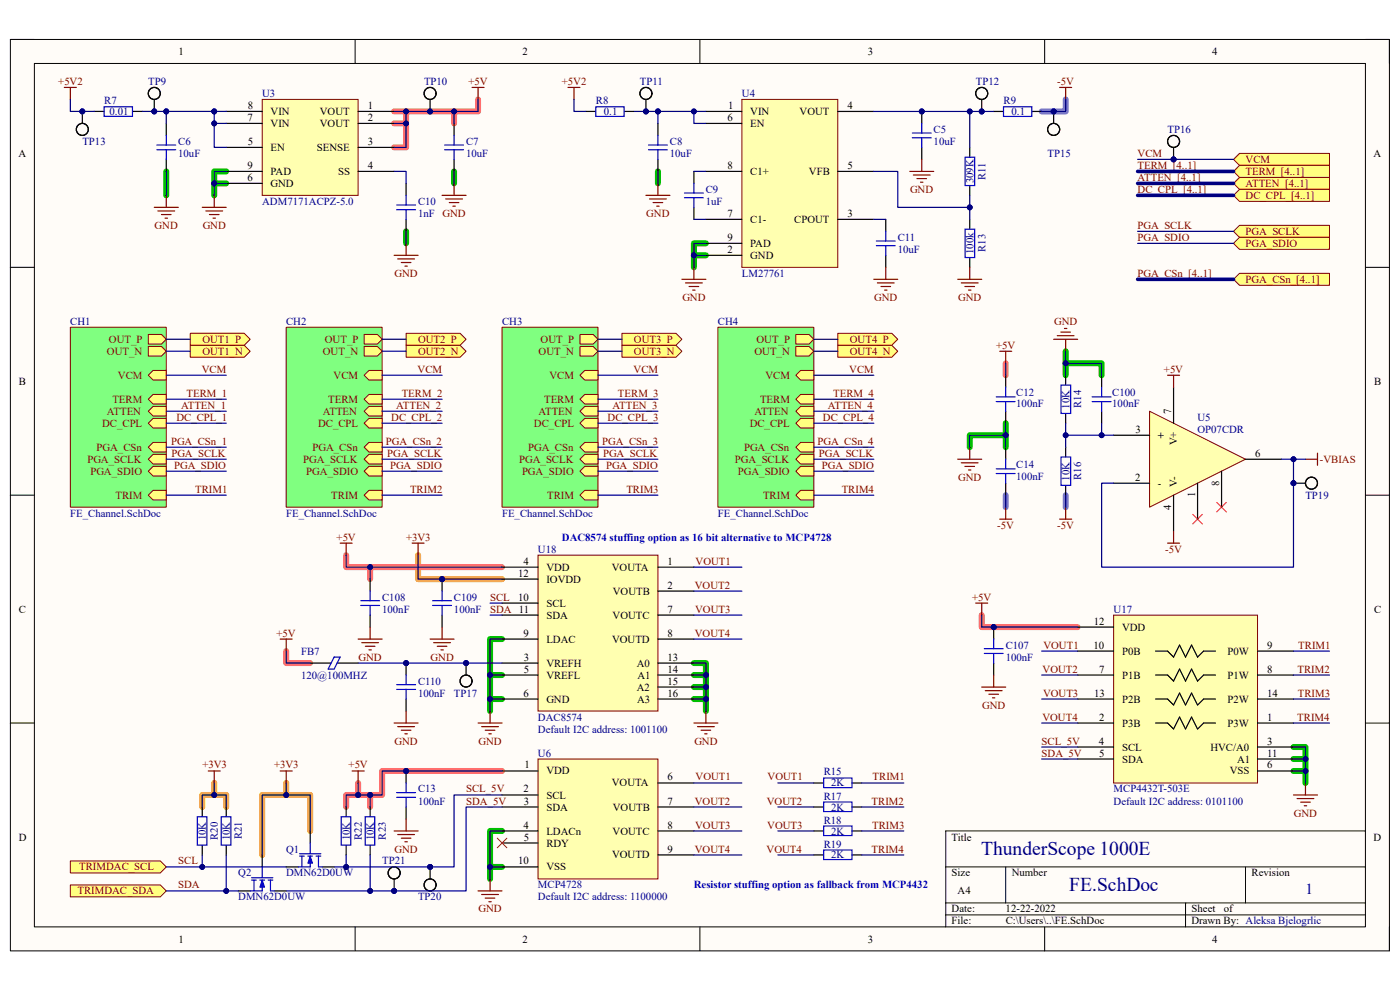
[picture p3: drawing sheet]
<svg xmlns="http://www.w3.org/2000/svg" width="297mm" height="210mm" viewBox="0 0 297 210" stroke-linecap="round" stroke-linejoin="round" font-family="sans-serif">
<defs><g id="words">
<g font-size="4.1" fill="#000080">
<text x="208.2" y="181.5">ThunderScope 1000E</text>
<text x="226.8" y="189.1">FE.SchDoc</text>
</g>
<text font-size="3.2" fill="#000080" x="276.9" y="189.6">1</text>
<g font-size="2.3">
<text x="37.9" y="11.7">1</text>
<text x="110.9" y="11.7">2</text>
<text x="184.1" y="11.7">3</text>
<text x="257.1" y="11.7">4</text>
<text x="52.6" y="23.1">8</text>
<text x="78" y="23.1">1</text>
<text x="154.5" y="23.1">1</text>
<text x="179.8" y="23.1">4</text>
<text x="52.5" y="25.7">7</text>
<text x="57.4" y="24.4">VIN</text>
<text x="57.4" y="26.9">VIN</text>
<text x="67.9" y="24.4">VOUT</text>
<text x="67.9" y="26.9">VOUT</text>
<text x="78" y="25.7">2</text>
<text x="154.3" y="25.7">6</text>
<text x="159.2" y="24.4">VIN</text>
<text x="159.2" y="26.9">EN</text>
<text x="169.6" y="24.4">VOUT</text>
<text x="3.9" y="33.3">A</text>
<text x="52.5" y="35.9">9</text>
<text x="52.6" y="30.7">5</text>
<text x="57.4" y="32">EN</text>
<text x="67.2" y="32">SENSE</text>
<text x="78" y="30.7">3</text>
<text x="78" y="35.9">4</text>
<text x="154.3" y="35.9">8</text>
<text x="179.8" y="35.9">5</text>
<text x="291.4" y="33.3">A</text>
<text x="52.5" y="38.4">6</text>
<text x="57.4" y="39.7">GND</text>
<text x="57.4" y="37.1">PAD</text>
<text x="71.8" y="37.1">SS</text>
<text x="159.2" y="37.1">C1+</text>
<text x="171.6" y="37.1">VFB</text>
<text x="154.3" y="46">7</text>
<text x="159.2" y="47.3">C1-</text>
<text x="168.5" y="47.3">CPOUT</text>
<text x="179.8" y="46">3</text>
<text x="154.3" y="53.6">2</text>
<text x="154.3" y="51.1">9</text>
<text x="159.2" y="52.4">PAD</text>
<text x="159.2" y="54.9">GND</text>
<text x="4" y="81.6">B</text>
<text x="291.5" y="81.6">B</text>
<text x="248.5" y="87.8" transform="rotate(-90 248.5 87.8)">7</text>
<text x="240.9" y="91.8">3</text>
<text x="245.7" y="93.1">+</text>
<text x="249.7" y="94.5" transform="rotate(-90 249.7 94.5)">V+</text>
<text x="240.8" y="102">2</text>
<text x="266.3" y="96.9">6</text>
<text x="245.7" y="103.3">-</text>
<text x="249.7" y="103.3" transform="rotate(-90 249.7 103.3)">V-</text>
<text x="253.6" y="105.4" transform="rotate(-90 253.6 105.4)">1</text>
<text x="258.7" y="103" transform="rotate(-90 258.7 103)">8</text>
<text x="248.5" y="108.2" transform="rotate(-90 248.5 108.2)">4</text>
<text x="111" y="119.8">4</text>
<text x="141.6" y="119.8">1</text>
<text x="109.9" y="122.3">12</text>
<text x="115.9" y="121.1">VDD</text>
<text x="115.9" y="123.6">IOVDD</text>
<text x="129.8" y="121.1">VOUTA</text>
<text x="141.6" y="124.9">2</text>
<text x="4" y="130">C</text>
<text x="109.9" y="127.4">10</text>
<text x="115.9" y="128.7">SCL</text>
<text x="115.9" y="131.2">SDA</text>
<text x="130" y="131.2">VOUTC</text>
<text x="130" y="126.2">VOUTB</text>
<text x="141.6" y="130">7</text>
<text x="291.5" y="130">C</text>
<text x="111" y="135">9</text>
<text x="115.9" y="136.3">LDAC</text>
<text x="129.8" y="136.3">VOUTD</text>
<text x="141.6" y="135">8</text>
<text x="232" y="137.6">10</text>
<text x="232" y="132.5">12</text>
<text x="238" y="133.8">VDD</text>
<text x="268.8" y="137.6">9</text>
<text x="111.1" y="140.1">3</text>
<text x="111.1" y="142.7">5</text>
<text x="115.9" y="141.4">VREFH</text>
<text x="115.9" y="144">VREFL</text>
<text x="135.1" y="141.4">A0</text>
<text x="135.3" y="144">A1</text>
<text x="141.6" y="140.1">13</text>
<text x="141.6" y="142.7">14</text>
<text x="233.2" y="142.7">7</text>
<text x="238" y="138.9">P0B</text>
<text x="238" y="144">P1B</text>
<text x="260.4" y="138.9">P0W</text>
<text x="260.4" y="144">P1W</text>
<text x="268.8" y="142.7">8</text>
<text x="111" y="147.8">6</text>
<text x="115.9" y="149.1">GND</text>
<text x="135.1" y="146.5">A2</text>
<text x="135.2" y="149.1">A3</text>
<text x="141.6" y="145.2">15</text>
<text x="141.6" y="147.8">16</text>
<text x="232.1" y="147.8">13</text>
<text x="238" y="149.1">P2B</text>
<text x="260.4" y="149.1">P2W</text>
<text x="268.8" y="147.8">14</text>
<text x="233.2" y="152.9">2</text>
<text x="238" y="154.1">P3B</text>
<text x="260.4" y="154.1">P3W</text>
<text x="268.8" y="152.9">1</text>
<text x="233.1" y="157.9">4</text>
<text x="233.2" y="160.5">5</text>
<text x="238" y="159.2">SCL</text>
<text x="238" y="161.8">SDA</text>
<text x="256.8" y="159.2">HVC/A0</text>
<text x="262.5" y="161.8">A1</text>
<text x="268.8" y="157.9">3</text>
<text x="268.8" y="160.5">11</text>
<text x="111.3" y="163">1</text>
<text x="115.9" y="164.3">VDD</text>
<text x="129.8" y="166.8">VOUTA</text>
<text x="141.6" y="165.6">6</text>
<text x="260.9" y="164.3">VSS</text>
<text x="268.8" y="163">6</text>
<text x="111" y="168.1">2</text>
<text x="111.1" y="170.7">3</text>
<text x="115.9" y="169.4">SCL</text>
<text x="115.9" y="172">SDA</text>
<text x="130" y="172">VOUTB</text>
<text x="141.6" y="170.7">7</text>
<text x="4" y="178.3">D</text>
<text x="111" y="175.8">4</text>
<text x="111.1" y="178.3">5</text>
<text x="115.9" y="177">LDACn</text>
<text x="115.9" y="179.6">RDY</text>
<text x="130" y="177">VOUTC</text>
<text x="141.6" y="175.8">8</text>
<text x="201.9" y="178.3">Title</text>
<text x="291.4" y="178.3">D</text>
<text x="109.9" y="183.4">10</text>
<text x="115.9" y="184.7">VSS</text>
<text x="129.8" y="182.1">VOUTD</text>
<text x="141.6" y="180.8">9</text>
<text x="201.9" y="185.9">Size</text>
<text x="214.6" y="185.9">Number</text>
<text x="265.5" y="185.9">Revision</text>
<text x="203.2" y="189.7">A4</text>
<text x="201.9" y="193.5">Date:</text>
<text x="201.9" y="196.1">File:</text>
<text x="213.3" y="193.5">12-22-2022</text>
<text x="213.4" y="196.1">C:\Users\..\FE.SchDoc</text>
<text x="252.8" y="196.1">Drawn By: Aleksa Bjelogrlic</text>
<text x="252.8" y="193.5">Sheet</text>
<text x="259.6" y="193.5">of</text>
<text x="37.9" y="199.9">1</text>
<text x="110.9" y="199.9">2</text>
<text x="184.1" y="199.9">3</text>
<text x="257.1" y="199.9">4</text>
</g>
<g font-size="2.3" fill="#800000">
<text x="12.4" y="18">+5V2</text>
<text x="99.4" y="18">+5V</text>
<text x="119.2" y="18">+5V2</text>
<text x="224.3" y="18">-5V</text>
<text x="241.3" y="33.3">VCM</text>
<text x="241.3" y="35.9">TERM_[4..1]</text>
<text x="264.2" y="34.6">VCM</text>
<text x="193.1" y="40.9">GND</text>
<text x="241.3" y="38.4">ATTEN_[4..1]</text>
<text x="241.3" y="40.9">DC_CPL_[4..1]</text>
<text x="264.2" y="39.7">ATTEN_[4..1]</text>
<text x="264.2" y="37.1">TERM_[4..1]</text>
<text x="93.9" y="46">GND</text>
<text x="137.1" y="46">GND</text>
<text x="264.2" y="42.2">DC_CPL_[4..1]</text>
<text x="32.8" y="48.6">GND</text>
<text x="43" y="48.6">GND</text>
<text x="241.3" y="48.6">PGA_SCLK</text>
<text x="241.3" y="51.1">PGA_SDIO</text>
<text x="264.2" y="49.8">PGA_SCLK</text>
<text x="264.2" y="52.4">PGA_SDIO</text>
<text x="83.7" y="58.7">GND</text>
<text x="241.3" y="58.7">PGA_CSn_[4..1]</text>
<text x="264.2" y="60">PGA_CSn_[4..1]</text>
<text x="144.8" y="63.8">GND</text>
<text x="185.5" y="63.8">GND</text>
<text x="203.3" y="63.8">GND</text>
<text x="223.6" y="68.9">GND</text>
<text x="22.7" y="75.3">OUT_N</text>
<text x="23.1" y="72.7">OUT_P</text>
<text x="42.9" y="75.3">OUT1_N</text>
<text x="42.9" y="72.7">OUT1_P</text>
<text x="68.5" y="75.3">OUT_N</text>
<text x="68.9" y="72.7">OUT_P</text>
<text x="88.7" y="75.3">OUT2_N</text>
<text x="88.7" y="72.7">OUT2_P</text>
<text x="114.3" y="75.3">OUT_N</text>
<text x="114.7" y="72.7">OUT_P</text>
<text x="134.5" y="75.3">OUT3_N</text>
<text x="134.5" y="72.7">OUT3_P</text>
<text x="160.1" y="75.3">OUT_N</text>
<text x="160.5" y="72.7">OUT_P</text>
<text x="180.3" y="75.3">OUT4_N</text>
<text x="180.3" y="72.7">OUT4_P</text>
<text x="211.3" y="74">+5V</text>
<text x="25" y="80.3">VCM</text>
<text x="42.8" y="79.1">VCM</text>
<text x="70.8" y="80.3">VCM</text>
<text x="88.6" y="79.1">VCM</text>
<text x="116.6" y="80.3">VCM</text>
<text x="134.4" y="79.1">VCM</text>
<text x="162.4" y="80.3">VCM</text>
<text x="180.2" y="79.1">VCM</text>
<text x="246.9" y="79.1">+5V</text>
<text x="22.7" y="88">ATTEN</text>
<text x="23.8" y="85.4">TERM</text>
<text x="37.4" y="89.3">DC_CPL_1</text>
<text x="38.4" y="86.7">ATTEN_1</text>
<text x="39.6" y="84.2">TERM_1</text>
<text x="68.5" y="88">ATTEN</text>
<text x="69.6" y="85.4">TERM</text>
<text x="83" y="89.3">DC_CPL_2</text>
<text x="84.1" y="86.7">ATTEN_2</text>
<text x="85.2" y="84.2">TERM_2</text>
<text x="114.3" y="88">ATTEN</text>
<text x="115.4" y="85.4">TERM</text>
<text x="128.9" y="89.3">DC_CPL_3</text>
<text x="130" y="86.7">ATTEN_3</text>
<text x="131.1" y="84.2">TERM_3</text>
<text x="160.1" y="88">ATTEN</text>
<text x="161.2" y="85.4">TERM</text>
<text x="174.6" y="89.3">DC_CPL_4</text>
<text x="175.6" y="86.7">ATTEN_4</text>
<text x="176.8" y="84.2">TERM_4</text>
<text x="20.5" y="95.6">PGA_CSn</text>
<text x="21.7" y="90.6">DC_CPL</text>
<text x="36.3" y="94.4">PGA_CSn_1</text>
<text x="66.3" y="95.6">PGA_CSn</text>
<text x="67.5" y="90.6">DC_CPL</text>
<text x="81.9" y="94.4">PGA_CSn_2</text>
<text x="112.1" y="95.6">PGA_CSn</text>
<text x="113.3" y="90.6">DC_CPL</text>
<text x="127.8" y="94.4">PGA_CSn_3</text>
<text x="157.9" y="95.6">PGA_CSn</text>
<text x="159" y="90.6">DC_CPL</text>
<text x="173.4" y="94.4">PGA_CSn_4</text>
<text x="18.5" y="98.2">PGA_SCLK</text>
<text x="19.2" y="100.7">PGA_SDIO</text>
<text x="36.4" y="96.9">PGA_SCLK</text>
<text x="37" y="99.4">PGA_SDIO</text>
<text x="64.3" y="98.2">PGA_SCLK</text>
<text x="65" y="100.7">PGA_SDIO</text>
<text x="82.2" y="96.9">PGA_SCLK</text>
<text x="82.8" y="99.4">PGA_SDIO</text>
<text x="110.2" y="98.2">PGA_SCLK</text>
<text x="110.7" y="100.7">PGA_SDIO</text>
<text x="127.9" y="96.9">PGA_SCLK</text>
<text x="128.6" y="99.4">PGA_SDIO</text>
<text x="155.9" y="98.2">PGA_SCLK</text>
<text x="156.5" y="100.7">PGA_SDIO</text>
<text x="173.7" y="96.9">PGA_SCLK</text>
<text x="174.4" y="99.4">PGA_SDIO</text>
<text x="203.3" y="102">GND</text>
<text x="280" y="98.2">-VBIAS</text>
<text x="24.5" y="105.8">TRIM</text>
<text x="41.4" y="104.5">TRIM1</text>
<text x="70.3" y="105.8">TRIM</text>
<text x="87" y="104.5">TRIM2</text>
<text x="116.1" y="105.8">TRIM</text>
<text x="132.9" y="104.5">TRIM3</text>
<text x="161.9" y="105.8">TRIM</text>
<text x="178.6" y="104.5">TRIM4</text>
<text x="211.6" y="112.1">-5V</text>
<text x="224.3" y="112.1">-5V</text>
<text x="71.4" y="114.7">+5V</text>
<text x="86.1" y="114.7">+3V3</text>
<text x="147.6" y="119.8">VOUT1</text>
<text x="247.2" y="117.3">-5V</text>
<text x="147.4" y="124.9">VOUT2</text>
<text x="104" y="127.4">SCL</text>
<text x="104" y="130">SDA 11</text>
<text x="147.5" y="130">VOUT3</text>
<text x="206.2" y="127.4">+5V</text>
<text x="58.7" y="135">+5V</text>
<text x="147.4" y="135">VOUT4</text>
<text x="221.4" y="137.6">VOUT1</text>
<text x="275.4" y="137.6">TRIM1</text>
<text x="76.1" y="140.1">GND</text>
<text x="91.4" y="140.1">GND</text>
<text x="221.2" y="142.7">VOUT2</text>
<text x="275.3" y="142.7">TRIM2</text>
<text x="221.3" y="147.8">VOUT3</text>
<text x="275.3" y="147.8">TRIM3</text>
<text x="208.4" y="150.3">GND</text>
<text x="221.1" y="152.9">VOUT4</text>
<text x="275.2" y="152.9">TRIM4</text>
<text x="83.7" y="157.9">GND</text>
<text x="101.5" y="157.9">GND</text>
<text x="147.3" y="157.9">GND</text>
<text x="221" y="157.9">SCL_5V</text>
<text x="221" y="160.5">SDA_5V</text>
<text x="42.9" y="163">+3V3</text>
<text x="58.2" y="163">+3V3</text>
<text x="74" y="163">+5V</text>
<text x="147.6" y="165.6">VOUT1</text>
<text x="162.9" y="165.6">VOUT1</text>
<text x="185.1" y="165.6">TRIM1</text>
<text x="98.9" y="168.1">SCL_5V</text>
<text x="98.9" y="170.7">SDA_5V</text>
<text x="147.4" y="170.7">VOUT2</text>
<text x="162.7" y="170.7">VOUT2</text>
<text x="184.9" y="170.7">TRIM2</text>
<text x="274.5" y="173.2">GND</text>
<text x="147.5" y="175.8">VOUT3</text>
<text x="162.8" y="175.8">VOUT3</text>
<text x="185" y="175.8">TRIM3</text>
<text x="16.8" y="184.7">TRIMDAC_SCL</text>
<text x="37.8" y="183.4">SCL</text>
<text x="83.7" y="180.8">GND</text>
<text x="147.4" y="180.8">VOUT4</text>
<text x="162.6" y="180.8">VOUT4</text>
<text x="184.9" y="180.8">TRIM4</text>
<text x="16.4" y="189.7">TRIMDAC_SDA</text>
<text x="37.8" y="188.5">SDA</text>
<text x="101.5" y="193.5">GND</text>
</g>
<g font-size="2.3" fill="#000080">
<text x="22.1" y="22.1">R7</text>
<text x="31.5" y="18">TP9</text>
<text x="55.6" y="20.6">U3</text>
<text x="90" y="18">TP10</text>
<text x="126.4" y="22.1">R8</text>
<text x="135.8" y="18">TP11</text>
<text x="157.4" y="20.6">U4</text>
<text x="207" y="18">TP12</text>
<text x="212.9" y="22.1">R9</text>
<text x="23.2" y="24.4">0.01</text>
<text x="128.1" y="24.4">0.1</text>
<text x="198.1" y="28.2">C5</text>
<text x="214.6" y="24.4">0.1</text>
<text x="247.7" y="28.2">TP16</text>
<text x="17.5" y="30.7">TP13</text>
<text x="37.8" y="30.7">C6</text>
<text x="37.8" y="33.3">10uF</text>
<text x="98.9" y="30.7">C7</text>
<text x="98.9" y="33.3">10uF</text>
<text x="142.1" y="30.7">C8</text>
<text x="142.1" y="33.3">10uF</text>
<text x="198.1" y="30.7">10uF</text>
<text x="222.2" y="33.3">TP15</text>
<text x="149.7" y="40.9">C9</text>
<text x="206.5" y="38.9" transform="rotate(-90 206.5 38.9)">309K</text>
<text x="209" y="38.1" transform="rotate(-90 209 38.1)">R11</text>
<text x="55.6" y="43.5">ADM7171ACPZ-5.0</text>
<text x="88.7" y="43.5">C10</text>
<text x="88.7" y="46">1nF</text>
<text x="149.7" y="43.5">1uF</text>
<text x="190.5" y="51.1">C11</text>
<text x="190.5" y="53.6">10uF</text>
<text x="206.5" y="53.9" transform="rotate(-90 206.5 53.9)">100k</text>
<text x="209" y="53.4" transform="rotate(-90 209 53.4)">R13</text>
<text x="157.4" y="58.7">LM27761</text>
<text x="14.9" y="68.9">CH1</text>
<text x="60.7" y="68.9">CH2</text>
<text x="106.5" y="68.9">CH3</text>
<text x="152.3" y="68.9">CH4</text>
<text x="215.6" y="83.9">C12</text>
<text x="236" y="83.9">C100</text>
<text x="215.6" y="86.4">100nF</text>
<text x="226.9" y="86.7" transform="rotate(-90 226.9 86.7)">10K</text>
<text x="229.4" y="86.6" transform="rotate(-90 229.4 86.6)">R14</text>
<text x="236" y="86.4">100nF</text>
<text x="254" y="89.3">U5</text>
<text x="254" y="91.8">OP07CDR</text>
<text x="215.6" y="99.2">C14</text>
<text x="215.6" y="101.7">100nF</text>
<text x="226.9" y="101.9" transform="rotate(-90 226.9 101.9)">10K</text>
<text x="229.4" y="101.8" transform="rotate(-90 229.4 101.8)">R16</text>
<text x="276.9" y="105.8">TP19</text>
<text x="14.9" y="109.6">FE_Channel.SchDoc</text>
<text x="60.7" y="109.6">FE_Channel.SchDoc</text>
<text x="106.5" y="109.6">FE_Channel.SchDoc</text>
<text x="152.3" y="109.6">FE_Channel.SchDoc</text>
<text x="114.1" y="117.3">U18</text>
<text x="81.1" y="127.4">C108</text>
<text x="81.1" y="130">100nF</text>
<text x="96.3" y="127.4">C109</text>
<text x="96.3" y="130">100nF</text>
<text x="236.3" y="130">U17</text>
<text x="213.4" y="137.6">C107</text>
<text x="63.9" y="138.9">FB7</text>
<text x="63.9" y="144">120@100MHZ</text>
<text x="213.4" y="140.1">100nF</text>
<text x="88.7" y="145.2">C110</text>
<text x="88.7" y="147.8">100nF</text>
<text x="96.3" y="147.8">TP17</text>
<text x="114.1" y="152.9">DAC8574</text>
<text x="114.1" y="155.4">Default I2C address: 1001100</text>
<text x="114.1" y="160.5">U6</text>
<text x="174.8" y="164.5">R15</text>
<text x="176.3" y="166.8">2K</text>
<text x="88.7" y="168.1">C13</text>
<text x="88.7" y="170.7">100nF</text>
<text x="174.8" y="169.6">R17</text>
<text x="176.3" y="172">2K</text>
<text x="236.3" y="168.1">MCP4432T-503E</text>
<text x="236.3" y="170.7">Default I2C address: 0101100</text>
<text x="43.7" y="178.3" transform="rotate(-90 43.7 178.3)">10K</text>
<text x="46.2" y="178.1" transform="rotate(-90 46.2 178.1)">R20</text>
<text x="48.8" y="178.3" transform="rotate(-90 48.8 178.3)">10K</text>
<text x="51.3" y="178.1" transform="rotate(-90 51.3 178.1)">R21</text>
<text x="74.2" y="178.3" transform="rotate(-90 74.2 178.3)">10K</text>
<text x="76.8" y="178.1" transform="rotate(-90 76.8 178.1)">R22</text>
<text x="79.3" y="178.3" transform="rotate(-90 79.3 178.3)">10K</text>
<text x="81.8" y="178.1" transform="rotate(-90 81.8 178.1)">R23</text>
<text x="174.8" y="174.7">R18</text>
<text x="174.8" y="179.8">R19</text>
<text x="176.3" y="177">2K</text>
<text x="50.5" y="185.9">Q2</text>
<text x="60.7" y="180.8">Q1</text>
<text x="60.7" y="185.9">DMN62D0UW</text>
<text x="81.1" y="183.4">TP21</text>
<text x="176.3" y="182.1">2K</text>
<text x="50.5" y="191">DMN62D0UW</text>
<text x="88.7" y="191">TP20</text>
<text x="114.1" y="188.5">MCP4728</text>
<text x="114.1" y="191">Default I2C address: 1100000</text>
</g>
<g font-size="2.3" fill="#00f">
<text x="119.2" y="114.7">DAC8574 stuffing option as 16 bit alternative to MCP4728</text>
<text x="147.2" y="188.5">Resistor stuffing option as fallback from MCP4432</text>
</g>
</g></defs>
<path d="M2.2 8.4h292.6v193.3h-292.6z" fill-rule="evenodd" fill="#fffcf8"/>
<path d="M2.2 8.4h292.6v193.3h-292.6z" fill="none" stroke="#000" stroke-width=".21"/>
<path d="M7.3 13.5h282.4v183.1h-282.4z" fill-rule="evenodd" fill="#fffcf8"/>
<g fill="none" stroke="#000" stroke-width=".21">
<path d="M2.2 8.4h5.1M7.3 13.5h282.4v183.1h-282.4zM75.3 8.4v5.1M148.5 8.4v5.1M221.6 8.4v5.1M289.7 8.4h5.1v5.1M2.2 56.7h5.1M289.7 56.7h5.1M2.2 105h5.1M289.7 105.1h5.1M2.2 153.4h5.1M289.7 153.4h5.1"/>
<path d="M289.7 176.3h-89.1v20.3M75.3 196.6v5.1M148.5 196.6v5.1M200.6 183.9h89.1M200.6 191.5h89.1M200.6 194.1h89.1M213.4 183.9v7.6M221.6 196.6v5.1M251.5 191.5v5.1M264.2 183.9v7.6M294.8 196.6v5.1"/>
</g>
<g fill="none" stroke="#00be00" stroke-width="1.3">
<path d="M35.3 36.4v5M45.5 38.9h2.5M48 36.4h-2.5v5M96.3 36.4v2.5M139.6 36.4v2.5M86.2 49.1v2.5M147.2 54.2v2.5M149.8 51.6h-2.6v2.6h2.6M226.1 74.5v5.1M226.1 77.1h7.6v2.5M213.4 92.3h-7.7v2.6M213.4 89.8v5.1"/>
<path d="M106.5 135.6h-2.5v12.7M104 143.2h2.5M106.5 148.3h-2.5v2.5M147.2 140.7h2.6v10.1M147.2 143.2h2.6M147.2 145.7h2.6M147.2 148.3h2.6M274.4 158.5h2.6v5.1M106.5 176.3h-2.5v7.6M274.4 163.6h2.6v2.5M274.4 161h2.6M106.5 183.9h-2.5v2.6"/>
</g>
<path d="M88.7 117.8v5.1h17.8M45.5 168.6h-2.6v2.6M45.5 166.1v2.5h2.5v2.6M60.7 166.1v2.5M65.8 176.3v-7.7h-10.2v12.8" fill="none" stroke="#f90" stroke-width="1.3"/>
<path d="M83.6 23.6h2.6v2.6h-2.6M86.2 23.6h10.1v2.6M86.2 26.2v5.1h-2.6M101.4 21.1v2.5h-5.1M213.4 77.1v2.5M73.4 117.8v2.5h5.1M60.7 138.1v2.6h5.1M106.5 120.3h-28v2.6M208.3 130.5v2.5h20.3M76 168.6h-2.6v2.6M76 166.1v2.5h2.5v2.6M106.5 163.6h-25.4v5h-2.6" fill="none" stroke="#ff6e6e" stroke-width="1.3"/>
<path d="M226.1 21.1v2.5h-5.1M213.4 105.1v2.5M226.1 105.1v2.5" fill="none" stroke="#6e6eff" stroke-width="1.3"/>
<path d="M14.9 69.4h20.4v38.2h-20.4z" fill-rule="evenodd" fill="#80ff80"/>
<path d="M14.9 69.4h20.4v38.2h-20.4z" fill="none" stroke="#800000" stroke-width=".21"/>
<path d="M31.5 71h2.8l1 1-1 1h-2.8z" fill-rule="evenodd" fill="#ffff80"/>
<path d="M31.5 71h2.8l1 1-1 1h-2.8z" fill="none" stroke="#800000" stroke-width=".21"/>
<path d="M31.5 79.6l1-1h2.8v2h-2.8z" fill-rule="evenodd" fill="#ffff80"/>
<path d="M31.5 79.6l1-1h2.8v2h-2.8z" fill="none" stroke="#800000" stroke-width=".21"/>
<path d="M31.5 73.5h2.8l1 1-1 1h-2.8z" fill-rule="evenodd" fill="#ffff80"/>
<path d="M31.5 73.5h2.8l1 1-1 1h-2.8z" fill="none" stroke="#800000" stroke-width=".21"/>
<path d="M31.5 105l1-1h2.8v2.1h-2.8z" fill-rule="evenodd" fill="#ffff80"/>
<path d="M31.5 105l1-1h2.8v2.1h-2.8z" fill="none" stroke="#800000" stroke-width=".21"/>
<path d="M32.5 86.2h2.8v2.1h-2.8l-1-1.1z" fill-rule="evenodd" fill="#ffff80"/>
<path d="M32.5 86.2h2.8v2.1h-2.8l-1-1.1z" fill="none" stroke="#800000" stroke-width=".21"/>
<path d="M31.5 89.8l1-1h2.8v2h-2.8z" fill-rule="evenodd" fill="#ffff80"/>
<path d="M31.5 89.8l1-1h2.8v2h-2.8z" fill="none" stroke="#800000" stroke-width=".21"/>
<path d="M31.5 94.9l1-1h2.8v2h-2.8z" fill-rule="evenodd" fill="#ffff80"/>
<path d="M31.5 94.9l1-1h2.8v2h-2.8z" fill="none" stroke="#800000" stroke-width=".21"/>
<path d="M32.5 96.4h2.8v2h-2.8l-1-1z" fill-rule="evenodd" fill="#ffff80"/>
<path d="M32.5 96.4h2.8v2h-2.8l-1-1z" fill="none" stroke="#800000" stroke-width=".21"/>
<path d="M32.5 98.9h2.8v2.1h-2.8l-1-1z" fill-rule="evenodd" fill="#ffff80"/>
<path d="M32.5 98.9h2.8v2.1h-2.8l-1-1z" fill="none" stroke="#800000" stroke-width=".21"/>
<path d="M31.5 84.7l1-1h2.8v2h-2.8z" fill-rule="evenodd" fill="#ffff80"/>
<path d="M31.5 84.7l1-1h2.8v2h-2.8z" fill="none" stroke="#800000" stroke-width=".21"/>
<circle cx="86.2" cy="163.6" r=".51" fill="#000080"/>
<circle cx="86.2" cy="163.6" r=".51" fill="none" stroke="#000080" stroke-width=".21"/>
<path d="M86.2 163.6v2.5M86.2 171.2v2.5" fill="none" stroke="#000" stroke-width=".25"/>
<circle cx="86.2" cy="163.6" r=".51" fill="#000080"/>
<circle cx="86.2" cy="163.6" r=".51" fill="none" stroke="#000080" stroke-width=".21"/>
<path d="M65.8 178.8v2.3M84.2 169.1h4M84.2 168.1h4M86.2 166.1v2M86.2 169.1v2.1M63.6 181.1h4.5M63.6 181.6h1M64.1 181.6v2.3M65.3 181.6h1M65.8 181.6v2.3h-2.5M67.1 181.6h1M67.6 181.6v2.3" fill="none" stroke="#00f" stroke-width=".25"/>
<path d="M83.6 176.3h5.1M84.4 177h3.5M85.1 177.8h2.1M85.9 178.6h.5M86.2 173.7v2.6M101.4 189h5.1M102.2 189.8h3.5M102.9 190.5h2.1M103.7 191.3h.5M104 186.5v2.5" fill="none" stroke="#800000" stroke-width=".25"/>
<path d="M65.8 176.3v2.5M60.7 183.9h2.6M68.3 183.9h2.6" fill="none" stroke="#000" stroke-width=".25"/>
<path d="M65.8 181.6l.5 1.5h-1z" fill="#00f"/>
<path d="M65.8 181.6l.5 1.5h-1z" fill="none" stroke="#00f" stroke-width=".21"/>
<path d="M53.4 186.2h4.5M53.4 186.7h1M53.9 186.7v2.3M55.1 186.7h1M55.6 183.9v2.3M55.6 186.7v2.3h-2.5M56.9 186.7h1M57.4 186.7v2.3M67.6 183.9h.7" fill="none" stroke="#00f" stroke-width=".25"/>
<path d="M50.5 189h2.6M55.6 181.4v2.5M58.2 189h2.5" fill="none" stroke="#000" stroke-width=".25"/>
<path d="M55.6 186.7l.5 1.5h-1z" fill="#00f"/>
<path d="M55.6 186.7l.5 1.5h-1z" fill="none" stroke="#00f" stroke-width=".21"/>
<path d="M41.9 173.3h2v6h-2zM46.9 173.3h2.1v6h-2.1zM72.4 173.3h2v6h-2zM77.5 173.3h2v6h-2zM57.4 189h.8" fill="none" stroke="#00f" stroke-width=".25"/>
<path d="M42.9 171.2v2M42.9 179.4v2M48 171.2v2M48 179.4v2M73.4 171.2v2M73.4 179.4v2M78.5 171.2v2M78.5 179.4v2" fill="none" stroke="#000" stroke-width=".25"/>
<path d="M44.2 163.6h2.5M45.5 163.6v2.5M59.4 163.6h2.6M60.7 163.6v2.5" fill="none" stroke="#800000" stroke-width=".25"/>
<path d="M14.9 182.6h19.1l1.3 1.3-1.3 1.3h-19.1z" fill-rule="evenodd" fill="#ffff80"/>
<path d="M14.9 182.6h19.1l1.3 1.3-1.3 1.3h-19.1z" fill="none" stroke="#800000" stroke-width=".21"/>
<path d="M14.9 187.7h19.1l1.3 1.3-1.3 1.3h-19.1z" fill-rule="evenodd" fill="#ffff80"/>
<path d="M14.9 187.7h19.1l1.3 1.3-1.3 1.3h-19.1z" fill="none" stroke="#800000" stroke-width=".21"/>
<path d="M243.9 87.2l20.3 10.2-20.3 10.2z" fill="#ffffb0"/>
<path d="M243.9 87.2l20.3 10.2-20.3 10.2z" fill="none" stroke="#800000" stroke-width=".21"/>
<path d="M226.1 79.6v2M226.1 87.8v2M226.1 94.9v2M236.3 92.3h7.6M249 82.1v7.7M259.2 100v7.6M264.2 97.4h7.7M226.1 103v2.1M236.3 102.5h7.6M249 105.1v7.6M254.1 102.5v7.6" fill="none" stroke="#000" stroke-width=".25"/>
<path d="M253 109.1l2.1 2.1M255.1 109.1l-2.1 2.1M258.1 106.6l2.1 2M260.2 106.6l-2.1 2" fill="none" stroke="#f00" stroke-width=".21"/>
<path d="M225.1 81.7h2v6h-2zM225.1 97h2v6h-2z" fill="none" stroke="#00f" stroke-width=".25"/>
<path d="M277 97.4h2.5M279.5 96.1v2.6" fill="none" stroke="#800000" stroke-width=".25"/>
<path d="M114.1 161h25.5v25.5h-25.5z" fill-rule="evenodd" fill="#ffffb0"/>
<path d="M114.1 161h25.5v25.5h-25.5z" fill="none" stroke="#800000" stroke-width=".21"/>
<path d="M106.5 163.6h7.6M106.5 168.6h7.6M106.5 171.2h7.6M106.5 176.3h7.6M106.5 178.8h7.6M139.6 171.2h7.6M139.6 166.1h7.6M139.6 176.3h7.6M106.5 183.9h7.6M139.6 181.4h7.6" fill="none" stroke="#000" stroke-width=".25"/>
<path d="M105.5 177.8l2 2M107.5 177.8l-2 2" fill="none" stroke="#f00" stroke-width=".21"/>
<path d="M261.7 38.9l1.3-1.3h19v2.6h-19z" fill-rule="evenodd" fill="#ffff80"/>
<path d="M261.7 38.9l1.3-1.3h19v2.6h-19z" fill="none" stroke="#800000" stroke-width=".21"/>
<path d="M263 40.2h19v2.5h-19l-1.3-1.3z" fill-rule="evenodd" fill="#ffff80"/>
<path d="M263 40.2h19v2.5h-19l-1.3-1.3z" fill="none" stroke="#800000" stroke-width=".21"/>
<path d="M263 47.8h19v2.6h-19l-1.3-1.3z" fill-rule="evenodd" fill="#ffff80"/>
<path d="M263 47.8h19v2.6h-19l-1.3-1.3z" fill="none" stroke="#800000" stroke-width=".21"/>
<path d="M261.7 51.6l1.3-1.2h19v2.5h-19z" fill-rule="evenodd" fill="#ffff80"/>
<path d="M261.7 51.6l1.3-1.2h19v2.5h-19z" fill="none" stroke="#800000" stroke-width=".21"/>
<path d="M263 58h19v2.5h-19l-1.3-1.2z" fill-rule="evenodd" fill="#ffff80"/>
<path d="M263 58h19v2.5h-19l-1.3-1.2z" fill="none" stroke="#800000" stroke-width=".21"/>
<path d="M263 32.5h19v2.6h-19l-1.3-1.3z" fill-rule="evenodd" fill="#ffff80"/>
<path d="M263 32.5h19v2.6h-19l-1.3-1.3z" fill="none" stroke="#800000" stroke-width=".21"/>
<path d="M40.4 73.2h11.4l1.3 1.3-1.3 1.3h-11.4z" fill-rule="evenodd" fill="#ffff80"/>
<path d="M40.4 73.2h11.4l1.3 1.3-1.3 1.3h-11.4z" fill="none" stroke="#800000" stroke-width=".21"/>
<path d="M40.4 70.7h11.4l1.3 1.3-1.3 1.2h-11.4z" fill-rule="evenodd" fill="#ffff80"/>
<path d="M40.4 70.7h11.4l1.3 1.3-1.3 1.2h-11.4z" fill="none" stroke="#800000" stroke-width=".21"/>
<path d="M86.2 73.2h11.4l1.3 1.3-1.3 1.3h-11.4z" fill-rule="evenodd" fill="#ffff80"/>
<path d="M86.2 73.2h11.4l1.3 1.3-1.3 1.3h-11.4z" fill="none" stroke="#800000" stroke-width=".21"/>
<path d="M86.2 70.7h11.4l1.3 1.3-1.3 1.2h-11.4z" fill-rule="evenodd" fill="#ffff80"/>
<path d="M86.2 70.7h11.4l1.3 1.3-1.3 1.2h-11.4z" fill="none" stroke="#800000" stroke-width=".21"/>
<path d="M131.9 73.2h11.5l1.3 1.3-1.3 1.3h-11.5z" fill-rule="evenodd" fill="#ffff80"/>
<path d="M131.9 73.2h11.5l1.3 1.3-1.3 1.3h-11.5z" fill="none" stroke="#800000" stroke-width=".21"/>
<path d="M131.9 70.7h11.5l1.3 1.3-1.3 1.2h-11.5z" fill-rule="evenodd" fill="#ffff80"/>
<path d="M131.9 70.7h11.5l1.3 1.3-1.3 1.2h-11.5z" fill="none" stroke="#800000" stroke-width=".21"/>
<path d="M177.7 73.2h11.5l1.3 1.3-1.3 1.3h-11.5z" fill-rule="evenodd" fill="#ffff80"/>
<path d="M177.7 73.2h11.5l1.3 1.3-1.3 1.3h-11.5z" fill="none" stroke="#800000" stroke-width=".21"/>
<path d="M177.7 70.7h11.5l1.3 1.3-1.3 1.2h-11.5z" fill-rule="evenodd" fill="#ffff80"/>
<path d="M177.7 70.7h11.5l1.3 1.3-1.3 1.2h-11.5z" fill="none" stroke="#800000" stroke-width=".21"/>
<path d="M157.4 21.1h20.3v35.6h-20.3z" fill-rule="evenodd" fill="#ffffb0"/>
<path d="M157.4 21.1h20.3v35.6h-20.3z" fill="none" stroke="#800000" stroke-width=".21"/>
<g fill="none" stroke="#000" stroke-width=".25">
<path d="M139.6 26.2v2.5M139.6 33.8v2.6M147.2 36.4v2.5M149.8 23.6h7.6M149.8 36.4h7.6M149.8 26.2h7.6M177.7 23.6h7.7M177.7 36.4h7.7M205.7 31.3v2M205.7 39.4v2M147.2 44v2.5M149.8 54.2h7.6"/>
<path d="M149.8 46.5h7.6M149.8 51.6h7.6M177.7 46.5h7.7M187.9 46.5v2.6M187.9 54.2v2.5M205.7 46.5v2M205.7 54.7v2"/>
</g>
<g fill="none" stroke="#00f" stroke-width=".25">
<path d="M137.6 31.8h4M137.6 30.8h4M139.6 28.7v2.1M139.6 31.8v2M147.2 38.9v2M204.7 33.4h2.1v6h-2.1zM145.2 41.9h4M145.2 40.9h4M147.2 41.9v2.1M185.9 52.1h4M185.9 51.1h4M187.9 49.1v2"/>
<path d="M187.9 52.1v2.1M204.7 48.6h2.1v6h-2.1z"/>
</g>
<g fill="none" stroke="#800000" stroke-width=".25">
<path d="M120.5 18.5h2.5M121.8 18.5v2.6M139.6 38.9v2.5M137 41.4h5.1M137.8 42.2h3.6M138.6 43h2M139.3 43.7h.5M144.7 59.3h5.1M147.2 56.7v2.6M185.4 59.3h5.1M187.9 56.7v2.6M203.2 59.3h5.1"/>
<path d="M205.7 56.7v2.6M145.4 60h3.6M146.2 60.8h2M147 61.5h.5M186.1 60h3.6M186.9 60.8h2M187.7 61.5h.5M203.9 60h3.6M204.7 60.8h2M205.5 61.5h.5"/>
</g>
<circle cx="195.5" cy="23.6" r=".51" fill="#000080"/>
<circle cx="195.5" cy="23.6" r=".51" fill="none" stroke="#000080" stroke-width=".21"/>
<path d="M195.5 23.6v2.6M195.5 31.3v2.5" fill="none" stroke="#000" stroke-width=".25"/>
<circle cx="195.5" cy="23.6" r=".51" fill="#000080"/>
<circle cx="195.5" cy="23.6" r=".51" fill="none" stroke="#000080" stroke-width=".21"/>
<path d="M193.5 29.2h4M193.5 28.2h4M195.5 26.2v2M195.5 29.2v2.1M212.9 22.7h6v2h-6z" fill="none" stroke="#00f" stroke-width=".25"/>
<path d="M224.8 18.6h2.6M226.1 18.6v2.5M193 36.4h5.1M193.8 37.1h3.5M194.5 37.9h2.1M195.3 38.7h.5M195.5 33.8v2.6" fill="none" stroke="#800000" stroke-width=".25"/>
<path d="M210.8 23.6h2M219 23.6h2" fill="none" stroke="#000" stroke-width=".25"/>
<path d="M55.6 21.1h20.4v20.3h-20.4z" fill-rule="evenodd" fill="#ffffb0"/>
<path d="M55.6 21.1h20.4v20.3h-20.4z" fill="none" stroke="#800000" stroke-width=".21"/>
<g fill="none" stroke="#000" stroke-width=".25">
<path d="M20 23.6h2M28.2 23.6h2M35.3 26.2v2.5M35.3 33.8v2.6M48 23.6h7.6M48 26.2h7.6M48 31.3h7.6M48 38.9h7.6M48 36.4h7.6M76 23.6h7.6M76 26.2h7.6M76 31.3h7.6"/>
<path d="M76 36.4h7.6M86.2 38.9v2.5M96.3 26.2v2.5M96.3 33.8v2.6M124.3 23.6h2M132.5 23.6h2M86.2 46.5v2.6"/>
</g>
<g fill="none" stroke="#800000" stroke-width=".25">
<path d="M13.6 18.5h2.6M14.9 18.5v2.6M100.1 18.5h2.6M101.4 18.5v2.6M96.3 38.9v2.5M32.7 44h5.1M33.5 44.8h3.6M34.3 45.5h2M35 46.3h.5M35.3 41.4v2.6M42.9 44h5.1M43.7 44.8h3.5"/>
<path d="M44.4 45.5h2.1M45.2 46.3h.5M45.5 41.4v2.6M83.6 54.2h5.1M84.4 54.9h3.5M85.1 55.7h2.1M85.9 56.5h.5M86.2 51.6v2.6M93.8 41.4h5.1M94.6 42.2h3.5M95.3 43h2.1M96.1 43.7h.5"/>
</g>
<g fill="none" stroke="#00f" stroke-width=".25">
<path d="M22.1 22.7h6v2h-6zM33.3 31.8h4M33.3 30.8h4M35.3 28.7v2.1M35.3 31.8v2M94.3 31.8h4M94.3 30.8h4M96.3 28.7v2.1M96.3 31.8v2M126.4 22.7h6v2h-6zM84.2 44.5h4M84.2 43.5h4"/>
<path d="M86.2 41.4v2.1M86.2 44.5v2"/>
</g>
<circle cx="17.5" cy="23.6" r=".51" fill="#000080"/>
<circle cx="17.5" cy="23.6" r=".51" fill="none" stroke="#000080" stroke-width=".21"/>
<path d="M17.5 23.6v2.6" fill="none" stroke="#000" stroke-width=".25"/>
<circle cx="17.5" cy="23.6" r=".51" fill="#000080"/>
<circle cx="17.5" cy="23.6" r=".51" fill="none" stroke="#000080" stroke-width=".21"/>
<circle cx="17.5" cy="27.5" r="1.27" fill="none" stroke="#000" stroke-width=".25"/>
<circle cx="32.7" cy="23.6" r=".51" fill="#000080"/>
<circle cx="32.7" cy="23.6" r=".51" fill="none" stroke="#000080" stroke-width=".21"/>
<path d="M32.7 21.1v2.5" fill="none" stroke="#000" stroke-width=".25"/>
<circle cx="32.7" cy="23.6" r=".51" fill="#000080"/>
<circle cx="32.7" cy="23.6" r=".51" fill="none" stroke="#000080" stroke-width=".21"/>
<circle cx="32.7" cy="19.8" r="1.27" fill="none" stroke="#000" stroke-width=".25"/>
<circle cx="137" cy="23.6" r=".51" fill="#000080"/>
<circle cx="137" cy="23.6" r=".51" fill="none" stroke="#000080" stroke-width=".21"/>
<path d="M137 21.1v2.5" fill="none" stroke="#000" stroke-width=".25"/>
<circle cx="137" cy="23.6" r=".51" fill="#000080"/>
<circle cx="137" cy="23.6" r=".51" fill="none" stroke="#000080" stroke-width=".21"/>
<circle cx="137" cy="19.8" r="1.27" fill="none" stroke="#000" stroke-width=".25"/>
<circle cx="208.3" cy="23.6" r=".51" fill="#000080"/>
<circle cx="208.3" cy="23.6" r=".51" fill="none" stroke="#000080" stroke-width=".21"/>
<path d="M208.3 21.1v2.5" fill="none" stroke="#000" stroke-width=".25"/>
<circle cx="208.3" cy="23.6" r=".51" fill="#000080"/>
<circle cx="208.3" cy="23.6" r=".51" fill="none" stroke="#000080" stroke-width=".21"/>
<circle cx="208.3" cy="19.8" r="1.27" fill="none" stroke="#000" stroke-width=".25"/>
<circle cx="223.5" cy="23.6" r=".51" fill="#000080"/>
<circle cx="223.5" cy="23.6" r=".51" fill="none" stroke="#000080" stroke-width=".21"/>
<path d="M223.5 23.6v2.6" fill="none" stroke="#000" stroke-width=".25"/>
<circle cx="223.5" cy="23.6" r=".51" fill="#000080"/>
<circle cx="223.5" cy="23.6" r=".51" fill="none" stroke="#000080" stroke-width=".21"/>
<circle cx="223.5" cy="27.5" r="1.27" fill="none" stroke="#000" stroke-width=".25"/>
<circle cx="274.4" cy="102.5" r=".51" fill="#000080"/>
<circle cx="274.4" cy="102.5" r=".51" fill="none" stroke="#000080" stroke-width=".21"/>
<path d="M274.4 102.5h2.6" fill="none" stroke="#000" stroke-width=".25"/>
<circle cx="274.4" cy="102.5" r=".51" fill="#000080"/>
<circle cx="274.4" cy="102.5" r=".51" fill="none" stroke="#000080" stroke-width=".21"/>
<circle cx="278.2" cy="102.5" r="1.27" fill="none" stroke="#000" stroke-width=".25"/>
<circle cx="249" cy="33.8" r=".51" fill="#000080"/>
<circle cx="249" cy="33.8" r=".51" fill="none" stroke="#000080" stroke-width=".21"/>
<path d="M249 31.3v2.5" fill="none" stroke="#000" stroke-width=".25"/>
<circle cx="249" cy="33.8" r=".51" fill="#000080"/>
<circle cx="249" cy="33.8" r=".51" fill="none" stroke="#000080" stroke-width=".21"/>
<circle cx="249" cy="30" r="1.27" fill="none" stroke="#000" stroke-width=".25"/>
<circle cx="91.2" cy="183.9" r=".51" fill="#000080"/>
<circle cx="91.2" cy="183.9" r=".51" fill="none" stroke="#000080" stroke-width=".21"/>
<path d="M91.2 183.9v2.6" fill="none" stroke="#000" stroke-width=".25"/>
<circle cx="91.2" cy="183.9" r=".51" fill="#000080"/>
<circle cx="91.2" cy="183.9" r=".51" fill="none" stroke="#000080" stroke-width=".21"/>
<circle cx="91.2" cy="187.7" r="1.27" fill="none" stroke="#000" stroke-width=".25"/>
<circle cx="83.6" cy="189" r=".51" fill="#000080"/>
<circle cx="83.6" cy="189" r=".51" fill="none" stroke="#000080" stroke-width=".21"/>
<path d="M83.6 186.5v2.5" fill="none" stroke="#000" stroke-width=".25"/>
<circle cx="83.6" cy="189" r=".51" fill="#000080"/>
<circle cx="83.6" cy="189" r=".51" fill="none" stroke="#000080" stroke-width=".21"/>
<circle cx="83.6" cy="185.2" r="1.27" fill="none" stroke="#000" stroke-width=".25"/>
<circle cx="91.2" cy="23.6" r=".51" fill="#000080"/>
<circle cx="91.2" cy="23.6" r=".51" fill="none" stroke="#000080" stroke-width=".21"/>
<path d="M91.2 21.1v2.5" fill="none" stroke="#000" stroke-width=".25"/>
<circle cx="91.2" cy="23.6" r=".51" fill="#000080"/>
<circle cx="91.2" cy="23.6" r=".51" fill="none" stroke="#000080" stroke-width=".21"/>
<g fill="none" stroke="#000" stroke-width=".25">
<path d="M213.4 79.6v2.5M213.4 87.2v2.6M213.4 94.9v2.5M213.4 102.5v2.6"/>
<circle cx="91.2" cy="19.8" r="1.27"/>
</g>
<path d="M211.3 99.5h4.1M211.3 84.2h4.1M211.3 85.2h4.1M213.4 82.1v2.1M213.4 85.2v2M213.4 97.4v2.1M211.3 100.5h4.1M213.4 100.5v2" fill="none" stroke="#00f" stroke-width=".25"/>
<g fill="none" stroke="#800000" stroke-width=".25">
<path d="M212.1 74.5h2.5M213.4 74.5v2.6M247.7 79.6h2.5M249 79.6v2.5M203.2 97.4h5.1M203.9 98.2h3.6M204.7 98.9h2M205.5 99.7h.5M205.7 94.9v2.5M212.1 110.1h2.5M213.4 107.6v2.5M224.8 110.1h2.6"/>
<path d="M226.1 107.6v2.5M247.7 115.2h2.5M249 112.7v2.5M74.7 163.6h2.6M76 163.6v2.5"/>
</g>
<path d="M60.7 69.4h20.4v38.2h-20.4z" fill-rule="evenodd" fill="#80ff80"/>
<path d="M60.7 69.4h20.4v38.2h-20.4z" fill="none" stroke="#800000" stroke-width=".21"/>
<path d="M77.3 71h2.7l1.1 1-1.1 1h-2.7z" fill-rule="evenodd" fill="#ffff80"/>
<path d="M77.3 71h2.7l1.1 1-1.1 1h-2.7z" fill="none" stroke="#800000" stroke-width=".21"/>
<path d="M77.3 79.6l1-1h2.8v2h-2.8z" fill-rule="evenodd" fill="#ffff80"/>
<path d="M77.3 79.6l1-1h2.8v2h-2.8z" fill="none" stroke="#800000" stroke-width=".21"/>
<path d="M77.3 73.5h2.7l1.1 1-1.1 1h-2.7z" fill-rule="evenodd" fill="#ffff80"/>
<path d="M77.3 73.5h2.7l1.1 1-1.1 1h-2.7z" fill="none" stroke="#800000" stroke-width=".21"/>
<path d="M77.3 105l1-1h2.8v2.1h-2.8z" fill-rule="evenodd" fill="#ffff80"/>
<path d="M77.3 105l1-1h2.8v2.1h-2.8z" fill="none" stroke="#800000" stroke-width=".21"/>
<path d="M78.3 86.2h2.8v2.1h-2.8l-1-1.1z" fill-rule="evenodd" fill="#ffff80"/>
<path d="M78.3 86.2h2.8v2.1h-2.8l-1-1.1z" fill="none" stroke="#800000" stroke-width=".21"/>
<path d="M77.3 89.8l1-1h2.8v2h-2.8z" fill-rule="evenodd" fill="#ffff80"/>
<path d="M77.3 89.8l1-1h2.8v2h-2.8z" fill="none" stroke="#800000" stroke-width=".21"/>
<path d="M77.3 94.9l1-1h2.8v2h-2.8z" fill-rule="evenodd" fill="#ffff80"/>
<path d="M77.3 94.9l1-1h2.8v2h-2.8z" fill="none" stroke="#800000" stroke-width=".21"/>
<path d="M78.3 96.4h2.8v2h-2.8l-1-1z" fill-rule="evenodd" fill="#ffff80"/>
<path d="M78.3 96.4h2.8v2h-2.8l-1-1z" fill="none" stroke="#800000" stroke-width=".21"/>
<path d="M78.3 98.9h2.8v2.1h-2.8l-1-1z" fill-rule="evenodd" fill="#ffff80"/>
<path d="M78.3 98.9h2.8v2.1h-2.8l-1-1z" fill="none" stroke="#800000" stroke-width=".21"/>
<path d="M77.3 84.7l1-1h2.8v2h-2.8z" fill-rule="evenodd" fill="#ffff80"/>
<path d="M77.3 84.7l1-1h2.8v2h-2.8z" fill="none" stroke="#800000" stroke-width=".21"/>
<path d="M106.5 69.4h20.4v38.2h-20.4z" fill-rule="evenodd" fill="#80ff80"/>
<path d="M106.5 69.4h20.4v38.2h-20.4z" fill="none" stroke="#800000" stroke-width=".21"/>
<path d="M123 71h2.8l1.1 1-1.1 1h-2.8z" fill-rule="evenodd" fill="#ffff80"/>
<path d="M123 71h2.8l1.1 1-1.1 1h-2.8z" fill="none" stroke="#800000" stroke-width=".21"/>
<path d="M123 79.6l1.1-1h2.8v2h-2.8z" fill-rule="evenodd" fill="#ffff80"/>
<path d="M123 79.6l1.1-1h2.8v2h-2.8z" fill="none" stroke="#800000" stroke-width=".21"/>
<path d="M123 73.5h2.8l1.1 1-1.1 1h-2.8z" fill-rule="evenodd" fill="#ffff80"/>
<path d="M123 73.5h2.8l1.1 1-1.1 1h-2.8z" fill="none" stroke="#800000" stroke-width=".21"/>
<path d="M123 105l1.1-1h2.8v2.1h-2.8z" fill-rule="evenodd" fill="#ffff80"/>
<path d="M123 105l1.1-1h2.8v2.1h-2.8z" fill="none" stroke="#800000" stroke-width=".21"/>
<path d="M124.1 86.2h2.8v2.1h-2.8l-1.1-1.1z" fill-rule="evenodd" fill="#ffff80"/>
<path d="M124.1 86.2h2.8v2.1h-2.8l-1.1-1.1z" fill="none" stroke="#800000" stroke-width=".21"/>
<path d="M123 89.8l1.1-1h2.8v2h-2.8z" fill-rule="evenodd" fill="#ffff80"/>
<path d="M123 89.8l1.1-1h2.8v2h-2.8z" fill="none" stroke="#800000" stroke-width=".21"/>
<path d="M123 94.9l1.1-1h2.8v2h-2.8z" fill-rule="evenodd" fill="#ffff80"/>
<path d="M123 94.9l1.1-1h2.8v2h-2.8z" fill="none" stroke="#800000" stroke-width=".21"/>
<path d="M124.1 96.4h2.8v2h-2.8l-1.1-1z" fill-rule="evenodd" fill="#ffff80"/>
<path d="M124.1 96.4h2.8v2h-2.8l-1.1-1z" fill="none" stroke="#800000" stroke-width=".21"/>
<path d="M123 100l1.1-1.1h2.8v2.1h-2.8z" fill-rule="evenodd" fill="#ffff80"/>
<path d="M123 100l1.1-1.1h2.8v2.1h-2.8z" fill="none" stroke="#800000" stroke-width=".21"/>
<path d="M123 84.7l1.1-1h2.8v2h-2.8z" fill-rule="evenodd" fill="#ffff80"/>
<path d="M123 84.7l1.1-1h2.8v2h-2.8z" fill="none" stroke="#800000" stroke-width=".21"/>
<path d="M152.3 69.4h20.4v38.2h-20.4z" fill-rule="evenodd" fill="#80ff80"/>
<path d="M152.3 69.4h20.4v38.2h-20.4z" fill="none" stroke="#800000" stroke-width=".21"/>
<path d="M168.8 71h2.8l1.1 1-1.1 1h-2.8z" fill-rule="evenodd" fill="#ffff80"/>
<path d="M168.8 71h2.8l1.1 1-1.1 1h-2.8z" fill="none" stroke="#800000" stroke-width=".21"/>
<path d="M168.8 79.6l1.1-1h2.8v2h-2.8z" fill-rule="evenodd" fill="#ffff80"/>
<path d="M168.8 79.6l1.1-1h2.8v2h-2.8z" fill="none" stroke="#800000" stroke-width=".21"/>
<path d="M168.8 73.5h2.8l1.1 1-1.1 1h-2.8z" fill-rule="evenodd" fill="#ffff80"/>
<path d="M168.8 73.5h2.8l1.1 1-1.1 1h-2.8z" fill="none" stroke="#800000" stroke-width=".21"/>
<path d="M168.8 105l1.1-1h2.8v2.1h-2.8z" fill-rule="evenodd" fill="#ffff80"/>
<path d="M168.8 105l1.1-1h2.8v2.1h-2.8z" fill="none" stroke="#800000" stroke-width=".21"/>
<path d="M169.9 86.2h2.8v2.1h-2.8l-1.1-1.1z" fill-rule="evenodd" fill="#ffff80"/>
<path d="M169.9 86.2h2.8v2.1h-2.8l-1.1-1.1z" fill="none" stroke="#800000" stroke-width=".21"/>
<path d="M168.8 89.8l1.1-1h2.8v2h-2.8z" fill-rule="evenodd" fill="#ffff80"/>
<path d="M168.8 89.8l1.1-1h2.8v2h-2.8z" fill="none" stroke="#800000" stroke-width=".21"/>
<path d="M168.8 94.9l1.1-1h2.8v2h-2.8z" fill-rule="evenodd" fill="#ffff80"/>
<path d="M168.8 94.9l1.1-1h2.8v2h-2.8z" fill="none" stroke="#800000" stroke-width=".21"/>
<path d="M169.9 96.4h2.8v2h-2.8l-1.1-1z" fill-rule="evenodd" fill="#ffff80"/>
<path d="M169.9 96.4h2.8v2h-2.8l-1.1-1z" fill="none" stroke="#800000" stroke-width=".21"/>
<path d="M169.9 98.9h2.8v2.1h-2.8l-1.1-1z" fill-rule="evenodd" fill="#ffff80"/>
<path d="M169.9 98.9h2.8v2.1h-2.8l-1.1-1z" fill="none" stroke="#800000" stroke-width=".21"/>
<path d="M168.8 84.7l1.1-1h2.8v2h-2.8z" fill-rule="evenodd" fill="#ffff80"/>
<path d="M168.8 84.7l1.1-1h2.8v2h-2.8z" fill="none" stroke="#800000" stroke-width=".21"/>
<path d="M263 35.1h19v2.5h-19l-1.3-1.2z" fill-rule="evenodd" fill="#ffff80"/>
<path d="M263 35.1h19v2.5h-19l-1.3-1.2z" fill="none" stroke="#800000" stroke-width=".21"/>
<path d="M223.5 72h5.1M224.3 71.2h3.6M225.1 70.5h2M225.8 69.7h.5M226.1 72v2.5" fill="none" stroke="#800000" stroke-width=".25"/>
<path d="M233.7 79.6v2.5M233.7 87.2v2.6" fill="none" stroke="#000" stroke-width=".25"/>
<path d="M231.7 84.2h4M231.7 85.2h4M233.7 82.1v2.1M233.7 85.2v2" fill="none" stroke="#00f" stroke-width=".25"/>
<path d="M236.3 130.5h30.5v35.6h-30.5z" fill-rule="evenodd" fill="#ffffb0"/>
<path d="M236.3 130.5h30.5v35.6h-30.5z" fill="none" stroke="#800000" stroke-width=".21"/>
<g fill="none" stroke="#000" stroke-width=".25">
<path d="M228.6 133h7.7M228.6 138.1h7.7M245.2 138.1h2.5l1.3 1.3 1.2-2.6 1.3 2.6 1.3-2.6 1.3 2.6 1.2-1.3h2.6M266.8 138.1h7.6M228.6 158.5h7.7M228.6 143.2h7.7M228.6 148.3h7.7M228.6 153.4h7.7M245.2 143.2h2.5l1.3 1.3 1.2-2.6 1.3 2.6 1.3-2.6 1.3 2.6 1.2-1.3h2.6M245.2 148.3h2.5l1.3 1.3 1.2-2.6 1.3 2.6 1.3-2.6 1.3 2.6 1.2-1.3h2.6M245.2 153.4h2.5l1.3 1.3 1.2-2.6 1.3 2.6 1.3-2.6 1.3 2.6 1.2-1.3h2.6M266.8 158.5h7.6"/>
<path d="M266.8 143.2h7.6M266.8 148.3h7.6M266.8 153.4h7.6M172.7 166.1h2M172.7 171.2h2M172.7 176.3h2M180.8 166.1h2M180.8 171.2h2M180.8 176.3h2M228.6 161h7.7M266.8 161h7.6M266.8 163.6h7.6"/>
<path d="M172.7 181.4h2M180.8 181.4h2"/>
</g>
<path d="M174.7 165h6v2.1h-6zM174.7 170.1h6v2.1h-6zM174.7 175.2h6v2.1h-6zM174.7 180.3h6v2h-6z" fill="none" stroke="#00f" stroke-width=".25"/>
<path d="M274.4 168.6h5.1M275.2 169.4h3.5M275.9 170.2h2.1M276.7 170.9h.5M277 166.1v2.5" fill="none" stroke="#800000" stroke-width=".25"/>
<circle cx="210.8" cy="133" r=".51" fill="#000080"/>
<circle cx="210.8" cy="133" r=".51" fill="none" stroke="#000080" stroke-width=".21"/>
<path d="M210.8 133v2.6M210.8 140.7v2.5" fill="none" stroke="#000" stroke-width=".25"/>
<circle cx="210.8" cy="133" r=".51" fill="#000080"/>
<circle cx="210.8" cy="133" r=".51" fill="none" stroke="#000080" stroke-width=".21"/>
<path d="M208.8 138.6h4M208.8 137.6h4M210.8 135.6v2M210.8 138.6v2.1" fill="none" stroke="#00f" stroke-width=".25"/>
<path d="M207 127.9h2.5M208.3 127.9v2.6M208.3 145.8h5.1M209 146.5h3.6M209.8 147.3h2M210.6 148h.5M210.8 143.2v2.6" fill="none" stroke="#800000" stroke-width=".25"/>
<path d="M114.1 117.8h25.5v33h-25.5z" fill-rule="evenodd" fill="#ffffb0"/>
<path d="M114.1 117.8h25.5v33h-25.5z" fill="none" stroke="#800000" stroke-width=".21"/>
<g fill="none" stroke="#000" stroke-width=".25">
<path d="M106.5 120.3h7.6M106.5 127.9h7.6M106.5 130.5h7.6M106.5 135.6h7.6M106.5 122.9h7.6M139.6 120.3h7.6M139.6 130.5h7.6M139.6 135.6h7.6M139.6 125.4h7.6M65.8 140.7h4.5M71.5 140.7h4.5M106.5 148.3h7.6"/>
<path d="M106.5 140.7h7.6M106.5 143.2h7.6M139.6 148.3h7.6M139.6 140.7h7.6M139.6 143.2h7.6M139.6 145.7h7.6"/>
</g>
<path d="M87.4 115.2h2.6M88.7 115.2v2.6M101.4 153.4h5.1M102.2 154.1h3.5M102.9 154.9h2.1M103.7 155.7h.5M104 150.8v2.6M147.2 153.4h5.1M148 154.1h3.5M148.7 154.9h2.1M149.5 155.7h.5M149.8 150.8v2.6" fill="none" stroke="#800000" stroke-width=".25"/>
<path d="M70.9 139.4h1.3l-1.3 2.5h-1.3z" fill="none" stroke="#00f" stroke-width=".25"/>
<circle cx="86.2" cy="140.7" r=".51" fill="#000080"/>
<circle cx="86.2" cy="140.7" r=".51" fill="none" stroke="#000080" stroke-width=".21"/>
<path d="M86.2 140.7v2.5M86.2 148.3v2.5" fill="none" stroke="#000" stroke-width=".25"/>
<circle cx="86.2" cy="140.7" r=".51" fill="#000080"/>
<circle cx="86.2" cy="140.7" r=".51" fill="none" stroke="#000080" stroke-width=".21"/>
<path d="M84.2 146.3h4M84.2 145.2h4M86.2 143.2v2M86.2 146.3v2" fill="none" stroke="#00f" stroke-width=".25"/>
<path d="M83.6 153.4h5.1M84.4 154.1h3.5M85.1 154.9h2.1M85.9 155.7h.5M86.2 150.8v2.6" fill="none" stroke="#800000" stroke-width=".25"/>
<circle cx="93.8" cy="122.9" r=".51" fill="#000080"/>
<circle cx="93.8" cy="122.9" r=".51" fill="none" stroke="#000080" stroke-width=".21"/>
<path d="M93.8 122.9v2.5M93.8 130.5v2.5" fill="none" stroke="#000" stroke-width=".25"/>
<circle cx="93.8" cy="122.9" r=".51" fill="#000080"/>
<circle cx="93.8" cy="122.9" r=".51" fill="none" stroke="#000080" stroke-width=".21"/>
<path d="M76.5 128.4h4M76.5 127.4h4M78.5 125.4v2M78.5 128.4v2.1M91.8 128.4h4M91.8 127.4h4M93.8 125.4v2M93.8 128.4v2.1" fill="none" stroke="#00f" stroke-width=".25"/>
<g fill="none" stroke="#800000" stroke-width=".25">
<path d="M72.2 115.2h2.5M73.4 115.2v2.6M59.4 135.6h2.6M60.7 135.6v2.5M76 135.6h5.1M76.7 136.3h3.6M77.5 137.1h2M78.3 137.9h.5M78.5 133v2.6M91.2 135.6h5.1M92 136.3h3.6M92.8 137.1h2"/>
<path d="M93.5 137.9h.5M93.8 133v2.6"/>
</g>
<path d="M78.5 122.9v2.5M78.5 130.5v2.5" fill="none" stroke="#000" stroke-width=".25"/>
<path d="M226.1 74.5v5.1" fill="none" stroke="#000080" stroke-width=".25"/>
<circle cx="226.1" cy="77.1" r=".51" fill="#000080"/>
<circle cx="226.1" cy="77.1" r=".51" fill="none" stroke="#000080" stroke-width=".21"/>
<path d="M45.5 168.6h-2.6v2.6" fill="none" stroke="#000080" stroke-width=".25"/>
<circle cx="45.4" cy="168.6" r=".51" fill="#000080"/>
<circle cx="45.4" cy="168.6" r=".51" fill="none" stroke="#000080" stroke-width=".21"/>
<path d="M45.5 166.1v2.5h2.5v2.6" fill="none" stroke="#000080" stroke-width=".25"/>
<circle cx="45.4" cy="168.6" r=".51" fill="#000080"/>
<circle cx="45.4" cy="168.6" r=".51" fill="none" stroke="#000080" stroke-width=".21"/>
<path d="M76 168.6h-2.6v2.6" fill="none" stroke="#000080" stroke-width=".25"/>
<circle cx="76" cy="168.6" r=".51" fill="#000080"/>
<circle cx="76" cy="168.6" r=".51" fill="none" stroke="#000080" stroke-width=".21"/>
<path d="M106.5 183.9h-2.5v2.6" fill="none" stroke="#000080" stroke-width=".25"/>
<circle cx="104" cy="183.9" r=".51" fill="#000080"/>
<circle cx="104" cy="183.9" r=".51" fill="none" stroke="#000080" stroke-width=".21"/>
<path d="M226.1 92.3h10.2" fill="none" stroke="#000080" stroke-width=".25"/>
<circle cx="226.1" cy="92.3" r=".51" fill="#000080"/>
<circle cx="226.1" cy="92.3" r=".51" fill="none" stroke="#000080" stroke-width=".21"/>
<circle cx="233.7" cy="92.3" r=".51" fill="#000080"/>
<circle cx="233.7" cy="92.3" r=".51" fill="none" stroke="#000080" stroke-width=".21"/>
<path d="M271.9 97.4h2.5v22.9h-40.7v-17.8h2.6" fill="none" stroke="#000080" stroke-width=".25"/>
<circle cx="274.4" cy="97.4" r=".51" fill="#000080"/>
<circle cx="274.4" cy="97.4" r=".51" fill="none" stroke="#000080" stroke-width=".21"/>
<circle cx="274.4" cy="102.5" r=".51" fill="#000080"/>
<circle cx="274.4" cy="102.5" r=".51" fill="none" stroke="#000080" stroke-width=".21"/>
<path d="M226.1 105.1v2.5M106.5 176.3h-2.5v7.6" fill="none" stroke="#000080" stroke-width=".25"/>
<circle cx="104" cy="183.9" r=".51" fill="#000080"/>
<circle cx="104" cy="183.9" r=".51" fill="none" stroke="#000080" stroke-width=".21"/>
<g fill="none" stroke="#000080" stroke-width=".25">
<path d="M241.3 33.8h20.4M241.3 49.1h20.4M241.3 51.6h20.4M35.3 79.6h12.7M35.3 72h5.1M35.3 74.5h5.1M81.1 72h5.1M81.1 74.5h5.1M81.1 79.6h12.7M126.9 79.6h12.7M126.9 72h5M126.9 74.5h5"/>
<path d="M172.7 79.6h12.7M172.7 72h5M172.7 74.5h5M35.3 105h12.7"/>
</g>
<circle cx="249" cy="33.8" r=".51" fill="#000080"/>
<circle cx="249" cy="33.8" r=".51" fill="none" stroke="#000080" stroke-width=".21"/>
<path d="M226.1 89.8v5.1" fill="none" stroke="#000080" stroke-width=".25"/>
<circle cx="226.1" cy="92.3" r=".51" fill="#000080"/>
<circle cx="226.1" cy="92.3" r=".51" fill="none" stroke="#000080" stroke-width=".21"/>
<path d="M149.8 51.6h-2.6v2.6h2.6" fill="none" stroke="#000080" stroke-width=".25"/>
<circle cx="147.2" cy="54.2" r=".51" fill="#000080"/>
<circle cx="147.2" cy="54.2" r=".51" fill="none" stroke="#000080" stroke-width=".21"/>
<path d="M147.2 36.4h2.6M185.4 36.4h5.1v7.6h15.2v2.5M147.2 46.5h2.6M185.4 46.5h2.5" fill="none" stroke="#000080" stroke-width=".25"/>
<circle cx="205.7" cy="44" r=".51" fill="#000080"/>
<circle cx="205.7" cy="44" r=".51" fill="none" stroke="#000080" stroke-width=".21"/>
<path d="M226.1 21.1v2.5h-5.1" fill="none" stroke="#000080" stroke-width=".25"/>
<circle cx="223.5" cy="23.6" r=".51" fill="#000080"/>
<circle cx="223.5" cy="23.6" r=".51" fill="none" stroke="#000080" stroke-width=".21"/>
<path d="M139.6 23.6v2.6M139.6 36.4v2.5" fill="none" stroke="#000080" stroke-width=".25"/>
<circle cx="139.6" cy="23.6" r=".51" fill="#000080"/>
<circle cx="139.6" cy="23.6" r=".51" fill="none" stroke="#000080" stroke-width=".21"/>
<path d="M147.2 54.2v2.5" fill="none" stroke="#000080" stroke-width=".25"/>
<circle cx="147.2" cy="54.2" r=".51" fill="#000080"/>
<circle cx="147.2" cy="54.2" r=".51" fill="none" stroke="#000080" stroke-width=".21"/>
<path d="M205.7 41.4v2.6" fill="none" stroke="#000080" stroke-width=".25"/>
<circle cx="205.7" cy="44" r=".51" fill="#000080"/>
<circle cx="205.7" cy="44" r=".51" fill="none" stroke="#000080" stroke-width=".21"/>
<path d="M205.7 23.6v7.7" fill="none" stroke="#000080" stroke-width=".25"/>
<circle cx="205.7" cy="23.6" r=".51" fill="#000080"/>
<circle cx="205.7" cy="23.6" r=".51" fill="none" stroke="#000080" stroke-width=".21"/>
<path d="M185.4 23.6h25.4" fill="none" stroke="#000080" stroke-width=".25"/>
<circle cx="195.5" cy="23.6" r=".51" fill="#000080"/>
<circle cx="195.5" cy="23.6" r=".51" fill="none" stroke="#000080" stroke-width=".21"/>
<circle cx="205.7" cy="23.6" r=".51" fill="#000080"/>
<circle cx="205.7" cy="23.6" r=".51" fill="none" stroke="#000080" stroke-width=".21"/>
<circle cx="208.3" cy="23.6" r=".51" fill="#000080"/>
<circle cx="208.3" cy="23.6" r=".51" fill="none" stroke="#000080" stroke-width=".21"/>
<path d="M45.5 23.6v2.6h2.5" fill="none" stroke="#000080" stroke-width=".25"/>
<circle cx="45.4" cy="26.2" r=".51" fill="#000080"/>
<circle cx="45.4" cy="26.2" r=".51" fill="none" stroke="#000080" stroke-width=".21"/>
<circle cx="45.4" cy="23.6" r=".51" fill="#000080"/>
<circle cx="45.4" cy="23.6" r=".51" fill="none" stroke="#000080" stroke-width=".21"/>
<path d="M83.6 23.6h2.6v2.6h-2.6M86.2 49.1v2.5" fill="none" stroke="#000080" stroke-width=".25"/>
<circle cx="86.2" cy="26.2" r=".51" fill="#000080"/>
<circle cx="86.2" cy="26.2" r=".51" fill="none" stroke="#000080" stroke-width=".21"/>
<circle cx="86.2" cy="23.6" r=".51" fill="#000080"/>
<circle cx="86.2" cy="23.6" r=".51" fill="none" stroke="#000080" stroke-width=".21"/>
<path d="M96.3 36.4v2.5M76 166.1v2.5h2.5v2.6" fill="none" stroke="#000080" stroke-width=".25"/>
<circle cx="76" cy="168.6" r=".51" fill="#000080"/>
<circle cx="76" cy="168.6" r=".51" fill="none" stroke="#000080" stroke-width=".21"/>
<circle cx="78.5" cy="168.6" r=".51" fill="#000080"/>
<circle cx="78.5" cy="168.6" r=".51" fill="none" stroke="#000080" stroke-width=".21"/>
<path d="M121.8 21.1v2.5h2.5M139.6 23.6h10.2" fill="none" stroke="#000080" stroke-width=".25"/>
<circle cx="147.2" cy="23.6" r=".51" fill="#000080"/>
<circle cx="147.2" cy="23.6" r=".51" fill="none" stroke="#000080" stroke-width=".21"/>
<circle cx="139.6" cy="23.6" r=".51" fill="#000080"/>
<circle cx="139.6" cy="23.6" r=".51" fill="none" stroke="#000080" stroke-width=".21"/>
<path d="M101.4 21.1v2.5h-5.1" fill="none" stroke="#000080" stroke-width=".25"/>
<circle cx="96.3" cy="23.6" r=".51" fill="#000080"/>
<circle cx="96.3" cy="23.6" r=".51" fill="none" stroke="#000080" stroke-width=".21"/>
<path d="M45.5 23.6h2.5" fill="none" stroke="#000080" stroke-width=".25"/>
<circle cx="45.4" cy="23.6" r=".51" fill="#000080"/>
<circle cx="45.4" cy="23.6" r=".51" fill="none" stroke="#000080" stroke-width=".21"/>
<path d="M30.2 23.6h5.1" fill="none" stroke="#000080" stroke-width=".25"/>
<circle cx="32.7" cy="23.6" r=".51" fill="#000080"/>
<circle cx="32.7" cy="23.6" r=".51" fill="none" stroke="#000080" stroke-width=".21"/>
<circle cx="35.3" cy="23.6" r=".51" fill="#000080"/>
<circle cx="35.3" cy="23.6" r=".51" fill="none" stroke="#000080" stroke-width=".21"/>
<path d="M35.3 23.6h10.2" fill="none" stroke="#000080" stroke-width=".25"/>
<circle cx="35.3" cy="23.6" r=".51" fill="#000080"/>
<circle cx="35.3" cy="23.6" r=".51" fill="none" stroke="#000080" stroke-width=".21"/>
<circle cx="45.4" cy="23.6" r=".51" fill="#000080"/>
<circle cx="45.4" cy="23.6" r=".51" fill="none" stroke="#000080" stroke-width=".21"/>
<path d="M14.9 21.1v2.5h5.1" fill="none" stroke="#000080" stroke-width=".25"/>
<circle cx="17.5" cy="23.6" r=".51" fill="#000080"/>
<circle cx="17.5" cy="23.6" r=".51" fill="none" stroke="#000080" stroke-width=".21"/>
<path d="M35.3 23.6v2.6M35.3 36.4v5" fill="none" stroke="#000080" stroke-width=".25"/>
<circle cx="35.3" cy="23.6" r=".51" fill="#000080"/>
<circle cx="35.3" cy="23.6" r=".51" fill="none" stroke="#000080" stroke-width=".21"/>
<path d="M134.5 23.6h5.1" fill="none" stroke="#000080" stroke-width=".25"/>
<circle cx="139.6" cy="23.6" r=".51" fill="#000080"/>
<circle cx="139.6" cy="23.6" r=".51" fill="none" stroke="#000080" stroke-width=".21"/>
<circle cx="137" cy="23.6" r=".51" fill="#000080"/>
<circle cx="137" cy="23.6" r=".51" fill="none" stroke="#000080" stroke-width=".21"/>
<path d="M213.4 77.1v2.5M213.4 92.3h-7.7v2.6M213.4 105.1v2.5" fill="none" stroke="#000080" stroke-width=".25"/>
<circle cx="213.4" cy="92.3" r=".51" fill="#000080"/>
<circle cx="213.4" cy="92.3" r=".51" fill="none" stroke="#000080" stroke-width=".21"/>
<path d="M45.5 26.2v5.1h2.5" fill="none" stroke="#000080" stroke-width=".25"/>
<circle cx="45.4" cy="26.2" r=".51" fill="#000080"/>
<circle cx="45.4" cy="26.2" r=".51" fill="none" stroke="#000080" stroke-width=".21"/>
<path d="M45.5 38.9h2.5" fill="none" stroke="#000080" stroke-width=".25"/>
<circle cx="45.4" cy="38.9" r=".51" fill="#000080"/>
<circle cx="45.4" cy="38.9" r=".51" fill="none" stroke="#000080" stroke-width=".21"/>
<path d="M147.2 23.6v2.6h2.6" fill="none" stroke="#000080" stroke-width=".25"/>
<circle cx="147.2" cy="23.6" r=".51" fill="#000080"/>
<circle cx="147.2" cy="23.6" r=".51" fill="none" stroke="#000080" stroke-width=".21"/>
<g fill="none" stroke="#000080" stroke-width=".25">
<path d="M83.6 36.4h2.6v2.5M35.3 97.4h12.7M35.3 100h12.7M35.3 94.9h12.7M35.3 87.2h12.7M35.3 89.8h12.7M35.3 84.7h12.7M81.1 97.4h12.7M81.1 100h12.7M81.1 94.9h12.7M81.1 87.2h12.7M81.1 89.8h12.7"/>
<path d="M81.1 84.7h12.7M126.9 97.4h12.7M126.9 100h12.7M126.9 94.9h12.7M126.9 87.2h12.7M126.9 89.8h12.7M126.9 84.7h12.7M172.7 97.4h12.7M172.7 100h12.7M172.7 94.9h12.7M172.7 87.2h12.7M172.7 89.8h12.7"/>
<path d="M172.7 84.7h12.7M213.4 89.8v5.1M81.1 105h12.7M126.9 105h12.7M172.7 105.1h12.7"/>
</g>
<circle cx="213.4" cy="92.3" r=".51" fill="#000080"/>
<circle cx="213.4" cy="92.3" r=".51" fill="none" stroke="#000080" stroke-width=".21"/>
<path d="M226.1 77.1h7.6v2.5" fill="none" stroke="#000080" stroke-width=".25"/>
<circle cx="226.1" cy="77.1" r=".51" fill="#000080"/>
<circle cx="226.1" cy="77.1" r=".51" fill="none" stroke="#000080" stroke-width=".21"/>
<path d="M233.7 89.8v2.5" fill="none" stroke="#000080" stroke-width=".25"/>
<circle cx="233.7" cy="92.3" r=".51" fill="#000080"/>
<circle cx="233.7" cy="92.3" r=".51" fill="none" stroke="#000080" stroke-width=".21"/>
<path d="M106.5 163.6h-25.4v5h-2.6" fill="none" stroke="#000080" stroke-width=".25"/>
<circle cx="86.2" cy="163.6" r=".51" fill="#000080"/>
<circle cx="86.2" cy="163.6" r=".51" fill="none" stroke="#000080" stroke-width=".21"/>
<circle cx="78.5" cy="168.6" r=".51" fill="#000080"/>
<circle cx="78.5" cy="168.6" r=".51" fill="none" stroke="#000080" stroke-width=".21"/>
<path d="M73.4 181.4v2.5" fill="none" stroke="#000080" stroke-width=".25"/>
<circle cx="73.4" cy="183.9" r=".51" fill="#000080"/>
<circle cx="73.4" cy="183.9" r=".51" fill="none" stroke="#000080" stroke-width=".21"/>
<path d="M42.9 181.4v2.5" fill="none" stroke="#000080" stroke-width=".25"/>
<circle cx="42.9" cy="183.9" r=".51" fill="#000080"/>
<circle cx="42.9" cy="183.9" r=".51" fill="none" stroke="#000080" stroke-width=".21"/>
<path d="M60.7 166.1v2.5" fill="none" stroke="#000080" stroke-width=".25"/>
<circle cx="60.7" cy="168.6" r=".51" fill="#000080"/>
<circle cx="60.7" cy="168.6" r=".51" fill="none" stroke="#000080" stroke-width=".21"/>
<path d="M48 181.4v7.6h-12.7" fill="none" stroke="#000080" stroke-width=".25"/>
<circle cx="48" cy="189" r=".51" fill="#000080"/>
<circle cx="48" cy="189" r=".51" fill="none" stroke="#000080" stroke-width=".21"/>
<path d="M48 189h2.5" fill="none" stroke="#000080" stroke-width=".25"/>
<circle cx="48" cy="189" r=".51" fill="#000080"/>
<circle cx="48" cy="189" r=".51" fill="none" stroke="#000080" stroke-width=".21"/>
<path d="M106.5 171.2h-7.6v17.8h-20.4v-7.6" fill="none" stroke="#000080" stroke-width=".25"/>
<circle cx="83.6" cy="189" r=".51" fill="#000080"/>
<circle cx="83.6" cy="189" r=".51" fill="none" stroke="#000080" stroke-width=".21"/>
<circle cx="78.5" cy="189" r=".51" fill="#000080"/>
<circle cx="78.5" cy="189" r=".51" fill="none" stroke="#000080" stroke-width=".21"/>
<path d="M60.7 189h17.8" fill="none" stroke="#000080" stroke-width=".25"/>
<circle cx="78.5" cy="189" r=".51" fill="#000080"/>
<circle cx="78.5" cy="189" r=".51" fill="none" stroke="#000080" stroke-width=".21"/>
<path d="M274.4 97.4h2.6" fill="none" stroke="#000080" stroke-width=".25"/>
<circle cx="274.4" cy="97.4" r=".51" fill="#000080"/>
<circle cx="274.4" cy="97.4" r=".51" fill="none" stroke="#000080" stroke-width=".21"/>
<path d="M106.5 168.6h-10.2v15.3h-25.4" fill="none" stroke="#000080" stroke-width=".25"/>
<circle cx="73.4" cy="183.9" r=".51" fill="#000080"/>
<circle cx="73.4" cy="183.9" r=".51" fill="none" stroke="#000080" stroke-width=".21"/>
<circle cx="91.2" cy="183.9" r=".51" fill="#000080"/>
<circle cx="91.2" cy="183.9" r=".51" fill="none" stroke="#000080" stroke-width=".21"/>
<path d="M65.8 176.3v-7.7h-10.2v12.8" fill="none" stroke="#000080" stroke-width=".25"/>
<circle cx="60.7" cy="168.6" r=".51" fill="#000080"/>
<circle cx="60.7" cy="168.6" r=".51" fill="none" stroke="#000080" stroke-width=".21"/>
<path d="M48 36.4h-2.5v5" fill="none" stroke="#000080" stroke-width=".25"/>
<circle cx="45.4" cy="38.9" r=".51" fill="#000080"/>
<circle cx="45.4" cy="38.9" r=".51" fill="none" stroke="#000080" stroke-width=".21"/>
<path d="M86.2 23.6h10.1v2.6" fill="none" stroke="#000080" stroke-width=".25"/>
<circle cx="86.2" cy="23.6" r=".51" fill="#000080"/>
<circle cx="86.2" cy="23.6" r=".51" fill="none" stroke="#000080" stroke-width=".21"/>
<circle cx="91.2" cy="23.6" r=".51" fill="#000080"/>
<circle cx="91.2" cy="23.6" r=".51" fill="none" stroke="#000080" stroke-width=".21"/>
<circle cx="96.3" cy="23.6" r=".51" fill="#000080"/>
<circle cx="96.3" cy="23.6" r=".51" fill="none" stroke="#000080" stroke-width=".21"/>
<g fill="none" stroke="#000080" stroke-width=".25">
<path d="M274.4 138.1h7.6M274.4 153.4h7.6M274.4 148.3h7.6M274.4 143.2h7.6M165 171.2h7.7M165 166.1h7.7M165 176.3h7.7M182.8 176.3h8.9M182.8 171.2h8.9M182.8 166.1h8.9M274.4 163.6h2.6v2.5M165 181.4h7.7"/>
<path d="M182.8 181.4h8.9"/>
</g>
<circle cx="277" cy="163.6" r=".51" fill="#000080"/>
<circle cx="277" cy="163.6" r=".51" fill="none" stroke="#000080" stroke-width=".21"/>
<path d="M274.4 158.5h2.6v5.1" fill="none" stroke="#000080" stroke-width=".25"/>
<circle cx="277" cy="161" r=".51" fill="#000080"/>
<circle cx="277" cy="161" r=".51" fill="none" stroke="#000080" stroke-width=".21"/>
<circle cx="277" cy="163.6" r=".51" fill="#000080"/>
<circle cx="277" cy="163.6" r=".51" fill="none" stroke="#000080" stroke-width=".21"/>
<path d="M274.4 161h2.6" fill="none" stroke="#000080" stroke-width=".25"/>
<circle cx="277" cy="161" r=".51" fill="#000080"/>
<circle cx="277" cy="161" r=".51" fill="none" stroke="#000080" stroke-width=".21"/>
<path d="M208.3 130.5v2.5h20.3M221 158.5h7.6M221 161h7.6" fill="none" stroke="#000080" stroke-width=".25"/>
<circle cx="210.8" cy="133" r=".51" fill="#000080"/>
<circle cx="210.8" cy="133" r=".51" fill="none" stroke="#000080" stroke-width=".21"/>
<g fill="none" stroke="#000080" stroke-width=".25">
<path d="M147.2 135.6h10.2M147.2 130.5h10.2M147.2 125.4h10.2M147.2 120.3h10.2M221 138.1h7.6M106.5 148.3h-2.5v2.5M221 153.4h7.6M221 148.3h7.6M221 143.2h7.6M147.2 171.2h10.2M147.2 166.1h10.2M147.2 176.3h10.2"/>
<path d="M147.2 181.4h10.2"/>
</g>
<circle cx="104" cy="148.3" r=".51" fill="#000080"/>
<circle cx="104" cy="148.3" r=".51" fill="none" stroke="#000080" stroke-width=".21"/>
<path d="M106.5 135.6h-2.5v12.7" fill="none" stroke="#000080" stroke-width=".25"/>
<circle cx="104" cy="143.2" r=".51" fill="#000080"/>
<circle cx="104" cy="143.2" r=".51" fill="none" stroke="#000080" stroke-width=".21"/>
<circle cx="104" cy="148.3" r=".51" fill="#000080"/>
<circle cx="104" cy="148.3" r=".51" fill="none" stroke="#000080" stroke-width=".21"/>
<path d="M35.3 183.9h25.4" fill="none" stroke="#000080" stroke-width=".25"/>
<circle cx="42.9" cy="183.9" r=".51" fill="#000080"/>
<circle cx="42.9" cy="183.9" r=".51" fill="none" stroke="#000080" stroke-width=".21"/>
<path d="M104 127.9h2.5M104 130.5h2.5M104 143.2h2.5" fill="none" stroke="#000080" stroke-width=".25"/>
<circle cx="104" cy="143.2" r=".51" fill="#000080"/>
<circle cx="104" cy="143.2" r=".51" fill="none" stroke="#000080" stroke-width=".21"/>
<path d="M147.2 143.2h2.6" fill="none" stroke="#000080" stroke-width=".25"/>
<circle cx="149.8" cy="143.2" r=".51" fill="#000080"/>
<circle cx="149.8" cy="143.2" r=".51" fill="none" stroke="#000080" stroke-width=".21"/>
<path d="M147.2 145.7h2.6" fill="none" stroke="#000080" stroke-width=".25"/>
<circle cx="149.8" cy="145.7" r=".51" fill="#000080"/>
<circle cx="149.8" cy="145.7" r=".51" fill="none" stroke="#000080" stroke-width=".21"/>
<path d="M147.2 148.3h2.6" fill="none" stroke="#000080" stroke-width=".25"/>
<circle cx="149.8" cy="148.3" r=".51" fill="#000080"/>
<circle cx="149.8" cy="148.3" r=".51" fill="none" stroke="#000080" stroke-width=".21"/>
<path d="M147.2 140.7h2.6v10.1" fill="none" stroke="#000080" stroke-width=".25"/>
<circle cx="149.8" cy="143.2" r=".51" fill="#000080"/>
<circle cx="149.8" cy="143.2" r=".51" fill="none" stroke="#000080" stroke-width=".21"/>
<circle cx="149.8" cy="145.7" r=".51" fill="#000080"/>
<circle cx="149.8" cy="145.7" r=".51" fill="none" stroke="#000080" stroke-width=".21"/>
<circle cx="149.8" cy="148.3" r=".51" fill="#000080"/>
<circle cx="149.8" cy="148.3" r=".51" fill="none" stroke="#000080" stroke-width=".21"/>
<path d="M76 140.7h30.5" fill="none" stroke="#000080" stroke-width=".25"/>
<circle cx="86.2" cy="140.7" r=".51" fill="#000080"/>
<circle cx="86.2" cy="140.7" r=".51" fill="none" stroke="#000080" stroke-width=".21"/>
<circle cx="98.9" cy="140.7" r=".51" fill="#000080"/>
<circle cx="98.9" cy="140.7" r=".51" fill="none" stroke="#000080" stroke-width=".21"/>
<path d="M88.7 117.8v5.1h17.8" fill="none" stroke="#000080" stroke-width=".25"/>
<circle cx="93.8" cy="122.9" r=".51" fill="#000080"/>
<circle cx="93.8" cy="122.9" r=".51" fill="none" stroke="#000080" stroke-width=".21"/>
<path d="M60.7 138.1v2.6h5.1M106.5 120.3h-28v2.6" fill="none" stroke="#000080" stroke-width=".25"/>
<circle cx="78.5" cy="120.3" r=".51" fill="#000080"/>
<circle cx="78.5" cy="120.3" r=".51" fill="none" stroke="#000080" stroke-width=".21"/>
<path d="M73.4 117.8v2.5h5.1" fill="none" stroke="#000080" stroke-width=".25"/>
<circle cx="78.5" cy="120.3" r=".51" fill="#000080"/>
<circle cx="78.5" cy="120.3" r=".51" fill="none" stroke="#000080" stroke-width=".21"/>
<path d="M86.2 26.2v5.1h-2.6" fill="none" stroke="#000080" stroke-width=".25"/>
<circle cx="86.2" cy="26.2" r=".51" fill="#000080"/>
<circle cx="86.2" cy="26.2" r=".51" fill="none" stroke="#000080" stroke-width=".21"/>
<path d="M241.3 38.9h20.4M241.3 36.4h20.4M241.3 41.4h20.4M241.3 59.3h20.4" fill="none" stroke="#000080" stroke-width=".76"/>
<circle cx="98.9" cy="140.7" r=".51" fill="#000080"/>
<circle cx="98.9" cy="140.7" r=".51" fill="none" stroke="#000080" stroke-width=".21"/>
<path d="M98.9 140.7v2.5" fill="none" stroke="#000" stroke-width=".25"/>
<circle cx="98.9" cy="140.7" r=".51" fill="#000080"/>
<circle cx="98.9" cy="140.7" r=".51" fill="none" stroke="#000080" stroke-width=".21"/>
<circle cx="98.9" cy="144.5" r="1.27" fill="none" stroke="#000" stroke-width=".25"/>
<use href="#words"/>
</svg>
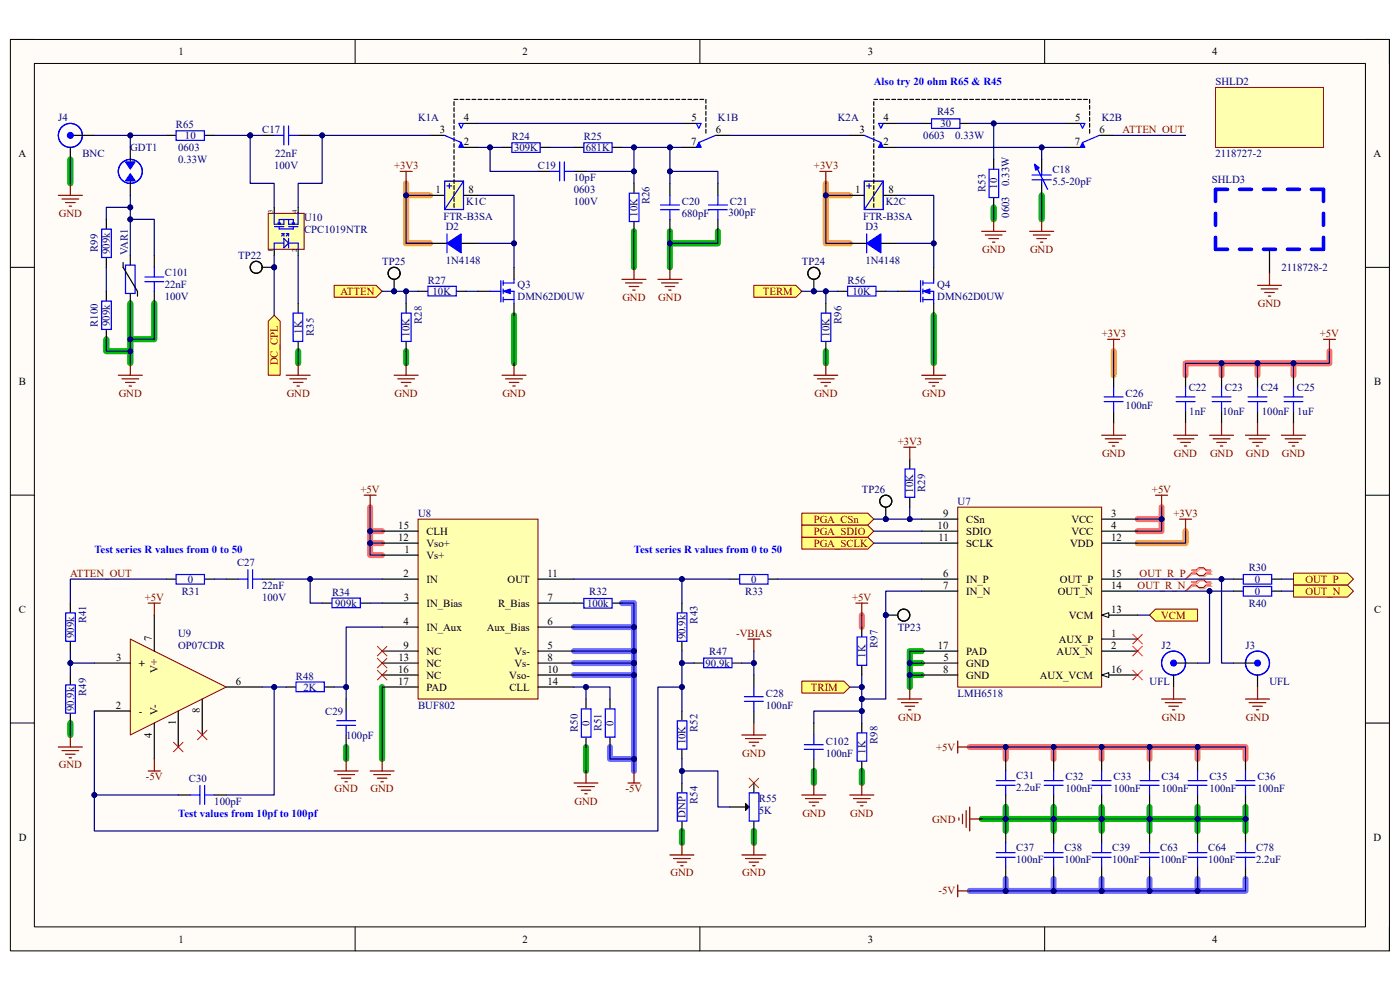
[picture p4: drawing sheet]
<svg xmlns="http://www.w3.org/2000/svg" width="297mm" height="210mm" viewBox="0 0 297 210" stroke-linecap="round" stroke-linejoin="round" font-family="sans-serif">
<defs><g id="words">
<g font-size="2.3">
<text x="37.9" y="11.7">1</text>
<text x="110.9" y="11.7">2</text>
<text x="184.1" y="11.7">3</text>
<text x="257.1" y="11.7">4</text>
<text x="93.3" y="28.2">3</text>
<text x="98.4" y="25.7">4</text>
<text x="146.7" y="25.7">5</text>
<text x="151.8" y="28.2">6</text>
<text x="182.3" y="28.2">3</text>
<text x="187.5" y="25.7">4</text>
<text x="228.1" y="25.7">5</text>
<text x="233.3" y="28.2">6</text>
<text x="3.9" y="33.3">A</text>
<text x="98.4" y="30.7">2</text>
<text x="146.6" y="30.7">7</text>
<text x="187.5" y="30.7">2</text>
<text x="228" y="30.7">7</text>
<text x="291.4" y="33.3">A</text>
<text x="92.4" y="40.9">1</text>
<text x="99.4" y="40.9">8</text>
<text x="181.4" y="40.9">1</text>
<text x="188.5" y="40.9">8</text>
<text x="4" y="81.6">B</text>
<text x="291.5" y="81.6">B</text>
<text x="84.5" y="112.1">15</text>
<text x="90.5" y="113.4">CLH</text>
<text x="198.9" y="112.1">10</text>
<text x="200.1" y="109.6">9</text>
<text x="205" y="110.9">CSn</text>
<text x="205" y="113.4">SDIO</text>
<text x="227.3" y="110.9">VCC</text>
<text x="227.3" y="113.4">VCC</text>
<text x="235.8" y="109.6">3</text>
<text x="235.8" y="112.1">4</text>
<text x="84.5" y="114.7">12</text>
<text x="85.8" y="117.3">1</text>
<text x="90.5" y="118.5">Vs+</text>
<text x="90.5" y="116">Vso+</text>
<text x="199.1" y="114.7">11</text>
<text x="205" y="116">SCLK</text>
<text x="227" y="116">VDD</text>
<text x="235.8" y="114.7">12</text>
<text x="85.6" y="122.3">2</text>
<text x="90.5" y="123.6">IN</text>
<text x="107.7" y="123.6">OUT</text>
<text x="116.2" y="122.3">11</text>
<text x="200.1" y="122.3">6</text>
<text x="200.1" y="124.9">7</text>
<text x="205" y="123.6">IN_P</text>
<text x="224.9" y="123.6">OUT_P</text>
<text x="235.8" y="124.9">14</text>
<text x="235.8" y="122.3">15</text>
<text x="4" y="130">C</text>
<text x="85.7" y="127.4">3</text>
<text x="90.5" y="128.7">IN_Bias</text>
<text x="105.7" y="128.7">R_Bias</text>
<text x="116.2" y="127.4">7</text>
<text x="205" y="126.2">IN_N</text>
<text x="224.4" y="126.2">OUT_N</text>
<text x="226.7" y="131.2">VCM</text>
<text x="235.8" y="130">13</text>
<text x="291.5" y="130">C</text>
<text x="32.2" y="136.1" transform="rotate(-90 32.2 136.1)">7</text>
<text x="85.6" y="132.5">4</text>
<text x="85.6" y="137.6">9</text>
<text x="90.5" y="133.8">IN_Aux</text>
<text x="103.3" y="133.8">Aux_Bias</text>
<text x="116.2" y="137.6">5</text>
<text x="116.2" y="132.5">6</text>
<text x="199" y="137.6">17</text>
<text x="224.6" y="136.3">AUX_P</text>
<text x="235.8" y="135">1</text>
<text x="235.8" y="137.6">2</text>
<text x="24.6" y="140.1">3</text>
<text x="29.4" y="141.4">+</text>
<text x="33.5" y="142.8" transform="rotate(-90 33.5 142.8)">V+</text>
<text x="84.5" y="142.7">16</text>
<text x="84.5" y="140.1">13</text>
<text x="90.5" y="138.9">NC</text>
<text x="90.5" y="141.4">NC</text>
<text x="90.5" y="144">NC</text>
<text x="108" y="144">Vso-</text>
<text x="109.1" y="138.9">Vs-</text>
<text x="109.1" y="141.4">Vs-</text>
<text x="116.2" y="140.1">8</text>
<text x="116.2" y="142.7">10</text>
<text x="200.1" y="142.7">8</text>
<text x="200.2" y="140.1">5</text>
<text x="205" y="144">GND</text>
<text x="205" y="141.4">GND</text>
<text x="205" y="138.9">PAD</text>
<text x="220.6" y="144">AUX_VCM</text>
<text x="224.2" y="138.9">AUX_N</text>
<text x="235.8" y="142.7">16</text>
<text x="50" y="145.2">6</text>
<text x="84.5" y="145.2">17</text>
<text x="90.5" y="146.5">PAD</text>
<text x="108.1" y="146.5">CLL</text>
<text x="116.2" y="145.2">14</text>
<text x="24.6" y="150.3">2</text>
<text x="29.4" y="151.6">-</text>
<text x="33.5" y="151.6" transform="rotate(-90 33.5 151.6)">V-</text>
<text x="37.3" y="153.8" transform="rotate(-90 37.3 153.8)">1</text>
<text x="42.4" y="151.3" transform="rotate(-90 42.4 151.3)">8</text>
<text x="32.2" y="156.5" transform="rotate(-90 32.2 156.5)">4</text>
<text x="4" y="178.3">D</text>
<text x="291.4" y="178.3">D</text>
<text x="37.9" y="199.9">1</text>
<text x="110.9" y="199.9">2</text>
<text x="184.1" y="199.9">3</text>
<text x="257.1" y="199.9">4</text>
</g>
<g font-size="2.3" fill="#00f">
<text x="185.4" y="18">Also try 20 ohm R65 &amp; R45</text>
<text x="20" y="117.3">Test series R values from 0 to 50</text>
<text x="134.5" y="117.3">Test series R values from 0 to 50</text>
<text x="37.8" y="173.2">Test values from 10pf to 100pf</text>
</g>
<g font-size="2.3" fill="#000080">
<text x="257.9" y="18">SHLD2</text>
<text x="12.4" y="25.7">J4</text>
<text x="37.3" y="27.2">R65</text>
<text x="39.2" y="29.5">10</text>
<text x="55.6" y="28.2">C17</text>
<text x="88.7" y="25.7">K1A</text>
<text x="108.6" y="29.8">R24</text>
<text x="123.9" y="29.8">R25</text>
<text x="152.3" y="25.7">K1B</text>
<text x="177.8" y="25.7">K2A</text>
<text x="195.9" y="29.5">0603</text>
<text x="198.8" y="24.4">R45</text>
<text x="199.5" y="26.9">30</text>
<text x="202.6" y="29.5">0.33W</text>
<text x="233.7" y="25.7">K2B</text>
<text x="17.5" y="33.3">BNC</text>
<text x="27.6" y="32">GDT1</text>
<text x="37.8" y="32">0603</text>
<text x="37.8" y="34.6">0.33W</text>
<text x="58.2" y="35.9">100V</text>
<text x="58.4" y="33.3">22nF</text>
<text x="109.1" y="32">309K</text>
<text x="114.1" y="35.9">C19</text>
<text x="124.3" y="32">681K</text>
<text x="257.9" y="33.3">2118727-2</text>
<text x="121.8" y="40.9">0603</text>
<text x="121.8" y="38.4">10pF</text>
<text x="209" y="40.7" transform="rotate(-90 209 40.7)">R53</text>
<text x="211.6" y="40" transform="rotate(-90 211.6 40)">10</text>
<text x="214.1" y="39.5" transform="rotate(-90 214.1 39.5)">0.33W</text>
<text x="223.3" y="36.6">C18</text>
<text x="223.3" y="39.2">5.5-20pF</text>
<text x="257.1" y="38.9">SHLD3</text>
<text x="64.5" y="46.8">U10</text>
<text x="94.1" y="46.7">FTR-B3SA</text>
<text x="98.9" y="43.5">K1C</text>
<text x="121.8" y="43.5">100V</text>
<text x="135.3" y="46" transform="rotate(-90 135.3 46)">10K</text>
<text x="137.8" y="43.3" transform="rotate(-90 137.8 43.3)">R26</text>
<text x="144.7" y="43.5">C20</text>
<text x="144.7" y="46">680pF</text>
<text x="154.6" y="45.8">300pF</text>
<text x="154.9" y="43.5">C21</text>
<text x="183.1" y="46.7">FTR-B3SA</text>
<text x="187.9" y="43.5">K2C</text>
<text x="214.1" y="46.2" transform="rotate(-90 214.1 46.2)">0603</text>
<text x="20.8" y="53.5" transform="rotate(-90 20.8 53.5)">R99</text>
<text x="23.3" y="53.9" transform="rotate(-90 23.3 53.9)">909k</text>
<text x="64.5" y="49.4">CPC1019NTR</text>
<text x="94.6" y="48.9">D2</text>
<text x="183.6" y="48.9">D3</text>
<text x="27.1" y="54.1" transform="rotate(-90 27.1 54.1)">VAR1</text>
<text x="35" y="58.5">C101</text>
<text x="50.5" y="54.9">TP22</text>
<text x="81.1" y="56.2">TP25</text>
<text x="94.6" y="55.9">1N4148</text>
<text x="170.1" y="56.2">TP24</text>
<text x="183.6" y="55.9">1N4148</text>
<text x="271.9" y="57.4">2118728-2</text>
<text x="35" y="63.6">100V</text>
<text x="35" y="61">22nF</text>
<text x="90.8" y="60.2">R27</text>
<text x="91.8" y="62.6">10K</text>
<text x="109.8" y="61">Q3</text>
<text x="109.8" y="63.6">DMN62D0UW</text>
<text x="179.8" y="60.2">R56</text>
<text x="180.8" y="62.6">10K</text>
<text x="198.8" y="61">Q4</text>
<text x="198.8" y="63.6">DMN62D0UW</text>
<text x="20.8" y="69.3" transform="rotate(-90 20.8 69.3)">R100</text>
<text x="23.3" y="69.2" transform="rotate(-90 23.3 69.2)">909k</text>
<text x="64" y="70.8" transform="rotate(-90 64 70.8)">1K</text>
<text x="66.6" y="71.2" transform="rotate(-90 66.6 71.2)">R35</text>
<text x="86.9" y="71.4" transform="rotate(-90 86.9 71.4)">10K</text>
<text x="89.5" y="68.7" transform="rotate(-90 89.5 68.7)">R28</text>
<text x="176" y="71.4" transform="rotate(-90 176 71.4)">10K</text>
<text x="178.5" y="68.7" transform="rotate(-90 178.5 68.7)">R96</text>
<text x="252.2" y="82.9">C22</text>
<text x="259.9" y="82.9">C23</text>
<text x="267.5" y="82.9">C24</text>
<text x="275.1" y="82.9">C25</text>
<text x="238.8" y="84.2">C26</text>
<text x="238.8" y="86.7">100nF</text>
<text x="252.3" y="88">1nF</text>
<text x="259.4" y="88">10nF</text>
<text x="267.7" y="88">100nF</text>
<text x="275.2" y="88">1uF</text>
<text x="182.8" y="104.5">TP26</text>
<text x="193.8" y="104.5" transform="rotate(-90 193.8 104.5)">10K</text>
<text x="196.3" y="104.4" transform="rotate(-90 196.3 104.4)">R29</text>
<text x="203.2" y="107.1">U7</text>
<text x="88.7" y="109.6">U8</text>
<text x="39.8" y="123.6">0</text>
<text x="50.3" y="120.1">C27</text>
<text x="55.6" y="124.9">22nF</text>
<text x="159.4" y="123.6">0</text>
<text x="264.9" y="121.1">R30</text>
<text x="266.2" y="123.6">0</text>
<text x="38.6" y="126.2">R31</text>
<text x="55.6" y="127.4">100V</text>
<text x="70.4" y="126.4">R34</text>
<text x="71.1" y="128.7">909k</text>
<text x="124.5" y="128.7">100k</text>
<text x="125" y="126.2">R32</text>
<text x="158.1" y="126.2">R33</text>
<text x="264.9" y="128.7">R40</text>
<text x="266.2" y="126.2">0</text>
<text x="15.7" y="135.3" transform="rotate(-90 15.7 135.3)">909k</text>
<text x="18.2" y="132.2" transform="rotate(-90 18.2 132.2)">R41</text>
<text x="37.8" y="135">U9</text>
<text x="37.8" y="137.6">OP07CDR</text>
<text x="145.5" y="135.6" transform="rotate(-90 145.5 135.6)">90.9k</text>
<text x="148" y="132.3" transform="rotate(-90 148 132.3)">R43</text>
<text x="186.1" y="137.4" transform="rotate(-90 186.1 137.4)">R97</text>
<text x="190.5" y="133.8">TP23</text>
<text x="246.4" y="137.6">J2</text>
<text x="264.2" y="137.6">J3</text>
<text x="149.7" y="141.4">90.9k</text>
<text x="150.5" y="138.9">R47</text>
<text x="183.6" y="139.5" transform="rotate(-90 183.6 139.5)">1K</text>
<text x="18.2" y="147.6" transform="rotate(-90 18.2 147.6)">R49</text>
<text x="62.8" y="144.2">R48</text>
<text x="64.4" y="146.5">2K</text>
<text x="162.5" y="147.8">C28</text>
<text x="203.2" y="147.8">LMH6518</text>
<text x="243.9" y="145.2">UFL</text>
<text x="269.3" y="145.2">UFL</text>
<text x="15.7" y="150.9" transform="rotate(-90 15.7 150.9)">90.9k</text>
<text x="69" y="151.6">C29</text>
<text x="88.7" y="150.3">BUF802</text>
<text x="122.6" y="155.2" transform="rotate(-90 122.6 155.2)">R50</text>
<text x="125.1" y="153.9" transform="rotate(-90 125.1 153.9)">0</text>
<text x="127.6" y="155.2" transform="rotate(-90 127.6 155.2)">R51</text>
<text x="130.2" y="153.9" transform="rotate(-90 130.2 153.9)">0</text>
<text x="148" y="155.2" transform="rotate(-90 148 155.2)">R52</text>
<text x="162.5" y="150.3">100nF</text>
<text x="73.4" y="156.7">100pF</text>
<text x="145.5" y="157.9" transform="rotate(-90 145.5 157.9)">10K</text>
<text x="175.2" y="157.9">C102</text>
<text x="175.2" y="160.5">100nF</text>
<text x="183.6" y="159.9" transform="rotate(-90 183.6 159.9)">1K</text>
<text x="186.1" y="157.8" transform="rotate(-90 186.1 157.8)">R98</text>
<text x="40.1" y="165.9">C30</text>
<text x="215.6" y="165.3">C31</text>
<text x="215.6" y="167.9">2.2uF</text>
<text x="226.1" y="165.6">C32</text>
<text x="236.3" y="165.6">C33</text>
<text x="246.4" y="165.6">C34</text>
<text x="256.6" y="165.6">C35</text>
<text x="266.8" y="165.6">C36</text>
<text x="45.5" y="170.7">100pF</text>
<text x="145.5" y="173.4" transform="rotate(-90 145.5 173.4)">DNP</text>
<text x="148" y="170.5" transform="rotate(-90 148 170.5)">R54</text>
<text x="161" y="170.2">R55</text>
<text x="161" y="172.8">5K</text>
<text x="226.1" y="168.1">100nF</text>
<text x="236.3" y="168.1">100nF</text>
<text x="246.4" y="168.1">100nF</text>
<text x="256.6" y="168.1">100nF</text>
<text x="266.8" y="168.1">100nF</text>
<text x="215.6" y="180.6">C37</text>
<text x="215.6" y="183.1">100nF</text>
<text x="225.8" y="180.6">C38</text>
<text x="225.8" y="183.1">100nF</text>
<text x="236" y="180.6">C39</text>
<text x="236" y="183.1">100nF</text>
<text x="246.1" y="180.6">C63</text>
<text x="246.1" y="183.1">100nF</text>
<text x="256.3" y="180.6">C64</text>
<text x="256.3" y="183.1">100nF</text>
<text x="266.5" y="180.6">C78</text>
<text x="266.5" y="183.1">2.2uF</text>
</g>
<g font-size="2.3" fill="#800000">
<text x="238.2" y="28.2">ATTEN_OUT</text>
<text x="83.6" y="35.9">+3V3</text>
<text x="172.7" y="35.9">+3V3</text>
<text x="12.5" y="46">GND</text>
<text x="208.4" y="53.6">GND</text>
<text x="218.5" y="53.6">GND</text>
<text x="72.2" y="62.6">ATTEN</text>
<text x="132" y="63.8">GND</text>
<text x="139.7" y="63.8">GND</text>
<text x="161.8" y="62.6">TERM</text>
<text x="266.9" y="65.1">GND</text>
<text x="233.7" y="71.5">+3V3</text>
<text x="280" y="71.5">+5V</text>
<text x="58.9" y="77.5" transform="rotate(-90 58.9 77.5)">DC_CPL</text>
<text x="25.2" y="84.2">GND</text>
<text x="60.8" y="84.2">GND</text>
<text x="83.7" y="84.2">GND</text>
<text x="106.6" y="84.2">GND</text>
<text x="172.8" y="84.2">GND</text>
<text x="195.7" y="84.2">GND</text>
<text x="190.5" y="94.4">+3V3</text>
<text x="233.8" y="96.9">GND</text>
<text x="249" y="96.9">GND</text>
<text x="256.7" y="96.9">GND</text>
<text x="264.3" y="96.9">GND</text>
<text x="271.9" y="96.9">GND</text>
<text x="76.5" y="104.5">+5V</text>
<text x="244.4" y="104.5">+5V</text>
<text x="172.6" y="110.9">PGA_CSn</text>
<text x="172.6" y="113.4">PGA_SDIO</text>
<text x="249" y="109.6">+3V3</text>
<text x="172.6" y="116">PGA_SCLK</text>
<text x="14.9" y="122.3">ATTEN_OUT</text>
<text x="241.3" y="124.9">OUT_R_N</text>
<text x="241.8" y="122.3">OUT_R_P</text>
<text x="276.9" y="123.6">OUT_P</text>
<text x="30.7" y="127.4">+5V</text>
<text x="180.8" y="127.4">+5V</text>
<text x="246.3" y="131.2">VCM</text>
<text x="276.9" y="126.2">OUT_N</text>
<text x="156.2" y="135">-VBIAS</text>
<text x="172" y="146.5">TRIM</text>
<text x="190.5" y="152.9">GND</text>
<text x="246.5" y="152.9">GND</text>
<text x="264.3" y="152.9">GND</text>
<text x="157.5" y="160.5">GND</text>
<text x="198.6" y="159.2">+5V</text>
<text x="12.5" y="163">GND</text>
<text x="30.9" y="165.6">-5V</text>
<text x="71" y="168.1">GND</text>
<text x="78.6" y="168.1">GND</text>
<text x="121.9" y="170.7">GND</text>
<text x="132.7" y="168.1">-5V</text>
<text x="170.2" y="173.2">GND</text>
<text x="180.4" y="173.2">GND</text>
<text x="197.8" y="174.5">GND</text>
<text x="142.2" y="185.9">GND</text>
<text x="157.5" y="185.9">GND</text>
<text x="199.1" y="189.7">-5V</text>
</g>
<g font-size="1.4">
<text x="57.9" y="45.3" transform="rotate(-90 57.9 45.3)">3</text>
<text x="62.9" y="45.3" transform="rotate(-90 62.9 45.3)">4</text>
<text x="57.9" y="53.4" transform="rotate(-90 57.9 53.4)">1</text>
<text x="62.9" y="53.5" transform="rotate(-90 62.9 53.5)">2</text>
</g>
</g></defs>
<path d="M2.2 8.4h292.6v193.3h-292.6z" fill-rule="evenodd" fill="#fffcf8"/>
<path d="M2.2 8.4h292.6v193.3h-292.6z" fill="none" stroke="#000" stroke-width=".21"/>
<path d="M7.3 13.5h282.4v183.1h-282.4z" fill-rule="evenodd" fill="#fffcf8"/>
<g fill="none" stroke="#000" stroke-width=".21">
<path d="M2.2 8.4h5.1M7.3 13.5h282.4v183.1h-282.4zM75.3 8.4v5.1M148.5 8.4v5.1M221.6 8.4v5.1M289.7 8.4h5.1v5.1M2.2 56.7h5.1M289.7 56.7h5.1M2.2 105h5.1M289.7 105.1h5.1M2.2 153.4h5.1M289.7 153.4h5.1"/>
<path d="M75.3 196.6v5.1M148.5 196.6v5.1M221.6 196.6v5.1M294.8 196.6v5.1"/>
</g>
<path d="M86.2 38.9v2.5h5M175.2 38.9v2.5h5.1M86.2 41.4v10.2h5M175.2 41.4v10.2h5.1M236.3 74.5v5.1M251.5 112.7v2.5h-10.2" fill="none" stroke="#f90" stroke-width="1.3"/>
<g fill="none" stroke="#00be00" stroke-width="1.3">
<path d="M14.9 33.8v5.1M134.5 49.1v7.6M142.1 49.1v7.6M152.3 49.1v2.5h-10.2M210.8 44v2.5M221 41.4v5.1M22.6 72v2.5h5M27.6 64.3v12.8M32.7 64.3v7.7h-5.1M63.3 74.5v2.6M86.2 74.5v2.6M109.1 66.9v10.2"/>
<path d="M175.2 74.5v2.6M198.1 66.9v10.2M195.5 138.1h-2.5v5.1h2.5M14.9 153.4v2.5M73.4 158.5v2.5M81.1 145.7v15.3M124.3 158.5v5.1M193 140.7h2.5M193 143.2v2.6M144.7 176.3v2.5M159.9 176.3v2.5M172.7 163.6v2.5"/>
<path d="M182.8 163.6v2.5M208.3 173.7h55.9M213.4 171.2v5.1M223.5 171.2v5.1M233.7 171.2v5.1M243.9 171.2v5.1M254.1 171.2v5.1M264.2 171.2v5.1"/>
</g>
<g fill="none" stroke="#ff6e6e" stroke-width="1.3">
<path d="M259.2 77.1h-7.7v2.5M266.8 77.1h-7.6v2.5M274.4 77.1v2.5M282 74.5v2.6h-15.2v2.5M78.5 107.6v10.2h2.6M78.5 115.2h2.6M78.5 112.7h2.6M241.3 110.1h5.1M246.4 107.6v5.1h-5.1M182.8 130.5v2.5M205.7 158.5h17.8v2.5M213.4 158.5v2.5"/>
<path d="M223.5 158.5h40.7v2.5M233.7 158.5v2.5M243.9 158.5v2.5M254.1 158.5v2.5"/>
</g>
<g fill="none" stroke="#6e6eff" stroke-width="1.3">
<path d="M121.8 133h12.7v5.1h-12.7M131.9 127.9h2.6v5.1M134.5 138.1v2.6M121.8 140.7h12.7M129.4 158.5v2.5h5.1M134.5 140.7v2.5h-12.7M134.5 143.2v20.4M213.4 186.5v2.5M223.5 186.5v2.5M233.7 186.5v2.5M243.9 186.5v2.5M254.1 186.5v2.5"/>
<path d="M264.2 186.5v2.5h-58.5"/>
</g>
<circle cx="58.2" cy="56.7" r=".51" fill="#000080"/>
<circle cx="58.2" cy="56.7" r=".51" fill="none" stroke="#000080" stroke-width=".21"/>
<path d="M55.6 56.7h2.6" fill="none" stroke="#000" stroke-width=".25"/>
<circle cx="58.2" cy="56.7" r=".51" fill="#000080"/>
<circle cx="58.2" cy="56.7" r=".51" fill="none" stroke="#000080" stroke-width=".21"/>
<g fill="none" stroke="#000" stroke-width=".25">
<path d="M269.3 52.9v5.1"/>
<circle cx="54.4" cy="56.7" r="1.27"/>
</g>
<path d="M257.9 45.3v2.5M257.9 50.4v2.5h2.5M260.4 40.2h-2.5v2.5M263 52.9h2.5M263 40.2h2.5M268.1 52.9h2.5M268.1 40.2h2.5M273.1 52.9h2.6M273.1 40.2h2.6M278.2 40.2h2.6v2.5M280.8 50.4v2.5h-2.6M280.8 45.3v2.5" fill="none" stroke="#00f" stroke-width=".76"/>
<path d="M269.3 58v2.5M266.8 60.5h5.1M267.5 61.3h3.6M268.3 62.1h2M269.1 62.8h.5" fill="none" stroke="#800000" stroke-width=".25"/>
<path d="M257.9 18.6h22.9v12.7h-22.9z" fill-rule="evenodd" fill="#ffffb0"/>
<path d="M257.9 18.6h22.9v12.7h-22.9z" fill="none" stroke="#800000" stroke-width=".21"/>
<path d="M94.3 38.4h4v6h-4z" fill-rule="evenodd" fill="#ffffb0"/>
<path d="M94.3 38.4h4v6h-4z" fill="none" stroke="#800000" stroke-width=".21"/>
<path d="M94.8 39.4h1M95.3 38.9v1M98.3 38.4l-4 6M98.3 38.4h-4v6M98.3 38.4v6h-4" fill="none" stroke="#00f" stroke-width=".25"/>
<path d="M91.2 41.4h3M91.2 51.6h3.9M97.6 51.6h3.8M98.4 41.4h3" fill="none" stroke="#000" stroke-width=".25"/>
<path d="M84.9 36.4h2.5M86.2 36.4v2.5" fill="none" stroke="#800000" stroke-width=".25"/>
<path d="M94.8 51.6l3-2v4z" fill="#00f"/>
<path d="M94.8 51.6l3-2v4zM94.8 49.6v4M106.3 59.5v4.6M106.8 59.5v1M104 61.8h2.3M106.8 60h2.3M106.8 61.8h2.3v2.5M106.8 63.5h2.3M106.8 61.3v1M106.8 63.1v1" fill="none" stroke="#00f" stroke-width=".25"/>
<path d="M109.1 56.7v2.6M101.4 61.8h2.6M109.1 64.3v2.6" fill="none" stroke="#000" stroke-width=".25"/>
<path d="M106.8 61.8l1.5-.5v1z" fill="#00f"/>
<path d="M106.8 61.8l1.5-.5v1z" fill="none" stroke="#00f" stroke-width=".21"/>
<path d="M109.1 59.3v.7M85.2 66.4h2v6h-2z" fill="none" stroke="#00f" stroke-width=".25"/>
<path d="M83.6 79.6h5.1M86.2 77.1v2.5M106.5 79.6h5.1M109.1 77.1v2.5M84.4 80.4h3.5M85.1 81.1h2.1M85.9 81.9h.5M107.3 80.4h3.5M108 81.1h2.1M108.8 81.9h.5" fill="none" stroke="#800000" stroke-width=".25"/>
<path d="M86.2 64.3v2M86.2 72.5v2" fill="none" stroke="#000" stroke-width=".25"/>
<path d="M70.9 60.5h8.9l1.3 1.3-1.3 1.3h-8.9z" fill-rule="evenodd" fill="#ffff80"/>
<path d="M70.9 60.5h8.9l1.3 1.3-1.3 1.3h-8.9z" fill="none" stroke="#800000" stroke-width=".21"/>
<g fill="none" stroke="#000" stroke-width=".25">
<path d="M91.2 28.7h3M96.3 21.6v.8M96.3 22.8v.8M96.3 24.1v.8M96.3 25.4v.8M96.3 26.7v.8M96.3 27.9v.8M96.3 29.2v.8M96.3 30.5v.8M96.3 31.7v.8M96.3 33v.8M96.3 34.3v.8"/>
<path d="M96.3 35.6v.8M96.3 36.8v.8M96.3 38.1v.8M96.3 39.4v.8M96.3 21.1h.8M97.6 21.1h.8M98.9 21.1h.8M100.1 21.1h.8M101.4 21.1h.8M102.7 21.1h.8M104 21.1h.8M105.2 21.1h.8"/>
<path d="M106.5 31.3h2M106.5 21.1h.8M107.8 21.1h.8M109.1 21.1h.7M110.3 21.1h.8M111.6 21.1h.8M112.9 21.1h.8M114.1 36.4h2.6M114.1 21.1h.8M114.7 31.3h2M115.4 21.1h.8M116.7 21.1h.8"/>
<path d="M118 21.1h.8M119.2 21.1h.8M120.5 21.1h.8M121.8 31.3h2M121.8 36.4h2.5M121.8 21.1h.8M123 21.1h.8M124.3 21.1h.8M125.6 21.1h.8M126.9 21.1h.8M128.1 21.1h.8M129.4 21.1h.8"/>
<path d="M129.9 31.3h2M130.7 21.1h.8M131.9 21.1h.8M133.2 21.1h.8M134.5 38.9v2M134.5 21.1h.8M135.8 21.1h.8M137 21.1h.8M138.3 21.1h.8M139.6 21.1h.8M140.9 21.1h.7M142.1 38.9v2.5"/>
<path d="M142.1 21.1h.8M143.4 21.1h.8M144.7 21.1h.8M145.9 21.1h.8M147.2 21.1h.8M148.5 21.1h.8M149.8 21.1v.8M149.8 22.4v.8M149.8 23.6v.8M149.8 24.9v.8M149.8 26.2v.8M149.8 27.5v.7"/>
<path d="M152.3 38.9v2.5M96.3 40.7v.7M96.3 41.9v.8M96.3 43.2v.8M134.5 47.1v2M142.1 46.5v2.6M152.3 46.5v2.6"/>
</g>
<g fill="none" stroke="#00f" stroke-width=".25">
<path d="M94.3 28.7l3.5 1.5M108.6 30.3h6v2h-6zM116.7 36.4h2M118.7 34.4v4M119.7 36.4h2.1M119.7 34.4v4M123.9 30.3h6v2h-6zM133.5 41h2.1v6h-2.1zM140.1 44.5h4M140.1 43.5h4M142.1 41.4v2.1M142.1 44.5v2"/>
<path d="M150.3 44.5h4M150.3 43.5h4M152.3 41.4v2.1M152.3 44.5v2"/>
</g>
<path d="M131.9 59.3h5.1M134.5 56.7v2.6M139.6 59.3h5.1M142.1 56.7v2.6M132.7 60h3.6M133.5 60.8h2M134.2 61.5h.5M140.3 60h3.6M141.1 60.8h2M141.9 61.5h.5" fill="none" stroke="#800000" stroke-width=".25"/>
<path d="M97.8 30.2l.5 1.1h-1z" fill="#00f"/>
<path d="M97.3 26.2h1l-.5 1zM97.8 30.2l.5 1.1h-1zM147.8 26.2h1l-.5 1zM151.8 28.7l-3.5 1.5" fill="none" stroke="#00f" stroke-width=".25"/>
<path d="M98.4 31.3h3M98.4 26.2h3M151.8 28.7h3" fill="none" stroke="#000" stroke-width=".25"/>
<path d="M148.3 30.2l.5 1.1h-1z" fill="#00f"/>
<path d="M58.2 28.7h2M60.2 26.7v4M61.2 28.7h2.1M61.2 26.7v4M148.3 30.2l.5 1.1h-1zM62.2 66.4h2v6h-2zM90.8 60.7h6v2.1h-6z" fill="none" stroke="#00f" stroke-width=".25"/>
<path d="M55.6 28.7h2.6M63.3 28.7h2.5M144.7 26.2h3M144.7 31.3h3M63.3 64.3v2M63.3 72.5v2M88.7 61.8h2M96.9 61.8h2" fill="none" stroke="#000" stroke-width=".25"/>
<path d="M25.1 79.6h5.1M27.6 77.1v2.5M60.7 79.6h5.1M63.3 77.1v2.5M25.9 80.4h3.5M26.6 81.1h2.1M27.4 81.9h.5M61.5 80.4h3.5M62.2 81.1h2.1M63 81.9h.5" fill="none" stroke="#800000" stroke-width=".25"/>
<path d="M58.2 66.9l1.2 1.3v11.4h-2.5v-11.4z" fill-rule="evenodd" fill="#ffff80"/>
<path d="M58.2 66.9l1.2 1.3v11.4h-2.5v-11.4z" fill="none" stroke="#800000" stroke-width=".21"/>
<circle cx="27.6" cy="36.4" r="2.54" fill="none" stroke="#00f" stroke-width=".25"/>
<path d="M26.6 34.4h2l-1 1.5z" fill="#00f"/>
<path d="M26.6 34.4h2l-1 1.5z" fill="none" stroke="#00f" stroke-width=".25"/>
<path d="M27.6 36.9l1 1.5h-2z" fill="#00f"/>
<path d="M27.6 36.9l1 1.5h-2z" fill="none" stroke="#00f" stroke-width=".25"/>
<path d="M27.6 31.3v2.9M27.6 38.5v2.9" fill="none" stroke="#000" stroke-width=".25"/>
<path d="M56.9 45.3h7.6v7.6h-7.6z" fill-rule="evenodd" fill="#ffffb0"/>
<path d="M56.9 45.3h7.6v7.6h-7.6z" fill="none" stroke="#800000" stroke-width=".21"/>
<path d="M14.9 28.7h5.1M14.9 31.3v2.5M58.2 44v1.3M58.2 52.9v1.3M63.3 44v1.3M63.3 52.9v1.3" fill="none" stroke="#000" stroke-width=".25"/>
<g fill="none" stroke="#00f" stroke-width=".25">
<path d="M58.2 45.3v2.3M58.2 48.1h2M59 47.3h.5l-.3 .3zM59.2 48.1v.5h3v-.5M59.2 47.6v-1h3v1M59.7 49.6h.5M60.2 49.6l-.5 .5M60.2 46.6v1h-2M60.2 49.6v.5M60.2 50.6l1 1-1 1zM60.2 51.6h-2v1.3M60.7 49.6h.5"/>
<path d="M61.2 49.6l-.5 .5M61.2 49.6v.5M61.2 50.6v2M61.2 48.1h2M61.2 51.6h2.1v1.3M62 47.3h.5l-.3 .3zM63.2 45.1v2.5h-2v-1"/>
<circle cx="14.9" cy="28.7" r="2.54"/>
</g>
<path d="M14.9 38.9v2.5M12.4 41.4h5.1M13.1 42.2h3.6M13.9 43h2M14.7 43.7h.5" fill="none" stroke="#800000" stroke-width=".25"/>
<circle cx="14.9" cy="28.7" r=".64" fill="#00f"/>
<circle cx="14.9" cy="28.7" r=".64" fill="none" stroke="#00f" stroke-width=".21"/>
<circle cx="83.6" cy="61.8" r=".51" fill="#000080"/>
<circle cx="83.6" cy="61.8" r=".51" fill="none" stroke="#000080" stroke-width=".21"/>
<path d="M83.6 59.3v2.5" fill="none" stroke="#000" stroke-width=".25"/>
<circle cx="83.6" cy="61.8" r=".51" fill="#000080"/>
<circle cx="83.6" cy="61.8" r=".51" fill="none" stroke="#000080" stroke-width=".21"/>
<circle cx="83.6" cy="58" r="1.27" fill="none" stroke="#000" stroke-width=".25"/>
<path d="M12.4 158.5h5.1M13.1 159.2h3.6M13.9 160h2M14.9 155.9v2.6M14.7 160.8h.5" fill="none" stroke="#800000" stroke-width=".25"/>
<path d="M27.6 135.6l20.4 10.1-20.4 10.2z" fill="#ffffb0"/>
<path d="M27.6 135.6l20.4 10.1-20.4 10.2z" fill="none" stroke="#800000" stroke-width=".21"/>
<g fill="none" stroke="#000" stroke-width=".25">
<path d="M14.9 127.9v2M14.9 136.1v2M32.7 130.5v7.6M35.3 122.9h2M43.4 122.9h2.1M48 122.9h2.5M55.6 122.9h2.6M144.7 127.9v2M144.7 136.1v2M14.9 143.2v2M14.9 151.4v2M20 140.7h7.6"/>
<path d="M20 150.8h7.6M32.7 153.4v7.6M37.8 150.8v7.7M42.9 148.3v7.6M48 145.7h7.6M60.7 145.7h2M68.9 145.7h2M144.7 150.8v2M144.7 159v2M147.2 140.7h2M155.4 140.7h2M159.9 143.2v2.5"/>
<path d="M159.9 150.8v2.6M37.8 168.6h2.6M45.5 168.6h2.5M144.7 166.1v2M144.7 174.3v2M223.5 161v2.6M223.5 168.6v2.6M233.7 161v2.6M233.7 168.6v2.6M243.9 161v2.6M243.9 168.6v2.6M254.1 161v2.6"/>
<path d="M254.1 168.6v2.6M264.2 161v2.6M264.2 168.6v2.6"/>
</g>
<path d="M36.8 157.5l2 2M38.8 157.5l-2 2M41.9 154.9l2 2M43.9 154.9l-2 2" fill="none" stroke="#f00" stroke-width=".21"/>
<g fill="none" stroke="#00f" stroke-width=".25">
<path d="M13.9 130h2.1v6h-2.1zM37.4 121.9h6v2h-6zM50.5 122.9h2.1M52.6 120.9v4M53.6 122.9h2M53.6 120.9v4M143.7 130h2v6h-2zM149.3 139.6h6v2h-6zM13.9 145.3h2.1v6h-2.1zM62.8 144.7h6v2h-6zM143.7 152.9h2v6h-2zM157.9 147.8h4"/>
<path d="M157.9 148.8h4M159.9 145.7v2.1M159.9 148.8v2M40.4 168.6h2M42.4 166.6v4M43.4 168.6h2.1M43.4 166.6v4M143.7 168.2h2v6h-2zM221.5 165.6h4M221.5 166.6h4M223.5 163.6v2M223.5 166.6v2"/>
<path d="M231.7 165.6h4M231.7 166.6h4M233.7 163.6v2M233.7 166.6v2M241.9 165.6h4M241.9 166.6h4M243.9 163.6v2M243.9 166.6v2M252.1 165.6h4M252.1 166.6h4M254.1 163.6v2M254.1 166.6v2"/>
<path d="M262.2 165.6h4M262.2 166.6h4M264.2 163.6v2M264.2 166.6v2"/>
</g>
<g fill="none" stroke="#800000" stroke-width=".25">
<path d="M31.5 127.9h2.5M32.7 127.9v2.6M158.7 135.6h2.5M159.9 135.6v2.5M157.4 155.9h5.1M158.2 156.7h3.5M158.9 157.5h2.1M159.7 158.2h.5M159.9 153.4v2.5M31.5 163.6h2.5M32.7 161v2.6M144.7 178.8v2.6"/>
<path d="M142.1 181.4h5.1M142.9 182.1h3.6M143.6 182.9h2.1M144.4 183.7h.5"/>
</g>
<path d="M88.7 110.1h25.4v38.2h-25.4z" fill-rule="evenodd" fill="#ffffb0"/>
<path d="M88.7 110.1h25.4v38.2h-25.4z" fill="none" stroke="#800000" stroke-width=".21"/>
<g fill="none" stroke="#000" stroke-width=".25">
<path d="M81.1 117.8h7.6M81.1 115.2h7.6M81.1 112.7h7.6M68.3 127.9h2.1M76.5 127.9h2M81.1 122.9h7.6M81.1 127.9h7.6M81.1 133h7.6M81.1 138.1h7.6M114.1 122.9h7.7M114.1 127.9h9.7M114.1 133h7.7"/>
<path d="M114.1 138.1h7.7M129.9 127.9h2M154.8 122.9h2M163 122.9h2M73.4 148.3v2.5M73.4 155.9v2.6M81.1 140.7h7.6M81.1 143.2h7.6M81.1 145.7h7.6M114.1 140.7h7.7M114.1 143.2h7.7M114.1 145.7h7.7"/>
<path d="M124.3 148.3v2M124.3 156.5v2M154.8 171.2h4.1M159.9 166.1v2M159.9 174.3v2M213.4 161v2.6M213.4 168.6v2.6M213.4 176.3v2.5M223.5 176.3v2.5M233.7 176.3v2.5M243.9 176.3v2.5M254.1 176.3v2.5"/>
<path d="M264.2 176.3v2.5M213.4 183.9v2.6M223.5 183.9v2.6M233.7 183.9v2.6M243.9 183.9v2.6M254.1 183.9v2.6M264.2 183.9v2.6"/>
</g>
<path d="M80.1 137.1l2 2M80.1 139.6l2 2.1M82.1 137.1l-2 2M82.1 139.6l-2 2.1M80.1 142.2l2 2M82.1 142.2l-2 2M158.9 165.1l2.1 2M161 165.1l-2.1 2" fill="none" stroke="#f00" stroke-width=".21"/>
<g fill="none" stroke="#800000" stroke-width=".25">
<path d="M77.3 105h2.5M78.5 105v2.6M203.2 157.2v2.5M203.2 158.5h2.5M70.9 163.6h5.1M71.7 164.3h3.5M72.4 165.1h2.1M73.2 165.8h.5M73.4 161v2.6M78.5 163.6h5.1M79.3 164.3h3.5M80.1 165.1h2"/>
<path d="M80.8 165.8h.5M81.1 161v2.6M121.8 166.1h5.1M122.5 166.9h3.6M123.3 167.6h2M124.1 168.4h.5M124.3 163.6v2.5M133.2 166.1h2.6M134.5 163.6v2.5M159.9 178.8v2.6M157.4 181.4h5.1M158.2 182.1h3.5"/>
<path d="M158.9 182.9h2.1M159.7 183.7h.5M203.2 187.7v2.6M203.2 189h2.5"/>
</g>
<g fill="none" stroke="#00f" stroke-width=".25">
<path d="M70.4 126.9h6v2h-6zM123.9 127h6v2h-6zM156.9 121.9h6v2h-6zM71.4 153.9h4M71.4 152.9h4M73.4 150.8v2.1M73.4 153.9v2M123.3 150.4h2.1v6h-2.1zM159 168.2h2v6h-2zM211.3 166.6h4.1M211.3 165.6h4.1M213.4 163.6v2"/>
<path d="M213.4 166.6v2M213.4 178.8v2.1M223.5 178.8v2.1M233.7 178.8v2.1M243.9 178.8v2.1M254.1 178.8v2.1M264.2 178.8v2.1M211.3 181.9h4.1M211.3 180.9h4.1M213.4 181.9v2M221.5 181.9h4M221.5 180.9h4"/>
<path d="M223.5 181.9v2M231.7 181.9h4M231.7 180.9h4M233.7 181.9v2M241.9 181.9h4M241.9 180.9h4M243.9 181.9v2M252.1 181.9h4M252.1 180.9h4M254.1 181.9v2M262.2 181.9h4M262.2 180.9h4"/>
<path d="M264.2 181.9v2"/>
</g>
<path d="M158.2 170.4l.7 .8-.7 .8z" fill="#000"/>
<path d="M158.2 170.4l.7 .8-.7 .8z" fill="none" stroke="#000" stroke-width=".21"/>
<path d="M203.2 107.6h30.5v38.2h-30.5z" fill-rule="evenodd" fill="#ffffb0"/>
<path d="M203.2 107.6h30.5v38.2h-30.5z" fill="none" stroke="#800000" stroke-width=".21"/>
<path d="M195.5 110.1h7.7M195.5 112.7h7.7M195.5 115.2h7.7M233.7 115.2h7.6M233.7 130.5h7.6" fill="none" stroke="#000" stroke-width=".25"/>
<path d="M233.7 130.5l1.5-.5v1z" fill="#f8fcff"/>
<path d="M233.7 130.5l1.5-.5v1z" fill="none" stroke="#000" stroke-width=".21"/>
<path d="M233.7 125.4h7.6M233.7 122.9h7.6M233.7 135.6h7.6M233.7 138.1h7.6M233.7 143.2h7.6" fill="none" stroke="#000" stroke-width=".25"/>
<path d="M233.7 143.2l1.5-.5v1z" fill="#f8fcff"/>
<path d="M233.7 143.2l1.5-.5v1z" fill="none" stroke="#000" stroke-width=".21"/>
<path d="M233.7 110.1h7.6M233.7 112.7h7.6M195.5 138.1h7.7M195.5 122.9h7.7M195.5 125.4h7.7M195.5 143.2h7.7M195.5 140.7h7.7" fill="none" stroke="#000" stroke-width=".25"/>
<path d="M170.1 108.9h14l1.3 1.2-1.3 1.3h-14z" fill-rule="evenodd" fill="#ffff80"/>
<path d="M170.1 108.9h14l1.3 1.2-1.3 1.3h-14z" fill="none" stroke="#800000" stroke-width=".21"/>
<path d="M193 97.4v2M193 105.6v2" fill="none" stroke="#000" stroke-width=".25"/>
<path d="M192 99.5h2.1v6h-2.1z" fill="none" stroke="#00f" stroke-width=".25"/>
<path d="M191.7 94.9h2.6M193 94.9v2.5" fill="none" stroke="#800000" stroke-width=".25"/>
<path d="M170.1 114h14l1.3 1.2-1.3 1.3h-14z" fill-rule="evenodd" fill="#ffff80"/>
<path d="M170.1 114h14l1.3 1.2-1.3 1.3h-14z" fill="none" stroke="#800000" stroke-width=".21"/>
<path d="M170.1 111.4h14l1.3 1.3-1.3 1.3h-14z" fill-rule="evenodd" fill="#ffff80"/>
<path d="M170.1 111.4h14l1.3 1.3-1.3 1.3h-14z" fill="none" stroke="#800000" stroke-width=".21"/>
<path d="M190.5 148.3h5M191.2 149.1h3.6M192 149.8h2M192.8 150.6h.5M193 145.8v2.5" fill="none" stroke="#800000" stroke-width=".25"/>
<path d="M245.2 129.2h8.9v2.6h-8.9l-1.3-1.3z" fill-rule="evenodd" fill="#ffff80"/>
<path d="M245.2 129.2h8.9v2.6h-8.9l-1.3-1.3z" fill="none" stroke="#800000" stroke-width=".21"/>
<path d="M250.2 110.1h2.6M251.5 110.1v2.6" fill="none" stroke="#800000" stroke-width=".25"/>
<path d="M240.3 134.6l2.1 2M240.3 137.1l2.1 2M242.4 134.6l-2.1 2M242.4 137.1l-2.1 2M240.3 142.2l2.1 2M242.4 142.2l-2.1 2" fill="none" stroke="#f00" stroke-width=".21"/>
<path d="M274.4 121.6h11.5l1.2 1.3-1.2 1.2h-11.5z" fill-rule="evenodd" fill="#ffff80"/>
<path d="M274.4 121.6h11.5l1.2 1.3-1.2 1.2h-11.5z" fill="none" stroke="#800000" stroke-width=".21"/>
<path d="M274.4 124.1h11.5l1.2 1.3-1.2 1.3h-11.5z" fill-rule="evenodd" fill="#ffff80"/>
<path d="M274.4 124.1h11.5l1.2 1.3-1.2 1.3h-11.5z" fill="none" stroke="#800000" stroke-width=".21"/>
<path d="M261.7 122.9h2M261.7 125.4h2M269.9 122.9h2M269.9 125.4h2M249 140.7h5.1M249 143.2v2.6" fill="none" stroke="#000" stroke-width=".25"/>
<g fill="none" stroke="#00f" stroke-width=".25">
<path d="M263.8 121.9h6v2h-6zM263.8 124.4h6v2.1h-6z"/>
<circle cx="249" cy="140.7" r="2.54"/>
</g>
<circle cx="249" cy="140.7" r=".64" fill="#00f"/>
<circle cx="249" cy="140.7" r=".64" fill="none" stroke="#00f" stroke-width=".21"/>
<path d="M246.4 148.3h5.1M247.2 149.1h3.6M248 149.8h2M248.7 150.6h.5M249 145.8v2.5" fill="none" stroke="#800000" stroke-width=".25"/>
<circle cx="266.8" cy="140.7" r="2.54" fill="none" stroke="#00f" stroke-width=".25"/>
<path d="M261.7 140.7h5.1M266.8 143.2v2.6" fill="none" stroke="#000" stroke-width=".25"/>
<circle cx="266.8" cy="140.7" r=".64" fill="#00f"/>
<circle cx="266.8" cy="140.7" r=".64" fill="none" stroke="#00f" stroke-width=".21"/>
<path d="M264.2 148.3h5.1M265 149.1h3.6M265.8 149.8h2M266.5 150.6h.5M266.8 145.8v2.5" fill="none" stroke="#800000" stroke-width=".25"/>
<path d="M253 121.2h1.1l.5-.5h1l.5 .5h1M253 121.8h1.1l.5 .5h1l.5-.5h1" fill="none" stroke="#d0a19e" stroke-width=".25"/>
<path d="M253 121.8l-1.5 1.1" fill="none" stroke="#d0a19e" stroke-width=".21"/>
<path d="M252.8 120.9h1l.5-.5h1l.5 .5h1.1M252.8 121.6h1l.5 .5h1l.5-.5h1.1" fill="none" stroke="#f00" stroke-width=".25"/>
<path d="M252.8 121.6l-1.3 1.3" fill="none" stroke="#f00" stroke-width=".21"/>
<circle cx="187.9" cy="110.1" r=".51" fill="#000080"/>
<circle cx="187.9" cy="110.1" r=".51" fill="none" stroke="#000080" stroke-width=".21"/>
<path d="M187.9 107.6v2.5" fill="none" stroke="#000" stroke-width=".25"/>
<circle cx="187.9" cy="110.1" r=".51" fill="#000080"/>
<circle cx="187.9" cy="110.1" r=".51" fill="none" stroke="#000080" stroke-width=".21"/>
<g fill="none" stroke="#000" stroke-width=".25">
<path d="M26.1 55.7v1l3.1 5.1v1M27.6 54.2v2M27.6 62.3v2M236.3 79.6v2.5M251.5 79.6v2.5M259.2 79.6v2.5M266.8 79.6v2.5M274.4 79.6v2.5M236.3 87.2v2.6M251.5 87.2v2.6M259.2 87.2v2.6M266.8 87.2v2.6"/>
<path d="M274.4 87.2v2.6M129.4 148.3v2M129.4 156.5v2"/>
<circle cx="187.9" cy="106.3" r="1.27"/>
</g>
<g fill="none" stroke="#00f" stroke-width=".25">
<path d="M26.6 56.2h2.1v6.1h-2.1zM234.3 85.2h4M234.3 84.2h4M236.3 82.1v2.1M236.3 85.2v2M249.5 85.2h4M249.5 84.2h4M251.5 82.1v2.1M251.5 85.2v2M257.1 85.2h4.1M257.1 84.2h4.1M259.2 82.1v2.1"/>
<path d="M259.2 85.2v2M264.8 85.2h4M264.8 84.2h4M266.8 82.1v2.1M266.8 85.2v2M272.4 85.2h4M272.4 84.2h4M274.4 82.1v2.1M274.4 85.2v2M128.4 150.4h2.1v6h-2.1z"/>
</g>
<g fill="none" stroke="#800000" stroke-width=".25">
<path d="M235 72h2.5M236.3 72v2.5M280.8 72h2.5M282 72v2.5M233.7 92.3h5.1M234.5 93.1h3.5M235.2 93.9h2.1M236 94.6h.5M236.3 89.8v2.5M249 92.3h5.1M249.7 93.1h3.6M250.5 93.9h2"/>
<path d="M251.3 94.6h.5M251.5 89.8v2.5M256.6 92.3h5.1M257.4 93.1h3.5M258.1 93.9h2.1M258.9 94.6h.5M259.2 89.8v2.5M264.2 92.3h5.1M265 93.1h3.6M265.8 93.9h2M266.5 94.6h.5M266.8 89.8v2.5"/>
<path d="M271.9 92.3h5.1M272.6 93.1h3.6M273.4 93.9h2M274.2 94.6h.5M274.4 89.8v2.5M245.2 105.1h2.5M246.4 105.1v2.5M203.4 173.5v.5M204.2 172.7v2.1M205 172v3.5M205.7 171.2v5.1M205.7 173.7h2.6"/>
</g>
<path d="M253 123.8h1.1l.5-.6h1l.5 .6h1M253 124.4h1.1l.5 .5h1l.5-.5h1" fill="none" stroke="#d0a19e" stroke-width=".25"/>
<path d="M253 124.4l-1.5 1" fill="none" stroke="#d0a19e" stroke-width=".21"/>
<path d="M252.8 123.5h1l.5-.5h1l.5 .5h1.1M252.8 124.1h1l.5 .5h1l.5-.5h1.1" fill="none" stroke="#f00" stroke-width=".25"/>
<path d="M252.8 124.1l-1.3 1.3" fill="none" stroke="#f00" stroke-width=".21"/>
<path d="M159.9 60.5h8.9l1.3 1.3-1.3 1.3h-8.9z" fill-rule="evenodd" fill="#ffff80"/>
<path d="M159.9 60.5h8.9l1.3 1.3-1.3 1.3h-8.9z" fill="none" stroke="#800000" stroke-width=".21"/>
<path d="M35.3 28.7h2M43.4 28.7h2.1M221 33.8v2.6M221 38.9v2.5M22.6 46.5v2M22.6 54.7v2M32.7 54.2v2.5M22.6 61.8v2M22.6 70v2M32.7 61.8v2.5" fill="none" stroke="#000" stroke-width=".25"/>
<path d="M37.4 27.7h6v2.1h-6zM220 35.6l2.3 4.6M21.6 48.6h2v6h-2zM30.7 58.8h4M30.7 59.8h4M32.7 56.7v2.1M32.7 59.8v2M21.6 63.9h2v6h-2z" fill="none" stroke="#00f" stroke-width=".25"/>
<path d="M218.5 49.1h5M219.2 49.8h3.6M220 50.6h2M220.7 51.4h.5M221 46.5v2.6" fill="none" stroke="#800000" stroke-width=".25"/>
<path d="M219.5 34.8l1 .8-.8 .5z" fill="#00f"/>
<path d="M219 37.1h4M219 38.1h4M219.5 34.8l1 .8-.8 .5zM221 36.4v.7M221 38.1v.8" fill="none" stroke="#00f" stroke-width=".25"/>
<path d="M183.4 38.4h4v6h-4z" fill-rule="evenodd" fill="#ffffb0"/>
<path d="M183.4 38.4h4v6h-4z" fill="none" stroke="#800000" stroke-width=".21"/>
<path d="M183.9 39.4h1M184.4 38.9v1M187.4 38.4l-4 6M187.4 38.4h-4v6M187.4 38.4v6h-4" fill="none" stroke="#00f" stroke-width=".25"/>
<path d="M180.3 41.4h3M180.3 51.6h3.8M186.6 51.6h3.9M187.5 41.4h3" fill="none" stroke="#000" stroke-width=".25"/>
<path d="M173.9 36.4h2.6M175.2 36.4v2.5" fill="none" stroke="#800000" stroke-width=".25"/>
<path d="M183.9 51.6l3-2v4z" fill="#00f"/>
<path d="M183.9 51.6l3-2v4zM183.9 49.6v4M195.3 59.5v4.6M195.8 59.5v1M193 61.8h2.3M195.8 60h2.3M195.8 61.8h2.3v2.5M195.8 63.6h2.3M195.8 61.3v1M195.8 63.1v1" fill="none" stroke="#00f" stroke-width=".25"/>
<path d="M198.1 56.7v2.6M190.5 61.8h2.5M198.1 64.3v2.6" fill="none" stroke="#000" stroke-width=".25"/>
<path d="M195.8 61.8l1.5-.5v1z" fill="#00f"/>
<path d="M195.8 61.8l1.5-.5v1z" fill="none" stroke="#00f" stroke-width=".21"/>
<path d="M183.4 28.7l3.5 1.5M198.1 59.3v.7M174.2 66.4h2.1v6h-2.1z" fill="none" stroke="#00f" stroke-width=".25"/>
<path d="M172.7 79.6h5M175.2 77.1v2.5M195.5 79.6h5.1M198.1 77.1v2.5M173.4 80.4h3.6M174.2 81.1h2M174.9 81.9h.6M196.3 80.4h3.6M197.1 81.1h2M197.8 81.9h.6" fill="none" stroke="#800000" stroke-width=".25"/>
<g fill="none" stroke="#000" stroke-width=".25">
<path d="M180.3 28.7h3M185.4 21.6v.8M185.4 22.8v.8M185.4 24.1v.8M185.4 25.4v.8M185.4 26.7v.8M185.4 27.9v.8M185.4 29.2v.8M185.4 30.5v.8M185.4 31.7v.8M185.4 33v.8M185.4 34.3v.8"/>
<path d="M185.4 35.6v.8M185.4 36.8v.8M185.4 38.1v.8M185.4 39.4v.8M185.4 21.1h.8M186.6 21.1h.8M187.9 21.1h.8M189.2 21.1h.8M190.5 21.1h.8M191.7 21.1h.8M193 21.1h.8M194.3 21.1h.8"/>
<path d="M195.5 21.1h.8M196.8 21.1h.8M198.1 21.1h.8M199.4 21.1h.8M200.6 21.1h.8M201.9 21.1h.8M203.2 21.1h.8M204.4 21.1h.9M205.7 21.1h.8M207 21.1h.8M208.3 21.1h.8M209.5 21.1h.8"/>
<path d="M210.8 21.1h.8M212.1 21.1h.8M213.4 21.1h.8M214.6 21.1h.8M215.9 21.1h.8M217.2 21.1h.8M218.5 21.1h.7M219.7 21.1h.8M221 21.1h.8M222.3 21.1h.8M223.5 21.1h.8M224.8 21.1h.8"/>
<path d="M226.1 21.1h.8M227.4 21.1h.7M228.6 21.1h.8M229.9 21.1h.8M231.2 21.1v.8M231.2 22.4v.8M231.2 23.6v.8M231.2 24.9v.8M231.2 26.2v.8M231.2 27.5v.7M185.4 40.7v.7M185.4 41.9v.8"/>
<path d="M185.4 43.2v.8M175.2 64.3v2M175.2 72.5v2"/>
</g>
<path d="M186.9 30.2l.5 1.1h-1z" fill="#00f"/>
<path d="M186.4 26.2h1l-.5 1zM186.9 30.2l.5 1.1h-1zM229.2 26.2h1l-.5 1zM233.2 28.7l-3.5 1.5" fill="none" stroke="#00f" stroke-width=".25"/>
<path d="M187.5 31.3h3M187.5 26.2h3M233.2 28.7h3.1" fill="none" stroke="#000" stroke-width=".25"/>
<path d="M229.7 30.2l.5 1.1h-1z" fill="#00f"/>
<path d="M229.7 30.2l.5 1.1h-1zM179.8 60.7h6v2.1h-6z" fill="none" stroke="#00f" stroke-width=".25"/>
<path d="M226.1 26.2h3M226.1 31.3h3M177.7 61.8h2M185.9 61.8h2" fill="none" stroke="#000" stroke-width=".25"/>
<circle cx="172.7" cy="61.8" r=".51" fill="#000080"/>
<circle cx="172.7" cy="61.8" r=".51" fill="none" stroke="#000080" stroke-width=".21"/>
<path d="M172.7 59.3v2.5" fill="none" stroke="#000" stroke-width=".25"/>
<circle cx="172.7" cy="61.8" r=".51" fill="#000080"/>
<circle cx="172.7" cy="61.8" r=".51" fill="none" stroke="#000080" stroke-width=".21"/>
<g fill="none" stroke="#000" stroke-width=".25">
<path d="M195.5 26.2h2M203.7 26.2h2M210.8 33.8v2M210.8 42v2M182.8 133v2M182.8 141.2v2M182.8 153.4v2M182.8 161.6v2"/>
<circle cx="172.7" cy="58" r="1.27"/>
</g>
<path d="M197.6 25.2h6v2h-6zM209.8 35.9h2.1v6h-2.1zM181.9 135.1h2v6h-2zM181.9 155.5h2v6h-2z" fill="none" stroke="#00f" stroke-width=".25"/>
<path d="M208.3 49.1h5.1M209 49.8h3.6M209.8 50.6h2M210.6 51.4h.5M210.8 46.5v2.6M180.3 168.6h5.1M181 169.4h3.6M181.8 170.2h2M182.6 170.9h.5M182.8 166.1v2.5" fill="none" stroke="#800000" stroke-width=".25"/>
<path d="M170.1 144.5h8.9l1.3 1.3-1.3 1.2h-8.9z" fill-rule="evenodd" fill="#ffff80"/>
<path d="M170.1 144.5h8.9l1.3 1.3-1.3 1.2h-8.9z" fill="none" stroke="#800000" stroke-width=".21"/>
<path d="M181.6 127.9h2.5M182.8 127.9v2.6" fill="none" stroke="#800000" stroke-width=".25"/>
<circle cx="187.9" cy="130.5" r=".51" fill="#000080"/>
<circle cx="187.9" cy="130.5" r=".51" fill="none" stroke="#000080" stroke-width=".21"/>
<path d="M187.9 130.5h2.6" fill="none" stroke="#000" stroke-width=".25"/>
<circle cx="187.9" cy="130.5" r=".51" fill="#000080"/>
<circle cx="187.9" cy="130.5" r=".51" fill="none" stroke="#000080" stroke-width=".21"/>
<g fill="none" stroke="#000" stroke-width=".25">
<path d="M172.7 153.4v2.5M172.7 161v2.6"/>
<circle cx="191.7" cy="130.5" r="1.27"/>
</g>
<path d="M170.6 158h4.1M170.6 159h4.1M172.7 155.9v2.1M172.7 159v2" fill="none" stroke="#00f" stroke-width=".25"/>
<path d="M170.1 168.6h5.1M170.9 169.4h3.5M171.6 170.2h2.1M172.4 170.9h.5M172.7 166.1v2.5" fill="none" stroke="#800000" stroke-width=".25"/>
<path d="M68.3 28.7h22.9" fill="none" stroke="#000080" stroke-width=".25"/>
<circle cx="68.3" cy="28.7" r=".51" fill="#000080"/>
<circle cx="68.3" cy="28.7" r=".51" fill="none" stroke="#000080" stroke-width=".21"/>
<path d="M81.1 61.8h5.1" fill="none" stroke="#000080" stroke-width=".25"/>
<circle cx="86.2" cy="61.8" r=".51" fill="#000080"/>
<circle cx="86.2" cy="61.8" r=".51" fill="none" stroke="#000080" stroke-width=".21"/>
<circle cx="83.6" cy="61.8" r=".51" fill="#000080"/>
<circle cx="83.6" cy="61.8" r=".51" fill="none" stroke="#000080" stroke-width=".21"/>
<path d="M88.7 61.8h-2.5v2.5" fill="none" stroke="#000080" stroke-width=".25"/>
<circle cx="86.2" cy="61.8" r=".51" fill="#000080"/>
<circle cx="86.2" cy="61.8" r=".51" fill="none" stroke="#000080" stroke-width=".21"/>
<path d="M86.2 41.4v10.2h5" fill="none" stroke="#000080" stroke-width=".25"/>
<circle cx="86.2" cy="41.4" r=".51" fill="#000080"/>
<circle cx="86.2" cy="41.4" r=".51" fill="none" stroke="#000080" stroke-width=".21"/>
<path d="M86.2 38.9v2.5h5" fill="none" stroke="#000080" stroke-width=".25"/>
<circle cx="86.2" cy="41.4" r=".51" fill="#000080"/>
<circle cx="86.2" cy="41.4" r=".51" fill="none" stroke="#000080" stroke-width=".21"/>
<path d="M101.4 51.6h7.7M98.9 61.8h2.5" fill="none" stroke="#000080" stroke-width=".25"/>
<circle cx="109" cy="51.6" r=".51" fill="#000080"/>
<circle cx="109" cy="51.6" r=".51" fill="none" stroke="#000080" stroke-width=".21"/>
<path d="M101.4 26.2h43.3M104 31.3v5.1h10.1" fill="none" stroke="#000080" stroke-width=".25"/>
<circle cx="104" cy="31.3" r=".51" fill="#000080"/>
<circle cx="104" cy="31.3" r=".51" fill="none" stroke="#000080" stroke-width=".21"/>
<path d="M152.3 49.1v2.5h-10.2" fill="none" stroke="#000080" stroke-width=".25"/>
<circle cx="142.1" cy="51.6" r=".51" fill="#000080"/>
<circle cx="142.1" cy="51.6" r=".51" fill="none" stroke="#000080" stroke-width=".21"/>
<path d="M142.1 36.4h10.2v2.5" fill="none" stroke="#000080" stroke-width=".25"/>
<circle cx="142.1" cy="36.4" r=".51" fill="#000080"/>
<circle cx="142.1" cy="36.4" r=".51" fill="none" stroke="#000080" stroke-width=".21"/>
<path d="M27.6 28.7v2.6" fill="none" stroke="#000080" stroke-width=".25"/>
<circle cx="27.6" cy="28.7" r=".51" fill="#000080"/>
<circle cx="27.6" cy="28.7" r=".51" fill="none" stroke="#000080" stroke-width=".21"/>
<path d="M134.5 31.3v7.6M63.3 54.2v10.1M134.5 49.1v7.6M63.3 74.5v2.6M86.2 74.5v2.6M109.1 66.9v10.2" fill="none" stroke="#000080" stroke-width=".25"/>
<circle cx="134.5" cy="31.3" r=".51" fill="#000080"/>
<circle cx="134.5" cy="31.3" r=".51" fill="none" stroke="#000080" stroke-width=".21"/>
<circle cx="134.5" cy="36.4" r=".51" fill="#000080"/>
<circle cx="134.5" cy="36.4" r=".51" fill="none" stroke="#000080" stroke-width=".21"/>
<path d="M14.9 33.8v5.1M116.7 31.3h5.1M159.9 140.7v2.5" fill="none" stroke="#000080" stroke-width=".25"/>
<circle cx="159.9" cy="140.7" r=".51" fill="#000080"/>
<circle cx="159.9" cy="140.7" r=".51" fill="none" stroke="#000080" stroke-width=".21"/>
<path d="M20 140.7h-5.1v2.5" fill="none" stroke="#000080" stroke-width=".25"/>
<circle cx="14.9" cy="140.7" r=".51" fill="#000080"/>
<circle cx="14.9" cy="140.7" r=".51" fill="none" stroke="#000080" stroke-width=".21"/>
<path d="M55.6 145.7h2.6v22.9h-10.2" fill="none" stroke="#000080" stroke-width=".25"/>
<circle cx="58.2" cy="145.7" r=".51" fill="#000080"/>
<circle cx="58.2" cy="145.7" r=".51" fill="none" stroke="#000080" stroke-width=".21"/>
<path d="M144.7 140.7h2.5" fill="none" stroke="#000080" stroke-width=".25"/>
<circle cx="144.7" cy="140.7" r=".51" fill="#000080"/>
<circle cx="144.7" cy="140.7" r=".51" fill="none" stroke="#000080" stroke-width=".21"/>
<path d="M213.4 158.5v2.5" fill="none" stroke="#000080" stroke-width=".25"/>
<circle cx="213.4" cy="158.5" r=".51" fill="#000080"/>
<circle cx="213.4" cy="158.5" r=".51" fill="none" stroke="#000080" stroke-width=".21"/>
<path d="M233.7 158.5v2.5" fill="none" stroke="#000080" stroke-width=".25"/>
<circle cx="233.7" cy="158.5" r=".51" fill="#000080"/>
<circle cx="233.7" cy="158.5" r=".51" fill="none" stroke="#000080" stroke-width=".21"/>
<path d="M243.9 158.5v2.5" fill="none" stroke="#000080" stroke-width=".25"/>
<circle cx="243.9" cy="158.5" r=".51" fill="#000080"/>
<circle cx="243.9" cy="158.5" r=".51" fill="none" stroke="#000080" stroke-width=".21"/>
<path d="M14.9 138.1v2.6M14.9 153.4v2.5" fill="none" stroke="#000080" stroke-width=".25"/>
<circle cx="14.9" cy="140.7" r=".51" fill="#000080"/>
<circle cx="14.9" cy="140.7" r=".51" fill="none" stroke="#000080" stroke-width=".21"/>
<path d="M254.1 158.5v2.5" fill="none" stroke="#000080" stroke-width=".25"/>
<circle cx="254.1" cy="158.5" r=".51" fill="#000080"/>
<circle cx="254.1" cy="158.5" r=".51" fill="none" stroke="#000080" stroke-width=".21"/>
<path d="M45.5 122.9h2.5M58.2 145.7h2.5M144.7 176.3v2.5" fill="none" stroke="#000080" stroke-width=".25"/>
<circle cx="58.2" cy="145.7" r=".51" fill="#000080"/>
<circle cx="58.2" cy="145.7" r=".51" fill="none" stroke="#000080" stroke-width=".21"/>
<path d="M35.3 122.9h-20.4v5M81.1 145.7v15.3M124.3 145.7v2.6" fill="none" stroke="#000080" stroke-width=".25"/>
<circle cx="124.3" cy="145.7" r=".51" fill="#000080"/>
<circle cx="124.3" cy="145.7" r=".51" fill="none" stroke="#000080" stroke-width=".21"/>
<path d="M131.9 127.9h2.6v5.1M124.3 158.5v5.1" fill="none" stroke="#000080" stroke-width=".25"/>
<circle cx="134.5" cy="133" r=".51" fill="#000080"/>
<circle cx="134.5" cy="133" r=".51" fill="none" stroke="#000080" stroke-width=".21"/>
<path d="M78.5 115.2h2.6" fill="none" stroke="#000080" stroke-width=".25"/>
<circle cx="78.5" cy="115.2" r=".51" fill="#000080"/>
<circle cx="78.5" cy="115.2" r=".51" fill="none" stroke="#000080" stroke-width=".21"/>
<path d="M78.5 112.7h2.6" fill="none" stroke="#000080" stroke-width=".25"/>
<circle cx="78.5" cy="112.7" r=".51" fill="#000080"/>
<circle cx="78.5" cy="112.7" r=".51" fill="none" stroke="#000080" stroke-width=".21"/>
<path d="M73.4 145.7v2.6" fill="none" stroke="#000080" stroke-width=".25"/>
<circle cx="73.4" cy="145.7" r=".51" fill="#000080"/>
<circle cx="73.4" cy="145.7" r=".51" fill="none" stroke="#000080" stroke-width=".21"/>
<path d="M73.4 158.5v2.5M144.7 163.6h7.6v7.6h2.5M159.9 176.3v2.5" fill="none" stroke="#000080" stroke-width=".25"/>
<circle cx="144.7" cy="163.6" r=".51" fill="#000080"/>
<circle cx="144.7" cy="163.6" r=".51" fill="none" stroke="#000080" stroke-width=".21"/>
<path d="M243.9 186.5v2.5" fill="none" stroke="#000080" stroke-width=".25"/>
<circle cx="243.9" cy="189" r=".51" fill="#000080"/>
<circle cx="243.9" cy="189" r=".51" fill="none" stroke="#000080" stroke-width=".21"/>
<path d="M233.7 186.5v2.5" fill="none" stroke="#000080" stroke-width=".25"/>
<circle cx="233.7" cy="189" r=".51" fill="#000080"/>
<circle cx="233.7" cy="189" r=".51" fill="none" stroke="#000080" stroke-width=".21"/>
<path d="M223.5 186.5v2.5" fill="none" stroke="#000080" stroke-width=".25"/>
<circle cx="223.5" cy="189" r=".51" fill="#000080"/>
<circle cx="223.5" cy="189" r=".51" fill="none" stroke="#000080" stroke-width=".21"/>
<path d="M144.7 122.9v5" fill="none" stroke="#000080" stroke-width=".25"/>
<circle cx="144.7" cy="122.9" r=".51" fill="#000080"/>
<circle cx="144.7" cy="122.9" r=".51" fill="none" stroke="#000080" stroke-width=".21"/>
<path d="M65.8 122.9v5h2.5M78.5 127.9h2.6" fill="none" stroke="#000080" stroke-width=".25"/>
<circle cx="65.8" cy="122.9" r=".51" fill="#000080"/>
<circle cx="65.8" cy="122.9" r=".51" fill="none" stroke="#000080" stroke-width=".21"/>
<path d="M121.8 140.7h12.7" fill="none" stroke="#000080" stroke-width=".25"/>
<circle cx="134.5" cy="140.7" r=".51" fill="#000080"/>
<circle cx="134.5" cy="140.7" r=".51" fill="none" stroke="#000080" stroke-width=".21"/>
<path d="M185.4 115.2h10.1M185.4 112.7h10.1M165 122.9h30.5M193 140.7h2.5" fill="none" stroke="#000080" stroke-width=".25"/>
<circle cx="193" cy="140.7" r=".51" fill="#000080"/>
<circle cx="193" cy="140.7" r=".51" fill="none" stroke="#000080" stroke-width=".21"/>
<path d="M241.3 110.1h5.1M241.3 130.5h2.6" fill="none" stroke="#000080" stroke-width=".25"/>
<circle cx="246.4" cy="110.1" r=".51" fill="#000080"/>
<circle cx="246.4" cy="110.1" r=".51" fill="none" stroke="#000080" stroke-width=".21"/>
<path d="M193 143.2v2.6" fill="none" stroke="#000080" stroke-width=".25"/>
<circle cx="193" cy="143.2" r=".51" fill="#000080"/>
<circle cx="193" cy="143.2" r=".51" fill="none" stroke="#000080" stroke-width=".21"/>
<path d="M193 107.6v2.5" fill="none" stroke="#000080" stroke-width=".25"/>
<circle cx="193" cy="110.1" r=".51" fill="#000080"/>
<circle cx="193" cy="110.1" r=".51" fill="none" stroke="#000080" stroke-width=".21"/>
<path d="M78.5 107.6v10.2h2.6" fill="none" stroke="#000080" stroke-width=".25"/>
<circle cx="78.5" cy="115.2" r=".51" fill="#000080"/>
<circle cx="78.5" cy="115.2" r=".51" fill="none" stroke="#000080" stroke-width=".21"/>
<circle cx="78.5" cy="112.7" r=".51" fill="#000080"/>
<circle cx="78.5" cy="112.7" r=".51" fill="none" stroke="#000080" stroke-width=".21"/>
<path d="M195.5 138.1h-2.5v5.1h2.5" fill="none" stroke="#000080" stroke-width=".25"/>
<circle cx="193" cy="140.7" r=".51" fill="#000080"/>
<circle cx="193" cy="140.7" r=".51" fill="none" stroke="#000080" stroke-width=".21"/>
<circle cx="193" cy="143.2" r=".51" fill="#000080"/>
<circle cx="193" cy="143.2" r=".51" fill="none" stroke="#000080" stroke-width=".21"/>
<path d="M246.4 107.6v5.1h-5.1M251.5 112.7v2.5h-10.2" fill="none" stroke="#000080" stroke-width=".25"/>
<circle cx="246.4" cy="110.1" r=".51" fill="#000080"/>
<circle cx="246.4" cy="110.1" r=".51" fill="none" stroke="#000080" stroke-width=".21"/>
<path d="M159.9 138.1v2.6h-2.5" fill="none" stroke="#000080" stroke-width=".25"/>
<circle cx="159.9" cy="140.7" r=".51" fill="#000080"/>
<circle cx="159.9" cy="140.7" r=".51" fill="none" stroke="#000080" stroke-width=".21"/>
<path d="M256.6 125.4v15.3h-2.5M271.9 122.9h2.5M271.9 125.4h2.5" fill="none" stroke="#000080" stroke-width=".25"/>
<circle cx="256.6" cy="125.4" r=".51" fill="#000080"/>
<circle cx="256.6" cy="125.4" r=".51" fill="none" stroke="#000080" stroke-width=".21"/>
<path d="M274.4 77.1v2.5" fill="none" stroke="#000080" stroke-width=".25"/>
<circle cx="274.4" cy="77.1" r=".51" fill="#000080"/>
<circle cx="274.4" cy="77.1" r=".51" fill="none" stroke="#000080" stroke-width=".21"/>
<path d="M259.2 77.1h-7.7v2.5" fill="none" stroke="#000080" stroke-width=".25"/>
<circle cx="259.1" cy="77.1" r=".51" fill="#000080"/>
<circle cx="259.1" cy="77.1" r=".51" fill="none" stroke="#000080" stroke-width=".21"/>
<path d="M266.8 77.1h-7.6v2.5" fill="none" stroke="#000080" stroke-width=".25"/>
<circle cx="259.1" cy="77.1" r=".51" fill="#000080"/>
<circle cx="259.1" cy="77.1" r=".51" fill="none" stroke="#000080" stroke-width=".21"/>
<circle cx="266.8" cy="77.1" r=".51" fill="#000080"/>
<circle cx="266.8" cy="77.1" r=".51" fill="none" stroke="#000080" stroke-width=".21"/>
<path d="M236.3 74.5v5.1M223.5 158.5h40.7v2.5" fill="none" stroke="#000080" stroke-width=".25"/>
<circle cx="223.5" cy="158.5" r=".51" fill="#000080"/>
<circle cx="223.5" cy="158.5" r=".51" fill="none" stroke="#000080" stroke-width=".21"/>
<circle cx="233.7" cy="158.5" r=".51" fill="#000080"/>
<circle cx="233.7" cy="158.5" r=".51" fill="none" stroke="#000080" stroke-width=".21"/>
<circle cx="243.9" cy="158.5" r=".51" fill="#000080"/>
<circle cx="243.9" cy="158.5" r=".51" fill="none" stroke="#000080" stroke-width=".21"/>
<circle cx="254.1" cy="158.5" r=".51" fill="#000080"/>
<circle cx="254.1" cy="158.5" r=".51" fill="none" stroke="#000080" stroke-width=".21"/>
<path d="M205.7 158.5h17.8v2.5" fill="none" stroke="#000080" stroke-width=".25"/>
<circle cx="213.4" cy="158.5" r=".51" fill="#000080"/>
<circle cx="213.4" cy="158.5" r=".51" fill="none" stroke="#000080" stroke-width=".21"/>
<circle cx="223.5" cy="158.5" r=".51" fill="#000080"/>
<circle cx="223.5" cy="158.5" r=".51" fill="none" stroke="#000080" stroke-width=".21"/>
<path d="M58.2 122.9h22.9" fill="none" stroke="#000080" stroke-width=".25"/>
<circle cx="65.8" cy="122.9" r=".51" fill="#000080"/>
<circle cx="65.8" cy="122.9" r=".51" fill="none" stroke="#000080" stroke-width=".21"/>
<path d="M121.8 145.7h7.6v2.6" fill="none" stroke="#000080" stroke-width=".25"/>
<circle cx="124.3" cy="145.7" r=".51" fill="#000080"/>
<circle cx="124.3" cy="145.7" r=".51" fill="none" stroke="#000080" stroke-width=".21"/>
<path d="M121.8 133h12.7v5.1h-12.7" fill="none" stroke="#000080" stroke-width=".25"/>
<circle cx="134.5" cy="138.1" r=".51" fill="#000080"/>
<circle cx="134.5" cy="138.1" r=".51" fill="none" stroke="#000080" stroke-width=".21"/>
<circle cx="134.5" cy="133" r=".51" fill="#000080"/>
<circle cx="134.5" cy="133" r=".51" fill="none" stroke="#000080" stroke-width=".21"/>
<path d="M134.5 138.1v2.6" fill="none" stroke="#000080" stroke-width=".25"/>
<circle cx="134.5" cy="140.7" r=".51" fill="#000080"/>
<circle cx="134.5" cy="140.7" r=".51" fill="none" stroke="#000080" stroke-width=".21"/>
<circle cx="134.5" cy="138.1" r=".51" fill="#000080"/>
<circle cx="134.5" cy="138.1" r=".51" fill="none" stroke="#000080" stroke-width=".21"/>
<path d="M134.5 140.7v2.5h-12.7" fill="none" stroke="#000080" stroke-width=".25"/>
<circle cx="134.5" cy="143.2" r=".51" fill="#000080"/>
<circle cx="134.5" cy="143.2" r=".51" fill="none" stroke="#000080" stroke-width=".21"/>
<circle cx="134.5" cy="140.7" r=".51" fill="#000080"/>
<circle cx="134.5" cy="140.7" r=".51" fill="none" stroke="#000080" stroke-width=".21"/>
<path d="M134.5 143.2v20.4" fill="none" stroke="#000080" stroke-width=".25"/>
<circle cx="134.5" cy="161" r=".51" fill="#000080"/>
<circle cx="134.5" cy="161" r=".51" fill="none" stroke="#000080" stroke-width=".21"/>
<circle cx="134.5" cy="143.2" r=".51" fill="#000080"/>
<circle cx="134.5" cy="143.2" r=".51" fill="none" stroke="#000080" stroke-width=".21"/>
<path d="M129.4 158.5v2.5h5.1" fill="none" stroke="#000080" stroke-width=".25"/>
<circle cx="134.5" cy="161" r=".51" fill="#000080"/>
<circle cx="134.5" cy="161" r=".51" fill="none" stroke="#000080" stroke-width=".21"/>
<path d="M121.8 122.9h33" fill="none" stroke="#000080" stroke-width=".25"/>
<circle cx="144.7" cy="122.9" r=".51" fill="#000080"/>
<circle cx="144.7" cy="122.9" r=".51" fill="none" stroke="#000080" stroke-width=".21"/>
<path d="M144.7 145.8h-5.1v30.5h-119.6v-7.7h17.8" fill="none" stroke="#000080" stroke-width=".25"/>
<circle cx="144.7" cy="145.7" r=".51" fill="#000080"/>
<circle cx="144.7" cy="145.7" r=".51" fill="none" stroke="#000080" stroke-width=".21"/>
<circle cx="20" cy="168.6" r=".51" fill="#000080"/>
<circle cx="20" cy="168.6" r=".51" fill="none" stroke="#000080" stroke-width=".21"/>
<path d="M20 150.8v17.8" fill="none" stroke="#000080" stroke-width=".25"/>
<circle cx="20" cy="168.6" r=".51" fill="#000080"/>
<circle cx="20" cy="168.6" r=".51" fill="none" stroke="#000080" stroke-width=".21"/>
<path d="M81.1 133h-7.7v12.7h-2.5" fill="none" stroke="#000080" stroke-width=".25"/>
<circle cx="73.4" cy="145.7" r=".51" fill="#000080"/>
<circle cx="73.4" cy="145.7" r=".51" fill="none" stroke="#000080" stroke-width=".21"/>
<path d="M144.7 161v5.1" fill="none" stroke="#000080" stroke-width=".25"/>
<circle cx="144.7" cy="163.6" r=".51" fill="#000080"/>
<circle cx="144.7" cy="163.6" r=".51" fill="none" stroke="#000080" stroke-width=".21"/>
<path d="M144.7 138.1v12.7" fill="none" stroke="#000080" stroke-width=".25"/>
<circle cx="144.7" cy="140.7" r=".51" fill="#000080"/>
<circle cx="144.7" cy="140.7" r=".51" fill="none" stroke="#000080" stroke-width=".21"/>
<circle cx="144.7" cy="145.7" r=".51" fill="#000080"/>
<circle cx="144.7" cy="145.7" r=".51" fill="none" stroke="#000080" stroke-width=".21"/>
<path d="M259.2 122.9v17.8h2.5" fill="none" stroke="#000080" stroke-width=".25"/>
<circle cx="259.1" cy="122.9" r=".51" fill="#000080"/>
<circle cx="259.1" cy="122.9" r=".51" fill="none" stroke="#000080" stroke-width=".21"/>
<path d="M241.3 125.4h20.4" fill="none" stroke="#000080" stroke-width=".25"/>
<circle cx="256.6" cy="125.4" r=".51" fill="#000080"/>
<circle cx="256.6" cy="125.4" r=".51" fill="none" stroke="#000080" stroke-width=".21"/>
<path d="M241.3 122.9h20.4" fill="none" stroke="#000080" stroke-width=".25"/>
<circle cx="259.1" cy="122.9" r=".51" fill="#000080"/>
<circle cx="259.1" cy="122.9" r=".51" fill="none" stroke="#000080" stroke-width=".21"/>
<path d="M264.2 171.2v5.1" fill="none" stroke="#000080" stroke-width=".25"/>
<circle cx="264.2" cy="173.7" r=".51" fill="#000080"/>
<circle cx="264.2" cy="173.7" r=".51" fill="none" stroke="#000080" stroke-width=".21"/>
<path d="M254.1 173.7h10.1" fill="none" stroke="#000080" stroke-width=".25"/>
<circle cx="264.2" cy="173.7" r=".51" fill="#000080"/>
<circle cx="264.2" cy="173.7" r=".51" fill="none" stroke="#000080" stroke-width=".21"/>
<circle cx="254.1" cy="173.7" r=".51" fill="#000080"/>
<circle cx="254.1" cy="173.7" r=".51" fill="none" stroke="#000080" stroke-width=".21"/>
<path d="M243.9 173.7h10.2" fill="none" stroke="#000080" stroke-width=".25"/>
<circle cx="254.1" cy="173.7" r=".51" fill="#000080"/>
<circle cx="254.1" cy="173.7" r=".51" fill="none" stroke="#000080" stroke-width=".21"/>
<circle cx="243.9" cy="173.7" r=".51" fill="#000080"/>
<circle cx="243.9" cy="173.7" r=".51" fill="none" stroke="#000080" stroke-width=".21"/>
<path d="M233.7 173.7h10.2" fill="none" stroke="#000080" stroke-width=".25"/>
<circle cx="243.9" cy="173.7" r=".51" fill="#000080"/>
<circle cx="243.9" cy="173.7" r=".51" fill="none" stroke="#000080" stroke-width=".21"/>
<circle cx="233.7" cy="173.7" r=".51" fill="#000080"/>
<circle cx="233.7" cy="173.7" r=".51" fill="none" stroke="#000080" stroke-width=".21"/>
<path d="M223.5 173.7h10.2" fill="none" stroke="#000080" stroke-width=".25"/>
<circle cx="233.7" cy="173.7" r=".51" fill="#000080"/>
<circle cx="233.7" cy="173.7" r=".51" fill="none" stroke="#000080" stroke-width=".21"/>
<circle cx="223.5" cy="173.7" r=".51" fill="#000080"/>
<circle cx="223.5" cy="173.7" r=".51" fill="none" stroke="#000080" stroke-width=".21"/>
<path d="M213.4 173.7h10.1" fill="none" stroke="#000080" stroke-width=".25"/>
<circle cx="223.5" cy="173.7" r=".51" fill="#000080"/>
<circle cx="223.5" cy="173.7" r=".51" fill="none" stroke="#000080" stroke-width=".21"/>
<circle cx="213.4" cy="173.7" r=".51" fill="#000080"/>
<circle cx="213.4" cy="173.7" r=".51" fill="none" stroke="#000080" stroke-width=".21"/>
<path d="M208.3 173.7h5.1" fill="none" stroke="#000080" stroke-width=".25"/>
<circle cx="213.4" cy="173.7" r=".51" fill="#000080"/>
<circle cx="213.4" cy="173.7" r=".51" fill="none" stroke="#000080" stroke-width=".21"/>
<path d="M264.2 186.5v2.5h-58.5" fill="none" stroke="#000080" stroke-width=".25"/>
<circle cx="213.4" cy="189" r=".51" fill="#000080"/>
<circle cx="213.4" cy="189" r=".51" fill="none" stroke="#000080" stroke-width=".21"/>
<circle cx="223.5" cy="189" r=".51" fill="#000080"/>
<circle cx="223.5" cy="189" r=".51" fill="none" stroke="#000080" stroke-width=".21"/>
<circle cx="233.7" cy="189" r=".51" fill="#000080"/>
<circle cx="233.7" cy="189" r=".51" fill="none" stroke="#000080" stroke-width=".21"/>
<circle cx="243.9" cy="189" r=".51" fill="#000080"/>
<circle cx="243.9" cy="189" r=".51" fill="none" stroke="#000080" stroke-width=".21"/>
<circle cx="254.1" cy="189" r=".51" fill="#000080"/>
<circle cx="254.1" cy="189" r=".51" fill="none" stroke="#000080" stroke-width=".21"/>
<path d="M213.4 186.5v2.5" fill="none" stroke="#000080" stroke-width=".25"/>
<circle cx="213.4" cy="189" r=".51" fill="#000080"/>
<circle cx="213.4" cy="189" r=".51" fill="none" stroke="#000080" stroke-width=".21"/>
<path d="M254.1 186.5v2.5" fill="none" stroke="#000080" stroke-width=".25"/>
<circle cx="254.1" cy="189" r=".51" fill="#000080"/>
<circle cx="254.1" cy="189" r=".51" fill="none" stroke="#000080" stroke-width=".21"/>
<path d="M213.4 171.2v5.1" fill="none" stroke="#000080" stroke-width=".25"/>
<circle cx="213.4" cy="173.7" r=".51" fill="#000080"/>
<circle cx="213.4" cy="173.7" r=".51" fill="none" stroke="#000080" stroke-width=".21"/>
<path d="M223.5 171.2v5.1" fill="none" stroke="#000080" stroke-width=".25"/>
<circle cx="223.5" cy="173.7" r=".51" fill="#000080"/>
<circle cx="223.5" cy="173.7" r=".51" fill="none" stroke="#000080" stroke-width=".21"/>
<path d="M233.7 171.2v5.1" fill="none" stroke="#000080" stroke-width=".25"/>
<circle cx="233.7" cy="173.7" r=".51" fill="#000080"/>
<circle cx="233.7" cy="173.7" r=".51" fill="none" stroke="#000080" stroke-width=".21"/>
<path d="M243.9 171.2v5.1" fill="none" stroke="#000080" stroke-width=".25"/>
<circle cx="243.9" cy="173.7" r=".51" fill="#000080"/>
<circle cx="243.9" cy="173.7" r=".51" fill="none" stroke="#000080" stroke-width=".21"/>
<path d="M254.1 171.2v5.1" fill="none" stroke="#000080" stroke-width=".25"/>
<circle cx="254.1" cy="173.7" r=".51" fill="#000080"/>
<circle cx="254.1" cy="173.7" r=".51" fill="none" stroke="#000080" stroke-width=".21"/>
<path d="M185.4 110.1h10.1" fill="none" stroke="#000080" stroke-width=".25"/>
<circle cx="187.9" cy="110.1" r=".51" fill="#000080"/>
<circle cx="187.9" cy="110.1" r=".51" fill="none" stroke="#000080" stroke-width=".21"/>
<circle cx="193" cy="110.1" r=".51" fill="#000080"/>
<circle cx="193" cy="110.1" r=".51" fill="none" stroke="#000080" stroke-width=".21"/>
<path d="M58.2 54.2v12.7" fill="none" stroke="#000080" stroke-width=".25"/>
<circle cx="58.2" cy="56.7" r=".51" fill="#000080"/>
<circle cx="58.2" cy="56.7" r=".51" fill="none" stroke="#000080" stroke-width=".21"/>
<path d="M53.1 28.7v10.2h5.1v5.1" fill="none" stroke="#000080" stroke-width=".25"/>
<circle cx="53.1" cy="28.7" r=".51" fill="#000080"/>
<circle cx="53.1" cy="28.7" r=".51" fill="none" stroke="#000080" stroke-width=".21"/>
<path d="M65.8 28.7h2.5v10.2h-5v5.1" fill="none" stroke="#000080" stroke-width=".25"/>
<circle cx="68.3" cy="28.7" r=".51" fill="#000080"/>
<circle cx="68.3" cy="28.7" r=".51" fill="none" stroke="#000080" stroke-width=".21"/>
<path d="M32.7 64.3v7.7h-5.1" fill="none" stroke="#000080" stroke-width=".25"/>
<circle cx="27.6" cy="72" r=".51" fill="#000080"/>
<circle cx="27.6" cy="72" r=".51" fill="none" stroke="#000080" stroke-width=".21"/>
<path d="M22.6 56.7v5.1M22.6 72v2.5h5" fill="none" stroke="#000080" stroke-width=".25"/>
<circle cx="27.6" cy="74.5" r=".51" fill="#000080"/>
<circle cx="27.6" cy="74.5" r=".51" fill="none" stroke="#000080" stroke-width=".21"/>
<path d="M101.4 41.4h7.7v15.3" fill="none" stroke="#000080" stroke-width=".25"/>
<circle cx="109" cy="51.6" r=".51" fill="#000080"/>
<circle cx="109" cy="51.6" r=".51" fill="none" stroke="#000080" stroke-width=".21"/>
<path d="M154.8 28.7h25.5M142.1 49.1v7.6" fill="none" stroke="#000080" stroke-width=".25"/>
<circle cx="142.1" cy="51.6" r=".51" fill="#000080"/>
<circle cx="142.1" cy="51.6" r=".51" fill="none" stroke="#000080" stroke-width=".21"/>
<path d="M142.1 31.3v7.6" fill="none" stroke="#000080" stroke-width=".25"/>
<circle cx="142.1" cy="36.4" r=".51" fill="#000080"/>
<circle cx="142.1" cy="36.4" r=".51" fill="none" stroke="#000080" stroke-width=".21"/>
<circle cx="142.1" cy="31.3" r=".51" fill="#000080"/>
<circle cx="142.1" cy="31.3" r=".51" fill="none" stroke="#000080" stroke-width=".21"/>
<path d="M27.6 46.5h5.1v7.7" fill="none" stroke="#000080" stroke-width=".25"/>
<circle cx="27.6" cy="46.5" r=".51" fill="#000080"/>
<circle cx="27.6" cy="46.5" r=".51" fill="none" stroke="#000080" stroke-width=".21"/>
<path d="M27.6 41.4v12.8" fill="none" stroke="#000080" stroke-width=".25"/>
<circle cx="27.6" cy="46.5" r=".51" fill="#000080"/>
<circle cx="27.6" cy="46.5" r=".51" fill="none" stroke="#000080" stroke-width=".21"/>
<circle cx="27.6" cy="44" r=".51" fill="#000080"/>
<circle cx="27.6" cy="44" r=".51" fill="none" stroke="#000080" stroke-width=".21"/>
<path d="M27.6 44h-5v2.5" fill="none" stroke="#000080" stroke-width=".25"/>
<circle cx="27.6" cy="44" r=".51" fill="#000080"/>
<circle cx="27.6" cy="44" r=".51" fill="none" stroke="#000080" stroke-width=".21"/>
<path d="M27.6 64.3v12.8" fill="none" stroke="#000080" stroke-width=".25"/>
<circle cx="27.6" cy="74.5" r=".51" fill="#000080"/>
<circle cx="27.6" cy="74.5" r=".51" fill="none" stroke="#000080" stroke-width=".21"/>
<circle cx="27.6" cy="72" r=".51" fill="#000080"/>
<circle cx="27.6" cy="72" r=".51" fill="none" stroke="#000080" stroke-width=".21"/>
<path d="M45.5 28.7h7.6" fill="none" stroke="#000080" stroke-width=".25"/>
<circle cx="53.1" cy="28.7" r=".51" fill="#000080"/>
<circle cx="53.1" cy="28.7" r=".51" fill="none" stroke="#000080" stroke-width=".21"/>
<path d="M53.1 28.7h2.5" fill="none" stroke="#000080" stroke-width=".25"/>
<circle cx="53.1" cy="28.7" r=".51" fill="#000080"/>
<circle cx="53.1" cy="28.7" r=".51" fill="none" stroke="#000080" stroke-width=".21"/>
<path d="M20 28.7h15.3" fill="none" stroke="#000080" stroke-width=".25"/>
<circle cx="27.6" cy="28.7" r=".51" fill="#000080"/>
<circle cx="27.6" cy="28.7" r=".51" fill="none" stroke="#000080" stroke-width=".21"/>
<path d="M221 31.3v2.5M221 41.4v5.1" fill="none" stroke="#000080" stroke-width=".25"/>
<circle cx="221" cy="31.3" r=".51" fill="#000080"/>
<circle cx="221" cy="31.3" r=".51" fill="none" stroke="#000080" stroke-width=".21"/>
<path d="M170.1 61.8h5.1" fill="none" stroke="#000080" stroke-width=".25"/>
<circle cx="175.2" cy="61.8" r=".51" fill="#000080"/>
<circle cx="175.2" cy="61.8" r=".51" fill="none" stroke="#000080" stroke-width=".21"/>
<circle cx="172.7" cy="61.8" r=".51" fill="#000080"/>
<circle cx="172.7" cy="61.8" r=".51" fill="none" stroke="#000080" stroke-width=".21"/>
<path d="M177.7 61.8h-2.5v2.5" fill="none" stroke="#000080" stroke-width=".25"/>
<circle cx="175.2" cy="61.8" r=".51" fill="#000080"/>
<circle cx="175.2" cy="61.8" r=".51" fill="none" stroke="#000080" stroke-width=".21"/>
<path d="M175.2 41.4v10.2h5.1" fill="none" stroke="#000080" stroke-width=".25"/>
<circle cx="175.2" cy="41.4" r=".51" fill="#000080"/>
<circle cx="175.2" cy="41.4" r=".51" fill="none" stroke="#000080" stroke-width=".21"/>
<path d="M175.2 38.9v2.5h5.1" fill="none" stroke="#000080" stroke-width=".25"/>
<circle cx="175.2" cy="41.4" r=".51" fill="#000080"/>
<circle cx="175.2" cy="41.4" r=".51" fill="none" stroke="#000080" stroke-width=".21"/>
<path d="M190.5 51.6h7.6M187.9 61.8h2.6" fill="none" stroke="#000080" stroke-width=".25"/>
<circle cx="198.1" cy="51.6" r=".51" fill="#000080"/>
<circle cx="198.1" cy="51.6" r=".51" fill="none" stroke="#000080" stroke-width=".21"/>
<path d="M190.5 41.4h7.6v15.3M175.2 74.5v2.6M198.1 66.9v10.2" fill="none" stroke="#000080" stroke-width=".25"/>
<circle cx="198.1" cy="51.6" r=".51" fill="#000080"/>
<circle cx="198.1" cy="51.6" r=".51" fill="none" stroke="#000080" stroke-width=".21"/>
<path d="M101.4 31.3h5.1M236.3 28.7h15.2" fill="none" stroke="#000080" stroke-width=".25"/>
<circle cx="104" cy="31.3" r=".51" fill="#000080"/>
<circle cx="104" cy="31.3" r=".51" fill="none" stroke="#000080" stroke-width=".21"/>
<path d="M131.9 31.3h12.8" fill="none" stroke="#000080" stroke-width=".25"/>
<circle cx="134.5" cy="31.3" r=".51" fill="#000080"/>
<circle cx="134.5" cy="31.3" r=".51" fill="none" stroke="#000080" stroke-width=".21"/>
<circle cx="142.1" cy="31.3" r=".51" fill="#000080"/>
<circle cx="142.1" cy="31.3" r=".51" fill="none" stroke="#000080" stroke-width=".21"/>
<path d="M124.3 36.4h10.2" fill="none" stroke="#000080" stroke-width=".25"/>
<circle cx="134.5" cy="36.4" r=".51" fill="#000080"/>
<circle cx="134.5" cy="36.4" r=".51" fill="none" stroke="#000080" stroke-width=".21"/>
<path d="M205.7 26.2h5.1v7.6" fill="none" stroke="#000080" stroke-width=".25"/>
<circle cx="210.8" cy="26.2" r=".51" fill="#000080"/>
<circle cx="210.8" cy="26.2" r=".51" fill="none" stroke="#000080" stroke-width=".21"/>
<path d="M210.8 26.2h15.3" fill="none" stroke="#000080" stroke-width=".25"/>
<circle cx="210.8" cy="26.2" r=".51" fill="#000080"/>
<circle cx="210.8" cy="26.2" r=".51" fill="none" stroke="#000080" stroke-width=".21"/>
<path d="M190.5 31.3h35.6M190.5 26.2h5M210.8 44v2.5" fill="none" stroke="#000080" stroke-width=".25"/>
<circle cx="221" cy="31.3" r=".51" fill="#000080"/>
<circle cx="221" cy="31.3" r=".51" fill="none" stroke="#000080" stroke-width=".21"/>
<path d="M282 74.5v2.6h-15.2v2.5" fill="none" stroke="#000080" stroke-width=".25"/>
<circle cx="266.8" cy="77.1" r=".51" fill="#000080"/>
<circle cx="266.8" cy="77.1" r=".51" fill="none" stroke="#000080" stroke-width=".21"/>
<circle cx="274.4" cy="77.1" r=".51" fill="#000080"/>
<circle cx="274.4" cy="77.1" r=".51" fill="none" stroke="#000080" stroke-width=".21"/>
<path d="M182.8 130.5v2.5M195.5 125.4h-7.6v22.9h-5.1M182.8 163.6v2.5" fill="none" stroke="#000080" stroke-width=".25"/>
<circle cx="187.9" cy="130.5" r=".51" fill="#000080"/>
<circle cx="187.9" cy="130.5" r=".51" fill="none" stroke="#000080" stroke-width=".21"/>
<circle cx="182.8" cy="148.3" r=".51" fill="#000080"/>
<circle cx="182.8" cy="148.3" r=".51" fill="none" stroke="#000080" stroke-width=".21"/>
<path d="M182.8 148.3v5.1" fill="none" stroke="#000080" stroke-width=".25"/>
<circle cx="182.8" cy="150.8" r=".51" fill="#000080"/>
<circle cx="182.8" cy="150.8" r=".51" fill="none" stroke="#000080" stroke-width=".21"/>
<circle cx="182.8" cy="148.3" r=".51" fill="#000080"/>
<circle cx="182.8" cy="148.3" r=".51" fill="none" stroke="#000080" stroke-width=".21"/>
<path d="M180.3 145.8h2.5" fill="none" stroke="#000080" stroke-width=".25"/>
<circle cx="182.8" cy="145.8" r=".51" fill="#000080"/>
<circle cx="182.8" cy="145.8" r=".51" fill="none" stroke="#000080" stroke-width=".21"/>
<path d="M182.8 143.2v5.1" fill="none" stroke="#000080" stroke-width=".25"/>
<circle cx="182.8" cy="148.3" r=".51" fill="#000080"/>
<circle cx="182.8" cy="148.3" r=".51" fill="none" stroke="#000080" stroke-width=".21"/>
<circle cx="182.8" cy="145.8" r=".51" fill="#000080"/>
<circle cx="182.8" cy="145.8" r=".51" fill="none" stroke="#000080" stroke-width=".21"/>
<path d="M182.8 150.8h-10.1v2.6" fill="none" stroke="#000080" stroke-width=".25"/>
<circle cx="182.8" cy="150.8" r=".51" fill="#000080"/>
<circle cx="182.8" cy="150.8" r=".51" fill="none" stroke="#000080" stroke-width=".21"/>
<path d="M172.7 163.6v2.5" fill="none" stroke="#000080" stroke-width=".25"/>
<use href="#words"/>
</svg>
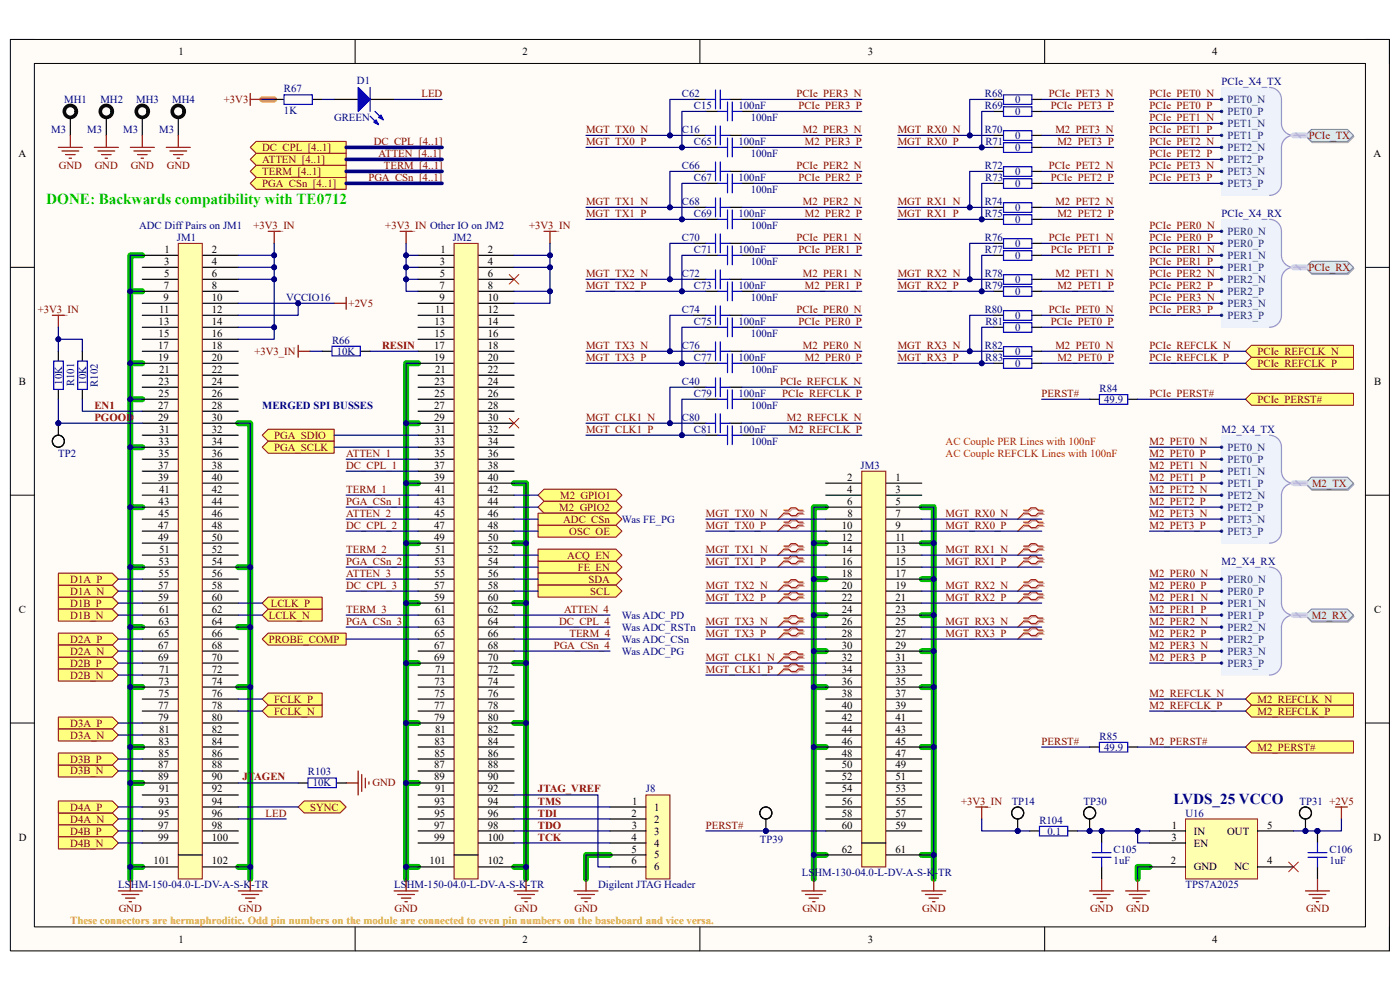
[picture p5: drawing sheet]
<svg xmlns="http://www.w3.org/2000/svg" width="297mm" height="210mm" viewBox="0 0 297 210" stroke-linecap="round" stroke-linejoin="round" font-family="sans-serif">
<defs><g id="words">
<text font-size="3.2" fill="#0f0" x="9.8" y="43.3">DONE: Backwards compatibility with TE0712</text>
<text font-size="3.2" fill="#000080" x="249" y="170.5">LVDS_25 VCCO</text>
<g font-size="2.3">
<text x="37.9" y="11.7">1</text>
<text x="110.9" y="11.7">2</text>
<text x="184.1" y="11.7">3</text>
<text x="257.1" y="11.7">4</text>
<text x="3.9" y="33.3">A</text>
<text x="291.4" y="33.3">A</text>
<text x="34.9" y="53.6">1</text>
<text x="45" y="53.6">2</text>
<text x="93.4" y="53.6">1</text>
<text x="103.5" y="53.6">2</text>
<text x="34.8" y="58.7">5</text>
<text x="34.8" y="56.2">3</text>
<text x="45" y="56.2">4</text>
<text x="45" y="58.7">6</text>
<text x="93.3" y="58.7">5</text>
<text x="93.3" y="56.2">3</text>
<text x="103.5" y="56.2">4</text>
<text x="103.5" y="58.7">6</text>
<text x="34.7" y="63.8">9</text>
<text x="34.8" y="61.3">7</text>
<text x="45" y="61.3">8</text>
<text x="45" y="63.8">10</text>
<text x="93.3" y="61.3">7</text>
<text x="93.3" y="63.8">9</text>
<text x="103.5" y="61.3">8</text>
<text x="103.5" y="63.8">10</text>
<text x="33.7" y="68.9">13</text>
<text x="33.7" y="71.5">15</text>
<text x="33.8" y="66.4">11</text>
<text x="45" y="66.4">12</text>
<text x="45" y="68.9">14</text>
<text x="45" y="71.5">16</text>
<text x="92.2" y="71.5">15</text>
<text x="92.2" y="68.9">13</text>
<text x="92.3" y="66.4">11</text>
<text x="103.5" y="66.4">12</text>
<text x="103.5" y="68.9">14</text>
<text x="103.5" y="71.5">16</text>
<text x="33.6" y="74">17</text>
<text x="33.6" y="76.5">19</text>
<text x="45" y="74">18</text>
<text x="45" y="76.5">20</text>
<text x="92.1" y="76.5">19</text>
<text x="92.1" y="74">17</text>
<text x="103.5" y="74">18</text>
<text x="103.5" y="76.5">20</text>
<text x="4" y="81.6">B</text>
<text x="33.7" y="81.6">23</text>
<text x="33.8" y="79.1">21</text>
<text x="45" y="79.1">22</text>
<text x="45" y="81.6">24</text>
<text x="92.2" y="81.6">23</text>
<text x="92.3" y="79.1">21</text>
<text x="103.5" y="79.1">22</text>
<text x="103.5" y="81.6">24</text>
<text x="291.5" y="81.6">B</text>
<text x="33.6" y="86.7">27</text>
<text x="33.6" y="89.3">29</text>
<text x="33.7" y="84.2">25</text>
<text x="45" y="84.2">26</text>
<text x="45" y="86.7">28</text>
<text x="45" y="89.3">30</text>
<text x="92.1" y="89.3">29</text>
<text x="92.1" y="86.7">27</text>
<text x="92.2" y="84.2">25</text>
<text x="103.5" y="84.2">26</text>
<text x="103.5" y="86.7">28</text>
<text x="103.5" y="89.3">30</text>
<text x="33.7" y="94.4">33</text>
<text x="33.8" y="91.8">31</text>
<text x="45" y="91.8">32</text>
<text x="45" y="94.4">34</text>
<text x="92.2" y="94.4">33</text>
<text x="92.3" y="91.8">31</text>
<text x="103.5" y="91.8">32</text>
<text x="103.5" y="94.4">34</text>
<text x="33.6" y="99.4">37</text>
<text x="33.6" y="102">39</text>
<text x="33.7" y="96.9">35</text>
<text x="45" y="96.9">36</text>
<text x="45" y="99.4">38</text>
<text x="45" y="102">40</text>
<text x="92.1" y="102">39</text>
<text x="92.1" y="99.4">37</text>
<text x="92.2" y="96.9">35</text>
<text x="103.5" y="96.9">36</text>
<text x="103.5" y="99.4">38</text>
<text x="103.5" y="102">40</text>
<text x="179.7" y="102">2</text>
<text x="189.9" y="102">1</text>
<text x="33.7" y="107.1">43</text>
<text x="33.8" y="104.5">41</text>
<text x="45" y="104.5">42</text>
<text x="45" y="107.1">44</text>
<text x="92.2" y="107.1">43</text>
<text x="92.3" y="104.5">41</text>
<text x="103.5" y="104.5">42</text>
<text x="103.5" y="107.1">44</text>
<text x="179.7" y="104.5">4</text>
<text x="179.7" y="107.1">6</text>
<text x="189.9" y="104.5">3</text>
<text x="189.9" y="107.1">5</text>
<text x="33.6" y="112.1">47</text>
<text x="33.7" y="109.6">45</text>
<text x="45" y="109.6">46</text>
<text x="45" y="112.1">48</text>
<text x="92.1" y="112.1">47</text>
<text x="92.2" y="109.6">45</text>
<text x="103.5" y="109.6">46</text>
<text x="103.5" y="112.1">48</text>
<text x="178.6" y="112.1">10</text>
<text x="179.8" y="109.6">8</text>
<text x="189.9" y="109.6">7</text>
<text x="189.9" y="112.1">9</text>
<text x="33.6" y="114.7">49</text>
<text x="33.7" y="119.8">53</text>
<text x="33.8" y="117.3">51</text>
<text x="45" y="114.7">50</text>
<text x="45" y="117.3">52</text>
<text x="45" y="119.8">54</text>
<text x="92.1" y="114.7">49</text>
<text x="92.2" y="119.8">53</text>
<text x="92.3" y="117.3">51</text>
<text x="103.5" y="114.7">50</text>
<text x="103.5" y="117.3">52</text>
<text x="103.5" y="119.8">54</text>
<text x="178.6" y="117.3">14</text>
<text x="178.6" y="119.8">16</text>
<text x="178.6" y="114.7">12</text>
<text x="189.9" y="114.7">11</text>
<text x="189.9" y="117.3">13</text>
<text x="189.9" y="119.8">15</text>
<text x="33.6" y="124.9">57</text>
<text x="33.7" y="122.3">55</text>
<text x="45" y="122.3">56</text>
<text x="45" y="124.9">58</text>
<text x="92.1" y="124.9">57</text>
<text x="92.2" y="122.3">55</text>
<text x="103.5" y="122.3">56</text>
<text x="103.5" y="124.9">58</text>
<text x="178.6" y="124.9">20</text>
<text x="178.6" y="122.3">18</text>
<text x="189.9" y="122.3">17</text>
<text x="189.9" y="124.9">19</text>
<text x="4" y="130">C</text>
<text x="33.6" y="127.4">59</text>
<text x="33.8" y="130">61</text>
<text x="45" y="127.4">60</text>
<text x="45" y="130">62</text>
<text x="92.1" y="127.4">59</text>
<text x="92.3" y="130">61</text>
<text x="103.5" y="127.4">60</text>
<text x="103.5" y="130">62</text>
<text x="178.6" y="130">24</text>
<text x="178.6" y="127.4">22</text>
<text x="189.9" y="127.4">21</text>
<text x="189.9" y="130">23</text>
<text x="291.5" y="130">C</text>
<text x="33.6" y="137.6">67</text>
<text x="33.7" y="132.5">63</text>
<text x="33.7" y="135">65</text>
<text x="45" y="132.5">64</text>
<text x="45" y="135">66</text>
<text x="45" y="137.6">68</text>
<text x="92.1" y="137.6">67</text>
<text x="92.2" y="135">65</text>
<text x="92.2" y="132.5">63</text>
<text x="103.5" y="132.5">64</text>
<text x="103.5" y="135">66</text>
<text x="103.5" y="137.6">68</text>
<text x="178.6" y="132.5">26</text>
<text x="178.6" y="137.6">30</text>
<text x="178.6" y="135">28</text>
<text x="189.9" y="132.5">25</text>
<text x="189.9" y="135">27</text>
<text x="189.9" y="137.6">29</text>
<text x="33.6" y="140.1">69</text>
<text x="33.8" y="142.7">71</text>
<text x="45" y="140.1">70</text>
<text x="45" y="142.7">72</text>
<text x="92.1" y="140.1">69</text>
<text x="92.3" y="142.7">71</text>
<text x="103.5" y="140.1">70</text>
<text x="103.5" y="142.7">72</text>
<text x="178.6" y="142.7">34</text>
<text x="178.6" y="140.1">32</text>
<text x="189.9" y="140.1">31</text>
<text x="189.9" y="142.7">33</text>
<text x="33.7" y="145.2">73</text>
<text x="33.7" y="147.8">75</text>
<text x="45" y="145.2">74</text>
<text x="45" y="147.8">76</text>
<text x="92.2" y="147.8">75</text>
<text x="92.2" y="145.2">73</text>
<text x="103.5" y="145.2">74</text>
<text x="103.5" y="147.8">76</text>
<text x="178.6" y="145.2">36</text>
<text x="178.6" y="147.8">38</text>
<text x="189.9" y="145.2">35</text>
<text x="189.9" y="147.8">37</text>
<text x="33.6" y="150.3">77</text>
<text x="33.6" y="152.9">79</text>
<text x="33.8" y="155.4">81</text>
<text x="45" y="150.3">78</text>
<text x="45" y="152.9">80</text>
<text x="45" y="155.4">82</text>
<text x="92.1" y="152.9">79</text>
<text x="92.1" y="150.3">77</text>
<text x="92.3" y="155.4">81</text>
<text x="103.5" y="150.3">78</text>
<text x="103.5" y="152.9">80</text>
<text x="103.5" y="155.4">82</text>
<text x="178.6" y="150.3">40</text>
<text x="178.6" y="155.4">44</text>
<text x="178.6" y="152.9">42</text>
<text x="189.9" y="150.3">39</text>
<text x="189.9" y="152.9">41</text>
<text x="189.9" y="155.4">43</text>
<text x="33.7" y="157.9">83</text>
<text x="33.7" y="160.5">85</text>
<text x="45" y="157.9">84</text>
<text x="45" y="160.5">86</text>
<text x="92.2" y="160.5">85</text>
<text x="92.2" y="157.9">83</text>
<text x="103.5" y="157.9">84</text>
<text x="103.5" y="160.5">86</text>
<text x="178.6" y="157.9">46</text>
<text x="178.6" y="160.5">48</text>
<text x="189.9" y="157.9">45</text>
<text x="189.9" y="160.5">47</text>
<text x="33.6" y="163">87</text>
<text x="33.6" y="165.6">89</text>
<text x="45" y="163">88</text>
<text x="45" y="165.6">90</text>
<text x="92.1" y="165.6">89</text>
<text x="92.1" y="163">87</text>
<text x="103.5" y="163">88</text>
<text x="103.5" y="165.6">90</text>
<text x="178.6" y="163">50</text>
<text x="178.6" y="165.6">52</text>
<text x="189.9" y="163">49</text>
<text x="189.9" y="165.6">51</text>
<text x="33.7" y="170.7">93</text>
<text x="33.7" y="173.2">95</text>
<text x="33.8" y="168.1">91</text>
<text x="45" y="168.1">92</text>
<text x="45" y="170.7">94</text>
<text x="45" y="173.2">96</text>
<text x="92.2" y="173.2">95</text>
<text x="92.2" y="170.7">93</text>
<text x="92.3" y="168.1">91</text>
<text x="103.5" y="168.1">92</text>
<text x="103.5" y="170.7">94</text>
<text x="103.5" y="173.2">96</text>
<text x="133.9" y="173.2">2</text>
<text x="134.1" y="170.7">1</text>
<text x="138.8" y="172">1</text>
<text x="178.6" y="168.1">54</text>
<text x="178.6" y="170.7">56</text>
<text x="178.6" y="173.2">58</text>
<text x="189.9" y="168.1">53</text>
<text x="189.9" y="170.7">55</text>
<text x="189.9" y="173.2">57</text>
<text x="4" y="178.3">D</text>
<text x="33.6" y="175.8">97</text>
<text x="33.6" y="178.3">99</text>
<text x="45" y="175.8">98</text>
<text x="45" y="178.3">100</text>
<text x="92.1" y="178.3">99</text>
<text x="92.1" y="175.8">97</text>
<text x="103.5" y="175.8">98</text>
<text x="103.5" y="178.3">100</text>
<text x="133.9" y="178.3">4</text>
<text x="134" y="175.8">3</text>
<text x="138.8" y="174.5">2</text>
<text x="138.8" y="177">3</text>
<text x="138.8" y="179.6">4</text>
<text x="178.6" y="175.8">60</text>
<text x="189.9" y="175.8">59</text>
<text x="248.5" y="178.3">3</text>
<text x="248.6" y="175.8">1</text>
<text x="253.3" y="177">IN</text>
<text x="253.3" y="179.6">EN</text>
<text x="260.3" y="177">OUT</text>
<text x="268.8" y="175.8">5</text>
<text x="291.4" y="178.3">D</text>
<text x="32.6" y="183.4">101</text>
<text x="45" y="183.4">102</text>
<text x="91.1" y="183.4">101</text>
<text x="103.5" y="183.4">102</text>
<text x="133.9" y="183.4">6</text>
<text x="134" y="180.8">5</text>
<text x="138.8" y="182.1">5</text>
<text x="138.8" y="184.7">6</text>
<text x="178.6" y="180.8">62</text>
<text x="189.9" y="180.8">61</text>
<text x="248.4" y="183.4">2</text>
<text x="253.3" y="184.7">GND</text>
<text x="261.9" y="184.7">NC</text>
<text x="268.8" y="183.4">4</text>
<text x="37.9" y="199.9">1</text>
<text x="110.9" y="199.9">2</text>
<text x="184.1" y="199.9">3</text>
<text x="257.1" y="199.9">4</text>
</g>
<g font-size="2.3" fill="#000080">
<text x="75.7" y="17.8">D1</text>
<text x="13.6" y="21.8">MH1</text>
<text x="21.3" y="21.8">MH2</text>
<text x="28.9" y="21.8">MH3</text>
<text x="36.5" y="21.8">MH4</text>
<text x="60.2" y="19.6">R67</text>
<text x="144.7" y="20.6">C62</text>
<text x="147.2" y="23.1">C15</text>
<text x="156.7" y="23.1">100nF</text>
<text x="209" y="20.6">R68</text>
<text x="209" y="23.1">R69</text>
<text x="215.3" y="21.8">0</text>
<text x="259.2" y="18">PCIe_X4_TX</text>
<text x="10.9" y="28.2">M3</text>
<text x="18.5" y="28.2">M3</text>
<text x="26.2" y="28.2">M3</text>
<text x="33.8" y="28.2">M3</text>
<text x="60.2" y="24.2">1K</text>
<text x="70.9" y="25.7">GREEN</text>
<text x="144.7" y="28.2">C16</text>
<text x="159.3" y="25.7">100nF</text>
<text x="208.9" y="28.2">R70</text>
<text x="215.3" y="24.4">0</text>
<text x="215.3" y="29.5">0</text>
<text x="144.7" y="35.9">C66</text>
<text x="147.2" y="30.7">C65</text>
<text x="156.7" y="30.7">100nF</text>
<text x="159.3" y="33.3">100nF</text>
<text x="209" y="35.9">R72</text>
<text x="209" y="30.7">R71</text>
<text x="215.3" y="32">0</text>
<text x="147.2" y="38.4">C67</text>
<text x="156.7" y="38.4">100nF</text>
<text x="159.3" y="40.9">100nF</text>
<text x="209" y="38.4">R73</text>
<text x="215.3" y="37.1">0</text>
<text x="215.3" y="39.7">0</text>
<text x="144.7" y="43.5">C68</text>
<text x="147.2" y="46">C69</text>
<text x="156.7" y="46">100nF</text>
<text x="208.9" y="43.5">R74</text>
<text x="209" y="46">R75</text>
<text x="215.3" y="44.7">0</text>
<text x="215.3" y="47.3">0</text>
<text x="259.2" y="46">PCIe_X4_RX</text>
<text x="29.5" y="48.6">ADC Diff Pairs on JM1</text>
<text x="37.5" y="51.1">JM1</text>
<text x="96.1" y="51.1">JM2</text>
<text x="144.7" y="51.1">C70</text>
<text x="147.2" y="53.6">C71</text>
<text x="156.7" y="53.6">100nF</text>
<text x="159.3" y="48.6">100nF</text>
<text x="209" y="51.1">R76</text>
<text x="209" y="53.6">R77</text>
<text x="215.3" y="52.4">0</text>
<text x="144.7" y="58.7">C72</text>
<text x="159.3" y="56.2">100nF</text>
<text x="209" y="58.7">R78</text>
<text x="215.3" y="54.9">0</text>
<text x="215.3" y="60">0</text>
<text x="60.7" y="63.8">VCCIO16</text>
<text x="147.2" y="61.3">C73</text>
<text x="156.7" y="61.3">100nF</text>
<text x="159.3" y="63.8">100nF</text>
<text x="209" y="61.3">R79</text>
<text x="215.3" y="62.6">0</text>
<text x="144.7" y="66.4">C74</text>
<text x="147.2" y="68.9">C75</text>
<text x="156.7" y="68.9">100nF</text>
<text x="159.3" y="71.5">100nF</text>
<text x="208.9" y="66.4">R80</text>
<text x="209" y="68.9">R81</text>
<text x="215.3" y="67.6">0</text>
<text x="215.3" y="70.2">0</text>
<text x="70.4" y="72.9">R66</text>
<text x="71.5" y="75.3">10K</text>
<text x="144.7" y="74">C76</text>
<text x="147.2" y="76.5">C77</text>
<text x="156.7" y="76.5">100nF</text>
<text x="209" y="74">R82</text>
<text x="209" y="76.5">R83</text>
<text x="215.3" y="75.3">0</text>
<text x="215.3" y="77.8">0</text>
<text x="13.2" y="81.6" transform="rotate(-90 13.2 81.6)">10K</text>
<text x="15.7" y="82" transform="rotate(-90 15.7 82)">R101</text>
<text x="18.2" y="81.6" transform="rotate(-90 18.2 81.6)">10K</text>
<text x="20.8" y="82" transform="rotate(-90 20.8 82)">R102</text>
<text x="144.7" y="81.6">C40</text>
<text x="159.3" y="79.1">100nF</text>
<text x="233.3" y="83.2">R84</text>
<text x="55.6" y="86.7">MERGED SPI BUSSES</text>
<text x="144.7" y="89.3">C80</text>
<text x="147.2" y="84.2">C79</text>
<text x="156.7" y="84.2">100nF</text>
<text x="159.3" y="86.7">100nF</text>
<text x="234.3" y="85.4">49.9</text>
<text x="147.2" y="91.8">C81</text>
<text x="156.7" y="91.8">100nF</text>
<text x="159.3" y="94.4">100nF</text>
<text x="259.2" y="91.8">M2_X4_TX</text>
<text x="12.4" y="96.9">TP2</text>
<text x="182.6" y="99.4">JM3</text>
<text x="132" y="110.9">Was FE_PG</text>
<text x="259.2" y="119.8">M2_X4_RX</text>
<text x="132" y="131.2">Was ADC_PD</text>
<text x="132" y="133.8">Was ADC_RSTn</text>
<text x="132" y="136.3">Was ADC_CSn</text>
<text x="132" y="138.9">Was ADC_PG</text>
<text x="233.3" y="157">R85</text>
<text x="234.3" y="159.2">49.9</text>
<text x="65.3" y="164.5">R103</text>
<text x="66.3" y="166.8">10K</text>
<text x="137" y="168.1">J8</text>
<text x="214.6" y="170.7">TP14</text>
<text x="229.9" y="170.7">TP30</text>
<text x="251.5" y="173.2">U16</text>
<text x="275.7" y="170.7">TP31 +2V5</text>
<text x="161.2" y="178.8">TP39</text>
<text x="220.5" y="174.8">R104</text>
<text x="222.2" y="177">0.1</text>
<text x="170.1" y="185.9">LSHM-130-04.0-L-DV-A-S-K-TR</text>
<text x="236.3" y="180.8">C105</text>
<text x="236.3" y="183.4">1uF</text>
<text x="282" y="180.8">C106</text>
<text x="282" y="183.4">1uF</text>
<text x="25.1" y="188.5">LSHM-150-04.0-L-DV-A-S-K-TR</text>
<text x="83.6" y="188.5">LSHM-150-04.0-L-DV-A-S-K-TR</text>
<text x="126.9" y="188.5">Digilent JTAG Header</text>
<text x="251.5" y="188.5">TPS7A2025</text>
</g>
<g font-size="2.3" fill="#800000">
<text x="47.5" y="21.8">+3V3</text>
<text x="89.4" y="20.6">LED</text>
<text x="169" y="20.6">PCIe_PER3_N</text>
<text x="169.4" y="23.1">PCIe_PER3_P</text>
<text x="222.5" y="20.6">PCIe_PET3_N</text>
<text x="222.9" y="23.1">PCIe_PET3_P</text>
<text x="243.9" y="20.6">PCIe_PET0_N</text>
<text x="243.9" y="23.1">PCIe_PET0_P</text>
<text x="124.3" y="28.2">MGT_TX0_N</text>
<text x="170.3" y="28.2">M2_PER3_N</text>
<text x="190.5" y="28.2">MGT_RX0_N</text>
<text x="223.9" y="28.2">M2_PET3_N</text>
<text x="243.9" y="25.7">PCIe_PET1_N</text>
<text x="243.9" y="28.2">PCIe_PET1_P</text>
<text x="277.7" y="29.5">PCIe_TX</text>
<text x="12.5" y="35.9">GND</text>
<text x="20.1" y="35.9">GND</text>
<text x="27.7" y="35.9">GND</text>
<text x="35.4" y="35.9">GND</text>
<text x="55.6" y="32">DC_CPL_[4..1]</text>
<text x="55.6" y="34.6">ATTEN_[4..1]</text>
<text x="79.3" y="30.7">DC_CPL_[4..1]</text>
<text x="80.3" y="33.3">ATTEN_[4..1]</text>
<text x="81.4" y="35.9">TERM_[4..1]</text>
<text x="124.3" y="30.7">MGT_TX0_P</text>
<text x="169" y="35.9">PCIe_PER2_N</text>
<text x="170.8" y="30.7">M2_PER3_P</text>
<text x="190.5" y="30.7">MGT_RX0_P</text>
<text x="222.5" y="35.9">PCIe_PET2_N</text>
<text x="224.3" y="30.7">M2_PET3_P</text>
<text x="243.9" y="30.7">PCIe_PET2_N</text>
<text x="243.9" y="33.3">PCIe_PET2_P</text>
<text x="243.9" y="35.9">PCIe_PET3_N</text>
<text x="55.6" y="39.7">PGA_CSn_[4..1]</text>
<text x="55.6" y="37.1">TERM_[4..1]</text>
<text x="78.1" y="38.4">PGA_CSn_[4..1]</text>
<text x="169.4" y="38.4">PCIe_PER2_P</text>
<text x="222.9" y="38.4">PCIe_PET2_P</text>
<text x="243.9" y="38.4">PCIe_PET3_P</text>
<text x="124.3" y="43.5">MGT_TX1_N</text>
<text x="124.3" y="46">MGT_TX1_P</text>
<text x="170.3" y="43.5">M2_PER2_N</text>
<text x="170.8" y="46">M2_PER2_P</text>
<text x="190.5" y="43.5">MGT_RX1_N</text>
<text x="190.5" y="46">MGT_RX1_P</text>
<text x="223.9" y="43.5">M2_PET2_N</text>
<text x="224.3" y="46">M2_PET2_P</text>
<text x="53.8" y="48.6">+3V3_IN</text>
<text x="81.7" y="48.6">+3V3_IN Other IO on JM2</text>
<text x="112.3" y="48.6">+3V3_IN</text>
<text x="169" y="51.1">PCIe_PER1_N</text>
<text x="169.4" y="53.6">PCIe_PER1_P</text>
<text x="222.5" y="51.1">PCIe_PET1_N</text>
<text x="222.9" y="53.6">PCIe_PET1_P</text>
<text x="243.9" y="48.6">PCIe_PER0_N</text>
<text x="243.9" y="51.1">PCIe_PER0_P</text>
<text x="243.9" y="53.6">PCIe_PER1_N</text>
<text x="124.3" y="58.7">MGT_TX2_N</text>
<text x="170.3" y="58.7">M2_PER1_N</text>
<text x="190.5" y="58.7">MGT_RX2_N</text>
<text x="223.9" y="58.7">M2_PET1_N</text>
<text x="243.9" y="56.2">PCIe_PER1_P</text>
<text x="243.9" y="58.7">PCIe_PER2_N</text>
<text x="277.6" y="57.4">PCIe_RX</text>
<text x="74" y="65.1">+2V5</text>
<text x="124.3" y="61.3">MGT_TX2_P</text>
<text x="170.8" y="61.3">M2_PER1_P</text>
<text x="190.5" y="61.3">MGT_RX2_P</text>
<text x="224.3" y="61.3">M2_PET1_P</text>
<text x="243.9" y="61.3">PCIe_PER2_P</text>
<text x="243.9" y="63.8">PCIe_PER3_N</text>
<text x="8" y="66.4">+3V3_IN</text>
<text x="169" y="66.4">PCIe_PER0_N</text>
<text x="169.4" y="68.9">PCIe_PER0_P</text>
<text x="222.5" y="66.4">PCIe_PET0_N</text>
<text x="222.9" y="68.9">PCIe_PET0_P</text>
<text x="243.9" y="66.4">PCIe_PER3_P</text>
<text x="54" y="75.3">+3V3_IN</text>
<text x="81.1" y="74">RESIN</text>
<text x="124.3" y="74">MGT_TX3_N</text>
<text x="124.3" y="76.5">MGT_TX3_P</text>
<text x="170.3" y="74">M2_PER0_N</text>
<text x="170.8" y="76.5">M2_PER0_P</text>
<text x="190.5" y="74">MGT_RX3_N</text>
<text x="190.5" y="76.5">MGT_RX3_P</text>
<text x="223.9" y="74">M2_PET0_N</text>
<text x="224.3" y="76.5">M2_PET0_P</text>
<text x="243.9" y="74">PCIe_REFCLK_N</text>
<text x="243.9" y="76.5">PCIe_REFCLK_P</text>
<text x="266.8" y="77.8">PCIe_REFCLK_P</text>
<text x="266.8" y="75.3">PCIe_REFCLK_N</text>
<text x="165.5" y="81.6">PCIe_REFCLK_N</text>
<text x="20" y="86.7">EN1</text>
<text x="20" y="89.3">PGOOD</text>
<text x="124.3" y="89.3">MGT_CLK1_N</text>
<text x="165.9" y="84.2">PCIe_REFCLK_P</text>
<text x="166.9" y="89.3">M2_REFCLK_N</text>
<text x="221" y="84.2">PERST#</text>
<text x="243.9" y="84.2">PCIe_PERST#</text>
<text x="266.8" y="85.4">PCIe_PERST#</text>
<text x="58.2" y="93.1">PGA_SDIO</text>
<text x="58.2" y="95.6">PGA_SCLK</text>
<text x="124.3" y="91.8">MGT_CLK1_P</text>
<text x="167.3" y="91.8">M2_REFCLK_P</text>
<text x="243.9" y="94.4">M2_PET0_N</text>
<text x="73.4" y="99.4">DC_CPL_1</text>
<text x="73.4" y="96.9">ATTEN_1</text>
<text x="243.9" y="96.9">M2_PET0_P</text>
<text x="243.9" y="99.4">M2_PET1_N</text>
<text x="243.9" y="102">M2_PET1_P</text>
<text x="73.4" y="107.1">PGA_CSn_1</text>
<text x="73.4" y="104.5">TERM_1</text>
<text x="118.8" y="105.8">M2_GPIO1</text>
<text x="243.9" y="104.5">M2_PET2_N</text>
<text x="243.9" y="107.1">M2_PET2_P</text>
<text x="278.3" y="103.3">M2_TX</text>
<text x="73.4" y="112.1">DC_CPL_2</text>
<text x="73.4" y="109.6">ATTEN_2</text>
<text x="118.7" y="108.3">M2_GPIO2</text>
<text x="119.5" y="110.9">ADC_CSn</text>
<text x="120.8" y="113.4">OSC_OE</text>
<text x="149.7" y="109.6">MGT_TX0_N</text>
<text x="149.7" y="112.1">MGT_TX0_P</text>
<text x="200.6" y="109.6">MGT_RX0_N</text>
<text x="200.6" y="112.1">MGT_RX0_P</text>
<text x="243.9" y="109.6">M2_PET3_N</text>
<text x="243.9" y="112.1">M2_PET3_P</text>
<text x="73.4" y="119.8">PGA_CSn_2</text>
<text x="73.4" y="117.3">TERM_2</text>
<text x="120.4" y="118.5">ACQ_EN</text>
<text x="149.7" y="117.3">MGT_TX1_N</text>
<text x="149.7" y="119.8">MGT_TX1_P</text>
<text x="200.6" y="117.3">MGT_RX1_N</text>
<text x="200.6" y="119.8">MGT_RX1_P</text>
<text x="14.9" y="123.6">D1A_P</text>
<text x="73.4" y="124.9">DC_CPL_3</text>
<text x="73.4" y="122.3">ATTEN_3</text>
<text x="122.6" y="121.1">FE_EN</text>
<text x="124.8" y="123.6">SDA</text>
<text x="149.7" y="124.9">MGT_TX2_N</text>
<text x="200.6" y="124.9">MGT_RX2_N</text>
<text x="243.9" y="122.3">M2_PER0_N</text>
<text x="243.9" y="124.9">M2_PER0_P</text>
<text x="14.9" y="128.7">D1B_P</text>
<text x="14.9" y="131.2">D1B_N</text>
<text x="14.9" y="126.2">D1A_N</text>
<text x="57" y="131.2">LCLK_N</text>
<text x="57.4" y="128.7">LCLK_P</text>
<text x="73.4" y="130">TERM_3</text>
<text x="119.7" y="130">ATTEN_4</text>
<text x="125.2" y="126.2">SCL</text>
<text x="149.7" y="127.4">MGT_TX2_P</text>
<text x="200.6" y="127.4">MGT_RX2_P</text>
<text x="243.9" y="127.4">M2_PER1_N</text>
<text x="243.9" y="130">M2_PER1_P</text>
<text x="278.3" y="131.2">M2_RX</text>
<text x="14.9" y="136.3">D2A_P</text>
<text x="57" y="136.3">PROBE_COMP</text>
<text x="73.4" y="132.5">PGA_CSn_3</text>
<text x="117.5" y="137.6">PGA_CSn_4</text>
<text x="118.6" y="132.5">DC_CPL_4</text>
<text x="120.8" y="135">TERM_4</text>
<text x="149.7" y="132.5">MGT_TX3_N</text>
<text x="149.7" y="135">MGT_TX3_P</text>
<text x="200.6" y="132.5">MGT_RX3_N</text>
<text x="200.6" y="135">MGT_RX3_P</text>
<text x="243.9" y="132.5">M2_PER2_N</text>
<text x="243.9" y="135">M2_PER2_P</text>
<text x="243.9" y="137.6">M2_PER3_N</text>
<text x="14.9" y="141.4">D2B_P</text>
<text x="14.9" y="138.9">D2A_N</text>
<text x="14.9" y="144">D2B_N</text>
<text x="149.7" y="140.1">MGT_CLK1_N</text>
<text x="149.7" y="142.7">MGT_CLK1_P</text>
<text x="243.9" y="140.1">M2_PER3_P</text>
<text x="58.2" y="149.1">FCLK_P</text>
<text x="243.9" y="147.8">M2_REFCLK_N</text>
<text x="266.8" y="149.1">M2_REFCLK_N</text>
<text x="14.9" y="154.1">D3A_P</text>
<text x="58.2" y="151.6">FCLK_N</text>
<text x="243.9" y="150.3">M2_REFCLK_P</text>
<text x="266.8" y="151.6">M2_REFCLK_P</text>
<text x="14.9" y="161.8">D3B_P</text>
<text x="14.9" y="156.7">D3A_N</text>
<text x="221" y="157.9">PERST#</text>
<text x="243.9" y="157.9">M2_PERST#</text>
<text x="266.8" y="159.2">M2_PERST#</text>
<text x="14.9" y="164.3">D3B_N</text>
<text x="51.4" y="165.6">JTAGEN</text>
<text x="79" y="166.8">GND</text>
<text x="14.9" y="172">D4A_P</text>
<text x="56.3" y="173.2">LED</text>
<text x="65.8" y="172">SYNC</text>
<text x="114.1" y="173.2">TDI</text>
<text x="114.1" y="170.7">TMS</text>
<text x="114.1" y="168.1">JTAG_VREF</text>
<text x="203.9" y="170.7">+3V3_IN</text>
<text x="14.9" y="174.5">D4A_N</text>
<text x="14.9" y="177">D4B_P</text>
<text x="14.9" y="179.6">D4B_N</text>
<text x="114.1" y="178.3">TCK</text>
<text x="114.1" y="175.8">TDO</text>
<text x="149.7" y="175.8">PERST#</text>
<text x="25.2" y="193.5">GND</text>
<text x="50.6" y="193.5">GND</text>
<text x="83.7" y="193.5">GND</text>
<text x="109.1" y="193.5">GND</text>
<text x="121.9" y="193.5">GND</text>
<text x="170.2" y="193.5">GND</text>
<text x="195.7" y="193.5">GND</text>
<text x="231.3" y="193.5">GND</text>
<text x="238.9" y="193.5">GND</text>
<text x="277.1" y="193.5">GND</text>
</g>
<g font-size="2.3" fill="#003a70">
<text x="260.4" y="21.8">PET0_N</text>
<text x="260.4" y="24.4">PET0_P</text>
<text x="260.4" y="26.9">PET1_N</text>
<text x="260.4" y="29.5">PET1_P</text>
<text x="260.4" y="32">PET2_N</text>
<text x="260.4" y="34.6">PET2_P</text>
<text x="260.4" y="37.1">PET3_N</text>
<text x="260.4" y="39.7">PET3_P</text>
<text x="260.4" y="49.8">PER0_N</text>
<text x="260.4" y="52.4">PER0_P</text>
<text x="260.4" y="54.9">PER1_N</text>
<text x="260.4" y="57.4">PER1_P</text>
<text x="260.4" y="60">PER2_N</text>
<text x="260.4" y="62.6">PER2_P</text>
<text x="260.4" y="65.1">PER3_N</text>
<text x="260.4" y="67.6">PER3_P</text>
<text x="260.4" y="95.6">PET0_N</text>
<text x="260.4" y="98.2">PET0_P</text>
<text x="260.4" y="100.7">PET1_N</text>
<text x="260.4" y="103.3">PET1_P</text>
<text x="260.4" y="105.8">PET2_N</text>
<text x="260.4" y="108.3">PET2_P</text>
<text x="260.4" y="110.9">PET3_N</text>
<text x="260.4" y="113.4">PET3_P</text>
<text x="260.4" y="123.6">PER0_N</text>
<text x="260.4" y="126.2">PER0_P</text>
<text x="260.4" y="128.7">PER1_N</text>
<text x="260.4" y="131.2">PER1_P</text>
<text x="260.4" y="133.8">PER2_N</text>
<text x="260.4" y="136.3">PER2_P</text>
<text x="260.4" y="138.9">PER3_N</text>
<text x="260.4" y="141.4">PER3_P</text>
</g>
<g font-size="2.3" fill="#f00">
<text x="200.6" y="94.4">AC Couple PER Lines with 100nF</text>
<text x="200.6" y="96.9">AC Couple REFCLK Lines with 100nF</text>
</g>
<text font-size="2.3" fill="#f90" x="14.9" y="196.1">These connectors are hermaphroditic. Odd pin numbers on the module are connected to even pin numbers on the baseboard and vice versa.</text>
</g></defs>
<path d="M2.2 8.4h292.6v193.3h-292.6z" fill-rule="evenodd" fill="#fffcf8"/>
<path d="M2.2 8.4h292.6v193.3h-292.6z" fill="none" stroke="#000" stroke-width=".21"/>
<path d="M7.3 13.5h282.4v183.1h-282.4z" fill-rule="evenodd" fill="#fffcf8"/>
<g fill="none" stroke="#000" stroke-width=".21">
<path d="M2.2 8.4h5.1M7.3 13.5h282.4v183.1h-282.4zM75.3 8.4v5.1M148.5 8.4v5.1M221.6 8.4v5.1M289.7 8.4h5.1v5.1M2.2 56.7h5.1M289.7 56.7h5.1M2.2 105h5.1M289.7 105.1h5.1M2.2 153.4h5.1M289.7 153.4h5.1"/>
<path d="M75.3 196.6v5.1M148.5 196.6v5.1M221.6 196.6v5.1M294.8 196.6v5.1"/>
</g>
<g fill="none" stroke="#00be00" stroke-width="1.3">
<path d="M30.2 54.2h-2.6v129.7M27.6 61.8h2.6M27.6 77.1h2.6M88.7 77.1h-2.5v106.8M27.6 84.7h2.6M27.6 94.9h2.6M50.5 89.8h2.6v30.5h-2.6M86.2 89.8h2.5M27.6 107.6h2.6M86.2 102.5h2.5M86.2 115.2h2.5M109.1 102.5h2.5v81.4"/>
<path d="M109.1 115.2h2.5M172.7 115.2h2.5M175.2 107.6h-2.5v73.8M195.5 107.6h2.6v73.8M195.5 115.2h2.6M27.6 120.3h2.6M27.6 133h2.6M53.1 120.3v12.7h-2.6M53.1 133v12.7h-2.6M86.2 127.9h2.5M109.1 127.9h2.5M172.7 122.9h2.5"/>
<path d="M172.7 130.5h2.5M172.7 138.1h2.5M195.5 122.9h2.6M195.5 130.5h2.6M195.5 138.1h2.6M27.6 145.7h2.6M27.6 158.5h2.6M53.1 145.8v38.1M86.2 140.7h2.5M86.2 153.4h2.5M109.1 140.7h2.5M109.1 153.4h2.5"/>
<path d="M172.7 145.8h2.5M172.7 158.5h2.5M195.5 145.8h2.6M195.5 158.5h2.6M27.6 166.1h2.6M86.2 166.1h2.5M30.2 183.9h-2.6v2.6M50.5 183.9h2.6v2.6M88.7 183.9h-2.5v2.6M109.1 183.9h2.5v2.6M129.4 181.4h-5.1v5.1M175.2 181.4h-2.5v5.1"/>
<path d="M195.5 181.4h2.6v5.1M243.9 183.9h-2.6v2.6"/>
</g>
<path d="M55.6 21.1h2.6" fill="none" stroke="#f90" stroke-width="1.3"/>
<path d="M278.4 55.7h7.6l1.3 1.3-1.3 1.2h-7.6l-1.3-1.2z" fill-rule="evenodd" fill="#bac0ca"/>
<path d="M278.4 55.7h7.6l1.3 1.3-1.3 1.2h-7.6l-1.3-1.2z" fill="none" stroke="#a6acb6" stroke-width=".21"/>
<path d="M278.2 55.4h7.7l1.2 1.3-1.2 1.3h-7.7l-1.2-1.3z" fill-rule="evenodd" fill="#d5e4ff"/>
<path d="M278.2 55.4h7.7l1.2 1.3-1.2 1.3h-7.7l-1.2-1.3z" fill="none" stroke="#71809b" stroke-width=".21"/>
<path d="M277.1 29l1.3-1.3h7.6l1.3 1.3-1.3 1.3h-7.6z" fill-rule="evenodd" fill="#bac0ca"/>
<path d="M277.1 29l1.3-1.3h7.6l1.3 1.3-1.3 1.3h-7.6z" fill="none" stroke="#a6acb6" stroke-width=".21"/>
<path d="M277 28.7l1.2-1.2h7.7l1.2 1.2-1.2 1.3h-7.7z" fill-rule="evenodd" fill="#d5e4ff"/>
<path d="M277 28.7l1.2-1.2h7.7l1.2 1.2-1.2 1.3h-7.7z" fill="none" stroke="#71809b" stroke-width=".21"/>
<path d="M265.5 75.8h21.6v2.5h-21.6l-1.3-1.2z" fill-rule="evenodd" fill="#ffff80"/>
<path d="M265.5 75.8h21.6v2.5h-21.6l-1.3-1.2z" fill="none" stroke="#800000" stroke-width=".21"/>
<path d="M265.5 73.2h21.6v2.6h-21.6l-1.3-1.3z" fill-rule="evenodd" fill="#ffff80"/>
<path d="M265.5 73.2h21.6v2.6h-21.6l-1.3-1.3z" fill="none" stroke="#800000" stroke-width=".21"/>
<path d="M264.2 84.7l1.3-1.3h21.6v2.6h-21.6z" fill-rule="evenodd" fill="#ffff80"/>
<path d="M264.2 84.7l1.3-1.3h21.6v2.6h-21.6z" fill="none" stroke="#800000" stroke-width=".21"/>
<g fill="none" stroke="#000" stroke-width=".25">
<path d="M30.2 54.2h7.6M30.2 56.7h7.6M30.2 59.3h7.6M42.9 54.2h7.6M42.9 56.7h7.6M42.9 59.3h7.6M30.2 61.8h7.6M30.2 64.3h7.6M30.2 66.9h7.6M30.2 69.4h7.6M30.2 72h7.6M30.2 74.5h7.6"/>
<path d="M30.2 77.1h7.6M30.2 79.6h7.6M42.9 61.8h7.6M42.9 64.3h7.6M42.9 66.9h7.6M42.9 69.4h7.6M42.9 72h7.6M42.9 74.5h7.6M42.9 77.1h7.6M42.9 79.6h7.6M30.2 82.1h7.6M30.2 84.7h7.6"/>
<path d="M30.2 87.2h7.6M30.2 89.8h7.6M30.2 92.3h7.6M30.2 94.9h7.6M30.2 97.4h7.6M30.2 100h7.6M42.9 82.1h7.6M42.9 84.7h7.6M42.9 87.2h7.6M42.9 89.8h7.6M42.9 92.3h7.6M42.9 94.9h7.6"/>
<path d="M42.9 97.4h7.6M42.9 100h7.6M30.2 102.5h7.6M30.2 105h7.6M30.2 107.6h7.6M30.2 110.1h7.6M30.2 112.7h7.6M30.2 115.2h7.6M30.2 117.8h7.6M42.9 102.5h7.6M42.9 105h7.6M42.9 107.6h7.6"/>
<path d="M42.9 110.1h7.6M42.9 112.7h7.6M42.9 115.2h7.6M42.9 117.8h7.6M30.2 120.3h7.6M30.2 122.9h7.6M30.2 125.4h7.6M30.2 127.9h7.6M30.2 130.5h7.6M30.2 133h7.6M30.2 135.6h7.6M30.2 138.1h7.6"/>
<path d="M42.9 120.3h7.6M42.9 122.9h7.6M42.9 125.4h7.6M42.9 127.9h7.6M42.9 130.5h7.6M42.9 133h7.6M42.9 135.6h7.6M42.9 138.1h7.6M30.2 140.7h7.6M30.2 143.2h7.6M30.2 145.7h7.6M30.2 148.3h7.6"/>
<path d="M30.2 150.8h7.6M30.2 153.4h7.6M30.2 155.9h7.6M30.2 158.5h7.6M42.9 140.7h7.6M42.9 143.2h7.6M42.9 145.7h7.6M42.9 148.3h7.6M42.9 150.8h7.6M42.9 153.4h7.6M42.9 155.9h7.6M42.9 158.5h7.6"/>
<path d="M30.2 161h7.6M30.2 163.6h7.6M30.2 166.1h7.6M30.2 168.6h7.6M30.2 171.2h7.6M30.2 173.7h7.6M30.2 176.3h7.6M30.2 178.8h7.6M42.9 173.7h7.6M42.9 176.3h7.6M42.9 178.8h7.6M42.9 161h7.6"/>
<path d="M42.9 163.6h7.6M42.9 166.1h7.6M42.9 168.6h7.6M42.9 171.2h7.6M30.2 183.9h7.6M42.9 183.9h7.6"/>
</g>
<path d="M37.8 51.6h5.1v134.9h-5.1z" fill-rule="evenodd" fill="#ffffb0"/>
<path d="M37.8 51.6h5.1v134.9h-5.1z" fill="none" stroke="#800000" stroke-width=".21"/>
<g fill="none" stroke="#000" stroke-width=".25">
<path d="M88.7 54.2h7.6M88.7 56.7h7.6M88.7 59.3h7.6M101.4 54.2h7.7M101.4 56.7h7.7M101.4 59.3h7.7M88.7 61.8h7.6M88.7 64.3h7.6M88.7 66.9h7.6M88.7 69.4h7.6M88.7 72h7.6M88.7 74.5h7.6"/>
<path d="M88.7 77.1h7.6M88.7 79.6h7.6M101.4 61.8h7.7M101.4 64.3h7.7M101.4 66.9h7.7M101.4 69.4h7.7M101.4 72h7.7M101.4 74.5h7.7M101.4 77.1h7.7M101.4 79.6h7.7M88.7 82.1h7.6M88.7 84.7h7.6"/>
<path d="M88.7 87.2h7.6M88.7 89.8h7.6M88.7 92.3h7.6M88.7 94.9h7.6M88.7 97.4h7.6M88.7 100h7.6M101.4 82.1h7.7M101.4 84.7h7.7M101.4 87.2h7.7M101.4 89.8h7.7M101.4 92.3h7.7M101.4 94.9h7.7"/>
<path d="M101.4 97.4h7.7M101.4 100h7.7M88.7 102.5h7.6M88.7 105h7.6M88.7 107.6h7.6M88.7 110.1h7.6M88.7 112.7h7.6M88.7 115.2h7.6M88.7 117.8h7.6M101.4 102.5h7.7M101.4 105h7.7M101.4 107.6h7.7"/>
<path d="M101.4 110.1h7.7M101.4 112.7h7.7M101.4 115.2h7.7M101.4 117.8h7.7M88.7 120.3h7.6M88.7 122.9h7.6M88.7 125.4h7.6M88.7 127.9h7.6M88.7 130.5h7.6M88.7 133h7.6M88.7 135.6h7.6M88.7 138.1h7.6"/>
<path d="M101.4 120.3h7.7M101.4 122.9h7.7M101.4 125.4h7.7M101.4 127.9h7.7M101.4 130.5h7.7M101.4 133h7.7M101.4 135.6h7.7M101.4 138.1h7.7M88.7 140.7h7.6M88.7 143.2h7.6M88.7 145.7h7.6M88.7 148.3h7.6"/>
<path d="M88.7 150.8h7.6M88.7 153.4h7.6M88.7 155.9h7.6M88.7 158.5h7.6M101.4 140.7h7.7M101.4 143.2h7.7M101.4 145.7h7.7M101.4 148.3h7.7M101.4 150.8h7.7M101.4 153.4h7.7M101.4 155.9h7.7M101.4 158.5h7.7"/>
<path d="M88.7 161h7.6M88.7 163.6h7.6M88.7 166.1h7.6M88.7 168.6h7.6M88.7 171.2h7.6M88.7 173.7h7.6M88.7 176.3h7.6M88.7 178.8h7.6M101.4 161h7.7M101.4 163.6h7.7M101.4 166.1h7.7M101.4 168.6h7.7"/>
<path d="M101.4 171.2h7.7M101.4 173.7h7.7M101.4 176.3h7.7M101.4 178.8h7.7M37.8 181.4h5.1M88.7 183.9h7.6M101.4 183.9h7.7"/>
</g>
<path d="M96.3 51.6h5.1v134.9h-5.1z" fill-rule="evenodd" fill="#ffffb0"/>
<path d="M96.3 51.6h5.1v134.9h-5.1z" fill="none" stroke="#800000" stroke-width=".21"/>
<path d="M96.3 181.4h5.1" fill="none" stroke="#000" stroke-width=".25"/>
<g fill="none" stroke="#800000" stroke-width=".25">
<path d="M25.1 189h5.1M25.9 189.8h3.5M26.6 190.5h2.1M27.4 191.3h.5M27.6 186.5v2.5M50.5 189h5.1M51.3 189.8h3.6M52.1 190.5h2M52.8 191.3h.5M53.1 186.5v2.5M83.6 189h5.1M84.4 189.8h3.5"/>
<path d="M85.1 190.5h2.1M85.9 191.3h.5M86.2 186.5v2.5M109.1 189h5M109.8 189.8h3.6M110.6 190.5h2M111.3 191.3h.6M111.6 186.5v2.5"/>
</g>
<path d="M12.4 126.7h11.4l1.3 1.2-1.3 1.3h-11.4z" fill-rule="evenodd" fill="#ffff80"/>
<path d="M12.4 126.7h11.4l1.3 1.2-1.3 1.3h-11.4z" fill="none" stroke="#800000" stroke-width=".21"/>
<path d="M12.4 162.3h11.4l1.3 1.3-1.3 1.2h-11.4z" fill-rule="evenodd" fill="#ffff80"/>
<path d="M12.4 162.3h11.4l1.3 1.3-1.3 1.2h-11.4z" fill="none" stroke="#800000" stroke-width=".21"/>
<path d="M56.9 129.2h11.4v2.6h-11.4l-1.3-1.3z" fill-rule="evenodd" fill="#ffff80"/>
<path d="M56.9 129.2h11.4v2.6h-11.4l-1.3-1.3z" fill="none" stroke="#800000" stroke-width=".21"/>
<path d="M12.4 129.2h11.4l1.3 1.3-1.3 1.3h-11.4z" fill-rule="evenodd" fill="#ffff80"/>
<path d="M12.4 129.2h11.4l1.3 1.3-1.3 1.3h-11.4z" fill="none" stroke="#800000" stroke-width=".21"/>
<path d="M12.4 124.1h11.4l1.3 1.3-1.3 1.3h-11.4z" fill-rule="evenodd" fill="#ffff80"/>
<path d="M12.4 124.1h11.4l1.3 1.3-1.3 1.3h-11.4z" fill="none" stroke="#800000" stroke-width=".21"/>
<path d="M56.9 126.7h11.4v2.5h-11.4l-1.3-1.3z" fill-rule="evenodd" fill="#ffff80"/>
<path d="M56.9 126.7h11.4v2.5h-11.4l-1.3-1.3z" fill="none" stroke="#800000" stroke-width=".21"/>
<path d="M12.4 152.1h11.4l1.3 1.3-1.3 1.3h-11.4z" fill-rule="evenodd" fill="#ffff80"/>
<path d="M12.4 152.1h11.4l1.3 1.3-1.3 1.3h-11.4z" fill="none" stroke="#800000" stroke-width=".21"/>
<path d="M12.4 139.4h11.4l1.3 1.3-1.3 1.2h-11.4z" fill-rule="evenodd" fill="#ffff80"/>
<path d="M12.4 139.4h11.4l1.3 1.3-1.3 1.2h-11.4z" fill="none" stroke="#800000" stroke-width=".21"/>
<path d="M12.4 172.5h11.4l1.3 1.2-1.3 1.3h-11.4z" fill-rule="evenodd" fill="#ffff80"/>
<path d="M12.4 172.5h11.4l1.3 1.2-1.3 1.3h-11.4z" fill="none" stroke="#800000" stroke-width=".21"/>
<path d="M12.4 134.3h11.4l1.3 1.3-1.3 1.2h-11.4z" fill-rule="evenodd" fill="#ffff80"/>
<path d="M12.4 134.3h11.4l1.3 1.3-1.3 1.2h-11.4z" fill="none" stroke="#800000" stroke-width=".21"/>
<path d="M12.4 159.7h11.4l1.3 1.3-1.3 1.3h-11.4z" fill-rule="evenodd" fill="#ffff80"/>
<path d="M12.4 159.7h11.4l1.3 1.3-1.3 1.3h-11.4z" fill="none" stroke="#800000" stroke-width=".21"/>
<path d="M12.4 154.7h11.4l1.3 1.2-1.3 1.3h-11.4z" fill-rule="evenodd" fill="#ffff80"/>
<path d="M12.4 154.7h11.4l1.3 1.2-1.3 1.3h-11.4z" fill="none" stroke="#800000" stroke-width=".21"/>
<path d="M12.4 136.8h11.4l1.3 1.3-1.3 1.3h-11.4z" fill-rule="evenodd" fill="#ffff80"/>
<path d="M12.4 136.8h11.4l1.3 1.3-1.3 1.3h-11.4z" fill="none" stroke="#800000" stroke-width=".21"/>
<path d="M55.6 150.8l1.3-1.2h11.4v2.5h-11.4z" fill-rule="evenodd" fill="#ffff80"/>
<path d="M55.6 150.8l1.3-1.2h11.4v2.5h-11.4z" fill="none" stroke="#800000" stroke-width=".21"/>
<path d="M12.4 141.9h11.4l1.3 1.3-1.3 1.3h-11.4z" fill-rule="evenodd" fill="#ffff80"/>
<path d="M12.4 141.9h11.4l1.3 1.3-1.3 1.3h-11.4z" fill="none" stroke="#800000" stroke-width=".21"/>
<path d="M56.9 147h11.4v2.6h-11.4l-1.3-1.3z" fill-rule="evenodd" fill="#ffff80"/>
<path d="M56.9 147h11.4v2.6h-11.4l-1.3-1.3z" fill="none" stroke="#800000" stroke-width=".21"/>
<path d="M12.4 169.9h11.4l1.3 1.3-1.3 1.3h-11.4z" fill-rule="evenodd" fill="#ffff80"/>
<path d="M12.4 169.9h11.4l1.3 1.3-1.3 1.3h-11.4z" fill="none" stroke="#800000" stroke-width=".21"/>
<path d="M12.4 121.6h11.4l1.3 1.3-1.3 1.2h-11.4z" fill-rule="evenodd" fill="#ffff80"/>
<path d="M12.4 121.6h11.4l1.3 1.3-1.3 1.2h-11.4z" fill="none" stroke="#800000" stroke-width=".21"/>
<path d="M56.9 49.1h2.5M58.2 49.1v2.5M84.9 49.1h2.5M86.2 49.1v2.5M115.4 49.1h2.6M116.7 49.1v2.5" fill="none" stroke="#800000" stroke-width=".25"/>
<path d="M108 58.2l2.1 2.1M110.1 58.2l-2.1 2.1" fill="none" stroke="#f00" stroke-width=".21"/>
<path d="M12.4 175h11.4l1.3 1.3-1.3 1.2h-11.4z" fill-rule="evenodd" fill="#ffff80"/>
<path d="M12.4 175h11.4l1.3 1.3-1.3 1.2h-11.4z" fill="none" stroke="#800000" stroke-width=".21"/>
<path d="M12.4 177.5h11.4l1.3 1.3-1.3 1.3h-11.4z" fill-rule="evenodd" fill="#ffff80"/>
<path d="M12.4 177.5h11.4l1.3 1.3-1.3 1.3h-11.4z" fill="none" stroke="#800000" stroke-width=".21"/>
<path d="M108 88.8l2.1 2M110.1 88.8l-2.1 2" fill="none" stroke="#f00" stroke-width=".21"/>
<path d="M121.8 189h5.1M122.5 189.8h3.6M123.3 190.5h2M124.1 191.3h.5M124.3 186.5v2.5" fill="none" stroke="#800000" stroke-width=".25"/>
<path d="M137 168.6h5.1v17.9h-5.1z" fill-rule="evenodd" fill="#ffffb0"/>
<path d="M137 168.6h5.1v17.9h-5.1z" fill="none" stroke="#800000" stroke-width=".21"/>
<path d="M129.4 171.2h7.6M129.4 173.7h7.6M129.4 176.3h7.6M129.4 178.8h7.6M129.4 181.4h7.6M129.4 183.9h7.6" fill="none" stroke="#000" stroke-width=".25"/>
<path d="M55.6 92.3l1.3-1.2h14v2.5h-14z" fill-rule="evenodd" fill="#ffff80"/>
<path d="M55.6 92.3l1.3-1.2h14v2.5h-14z" fill="none" stroke="#800000" stroke-width=".21"/>
<path d="M115.4 106.3h15.3l1.2 1.3-1.2 1.3h-15.3l-1.3-1.3z" fill-rule="evenodd" fill="#ffff80"/>
<path d="M115.4 106.3h15.3l1.2 1.3-1.2 1.3h-15.3l-1.3-1.3z" fill="none" stroke="#800000" stroke-width=".21"/>
<path d="M114.1 105l1.3-1.2h15.3l1.2 1.2-1.2 1.3h-15.3z" fill-rule="evenodd" fill="#ffff80"/>
<path d="M114.1 105l1.3-1.2h15.3l1.2 1.2-1.2 1.3h-15.3z" fill="none" stroke="#800000" stroke-width=".21"/>
<path d="M114.1 119h16.6l1.2 1.3-1.2 1.3h-16.6z" fill-rule="evenodd" fill="#ffff80"/>
<path d="M114.1 119h16.6l1.2 1.3-1.2 1.3h-16.6z" fill="none" stroke="#800000" stroke-width=".21"/>
<path d="M55.6 94.9l1.3-1.3h14v2.5h-14z" fill-rule="evenodd" fill="#ffff80"/>
<path d="M55.6 94.9l1.3-1.3h14v2.5h-14z" fill="none" stroke="#800000" stroke-width=".21"/>
<path d="M114.1 111.4h16.6l1.2 1.3-1.2 1.3h-16.6z" fill-rule="evenodd" fill="#ffff80"/>
<path d="M114.1 111.4h16.6l1.2 1.3-1.2 1.3h-16.6z" fill="none" stroke="#800000" stroke-width=".21"/>
<path d="M114.1 121.6h16.6l1.2 1.3-1.2 1.2h-16.6z" fill-rule="evenodd" fill="#ffff80"/>
<path d="M114.1 121.6h16.6l1.2 1.3-1.2 1.2h-16.6z" fill="none" stroke="#800000" stroke-width=".21"/>
<path d="M114.1 116.5h16.6l1.2 1.3-1.2 1.2h-16.6z" fill-rule="evenodd" fill="#ffff80"/>
<path d="M114.1 116.5h16.6l1.2 1.3-1.2 1.2h-16.6z" fill="none" stroke="#800000" stroke-width=".21"/>
<path d="M114.1 124.1h16.6l1.2 1.3-1.2 1.3h-16.6z" fill-rule="evenodd" fill="#ffff80"/>
<path d="M114.1 124.1h16.6l1.2 1.3-1.2 1.3h-16.6z" fill="none" stroke="#800000" stroke-width=".21"/>
<path d="M14.9 24.9v3.8M22.6 24.9v3.8M30.2 24.9v3.8M37.8 24.9v3.8" fill="none" stroke="#000" stroke-width=".25"/>
<g fill="none" stroke="#000" stroke-width=".76">
<circle cx="14.9" cy="23.6" r="1.27"/>
<circle cx="22.6" cy="23.6" r="1.27"/>
<circle cx="30.2" cy="23.6" r="1.27"/>
<circle cx="37.8" cy="23.6" r="1.27"/>
</g>
<g fill="none" stroke="#800000" stroke-width=".25">
<path d="M12.4 31.3h5.1M13.1 32h3.6M13.9 32.8h2M14.7 33.6h.5M14.9 28.7v2.6M20 31.3h5.1M20.8 32h3.5M21.5 32.8h2.1M22.3 33.6h.5M22.6 28.7v2.6M27.6 31.3h5.1M28.4 32h3.6"/>
<path d="M29.2 32.8h2M29.9 33.6h.5M30.2 28.7v2.6M35.3 31.3h5.1M36 32h3.6M36.8 32.8h2M37.6 33.6h.5M37.8 28.7v2.6"/>
</g>
<path d="M54.4 30h19v2.5h-19l-1.3-1.2z" fill-rule="evenodd" fill="#ffff80"/>
<path d="M54.4 30h19v2.5h-19l-1.3-1.2z" fill="none" stroke="#800000" stroke-width=".21"/>
<path d="M54.4 32.5h19v2.6h-19l-1.3-1.3z" fill-rule="evenodd" fill="#ffff80"/>
<path d="M54.4 32.5h19v2.6h-19l-1.3-1.3z" fill="none" stroke="#800000" stroke-width=".21"/>
<path d="M54.4 37.6h19v2.6h-19l-1.3-1.3z" fill-rule="evenodd" fill="#ffff80"/>
<path d="M54.4 37.6h19v2.6h-19l-1.3-1.3z" fill="none" stroke="#800000" stroke-width=".21"/>
<path d="M70.9 21.1h5.1M78.5 21.1h5.1" fill="none" stroke="#000" stroke-width=".25"/>
<path d="M76 18.5l2.5 2.6-2.5 2.5z" fill="#00f"/>
<path d="M76 18.5l2.5 2.6-2.5 2.5zM78.5 24.7l1.8 1.7M79.5 23.6l1.8 1.8" fill="none" stroke="#00f" stroke-width=".25"/>
<path d="M80.8 24.4l.5 1-1-.5z" fill="#00f"/>
<path d="M80.8 24.4l.5 1-1-.5z" fill="none" stroke="#00f" stroke-width=".25"/>
<path d="M79.8 25.4l.5 1-1-.5z" fill="#00f"/>
<path d="M78.5 18.5v5.1M60.3 20.1h6v2.1h-6zM79.8 25.4l.5 1-1-.5z" fill="none" stroke="#00f" stroke-width=".25"/>
<path d="M58.2 21.1h2M66.3 21.1h2" fill="none" stroke="#000" stroke-width=".25"/>
<path d="M53.1 19.8v2.6M53.1 21.1h2.5" fill="none" stroke="#800000" stroke-width=".25"/>
<path d="M259.2 46.5h10.1l1.3 .4 1 .9 .3 1.3v5.7l.6 1.1 1.3 .8-1.3 .9-.6 1v8.3l-.3 1.3-1 .9-1.3 .3h-10.1z" fill-rule="evenodd" fill="#edf2fb"/>
<path d="M259.2 46.5h10.1l1.3 .4 1 .9 .3 1.3v5.7l.6 1.1 1.3 .8-1.3 .9-.6 1v8.3l-.3 1.3-1 .9-1.3 .3h-10.1z" fill="none" stroke="#edf2fb" stroke-width=".21"/>
<path d="M269.3 46.5a2.54 2.54 0 0 1 2.6 2.6v5.1a2.55 2.55 0 0 0 2.5 2.5 2.54 2.54 0 0 0-2.5 2.6v7.6a2.53 2.53 0 0 1-2.6 2.5" fill="none" stroke="#8f9ec9" stroke-width=".25"/>
<circle cx="259.1" cy="49.1" r=".26" fill="#003a70"/>
<circle cx="259.1" cy="49.1" r=".26" fill="none" stroke="#003a70" stroke-width=".21"/>
<circle cx="259.1" cy="51.6" r=".26" fill="#003a70"/>
<circle cx="259.1" cy="51.6" r=".26" fill="none" stroke="#003a70" stroke-width=".21"/>
<circle cx="259.1" cy="54.2" r=".26" fill="#003a70"/>
<circle cx="259.1" cy="54.2" r=".26" fill="none" stroke="#003a70" stroke-width=".21"/>
<circle cx="259.1" cy="56.7" r=".26" fill="#003a70"/>
<circle cx="259.1" cy="56.7" r=".26" fill="none" stroke="#003a70" stroke-width=".21"/>
<circle cx="259.1" cy="59.3" r=".26" fill="#003a70"/>
<circle cx="259.1" cy="59.3" r=".26" fill="none" stroke="#003a70" stroke-width=".21"/>
<circle cx="259.1" cy="61.8" r=".26" fill="#003a70"/>
<circle cx="259.1" cy="61.8" r=".26" fill="none" stroke="#003a70" stroke-width=".21"/>
<circle cx="259.1" cy="64.3" r=".26" fill="#003a70"/>
<circle cx="259.1" cy="64.3" r=".26" fill="none" stroke="#003a70" stroke-width=".21"/>
<circle cx="259.1" cy="66.9" r=".26" fill="#003a70"/>
<circle cx="259.1" cy="66.9" r=".26" fill="none" stroke="#003a70" stroke-width=".21"/>
<path d="M259.2 18.6h10.1l1.3 .3 1 .9 .3 1.3v5.7l.6 1.1 1.3 .8-1.3 .9-.6 1v8.3l-.3 1.3-1 .9-1.3 .4h-10.1z" fill-rule="evenodd" fill="#edf2fb"/>
<path d="M259.2 18.6h10.1l1.3 .3 1 .9 .3 1.3v5.7l.6 1.1 1.3 .8-1.3 .9-.6 1v8.3l-.3 1.3-1 .9-1.3 .4h-10.1z" fill="none" stroke="#edf2fb" stroke-width=".21"/>
<path d="M269.3 18.6a2.54 2.54 0 0 1 2.6 2.5v5.1a2.54 2.54 0 0 0 2.5 2.5 2.55 2.55 0 0 0-2.5 2.6v7.6a2.53 2.53 0 0 1-2.6 2.5" fill="none" stroke="#8f9ec9" stroke-width=".25"/>
<circle cx="259.1" cy="21.1" r=".26" fill="#003a70"/>
<circle cx="259.1" cy="21.1" r=".26" fill="none" stroke="#003a70" stroke-width=".21"/>
<circle cx="259.1" cy="23.6" r=".26" fill="#003a70"/>
<circle cx="259.1" cy="23.6" r=".26" fill="none" stroke="#003a70" stroke-width=".21"/>
<circle cx="259.1" cy="26.2" r=".26" fill="#003a70"/>
<circle cx="259.1" cy="26.2" r=".26" fill="none" stroke="#003a70" stroke-width=".21"/>
<circle cx="259.1" cy="28.7" r=".26" fill="#003a70"/>
<circle cx="259.1" cy="28.7" r=".26" fill="none" stroke="#003a70" stroke-width=".21"/>
<circle cx="259.1" cy="31.3" r=".26" fill="#003a70"/>
<circle cx="259.1" cy="31.3" r=".26" fill="none" stroke="#003a70" stroke-width=".21"/>
<circle cx="259.1" cy="33.8" r=".26" fill="#003a70"/>
<circle cx="259.1" cy="33.8" r=".26" fill="none" stroke="#003a70" stroke-width=".21"/>
<circle cx="259.1" cy="36.4" r=".26" fill="#003a70"/>
<circle cx="259.1" cy="36.4" r=".26" fill="none" stroke="#003a70" stroke-width=".21"/>
<circle cx="259.1" cy="38.9" r=".26" fill="#003a70"/>
<circle cx="259.1" cy="38.9" r=".26" fill="none" stroke="#003a70" stroke-width=".21"/>
<g fill="none" stroke="#000" stroke-width=".25">
<path d="M175.2 102.5h7.6M175.2 105.1h7.6M175.2 107.6h7.6M175.2 110.1h7.6M175.2 112.7h7.6M175.2 115.2h7.6M175.2 117.8h7.6M187.9 102.5h7.6M187.9 105.1h7.6M187.9 107.6h7.6M187.9 110.1h7.6M187.9 112.7h7.6"/>
<path d="M187.9 115.2h7.6M187.9 117.8h7.6M175.2 120.3h7.6M175.2 122.9h7.6M175.2 125.4h7.6M175.2 127.9h7.6M175.2 130.5h7.6M175.2 133h7.6M175.2 135.6h7.6M175.2 138.1h7.6M187.9 120.3h7.6M187.9 122.9h7.6"/>
<path d="M187.9 125.4h7.6M187.9 127.9h7.6M187.9 130.5h7.6M187.9 133h7.6M187.9 135.6h7.6M187.9 138.1h7.6M175.2 140.7h7.6M175.2 143.2h7.6M175.2 145.8h7.6M175.2 148.3h7.6M175.2 150.8h7.6M175.2 153.4h7.6"/>
<path d="M175.2 155.9h7.6M175.2 158.5h7.6M187.9 140.7h7.6M187.9 143.2h7.6M187.9 145.8h7.6M187.9 148.3h7.6M187.9 150.8h7.6M187.9 153.4h7.6M187.9 155.9h7.6M187.9 158.5h7.6M175.2 161h7.6M175.2 163.6h7.6"/>
<path d="M175.2 166.1h7.6M175.2 168.6h7.6M175.2 171.2h7.6M175.2 173.7h7.6M175.2 176.3h7.6M187.9 161h7.6M187.9 163.6h7.6M187.9 166.1h7.6M187.9 168.6h7.6M187.9 171.2h7.6M187.9 173.7h7.6M187.9 176.3h7.6"/>
<path d="M175.2 181.4h7.6M187.9 181.4h7.6"/>
</g>
<path d="M182.8 100h5.1v83.9h-5.1z" fill-rule="evenodd" fill="#ffffb0"/>
<path d="M182.8 100h5.1v83.9h-5.1z" fill="none" stroke="#800000" stroke-width=".21"/>
<path d="M182.8 178.8h5.1" fill="none" stroke="#000" stroke-width=".25"/>
<path d="M170.1 189h5.1M170.9 189.8h3.5M171.6 190.5h2.1M172.4 191.3h.5M172.7 186.5v2.5M195.5 189h5.1M196.3 189.8h3.6M197.1 190.5h2M197.8 191.3h.6M198.1 186.5v2.5" fill="none" stroke="#800000" stroke-width=".25"/>
<circle cx="162.5" cy="176.3" r=".51" fill="#000080"/>
<circle cx="162.5" cy="176.3" r=".51" fill="none" stroke="#000080" stroke-width=".21"/>
<path d="M162.5 173.7v2.6" fill="none" stroke="#000" stroke-width=".25"/>
<circle cx="162.5" cy="176.3" r=".51" fill="#000080"/>
<circle cx="162.5" cy="176.3" r=".51" fill="none" stroke="#000080" stroke-width=".21"/>
<g fill="none" stroke="#000" stroke-width=".25">
<path d="M147.2 21.1h2.6M147.2 28.7h2.6M147.2 36.4h2.6M149.8 23.6h2.5M149.8 31.3h2.5M149.8 38.9h2.5M154.8 21.1h2.6M154.8 28.7h2.6M154.8 36.4h2.6M157.4 23.6h2.5M157.4 31.3h2.5M157.4 38.9h2.5"/>
<path d="M210.8 21.1h2M210.8 23.6h2M210.8 28.7h2M210.8 31.3h2M210.8 36.4h2M210.8 38.9h2M219 21.1h2M219 23.6h2M219 28.7h2M219 31.3h2M219 36.4h2M219 38.9h2"/>
<path d="M147.2 51.6h2.6M147.2 59.3h2.6M147.2 44h2.6M149.8 46.5h2.5M149.8 54.2h2.5M154.8 51.6h2.6M154.8 59.3h2.6M154.8 44h2.6M157.4 46.5h2.5M157.4 54.2h2.5M210.8 44h2M210.8 46.5h2"/>
<path d="M210.8 51.6h2M210.8 54.2h2M210.8 59.3h2M219 44h2M219 46.5h2M219 51.6h2M219 54.2h2M219 59.3h2M147.2 66.9h2.6M147.2 74.5h2.6M149.8 61.8h2.5M149.8 69.4h2.5"/>
<path d="M149.8 77.1h2.5M154.8 66.9h2.6M154.8 74.5h2.6M157.4 61.8h2.5M157.4 69.4h2.5M157.4 77.1h2.5M210.8 61.8h2M210.8 66.9h2M210.8 69.4h2M210.8 74.5h2M210.8 77.1h2M219 61.8h2"/>
<path d="M219 66.9h2M219 69.4h2M219 74.5h2M219 77.1h2M147.2 82.1h2.6M147.2 89.8h2.6M149.8 84.7h2.5M149.8 92.3h2.5M154.8 82.1h2.6M154.8 89.8h2.6M157.4 84.7h2.5M157.4 92.3h2.5"/>
<circle cx="162.5" cy="172.5" r="1.27"/>
</g>
<path d="M166.5 108.5h1.1l.5-.5h1l.5 .5h1M166.5 109.1h1.1l.5 .5h1l.5-.5h1" fill="none" stroke="#d0a19e" stroke-width=".25"/>
<path d="M166.5 109.1l-1.5 1" fill="none" stroke="#d0a19e" stroke-width=".21"/>
<path d="M166.3 108.2h1l.5-.5h1l.5 .5h1.1M166.3 108.9h1l.5 .5h1l.5-.5h1.1" fill="none" stroke="#f00" stroke-width=".25"/>
<path d="M166.3 108.9l-1.3 1.2" fill="none" stroke="#f00" stroke-width=".21"/>
<g fill="none" stroke="#00f" stroke-width=".25">
<path d="M151.8 19.1v4M152.8 19.1v4M149.8 21.1h2M149.8 28.7h2M149.8 36.4h2M151.8 26.7v4M151.8 34.4v4M152.3 23.6h2M152.3 31.3h2M152.3 38.9h2M152.8 21.1h2M152.8 26.7v4"/>
<path d="M152.8 34.4v4M152.8 28.7h2M152.8 36.4h2M154.3 21.6v4M154.3 29.3v4M154.3 36.9v4M155.3 23.6h2.1M155.3 21.6v4M155.3 29.3v4M155.3 36.9v4M155.3 31.3h2.1M155.3 38.9h2.1"/>
<path d="M212.9 20.1h6v2.1h-6zM212.9 22.7h6v2h-6zM212.9 27.7h6v2.1h-6zM212.9 30.3h6v2h-6zM212.9 35.4h6v2h-6zM212.9 37.9h6v2.1h-6zM149.8 44h2M149.8 51.6h2M149.8 59.3h2M151.8 42v4M151.8 49.6v4M151.8 57.3v4"/>
<path d="M152.3 46.5h2M152.3 54.2h2M152.8 42v4M152.8 49.6v4M152.8 57.3v4M152.8 44h2M152.8 51.6h2M152.8 59.3h2M154.3 44.5v4M154.3 52.2v4M154.3 59.8v4M155.3 44.5v4"/>
<path d="M155.3 52.2v4M155.3 59.8v4M155.3 46.5h2.1M155.3 54.2h2.1M212.9 43h6v2.1h-6zM212.9 45.6h6v2h-6zM212.9 50.6h6v2.1h-6zM212.9 53.2h6v2h-6zM212.9 58.3h6v2h-6zM149.8 66.9h2M149.8 74.5h2M151.8 64.9v4"/>
<path d="M151.8 72.5v4M152.3 61.8h2M152.3 69.4h2M152.3 77.1h2M152.8 64.9v4M152.8 72.5v4M152.8 66.9h2M152.8 74.5h2M154.3 67.4v4M154.3 75.1v4M155.3 67.4v4M155.3 75.1v4"/>
<path d="M155.3 61.8h2.1M155.3 69.4h2.1M155.3 77.1h2.1M212.9 60.8h6v2.1h-6zM212.9 65.9h6v2h-6zM212.9 68.5h6v2h-6zM212.9 73.5h6v2.1h-6zM212.9 76.1h6v2h-6zM149.8 82.1h2M149.8 89.8h2M151.8 80.1v4.1M151.8 87.8v4"/>
<path d="M152.3 84.7h2M152.3 92.3h2M152.8 80.1v4.1M152.8 87.8v4M152.8 82.1h2M152.8 89.8h2M154.3 82.7v4M154.3 90.3v4M155.3 82.7v4M155.3 90.3v4M155.3 84.7h2.1M155.3 92.3h2.1"/>
</g>
<path d="M265.5 149.6h21.6v2.5h-21.6l-1.3-1.3z" fill-rule="evenodd" fill="#ffff80"/>
<path d="M265.5 149.6h21.6v2.5h-21.6l-1.3-1.3z" fill="none" stroke="#800000" stroke-width=".21"/>
<path d="M264.2 148.3l1.3-1.3h21.6v2.6h-21.6z" fill-rule="evenodd" fill="#ffff80"/>
<path d="M264.2 148.3l1.3-1.3h21.6v2.6h-21.6z" fill="none" stroke="#800000" stroke-width=".21"/>
<path d="M265.5 157.2h21.6v2.5h-21.6l-1.3-1.2z" fill-rule="evenodd" fill="#ffff80"/>
<path d="M265.5 157.2h21.6v2.5h-21.6l-1.3-1.2z" fill="none" stroke="#800000" stroke-width=".21"/>
<path d="M259.2 120.3h10.1l1.3 .3 1 1 .3 1.3v5.7l.6 1 1.3 .9-1.3 .8-.6 1.1v8.3l-.3 1.2-1 1-1.3 .3h-10.1z" fill-rule="evenodd" fill="#edf2fb"/>
<path d="M259.2 120.3h10.1l1.3 .3 1 1 .3 1.3v5.7l.6 1 1.3 .9-1.3 .8-.6 1.1v8.3l-.3 1.2-1 1-1.3 .3h-10.1z" fill="none" stroke="#edf2fb" stroke-width=".21"/>
<path d="M269.3 120.3a2.54 2.54 0 0 1 2.6 2.6v5a2.55 2.55 0 0 0 2.5 2.6 2.54 2.54 0 0 0-2.5 2.5v7.7a2.53 2.53 0 0 1-2.6 2.5" fill="none" stroke="#8f9ec9" stroke-width=".25"/>
<circle cx="259.1" cy="122.9" r=".26" fill="#003a70"/>
<circle cx="259.1" cy="122.9" r=".26" fill="none" stroke="#003a70" stroke-width=".21"/>
<circle cx="259.1" cy="125.4" r=".26" fill="#003a70"/>
<circle cx="259.1" cy="125.4" r=".26" fill="none" stroke="#003a70" stroke-width=".21"/>
<circle cx="259.1" cy="127.9" r=".26" fill="#003a70"/>
<circle cx="259.1" cy="127.9" r=".26" fill="none" stroke="#003a70" stroke-width=".21"/>
<circle cx="259.1" cy="130.5" r=".26" fill="#003a70"/>
<circle cx="259.1" cy="130.5" r=".26" fill="none" stroke="#003a70" stroke-width=".21"/>
<circle cx="259.1" cy="133" r=".26" fill="#003a70"/>
<circle cx="259.1" cy="133" r=".26" fill="none" stroke="#003a70" stroke-width=".21"/>
<circle cx="259.1" cy="135.6" r=".26" fill="#003a70"/>
<circle cx="259.1" cy="135.6" r=".26" fill="none" stroke="#003a70" stroke-width=".21"/>
<circle cx="259.1" cy="138.1" r=".26" fill="#003a70"/>
<circle cx="259.1" cy="138.1" r=".26" fill="none" stroke="#003a70" stroke-width=".21"/>
<circle cx="259.1" cy="140.7" r=".26" fill="#003a70"/>
<circle cx="259.1" cy="140.7" r=".26" fill="none" stroke="#003a70" stroke-width=".21"/>
<path d="M259.2 92.3h10.1l1.3 .3 1 1 .3 1.3v5.7l.6 1.1 1.3 .8-1.3 .9-.6 1v8.3l-.3 1.3-1 .9-1.3 .3h-10.1z" fill-rule="evenodd" fill="#edf2fb"/>
<path d="M259.2 92.3h10.1l1.3 .3 1 1 .3 1.3v5.7l.6 1.1 1.3 .8-1.3 .9-.6 1v8.3l-.3 1.3-1 .9-1.3 .3h-10.1z" fill="none" stroke="#edf2fb" stroke-width=".21"/>
<path d="M269.3 92.3a2.53 2.53 0 0 1 2.6 2.6v5.1a2.54 2.54 0 0 0 2.5 2.5 2.55 2.55 0 0 0-2.5 2.6v7.6a2.53 2.53 0 0 1-2.6 2.5" fill="none" stroke="#8f9ec9" stroke-width=".25"/>
<circle cx="259.1" cy="94.9" r=".26" fill="#003a70"/>
<circle cx="259.1" cy="94.9" r=".26" fill="none" stroke="#003a70" stroke-width=".21"/>
<circle cx="259.1" cy="97.4" r=".26" fill="#003a70"/>
<circle cx="259.1" cy="97.4" r=".26" fill="none" stroke="#003a70" stroke-width=".21"/>
<circle cx="259.1" cy="100" r=".26" fill="#003a70"/>
<circle cx="259.1" cy="100" r=".26" fill="none" stroke="#003a70" stroke-width=".21"/>
<circle cx="259.1" cy="102.5" r=".26" fill="#003a70"/>
<circle cx="259.1" cy="102.5" r=".26" fill="none" stroke="#003a70" stroke-width=".21"/>
<circle cx="259.1" cy="105.1" r=".26" fill="#003a70"/>
<circle cx="259.1" cy="105.1" r=".26" fill="none" stroke="#003a70" stroke-width=".21"/>
<circle cx="259.1" cy="107.6" r=".26" fill="#003a70"/>
<circle cx="259.1" cy="107.6" r=".26" fill="none" stroke="#003a70" stroke-width=".21"/>
<circle cx="259.1" cy="110.1" r=".26" fill="#003a70"/>
<circle cx="259.1" cy="110.1" r=".26" fill="none" stroke="#003a70" stroke-width=".21"/>
<circle cx="259.1" cy="112.7" r=".26" fill="#003a70"/>
<circle cx="259.1" cy="112.7" r=".26" fill="none" stroke="#003a70" stroke-width=".21"/>
<path d="M278.4 129.5h7.6l1.3 1.2-1.3 1.3h-7.6l-1.3-1.3z" fill-rule="evenodd" fill="#bac0ca"/>
<path d="M278.4 129.5h7.6l1.3 1.2-1.3 1.3h-7.6l-1.3-1.3z" fill="none" stroke="#a6acb6" stroke-width=".21"/>
<path d="M278.2 129.2h7.7l1.2 1.3-1.2 1.3h-7.7l-1.2-1.3z" fill-rule="evenodd" fill="#d5e4ff"/>
<path d="M278.2 129.2h7.7l1.2 1.3-1.2 1.3h-7.7l-1.2-1.3z" fill="none" stroke="#71809b" stroke-width=".21"/>
<path d="M277.1 102.8l1.3-1.3h7.6l1.3 1.3-1.3 1.2h-7.6z" fill-rule="evenodd" fill="#bac0ca"/>
<path d="M277.1 102.8l1.3-1.3h7.6l1.3 1.3-1.3 1.2h-7.6z" fill="none" stroke="#a6acb6" stroke-width=".21"/>
<path d="M277 102.5l1.2-1.3h7.7l1.2 1.3-1.2 1.3h-7.7z" fill-rule="evenodd" fill="#d5e4ff"/>
<path d="M277 102.5l1.2-1.3h7.7l1.2 1.3-1.2 1.3h-7.7z" fill="none" stroke="#71809b" stroke-width=".21"/>
<path d="M231.2 84.7h2M239.3 84.7h2M231.2 158.5h2M239.3 158.5h2" fill="none" stroke="#000" stroke-width=".25"/>
<path d="M233.2 83.7h6.1v2.1h-6.1zM233.2 157.5h6.1v2h-6.1z" fill="none" stroke="#00f" stroke-width=".25"/>
<path d="M114.1 108.9h16.6l1.2 1.2-1.2 1.3h-16.6z" fill-rule="evenodd" fill="#ffff80"/>
<path d="M114.1 108.9h16.6l1.2 1.2-1.2 1.3h-16.6z" fill="none" stroke="#800000" stroke-width=".21"/>
<path d="M54.4 35.1h19v2.5h-19l-1.3-1.2z" fill-rule="evenodd" fill="#ffff80"/>
<path d="M54.4 35.1h19v2.5h-19l-1.3-1.2z" fill="none" stroke="#800000" stroke-width=".21"/>
<g fill="none" stroke="#d0a19e" stroke-width=".25">
<path d="M166.5 111h1.1l.5-.5h1l.5 .5h1M166.5 111.7h1.1l.5 .5h1l.5-.5h1M166.5 116.1h1.1l.5-.5h1l.5 .5h1M166.5 116.7h1.1l.5 .6h1l.5-.6h1M166.5 118.7h1.1l.5-.6h1l.5 .6h1M166.5 119.3h1.1l.5 .5h1l.5-.5h1M217.4 108.5h1.1l.5-.5h1l.5 .5h1M217.4 109.1h1.1l.5 .5h1l.5-.5h1M217.4 111h1.1l.5-.5h1l.5 .5h1M217.4 111.7h1.1l.5 .5h1l.5-.5h1M217.4 116.1h1.1l.5-.5h1l.5 .5h1M217.4 116.7h1.1l.5 .6h1l.5-.6h1"/>
<path d="M217.4 118.7h1.1l.5-.5h1l.5 .5h1M217.4 119.3h1.1l.5 .5h1l.5-.5h1M166.5 123.7h1.1l.5-.5h1l.5 .5h1M166.5 124.4h1.1l.5 .5h1l.5-.5h1M166.5 126.3h1.1l.5-.5h1l.5 .5h1M166.5 126.9h1.1l.5 .5h1l.5-.5h1M166.5 131.4h1.1l.5-.5h1l.5 .5h1M166.5 132h1.1l.5 .5h1l.5-.5h1M166.5 133.9h1.1l.5-.5h1l.5 .5h1M166.5 134.6h1.1l.5 .5h1l.5-.5h1M166.5 139h1.1l.5-.5h1l.5 .5h1M166.5 139.6h1.1l.5 .5h1l.5-.5h1"/>
<path d="M217.4 123.8h1.1l.5-.6h1l.5 .6h1M217.4 124.4h1.1l.5 .5h1l.5-.5h1M217.4 126.3h1.1l.5-.5h1l.5 .5h1M217.4 126.9h1.1l.5 .5h1l.5-.5h1M217.4 131.4h1.1l.5-.5h1l.5 .5h1M217.4 132h1.1l.5 .5h1l.5-.5h1M217.4 133.9h1.1l.5-.5h1l.5 .5h1M217.4 134.6h1.1l.5 .5h1l.5-.5h1M166.5 141.6h1.1l.5-.6h1l.5 .6h1M166.5 142.2h1.1l.5 .5h1l.5-.5h1"/>
</g>
<g fill="none" stroke="#d0a19e" stroke-width=".21">
<path d="M166.5 111.7l-1.5 1M166.5 116.7l-1.5 1.1M166.5 119.3l-1.5 1M217.4 109.1l-1.5 1M217.4 111.7l-1.5 1M217.4 116.7l-1.5 1.1M217.4 119.3l-1.5 1M166.5 124.4l-1.5 1M166.5 126.9l-1.5 1M166.5 132l-1.5 1M166.5 134.6l-1.5 1M166.5 139.6l-1.5 1.1"/>
<path d="M217.4 124.4l-1.5 1M217.4 126.9l-1.5 1M217.4 132l-1.5 1M217.4 134.6l-1.5 1M166.5 142.2l-1.5 1"/>
</g>
<g fill="none" stroke="#f00" stroke-width=".25">
<path d="M166.3 110.8h1l.5-.5h1l.5 .5h1.1M166.3 111.4h1l.5 .5h1l.5-.5h1.1M166.3 115.9h1l.5-.6h1l.5 .6h1.1M166.3 116.5h1l.5 .5h1l.5-.5h1.1M166.3 118.4h1l.5-.5h1l.5 .5h1.1M166.3 119h1l.5 .5h1l.5-.5h1.1M217.2 108.2h1l.5-.5h1l.5 .5h1M217.2 108.9h1l.5 .5h1l.5-.5h1M217.2 110.8h1l.5-.5h1l.5 .5h1M217.2 111.4h1l.5 .5h1l.5-.5h1M217.2 115.9h1l.5-.6h1l.5 .6h1M217.2 116.5h1l.5 .5h1l.5-.5h1"/>
<path d="M217.2 118.4h1l.5-.5h1l.5 .5h1M217.2 119h1l.5 .5h1l.5-.5h1M166.3 123.5h1l.5-.5h1l.5 .5h1.1M166.3 124.1h1l.5 .5h1l.5-.5h1.1M166.3 126h1l.5-.5h1l.5 .5h1.1M166.3 126.7h1l.5 .5h1l.5-.5h1.1M166.3 131.1h1l.5-.5h1l.5 .5h1.1M166.3 131.8h1l.5 .5h1l.5-.5h1.1M166.3 133.7h1l.5-.5h1l.5 .5h1.1M166.3 134.3h1l.5 .5h1l.5-.5h1.1M166.3 138.8h1l.5-.6h1l.5 .6h1.1M166.3 139.4h1l.5 .5h1l.5-.5h1.1"/>
<path d="M217.2 123.5h1l.5-.5h1l.5 .5h1M217.2 124.1h1l.5 .5h1l.5-.5h1M217.2 126h1l.5-.5h1l.5 .5h1M217.2 126.7h1l.5 .5h1l.5-.5h1M217.2 131.1h1l.5-.5h1l.5 .5h1M217.2 131.8h1l.5 .5h1l.5-.5h1M217.2 133.7h1l.5-.5h1l.5 .5h1M217.2 134.3h1l.5 .5h1l.5-.5h1M166.3 141.3h1l.5-.5h1l.5 .5h1.1M166.3 141.9h1l.5 .5h1l.5-.5h1.1"/>
</g>
<g fill="none" stroke="#f00" stroke-width=".21">
<path d="M166.3 111.4l-1.3 1.3M166.3 116.5l-1.3 1.3M166.3 119l-1.3 1.3M217.2 108.9l-1.3 1.2M217.2 111.4l-1.3 1.3M217.2 116.5l-1.3 1.3M217.2 119l-1.3 1.3M166.3 124.1l-1.3 1.3M166.3 126.7l-1.3 1.2M166.3 131.8l-1.3 1.2M166.3 134.3l-1.3 1.3M166.3 139.4l-1.3 1.3"/>
<path d="M217.2 124.1l-1.3 1.3M217.2 126.7l-1.3 1.2M217.2 131.8l-1.3 1.2M217.2 134.3l-1.3 1.3M166.3 141.9l-1.3 1.3"/>
</g>
<path d="M55.6 135.6l1.3-1.3h16.5v2.5h-16.5z" fill-rule="evenodd" fill="#ffff80"/>
<path d="M55.6 135.6l1.3-1.3h16.5v2.5h-16.5z" fill="none" stroke="#800000" stroke-width=".21"/>
<path d="M11.1 66.9h2.5M12.4 66.9v2.5M73.4 166.1h2.6M76 163.6v5M76.7 164.3v3.6M77.5 165.1v2M78.3 165.8v.6" fill="none" stroke="#800000" stroke-width=".25"/>
<path d="M12.4 74.5v2M17.5 74.5v2M12.4 82.7v2M17.5 82.7v2M63.3 166.1h2M71.4 166.1h2" fill="none" stroke="#000" stroke-width=".25"/>
<path d="M11.4 76.6h2v6h-2zM16.5 76.6h2v6h-2zM65.3 165h6.1v2.1h-6.1z" fill="none" stroke="#00f" stroke-width=".25"/>
<circle cx="12.4" cy="89.8" r=".51" fill="#000080"/>
<circle cx="12.4" cy="89.8" r=".51" fill="none" stroke="#000080" stroke-width=".21"/>
<path d="M12.4 89.8v2.5" fill="none" stroke="#000" stroke-width=".25"/>
<circle cx="12.4" cy="89.8" r=".51" fill="#000080"/>
<circle cx="12.4" cy="89.8" r=".51" fill="none" stroke="#000080" stroke-width=".21"/>
<g fill="none" stroke="#000" stroke-width=".25">
<path d="M68.3 74.5h2.1M76.5 74.5h2"/>
<circle cx="12.4" cy="93.6" r="1.27"/>
</g>
<path d="M63.3 73.2v2.6M63.3 74.5h2.5M70.9 64.3h2.5M73.4 63.1v2.5" fill="none" stroke="#800000" stroke-width=".25"/>
<path d="M70.4 73.5h6v2h-6z" fill="none" stroke="#00f" stroke-width=".25"/>
<circle cx="233.7" cy="176.3" r=".51" fill="#000080"/>
<circle cx="233.7" cy="176.3" r=".51" fill="none" stroke="#000080" stroke-width=".21"/>
<path d="M233.7 176.3v2.5M233.7 183.9v2.6" fill="none" stroke="#000" stroke-width=".25"/>
<circle cx="233.7" cy="176.3" r=".51" fill="#000080"/>
<circle cx="233.7" cy="176.3" r=".51" fill="none" stroke="#000080" stroke-width=".21"/>
<path d="M233.7 178.8v2.1M231.7 181.9h4M231.7 180.9h4M233.7 181.9v2" fill="none" stroke="#00f" stroke-width=".25"/>
<path d="M231.2 189h5.1M231.9 189.8h3.6M232.7 190.5h2M233.5 191.3h.5M233.7 186.5v2.5M238.8 189h5.1M239.6 189.8h3.5M240.3 190.5h2.1M241.1 191.3h.5M241.3 186.5v2.5" fill="none" stroke="#800000" stroke-width=".25"/>
<path d="M273.4 182.9l2 2M275.4 182.9l-2 2" fill="none" stroke="#f00" stroke-width=".21"/>
<circle cx="279.5" cy="176.3" r=".51" fill="#000080"/>
<circle cx="279.5" cy="176.3" r=".51" fill="none" stroke="#000080" stroke-width=".21"/>
<path d="M279.5 176.3v2.5M279.5 183.9v2.6" fill="none" stroke="#000" stroke-width=".25"/>
<circle cx="279.5" cy="176.3" r=".51" fill="#000080"/>
<circle cx="279.5" cy="176.3" r=".51" fill="none" stroke="#000080" stroke-width=".21"/>
<path d="M279.5 178.8v2.1M277.5 181.9h4M277.5 180.9h4M279.5 181.9v2" fill="none" stroke="#00f" stroke-width=".25"/>
<path d="M207 171.2h2.5M208.3 171.2v2.5M283.3 171.2h2.6M284.6 171.2v2.5M277 189h5M277.7 189.8h3.6M278.5 190.5h2M279.3 191.3h.5M279.5 186.5v2.5" fill="none" stroke="#800000" stroke-width=".25"/>
<path d="M251.5 173.7h15.3v12.8h-15.3z" fill-rule="evenodd" fill="#ffffb0"/>
<path d="M251.5 173.7h15.3v12.8h-15.3z" fill="none" stroke="#800000" stroke-width=".21"/>
<path d="M218.5 176.3h2M226.6 176.3h2M243.9 176.3h7.6M243.9 178.8h7.6M266.8 176.3h7.6M243.9 183.9h7.6M266.8 183.9h7.6" fill="none" stroke="#000" stroke-width=".25"/>
<path d="M220.5 175.3h6v2h-6z" fill="none" stroke="#00f" stroke-width=".25"/>
<circle cx="215.9" cy="176.3" r=".51" fill="#000080"/>
<circle cx="215.9" cy="176.3" r=".51" fill="none" stroke="#000080" stroke-width=".21"/>
<path d="M215.9 173.7v2.6" fill="none" stroke="#000" stroke-width=".25"/>
<circle cx="215.9" cy="176.3" r=".51" fill="#000080"/>
<circle cx="215.9" cy="176.3" r=".51" fill="none" stroke="#000080" stroke-width=".21"/>
<circle cx="215.9" cy="172.5" r="1.27" fill="none" stroke="#000" stroke-width=".25"/>
<circle cx="231.2" cy="176.3" r=".51" fill="#000080"/>
<circle cx="231.2" cy="176.3" r=".51" fill="none" stroke="#000080" stroke-width=".21"/>
<path d="M231.2 173.7v2.6" fill="none" stroke="#000" stroke-width=".25"/>
<circle cx="231.2" cy="176.3" r=".51" fill="#000080"/>
<circle cx="231.2" cy="176.3" r=".51" fill="none" stroke="#000080" stroke-width=".21"/>
<circle cx="231.2" cy="172.5" r="1.27" fill="none" stroke="#000" stroke-width=".25"/>
<circle cx="277" cy="176.3" r=".51" fill="#000080"/>
<circle cx="277" cy="176.3" r=".51" fill="none" stroke="#000080" stroke-width=".21"/>
<path d="M277 173.7v2.6" fill="none" stroke="#000" stroke-width=".25"/>
<circle cx="277" cy="176.3" r=".51" fill="#000080"/>
<circle cx="277" cy="176.3" r=".51" fill="none" stroke="#000080" stroke-width=".21"/>
<circle cx="277" cy="172.5" r="1.27" fill="none" stroke="#000" stroke-width=".25"/>
<path d="M64.5 169.9h7.7l1.2 1.3-1.2 1.3h-7.7l-1.2-1.3z" fill-rule="evenodd" fill="#ffff80"/>
<path d="M64.5 169.9h7.7l1.2 1.3-1.2 1.3h-7.7l-1.2-1.3z" fill="none" stroke="#800000" stroke-width=".21"/>
<path d="M243.9 49.1h15.3M243.9 51.6h15.3M243.9 54.2h15.3M243.9 56.7h15.3M243.9 59.3h15.3M243.9 61.8h15.3M243.9 66.9h15.3M243.9 64.3h15.3M30.2 183.9h-2.6v2.6" fill="none" stroke="#000080" stroke-width=".25"/>
<circle cx="27.6" cy="183.9" r=".51" fill="#000080"/>
<circle cx="27.6" cy="183.9" r=".51" fill="none" stroke="#000080" stroke-width=".21"/>
<path d="M50.5 183.9h2.6v2.6" fill="none" stroke="#000080" stroke-width=".25"/>
<circle cx="53.1" cy="183.9" r=".51" fill="#000080"/>
<circle cx="53.1" cy="183.9" r=".51" fill="none" stroke="#000080" stroke-width=".21"/>
<path d="M88.7 183.9h-2.5v2.6" fill="none" stroke="#000080" stroke-width=".25"/>
<circle cx="86.2" cy="183.9" r=".51" fill="#000080"/>
<circle cx="86.2" cy="183.9" r=".51" fill="none" stroke="#000080" stroke-width=".21"/>
<path d="M109.1 183.9h2.5v2.6" fill="none" stroke="#000080" stroke-width=".25"/>
<circle cx="111.6" cy="183.9" r=".51" fill="#000080"/>
<circle cx="111.6" cy="183.9" r=".51" fill="none" stroke="#000080" stroke-width=".21"/>
<path d="M27.6 61.8h2.6" fill="none" stroke="#000080" stroke-width=".25"/>
<circle cx="27.6" cy="61.8" r=".51" fill="#000080"/>
<circle cx="27.6" cy="61.8" r=".51" fill="none" stroke="#000080" stroke-width=".21"/>
<path d="M27.6 77.1h2.6" fill="none" stroke="#000080" stroke-width=".25"/>
<circle cx="27.6" cy="77.1" r=".51" fill="#000080"/>
<circle cx="27.6" cy="77.1" r=".51" fill="none" stroke="#000080" stroke-width=".21"/>
<path d="M27.6 84.7h2.6" fill="none" stroke="#000080" stroke-width=".25"/>
<circle cx="27.6" cy="84.7" r=".51" fill="#000080"/>
<circle cx="27.6" cy="84.7" r=".51" fill="none" stroke="#000080" stroke-width=".21"/>
<path d="M27.6 94.9h2.6" fill="none" stroke="#000080" stroke-width=".25"/>
<circle cx="27.6" cy="94.9" r=".51" fill="#000080"/>
<circle cx="27.6" cy="94.9" r=".51" fill="none" stroke="#000080" stroke-width=".21"/>
<path d="M27.6 107.6h2.6" fill="none" stroke="#000080" stroke-width=".25"/>
<circle cx="27.6" cy="107.6" r=".51" fill="#000080"/>
<circle cx="27.6" cy="107.6" r=".51" fill="none" stroke="#000080" stroke-width=".21"/>
<path d="M27.6 120.3h2.6" fill="none" stroke="#000080" stroke-width=".25"/>
<circle cx="27.6" cy="120.3" r=".51" fill="#000080"/>
<circle cx="27.6" cy="120.3" r=".51" fill="none" stroke="#000080" stroke-width=".21"/>
<path d="M27.6 133h2.6" fill="none" stroke="#000080" stroke-width=".25"/>
<circle cx="27.6" cy="133" r=".51" fill="#000080"/>
<circle cx="27.6" cy="133" r=".51" fill="none" stroke="#000080" stroke-width=".21"/>
<path d="M27.6 145.7h2.6" fill="none" stroke="#000080" stroke-width=".25"/>
<circle cx="27.6" cy="145.7" r=".51" fill="#000080"/>
<circle cx="27.6" cy="145.7" r=".51" fill="none" stroke="#000080" stroke-width=".21"/>
<path d="M27.6 158.5h2.6" fill="none" stroke="#000080" stroke-width=".25"/>
<circle cx="27.6" cy="158.5" r=".51" fill="#000080"/>
<circle cx="27.6" cy="158.5" r=".51" fill="none" stroke="#000080" stroke-width=".21"/>
<path d="M27.6 166.1h2.6" fill="none" stroke="#000080" stroke-width=".25"/>
<circle cx="27.6" cy="166.1" r=".51" fill="#000080"/>
<circle cx="27.6" cy="166.1" r=".51" fill="none" stroke="#000080" stroke-width=".21"/>
<path d="M50.5 89.8h2.6v30.5h-2.6" fill="none" stroke="#000080" stroke-width=".25"/>
<circle cx="53.1" cy="120.3" r=".51" fill="#000080"/>
<circle cx="53.1" cy="120.3" r=".51" fill="none" stroke="#000080" stroke-width=".21"/>
<path d="M53.1 120.3v12.7h-2.6" fill="none" stroke="#000080" stroke-width=".25"/>
<circle cx="53.1" cy="120.3" r=".51" fill="#000080"/>
<circle cx="53.1" cy="120.3" r=".51" fill="none" stroke="#000080" stroke-width=".21"/>
<circle cx="53.1" cy="133" r=".51" fill="#000080"/>
<circle cx="53.1" cy="133" r=".51" fill="none" stroke="#000080" stroke-width=".21"/>
<path d="M53.1 133v12.7h-2.6" fill="none" stroke="#000080" stroke-width=".25"/>
<circle cx="53.1" cy="133" r=".51" fill="#000080"/>
<circle cx="53.1" cy="133" r=".51" fill="none" stroke="#000080" stroke-width=".21"/>
<circle cx="53.1" cy="145.7" r=".51" fill="#000080"/>
<circle cx="53.1" cy="145.7" r=".51" fill="none" stroke="#000080" stroke-width=".21"/>
<path d="M53.1 145.8v38.1" fill="none" stroke="#000080" stroke-width=".25"/>
<circle cx="53.1" cy="145.7" r=".51" fill="#000080"/>
<circle cx="53.1" cy="145.7" r=".51" fill="none" stroke="#000080" stroke-width=".21"/>
<circle cx="53.1" cy="183.9" r=".51" fill="#000080"/>
<circle cx="53.1" cy="183.9" r=".51" fill="none" stroke="#000080" stroke-width=".21"/>
<path d="M50.5 56.7h7.7" fill="none" stroke="#000080" stroke-width=".25"/>
<circle cx="58.2" cy="56.7" r=".51" fill="#000080"/>
<circle cx="58.2" cy="56.7" r=".51" fill="none" stroke="#000080" stroke-width=".21"/>
<path d="M50.5 54.2h7.7" fill="none" stroke="#000080" stroke-width=".25"/>
<circle cx="58.2" cy="54.2" r=".51" fill="#000080"/>
<circle cx="58.2" cy="54.2" r=".51" fill="none" stroke="#000080" stroke-width=".21"/>
<path d="M58.2 69.4v2.6h-7.7" fill="none" stroke="#000080" stroke-width=".25"/>
<circle cx="58.2" cy="69.4" r=".51" fill="#000080"/>
<circle cx="58.2" cy="69.4" r=".51" fill="none" stroke="#000080" stroke-width=".21"/>
<g fill="none" stroke="#000080" stroke-width=".25">
<path d="M86.2 54.2h2.5M25.1 130.5h5.1M25.1 127.9h5.1M25.1 125.4h5.1M25.1 122.9h5.1M25.1 138.1h5.1M25.1 135.6h5.1M50.5 130.5h5.1M50.5 127.9h5.1M25.1 143.2h5.1M25.1 140.7h5.1M25.1 155.9h5.1"/>
<path d="M25.1 153.4h5.1M50.5 150.8h5.1M50.5 148.3h5.1M25.1 163.6h5.1M25.1 161h5.1M25.1 171.2h5.1M25.1 173.7h5.1M25.1 178.8h5.1M25.1 176.3h5.1"/>
</g>
<circle cx="86.2" cy="54.2" r=".51" fill="#000080"/>
<circle cx="86.2" cy="54.2" r=".51" fill="none" stroke="#000080" stroke-width=".21"/>
<path d="M86.2 59.3v2.5h2.5" fill="none" stroke="#000080" stroke-width=".25"/>
<circle cx="86.2" cy="59.3" r=".51" fill="#000080"/>
<circle cx="86.2" cy="59.3" r=".51" fill="none" stroke="#000080" stroke-width=".21"/>
<path d="M116.7 54.2v2.5h-7.6" fill="none" stroke="#000080" stroke-width=".25"/>
<circle cx="116.7" cy="56.7" r=".51" fill="#000080"/>
<circle cx="116.7" cy="56.7" r=".51" fill="none" stroke="#000080" stroke-width=".21"/>
<circle cx="116.7" cy="54.2" r=".51" fill="#000080"/>
<circle cx="116.7" cy="54.2" r=".51" fill="none" stroke="#000080" stroke-width=".21"/>
<path d="M116.7 61.8v2.5h-7.6" fill="none" stroke="#000080" stroke-width=".25"/>
<circle cx="116.7" cy="61.8" r=".51" fill="#000080"/>
<circle cx="116.7" cy="61.8" r=".51" fill="none" stroke="#000080" stroke-width=".21"/>
<path d="M86.2 56.7v2.6h2.5M50.5 173.7h10.2M109.1 171.2h20.3M109.1 173.7h20.3M109.1 176.3h20.3M109.1 178.8h20.3" fill="none" stroke="#000080" stroke-width=".25"/>
<circle cx="86.2" cy="59.3" r=".51" fill="#000080"/>
<circle cx="86.2" cy="59.3" r=".51" fill="none" stroke="#000080" stroke-width=".21"/>
<circle cx="86.2" cy="56.7" r=".51" fill="#000080"/>
<circle cx="86.2" cy="56.7" r=".51" fill="none" stroke="#000080" stroke-width=".21"/>
<path d="M86.2 89.8h2.5" fill="none" stroke="#000080" stroke-width=".25"/>
<circle cx="86.2" cy="89.8" r=".51" fill="#000080"/>
<circle cx="86.2" cy="89.8" r=".51" fill="none" stroke="#000080" stroke-width=".21"/>
<path d="M86.2 102.5h2.5" fill="none" stroke="#000080" stroke-width=".25"/>
<circle cx="86.2" cy="102.5" r=".51" fill="#000080"/>
<circle cx="86.2" cy="102.5" r=".51" fill="none" stroke="#000080" stroke-width=".21"/>
<path d="M86.2 115.2h2.5" fill="none" stroke="#000080" stroke-width=".25"/>
<circle cx="86.2" cy="115.2" r=".51" fill="#000080"/>
<circle cx="86.2" cy="115.2" r=".51" fill="none" stroke="#000080" stroke-width=".21"/>
<path d="M86.2 127.9h2.5" fill="none" stroke="#000080" stroke-width=".25"/>
<circle cx="86.2" cy="127.9" r=".51" fill="#000080"/>
<circle cx="86.2" cy="127.9" r=".51" fill="none" stroke="#000080" stroke-width=".21"/>
<path d="M86.2 140.7h2.5" fill="none" stroke="#000080" stroke-width=".25"/>
<circle cx="86.2" cy="140.7" r=".51" fill="#000080"/>
<circle cx="86.2" cy="140.7" r=".51" fill="none" stroke="#000080" stroke-width=".21"/>
<path d="M86.2 153.4h2.5" fill="none" stroke="#000080" stroke-width=".25"/>
<circle cx="86.2" cy="153.4" r=".51" fill="#000080"/>
<circle cx="86.2" cy="153.4" r=".51" fill="none" stroke="#000080" stroke-width=".21"/>
<path d="M86.2 166.1h2.5" fill="none" stroke="#000080" stroke-width=".25"/>
<circle cx="86.2" cy="166.1" r=".51" fill="#000080"/>
<circle cx="86.2" cy="166.1" r=".51" fill="none" stroke="#000080" stroke-width=".21"/>
<path d="M109.1 115.2h2.5" fill="none" stroke="#000080" stroke-width=".25"/>
<circle cx="111.6" cy="115.2" r=".51" fill="#000080"/>
<circle cx="111.6" cy="115.2" r=".51" fill="none" stroke="#000080" stroke-width=".21"/>
<path d="M109.1 127.9h2.5" fill="none" stroke="#000080" stroke-width=".25"/>
<circle cx="111.6" cy="127.9" r=".51" fill="#000080"/>
<circle cx="111.6" cy="127.9" r=".51" fill="none" stroke="#000080" stroke-width=".21"/>
<path d="M109.1 140.7h2.5" fill="none" stroke="#000080" stroke-width=".25"/>
<circle cx="111.6" cy="140.7" r=".51" fill="#000080"/>
<circle cx="111.6" cy="140.7" r=".51" fill="none" stroke="#000080" stroke-width=".21"/>
<path d="M109.1 153.4h2.5" fill="none" stroke="#000080" stroke-width=".25"/>
<circle cx="111.6" cy="153.4" r=".51" fill="#000080"/>
<circle cx="111.6" cy="153.4" r=".51" fill="none" stroke="#000080" stroke-width=".21"/>
<g fill="none" stroke="#000080" stroke-width=".25">
<path d="M30.2 54.2h-2.6v129.7M243.9 77.1h20.3M243.9 74.5h20.3M70.9 94.9h17.8M70.9 92.3h17.8M241.3 84.7h22.9M109.1 105h5M109.1 107.6h5M109.1 112.7h5M109.1 117.8h5M109.1 120.3h5M109.1 122.9h5"/>
<path d="M109.1 125.4h5M109.1 168.6h17.8v15.3h2.5M129.4 181.4h-5.1v5.1"/>
</g>
<circle cx="27.6" cy="61.8" r=".51" fill="#000080"/>
<circle cx="27.6" cy="61.8" r=".51" fill="none" stroke="#000080" stroke-width=".21"/>
<circle cx="27.6" cy="77.1" r=".51" fill="#000080"/>
<circle cx="27.6" cy="77.1" r=".51" fill="none" stroke="#000080" stroke-width=".21"/>
<circle cx="27.6" cy="84.7" r=".51" fill="#000080"/>
<circle cx="27.6" cy="84.7" r=".51" fill="none" stroke="#000080" stroke-width=".21"/>
<circle cx="27.6" cy="94.9" r=".51" fill="#000080"/>
<circle cx="27.6" cy="94.9" r=".51" fill="none" stroke="#000080" stroke-width=".21"/>
<circle cx="27.6" cy="107.6" r=".51" fill="#000080"/>
<circle cx="27.6" cy="107.6" r=".51" fill="none" stroke="#000080" stroke-width=".21"/>
<circle cx="27.6" cy="120.3" r=".51" fill="#000080"/>
<circle cx="27.6" cy="120.3" r=".51" fill="none" stroke="#000080" stroke-width=".21"/>
<circle cx="27.6" cy="133" r=".51" fill="#000080"/>
<circle cx="27.6" cy="133" r=".51" fill="none" stroke="#000080" stroke-width=".21"/>
<circle cx="27.6" cy="145.7" r=".51" fill="#000080"/>
<circle cx="27.6" cy="145.7" r=".51" fill="none" stroke="#000080" stroke-width=".21"/>
<circle cx="27.6" cy="158.5" r=".51" fill="#000080"/>
<circle cx="27.6" cy="158.5" r=".51" fill="none" stroke="#000080" stroke-width=".21"/>
<circle cx="27.6" cy="166.1" r=".51" fill="#000080"/>
<circle cx="27.6" cy="166.1" r=".51" fill="none" stroke="#000080" stroke-width=".21"/>
<circle cx="27.6" cy="183.9" r=".51" fill="#000080"/>
<circle cx="27.6" cy="183.9" r=".51" fill="none" stroke="#000080" stroke-width=".21"/>
<path d="M58.2 59.3v10.1h-7.7" fill="none" stroke="#000080" stroke-width=".25"/>
<circle cx="58.2" cy="59.3" r=".51" fill="#000080"/>
<circle cx="58.2" cy="59.3" r=".51" fill="none" stroke="#000080" stroke-width=".21"/>
<circle cx="58.2" cy="69.4" r=".51" fill="#000080"/>
<circle cx="58.2" cy="69.4" r=".51" fill="none" stroke="#000080" stroke-width=".21"/>
<path d="M88.7 77.1h-2.5v106.8" fill="none" stroke="#000080" stroke-width=".25"/>
<circle cx="86.2" cy="89.8" r=".51" fill="#000080"/>
<circle cx="86.2" cy="89.8" r=".51" fill="none" stroke="#000080" stroke-width=".21"/>
<circle cx="86.2" cy="102.5" r=".51" fill="#000080"/>
<circle cx="86.2" cy="102.5" r=".51" fill="none" stroke="#000080" stroke-width=".21"/>
<circle cx="86.2" cy="115.2" r=".51" fill="#000080"/>
<circle cx="86.2" cy="115.2" r=".51" fill="none" stroke="#000080" stroke-width=".21"/>
<circle cx="86.2" cy="127.9" r=".51" fill="#000080"/>
<circle cx="86.2" cy="127.9" r=".51" fill="none" stroke="#000080" stroke-width=".21"/>
<circle cx="86.2" cy="140.7" r=".51" fill="#000080"/>
<circle cx="86.2" cy="140.7" r=".51" fill="none" stroke="#000080" stroke-width=".21"/>
<circle cx="86.2" cy="153.4" r=".51" fill="#000080"/>
<circle cx="86.2" cy="153.4" r=".51" fill="none" stroke="#000080" stroke-width=".21"/>
<circle cx="86.2" cy="166.1" r=".51" fill="#000080"/>
<circle cx="86.2" cy="166.1" r=".51" fill="none" stroke="#000080" stroke-width=".21"/>
<circle cx="86.2" cy="183.9" r=".51" fill="#000080"/>
<circle cx="86.2" cy="183.9" r=".51" fill="none" stroke="#000080" stroke-width=".21"/>
<path d="M109.1 102.5h2.5v81.4" fill="none" stroke="#000080" stroke-width=".25"/>
<circle cx="111.6" cy="115.2" r=".51" fill="#000080"/>
<circle cx="111.6" cy="115.2" r=".51" fill="none" stroke="#000080" stroke-width=".21"/>
<circle cx="111.6" cy="127.9" r=".51" fill="#000080"/>
<circle cx="111.6" cy="127.9" r=".51" fill="none" stroke="#000080" stroke-width=".21"/>
<circle cx="111.6" cy="140.7" r=".51" fill="#000080"/>
<circle cx="111.6" cy="140.7" r=".51" fill="none" stroke="#000080" stroke-width=".21"/>
<circle cx="111.6" cy="153.4" r=".51" fill="#000080"/>
<circle cx="111.6" cy="153.4" r=".51" fill="none" stroke="#000080" stroke-width=".21"/>
<circle cx="111.6" cy="183.9" r=".51" fill="#000080"/>
<circle cx="111.6" cy="183.9" r=".51" fill="none" stroke="#000080" stroke-width=".21"/>
<path d="M116.7 56.7v5.1h-7.6" fill="none" stroke="#000080" stroke-width=".25"/>
<circle cx="116.7" cy="56.7" r=".51" fill="#000080"/>
<circle cx="116.7" cy="56.7" r=".51" fill="none" stroke="#000080" stroke-width=".21"/>
<circle cx="116.7" cy="61.8" r=".51" fill="#000080"/>
<circle cx="116.7" cy="61.8" r=".51" fill="none" stroke="#000080" stroke-width=".21"/>
<path d="M116.7 51.6v2.6h-7.6" fill="none" stroke="#000080" stroke-width=".25"/>
<circle cx="116.7" cy="54.2" r=".51" fill="#000080"/>
<circle cx="116.7" cy="54.2" r=".51" fill="none" stroke="#000080" stroke-width=".21"/>
<path d="M58.2 51.6v7.7h-7.7" fill="none" stroke="#000080" stroke-width=".25"/>
<circle cx="58.2" cy="59.3" r=".51" fill="#000080"/>
<circle cx="58.2" cy="59.3" r=".51" fill="none" stroke="#000080" stroke-width=".21"/>
<circle cx="58.2" cy="56.7" r=".51" fill="#000080"/>
<circle cx="58.2" cy="56.7" r=".51" fill="none" stroke="#000080" stroke-width=".21"/>
<circle cx="58.2" cy="54.2" r=".51" fill="#000080"/>
<circle cx="58.2" cy="54.2" r=".51" fill="none" stroke="#000080" stroke-width=".21"/>
<path d="M86.2 51.6v5.1h2.5" fill="none" stroke="#000080" stroke-width=".25"/>
<circle cx="86.2" cy="54.2" r=".51" fill="#000080"/>
<circle cx="86.2" cy="54.2" r=".51" fill="none" stroke="#000080" stroke-width=".21"/>
<circle cx="86.2" cy="56.7" r=".51" fill="#000080"/>
<circle cx="86.2" cy="56.7" r=".51" fill="none" stroke="#000080" stroke-width=".21"/>
<g fill="none" stroke="#000080" stroke-width=".25">
<path d="M55.6 21.1h2.6M68.3 21.1h2.6M83.6 21.1h10.2M243.9 21.1h15.3M243.9 38.9h15.3M243.9 36.4h15.3M243.9 33.8h15.3M243.9 31.3h15.3M243.9 28.7h15.3M243.9 26.2h15.3M243.9 23.6h15.3M73.4 97.4h15.3"/>
<path d="M73.4 100h15.3M73.4 105h15.3M73.4 107.6h15.3M73.4 110.1h15.3M73.4 112.7h15.3M73.4 117.8h15.3M73.4 120.3h15.3M73.4 122.9h15.3M73.4 125.4h15.3M73.4 130.5h15.3M73.4 133h15.3M73.4 135.6h15.3"/>
<path d="M195.5 181.4h2.6v5.1"/>
</g>
<circle cx="198.1" cy="181.4" r=".51" fill="#000080"/>
<circle cx="198.1" cy="181.4" r=".51" fill="none" stroke="#000080" stroke-width=".21"/>
<path d="M175.2 181.4h-2.5v5.1" fill="none" stroke="#000080" stroke-width=".25"/>
<circle cx="172.7" cy="181.4" r=".51" fill="#000080"/>
<circle cx="172.7" cy="181.4" r=".51" fill="none" stroke="#000080" stroke-width=".21"/>
<path d="M172.7 115.2h2.5" fill="none" stroke="#000080" stroke-width=".25"/>
<circle cx="172.7" cy="115.2" r=".51" fill="#000080"/>
<circle cx="172.7" cy="115.2" r=".51" fill="none" stroke="#000080" stroke-width=".21"/>
<path d="M172.7 122.9h2.5" fill="none" stroke="#000080" stroke-width=".25"/>
<circle cx="172.7" cy="122.9" r=".51" fill="#000080"/>
<circle cx="172.7" cy="122.9" r=".51" fill="none" stroke="#000080" stroke-width=".21"/>
<path d="M172.7 130.5h2.5" fill="none" stroke="#000080" stroke-width=".25"/>
<circle cx="172.7" cy="130.5" r=".51" fill="#000080"/>
<circle cx="172.7" cy="130.5" r=".51" fill="none" stroke="#000080" stroke-width=".21"/>
<path d="M172.7 138.1h2.5" fill="none" stroke="#000080" stroke-width=".25"/>
<circle cx="172.7" cy="138.1" r=".51" fill="#000080"/>
<circle cx="172.7" cy="138.1" r=".51" fill="none" stroke="#000080" stroke-width=".21"/>
<path d="M172.7 145.8h2.5" fill="none" stroke="#000080" stroke-width=".25"/>
<circle cx="172.7" cy="145.7" r=".51" fill="#000080"/>
<circle cx="172.7" cy="145.7" r=".51" fill="none" stroke="#000080" stroke-width=".21"/>
<path d="M172.7 158.5h2.5" fill="none" stroke="#000080" stroke-width=".25"/>
<circle cx="172.7" cy="158.5" r=".51" fill="#000080"/>
<circle cx="172.7" cy="158.5" r=".51" fill="none" stroke="#000080" stroke-width=".21"/>
<path d="M195.5 115.2h2.6" fill="none" stroke="#000080" stroke-width=".25"/>
<circle cx="198.1" cy="115.2" r=".51" fill="#000080"/>
<circle cx="198.1" cy="115.2" r=".51" fill="none" stroke="#000080" stroke-width=".21"/>
<path d="M195.5 122.9h2.6" fill="none" stroke="#000080" stroke-width=".25"/>
<circle cx="198.1" cy="122.9" r=".51" fill="#000080"/>
<circle cx="198.1" cy="122.9" r=".51" fill="none" stroke="#000080" stroke-width=".21"/>
<path d="M195.5 130.5h2.6" fill="none" stroke="#000080" stroke-width=".25"/>
<circle cx="198.1" cy="130.5" r=".51" fill="#000080"/>
<circle cx="198.1" cy="130.5" r=".51" fill="none" stroke="#000080" stroke-width=".21"/>
<path d="M195.5 138.1h2.6" fill="none" stroke="#000080" stroke-width=".25"/>
<circle cx="198.1" cy="138.1" r=".51" fill="#000080"/>
<circle cx="198.1" cy="138.1" r=".51" fill="none" stroke="#000080" stroke-width=".21"/>
<path d="M195.5 145.8h2.6" fill="none" stroke="#000080" stroke-width=".25"/>
<circle cx="198.1" cy="145.8" r=".51" fill="#000080"/>
<circle cx="198.1" cy="145.8" r=".51" fill="none" stroke="#000080" stroke-width=".21"/>
<path d="M195.5 158.5h2.6" fill="none" stroke="#000080" stroke-width=".25"/>
<circle cx="198.1" cy="158.5" r=".51" fill="#000080"/>
<circle cx="198.1" cy="158.5" r=".51" fill="none" stroke="#000080" stroke-width=".21"/>
<g fill="none" stroke="#000080" stroke-width=".25">
<path d="M210.8 21.1h-5.1v7.6M149.8 110.1h25.4M149.8 112.7h25.4M149.8 117.8h25.4M195.5 110.1h25.5M195.5 112.7h25.5M195.5 117.8h25.5M149.8 120.3h25.4M149.8 125.4h25.4M149.8 127.9h25.4M149.8 133h25.4M149.8 135.6h25.4"/>
<path d="M195.5 120.3h25.5M195.5 125.4h25.5M195.5 127.9h25.5M195.5 133h25.5M195.5 135.6h25.5M149.8 140.7h25.4M149.8 143.2h25.4"/>
</g>
<circle cx="205.7" cy="28.7" r=".51" fill="#000080"/>
<circle cx="205.7" cy="28.7" r=".51" fill="none" stroke="#000080" stroke-width=".21"/>
<path d="M210.8 23.6h-2.5v7.7" fill="none" stroke="#000080" stroke-width=".25"/>
<circle cx="208.3" cy="31.3" r=".51" fill="#000080"/>
<circle cx="208.3" cy="31.3" r=".51" fill="none" stroke="#000080" stroke-width=".21"/>
<path d="M210.8 36.4h-5.1v7.6" fill="none" stroke="#000080" stroke-width=".25"/>
<circle cx="205.7" cy="44" r=".51" fill="#000080"/>
<circle cx="205.7" cy="44" r=".51" fill="none" stroke="#000080" stroke-width=".21"/>
<path d="M210.8 38.9h-2.5v7.6" fill="none" stroke="#000080" stroke-width=".25"/>
<circle cx="208.3" cy="46.5" r=".51" fill="#000080"/>
<circle cx="208.3" cy="46.5" r=".51" fill="none" stroke="#000080" stroke-width=".21"/>
<path d="M210.8 51.6h-5.1v7.7" fill="none" stroke="#000080" stroke-width=".25"/>
<circle cx="205.7" cy="59.3" r=".51" fill="#000080"/>
<circle cx="205.7" cy="59.3" r=".51" fill="none" stroke="#000080" stroke-width=".21"/>
<path d="M210.8 54.2h-2.5v7.6" fill="none" stroke="#000080" stroke-width=".25"/>
<circle cx="208.3" cy="61.8" r=".51" fill="#000080"/>
<circle cx="208.3" cy="61.8" r=".51" fill="none" stroke="#000080" stroke-width=".21"/>
<path d="M210.8 66.9h-5.1v7.6" fill="none" stroke="#000080" stroke-width=".25"/>
<circle cx="205.7" cy="74.5" r=".51" fill="#000080"/>
<circle cx="205.7" cy="74.5" r=".51" fill="none" stroke="#000080" stroke-width=".21"/>
<path d="M210.8 69.4h-2.5v7.7" fill="none" stroke="#000080" stroke-width=".25"/>
<circle cx="208.3" cy="77.1" r=".51" fill="#000080"/>
<circle cx="208.3" cy="77.1" r=".51" fill="none" stroke="#000080" stroke-width=".21"/>
<path d="M149.8 176.3h25.4" fill="none" stroke="#000080" stroke-width=".25"/>
<circle cx="162.5" cy="176.3" r=".51" fill="#000080"/>
<circle cx="162.5" cy="176.3" r=".51" fill="none" stroke="#000080" stroke-width=".21"/>
<path d="M175.2 107.6h-2.5v73.8" fill="none" stroke="#000080" stroke-width=".25"/>
<circle cx="172.7" cy="115.2" r=".51" fill="#000080"/>
<circle cx="172.7" cy="115.2" r=".51" fill="none" stroke="#000080" stroke-width=".21"/>
<circle cx="172.7" cy="122.9" r=".51" fill="#000080"/>
<circle cx="172.7" cy="122.9" r=".51" fill="none" stroke="#000080" stroke-width=".21"/>
<circle cx="172.7" cy="130.5" r=".51" fill="#000080"/>
<circle cx="172.7" cy="130.5" r=".51" fill="none" stroke="#000080" stroke-width=".21"/>
<circle cx="172.7" cy="138.1" r=".51" fill="#000080"/>
<circle cx="172.7" cy="138.1" r=".51" fill="none" stroke="#000080" stroke-width=".21"/>
<circle cx="172.7" cy="145.7" r=".51" fill="#000080"/>
<circle cx="172.7" cy="145.7" r=".51" fill="none" stroke="#000080" stroke-width=".21"/>
<circle cx="172.7" cy="158.5" r=".51" fill="#000080"/>
<circle cx="172.7" cy="158.5" r=".51" fill="none" stroke="#000080" stroke-width=".21"/>
<circle cx="172.7" cy="181.4" r=".51" fill="#000080"/>
<circle cx="172.7" cy="181.4" r=".51" fill="none" stroke="#000080" stroke-width=".21"/>
<path d="M195.5 107.6h2.6v73.8" fill="none" stroke="#000080" stroke-width=".25"/>
<circle cx="198.1" cy="115.2" r=".51" fill="#000080"/>
<circle cx="198.1" cy="115.2" r=".51" fill="none" stroke="#000080" stroke-width=".21"/>
<circle cx="198.1" cy="122.9" r=".51" fill="#000080"/>
<circle cx="198.1" cy="122.9" r=".51" fill="none" stroke="#000080" stroke-width=".21"/>
<circle cx="198.1" cy="130.5" r=".51" fill="#000080"/>
<circle cx="198.1" cy="130.5" r=".51" fill="none" stroke="#000080" stroke-width=".21"/>
<circle cx="198.1" cy="138.1" r=".51" fill="#000080"/>
<circle cx="198.1" cy="138.1" r=".51" fill="none" stroke="#000080" stroke-width=".21"/>
<circle cx="198.1" cy="145.8" r=".51" fill="#000080"/>
<circle cx="198.1" cy="145.8" r=".51" fill="none" stroke="#000080" stroke-width=".21"/>
<circle cx="198.1" cy="158.5" r=".51" fill="#000080"/>
<circle cx="198.1" cy="158.5" r=".51" fill="none" stroke="#000080" stroke-width=".21"/>
<circle cx="198.1" cy="181.4" r=".51" fill="#000080"/>
<circle cx="198.1" cy="181.4" r=".51" fill="none" stroke="#000080" stroke-width=".21"/>
<path d="M147.2 21.1h-5.1v7.6" fill="none" stroke="#000080" stroke-width=".25"/>
<circle cx="142.1" cy="28.7" r=".51" fill="#000080"/>
<circle cx="142.1" cy="28.7" r=".51" fill="none" stroke="#000080" stroke-width=".21"/>
<path d="M149.8 23.6h-5.1v7.7" fill="none" stroke="#000080" stroke-width=".25"/>
<circle cx="144.7" cy="31.3" r=".51" fill="#000080"/>
<circle cx="144.7" cy="31.3" r=".51" fill="none" stroke="#000080" stroke-width=".21"/>
<g fill="none" stroke="#000080" stroke-width=".25">
<path d="M147.2 36.4h-5.1v7.6M221 21.1h15.3M221 23.6h15.3M221 28.7h15.3M221 31.3h15.3M221 36.4h15.3M221 38.9h15.3M221 44h15.3M221 46.5h15.3M221 51.6h15.3M221 54.2h15.3M221 59.3h15.3"/>
<path d="M221 61.8h15.3M221 66.9h15.3M221 69.4h15.3M221 74.5h15.3M221 77.1h15.3"/>
</g>
<circle cx="142.1" cy="44" r=".51" fill="#000080"/>
<circle cx="142.1" cy="44" r=".51" fill="none" stroke="#000080" stroke-width=".21"/>
<path d="M149.8 38.9h-5.1v7.6" fill="none" stroke="#000080" stroke-width=".25"/>
<circle cx="144.7" cy="46.5" r=".51" fill="#000080"/>
<circle cx="144.7" cy="46.5" r=".51" fill="none" stroke="#000080" stroke-width=".21"/>
<path d="M147.2 51.6h-5.1v7.7" fill="none" stroke="#000080" stroke-width=".25"/>
<circle cx="142.1" cy="59.3" r=".51" fill="#000080"/>
<circle cx="142.1" cy="59.3" r=".51" fill="none" stroke="#000080" stroke-width=".21"/>
<path d="M149.8 54.2h-5.1v7.6" fill="none" stroke="#000080" stroke-width=".25"/>
<circle cx="144.7" cy="61.8" r=".51" fill="#000080"/>
<circle cx="144.7" cy="61.8" r=".51" fill="none" stroke="#000080" stroke-width=".21"/>
<path d="M147.2 66.9h-5.1v7.6" fill="none" stroke="#000080" stroke-width=".25"/>
<circle cx="142.1" cy="74.5" r=".51" fill="#000080"/>
<circle cx="142.1" cy="74.5" r=".51" fill="none" stroke="#000080" stroke-width=".21"/>
<path d="M149.8 69.4h-5.1v7.7" fill="none" stroke="#000080" stroke-width=".25"/>
<circle cx="144.7" cy="77.1" r=".51" fill="#000080"/>
<circle cx="144.7" cy="77.1" r=".51" fill="none" stroke="#000080" stroke-width=".21"/>
<path d="M147.2 82.1h-5.1v7.7" fill="none" stroke="#000080" stroke-width=".25"/>
<circle cx="142.1" cy="89.8" r=".51" fill="#000080"/>
<circle cx="142.1" cy="89.8" r=".51" fill="none" stroke="#000080" stroke-width=".21"/>
<path d="M149.8 84.7h-5.1v7.6" fill="none" stroke="#000080" stroke-width=".25"/>
<circle cx="144.7" cy="92.3" r=".51" fill="#000080"/>
<circle cx="144.7" cy="92.3" r=".51" fill="none" stroke="#000080" stroke-width=".21"/>
<path d="M124.3 92.3h25.5" fill="none" stroke="#000080" stroke-width=".25"/>
<circle cx="144.7" cy="92.3" r=".51" fill="#000080"/>
<circle cx="144.7" cy="92.3" r=".51" fill="none" stroke="#000080" stroke-width=".21"/>
<path d="M124.3 89.8h22.9" fill="none" stroke="#000080" stroke-width=".25"/>
<circle cx="142.1" cy="89.8" r=".51" fill="#000080"/>
<circle cx="142.1" cy="89.8" r=".51" fill="none" stroke="#000080" stroke-width=".21"/>
<path d="M124.3 77.1h25.5" fill="none" stroke="#000080" stroke-width=".25"/>
<circle cx="144.7" cy="77.1" r=".51" fill="#000080"/>
<circle cx="144.7" cy="77.1" r=".51" fill="none" stroke="#000080" stroke-width=".21"/>
<path d="M124.3 74.5h22.9" fill="none" stroke="#000080" stroke-width=".25"/>
<circle cx="142.1" cy="74.5" r=".51" fill="#000080"/>
<circle cx="142.1" cy="74.5" r=".51" fill="none" stroke="#000080" stroke-width=".21"/>
<path d="M124.3 61.8h25.5" fill="none" stroke="#000080" stroke-width=".25"/>
<circle cx="144.7" cy="61.8" r=".51" fill="#000080"/>
<circle cx="144.7" cy="61.8" r=".51" fill="none" stroke="#000080" stroke-width=".21"/>
<path d="M124.3 59.3h22.9" fill="none" stroke="#000080" stroke-width=".25"/>
<circle cx="142.1" cy="59.3" r=".51" fill="#000080"/>
<circle cx="142.1" cy="59.3" r=".51" fill="none" stroke="#000080" stroke-width=".21"/>
<path d="M124.3 46.5h25.5" fill="none" stroke="#000080" stroke-width=".25"/>
<circle cx="144.7" cy="46.5" r=".51" fill="#000080"/>
<circle cx="144.7" cy="46.5" r=".51" fill="none" stroke="#000080" stroke-width=".21"/>
<path d="M124.3 44h22.9" fill="none" stroke="#000080" stroke-width=".25"/>
<circle cx="142.1" cy="44" r=".51" fill="#000080"/>
<circle cx="142.1" cy="44" r=".51" fill="none" stroke="#000080" stroke-width=".21"/>
<path d="M124.3 31.3h25.5" fill="none" stroke="#000080" stroke-width=".25"/>
<circle cx="144.7" cy="31.3" r=".51" fill="#000080"/>
<circle cx="144.7" cy="31.3" r=".51" fill="none" stroke="#000080" stroke-width=".21"/>
<path d="M124.3 28.7h22.9" fill="none" stroke="#000080" stroke-width=".25"/>
<circle cx="142.1" cy="28.7" r=".51" fill="#000080"/>
<circle cx="142.1" cy="28.7" r=".51" fill="none" stroke="#000080" stroke-width=".21"/>
<g fill="none" stroke="#000080" stroke-width=".25">
<path d="M157.4 36.4h25.4M157.4 28.7h25.4M157.4 21.1h25.4M159.9 38.9h22.9M159.9 31.3h22.9M159.9 23.6h22.9M157.4 59.3h25.4M157.4 51.6h25.4M157.4 44h25.4M159.9 54.2h22.9M159.9 46.5h22.9M157.4 74.5h25.4"/>
<path d="M157.4 66.9h25.4M159.9 77.1h22.9M159.9 69.4h22.9M159.9 61.8h22.9M190.5 77.1h20.3M157.4 89.8h25.4M157.4 82.1h25.4M159.9 92.3h22.9M159.9 84.7h22.9"/>
</g>
<circle cx="208.3" cy="77.1" r=".51" fill="#000080"/>
<circle cx="208.3" cy="77.1" r=".51" fill="none" stroke="#000080" stroke-width=".21"/>
<path d="M190.5 74.5h20.3" fill="none" stroke="#000080" stroke-width=".25"/>
<circle cx="205.7" cy="74.5" r=".51" fill="#000080"/>
<circle cx="205.7" cy="74.5" r=".51" fill="none" stroke="#000080" stroke-width=".21"/>
<path d="M190.5 61.8h20.3" fill="none" stroke="#000080" stroke-width=".25"/>
<circle cx="208.3" cy="61.8" r=".51" fill="#000080"/>
<circle cx="208.3" cy="61.8" r=".51" fill="none" stroke="#000080" stroke-width=".21"/>
<path d="M190.5 59.3h20.3" fill="none" stroke="#000080" stroke-width=".25"/>
<circle cx="205.7" cy="59.3" r=".51" fill="#000080"/>
<circle cx="205.7" cy="59.3" r=".51" fill="none" stroke="#000080" stroke-width=".21"/>
<path d="M190.5 46.5h20.3" fill="none" stroke="#000080" stroke-width=".25"/>
<circle cx="208.3" cy="46.5" r=".51" fill="#000080"/>
<circle cx="208.3" cy="46.5" r=".51" fill="none" stroke="#000080" stroke-width=".21"/>
<path d="M190.5 44h20.3" fill="none" stroke="#000080" stroke-width=".25"/>
<circle cx="205.7" cy="44" r=".51" fill="#000080"/>
<circle cx="205.7" cy="44" r=".51" fill="none" stroke="#000080" stroke-width=".21"/>
<path d="M190.5 31.3h20.3" fill="none" stroke="#000080" stroke-width=".25"/>
<circle cx="208.3" cy="31.3" r=".51" fill="#000080"/>
<circle cx="208.3" cy="31.3" r=".51" fill="none" stroke="#000080" stroke-width=".21"/>
<path d="M190.5 28.7h20.3" fill="none" stroke="#000080" stroke-width=".25"/>
<circle cx="205.7" cy="28.7" r=".51" fill="#000080"/>
<circle cx="205.7" cy="28.7" r=".51" fill="none" stroke="#000080" stroke-width=".21"/>
<g fill="none" stroke="#000080" stroke-width=".25">
<path d="M12.4 72h5.1v2.5M221 84.7h10.2M243.9 100h15.3M243.9 97.4h15.3M243.9 94.9h15.3M109.1 110.1h5M243.9 112.7h15.3M243.9 110.1h15.3M243.9 107.6h15.3M243.9 105.1h15.3M243.9 102.5h15.3M109.1 130.5h20.3"/>
<path d="M109.1 133h20.3M109.1 135.6h20.3M109.1 138.1h20.3M243.9 122.9h15.3M243.9 125.4h15.3M243.9 127.9h15.3M243.9 130.5h15.3M243.9 133h15.3M243.9 135.6h15.3M243.9 138.1h15.3M221 158.5h10.2M241.3 158.5h22.9"/>
<path d="M243.9 140.7h15.3M243.9 150.8h20.3M243.9 148.3h20.3M50.5 166.1h12.8"/>
</g>
<circle cx="12.4" cy="72" r=".51" fill="#000080"/>
<circle cx="12.4" cy="72" r=".51" fill="none" stroke="#000080" stroke-width=".21"/>
<path d="M12.4 84.7v5.1h17.8" fill="none" stroke="#000080" stroke-width=".25"/>
<circle cx="12.4" cy="89.8" r=".51" fill="#000080"/>
<circle cx="12.4" cy="89.8" r=".51" fill="none" stroke="#000080" stroke-width=".21"/>
<path d="M12.4 69.4v5.1M17.5 84.7v2.5h12.7" fill="none" stroke="#000080" stroke-width=".25"/>
<circle cx="12.4" cy="72" r=".51" fill="#000080"/>
<circle cx="12.4" cy="72" r=".51" fill="none" stroke="#000080" stroke-width=".21"/>
<path d="M50.5 64.3h12.8v2.6h-12.8" fill="none" stroke="#000080" stroke-width=".25"/>
<circle cx="63.3" cy="64.3" r=".51" fill="#000080"/>
<circle cx="63.3" cy="64.3" r=".51" fill="none" stroke="#000080" stroke-width=".21"/>
<path d="M63.3 64.3h7.6" fill="none" stroke="#000080" stroke-width=".25"/>
<circle cx="63.3" cy="64.3" r=".51" fill="#000080"/>
<circle cx="63.3" cy="64.3" r=".51" fill="none" stroke="#000080" stroke-width=".21"/>
<path d="M65.8 74.5h2.5M78.5 74.5h10.2M274.4 176.3h5.1M243.9 183.9h-2.6v2.6" fill="none" stroke="#000080" stroke-width=".25"/>
<circle cx="279.5" cy="176.3" r=".51" fill="#000080"/>
<circle cx="279.5" cy="176.3" r=".51" fill="none" stroke="#000080" stroke-width=".21"/>
<circle cx="277" cy="176.3" r=".51" fill="#000080"/>
<circle cx="277" cy="176.3" r=".51" fill="none" stroke="#000080" stroke-width=".21"/>
<path d="M284.6 173.7v2.6h-5.1" fill="none" stroke="#000080" stroke-width=".25"/>
<circle cx="279.5" cy="176.3" r=".51" fill="#000080"/>
<circle cx="279.5" cy="176.3" r=".51" fill="none" stroke="#000080" stroke-width=".21"/>
<path d="M208.3 173.7v2.6h10.2" fill="none" stroke="#000080" stroke-width=".25"/>
<circle cx="215.9" cy="176.3" r=".51" fill="#000080"/>
<circle cx="215.9" cy="176.3" r=".51" fill="none" stroke="#000080" stroke-width=".21"/>
<path d="M241.3 176.3v2.5h2.6" fill="none" stroke="#000080" stroke-width=".25"/>
<circle cx="241.3" cy="176.3" r=".51" fill="#000080"/>
<circle cx="241.3" cy="176.3" r=".51" fill="none" stroke="#000080" stroke-width=".21"/>
<path d="M228.6 176.3h15.3" fill="none" stroke="#000080" stroke-width=".25"/>
<circle cx="231.2" cy="176.3" r=".51" fill="#000080"/>
<circle cx="231.2" cy="176.3" r=".51" fill="none" stroke="#000080" stroke-width=".21"/>
<circle cx="233.7" cy="176.3" r=".51" fill="#000080"/>
<circle cx="233.7" cy="176.3" r=".51" fill="none" stroke="#000080" stroke-width=".21"/>
<circle cx="241.3" cy="176.3" r=".51" fill="#000080"/>
<circle cx="241.3" cy="176.3" r=".51" fill="none" stroke="#000080" stroke-width=".21"/>
<path d="M50.5 171.2h12.8" fill="none" stroke="#000080" stroke-width=".25"/>
<path d="M73.4 31.3h20.4M73.4 33.8h20.4M73.4 38.9h20.4M73.4 36.4h20.4" fill="none" stroke="#000080" stroke-width=".76"/>
<path d="M274.4 28.7h2.6M274.4 56.7h2.6M274.4 102.5h2.6M274.4 130.5h2.6" fill="none" stroke="#cbdaff" stroke-width="1.3"/>
<path d="M274.9 28.3l1 .9M274.9 56.3l1 .9M274.9 102.1l1 .8M274.9 130l1 .9" fill="none" stroke="#adbce7" stroke-width=".38"/>
<path d="M274.4 28.7h2.6M274.4 56.7h2.6M274.4 102.5h2.6M274.4 130.5h2.6" fill="none" stroke="#adbce7" stroke-width=".25"/>
<use href="#words"/>
</svg>
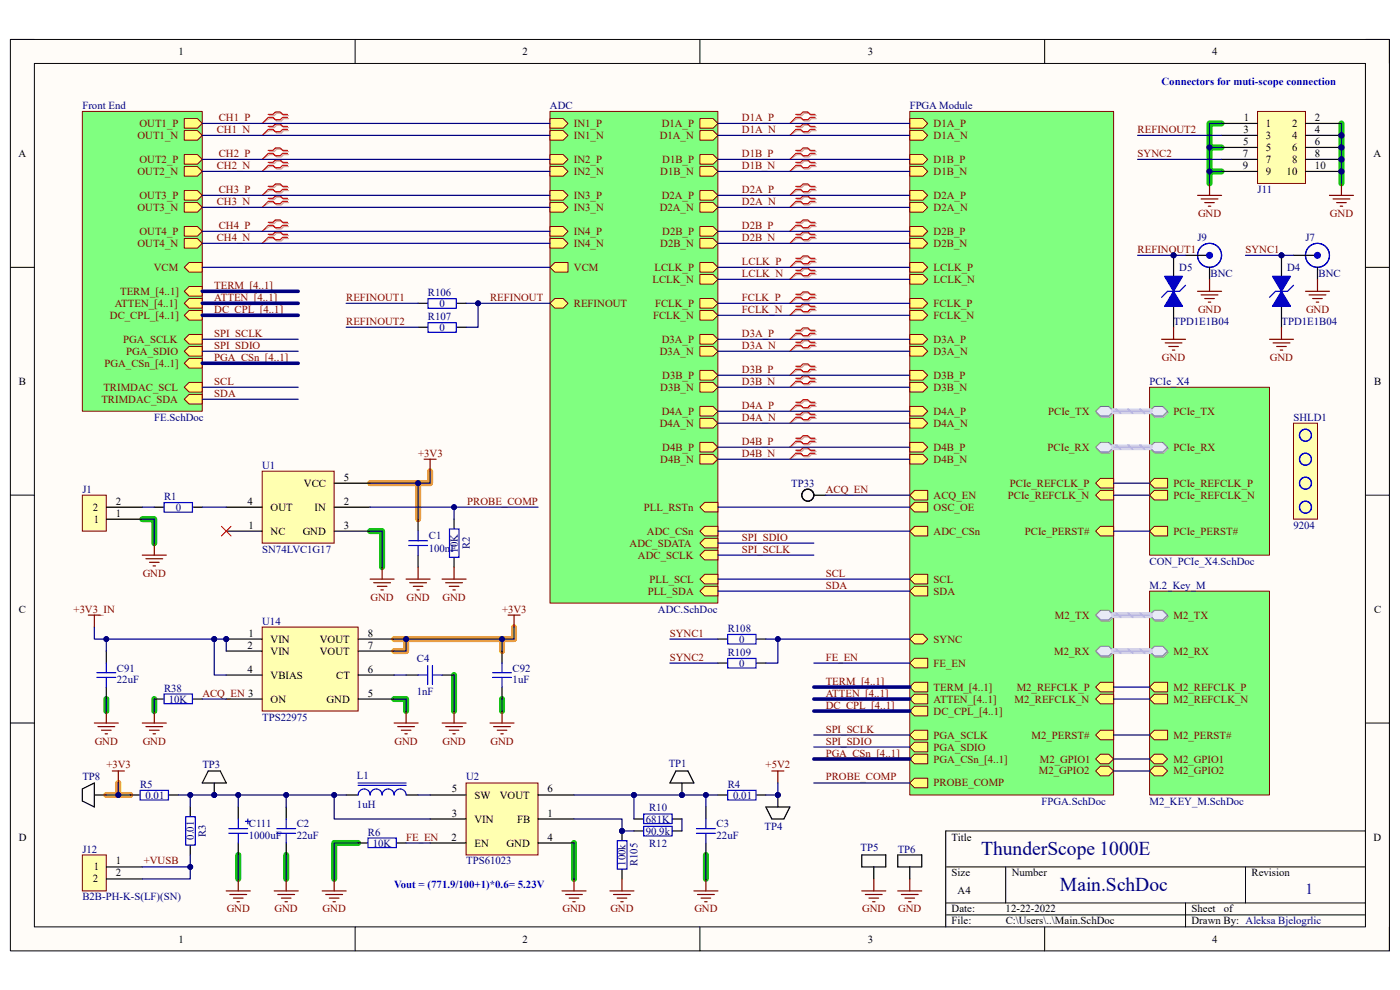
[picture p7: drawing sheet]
<svg xmlns="http://www.w3.org/2000/svg" width="297mm" height="210mm" viewBox="0 0 297 210" stroke-linecap="round" stroke-linejoin="round" font-family="sans-serif">
<defs><g id="words">
<g font-size="4.1" fill="#000080">
<text x="208.2" y="181.5">ThunderScope 1000E</text>
<text x="224.9" y="189.1">Main.SchDoc</text>
</g>
<text font-size="3.2" fill="#000080" x="276.9" y="189.6">1</text>
<g font-size="2.3">
<text x="37.9" y="11.7">1</text>
<text x="110.9" y="11.7">2</text>
<text x="184.1" y="11.7">3</text>
<text x="257.1" y="11.7">4</text>
<text x="263.8" y="28.2">3</text>
<text x="263.9" y="25.7">1</text>
<text x="268.6" y="26.9">1</text>
<text x="268.6" y="29.5">3</text>
<text x="274.1" y="26.9">2</text>
<text x="274.1" y="29.5">4</text>
<text x="279" y="25.7">2</text>
<text x="279" y="28.2">4</text>
<text x="3.9" y="33.3">A</text>
<text x="263.7" y="33.3">7</text>
<text x="263.7" y="35.9">9</text>
<text x="263.7" y="30.7">5</text>
<text x="268.6" y="32">5</text>
<text x="268.6" y="34.6">7</text>
<text x="274.1" y="32">6</text>
<text x="274.2" y="34.6">8</text>
<text x="279" y="30.7">6</text>
<text x="279" y="33.3">8</text>
<text x="279" y="35.9">10</text>
<text x="291.4" y="33.3">A</text>
<text x="268.6" y="37.1">9</text>
<text x="273" y="37.1">10</text>
<text x="4" y="81.6">B</text>
<text x="291.5" y="81.6">B</text>
<text x="72.9" y="102">5</text>
<text x="24.6" y="107.1">2</text>
<text x="52.5" y="107.1">4</text>
<text x="64.5" y="103.3">VCC</text>
<text x="72.9" y="107.1">2</text>
<text x="19.7" y="108.3">2</text>
<text x="19.9" y="110.9">1</text>
<text x="24.6" y="109.6">1</text>
<text x="52.7" y="112.1">1</text>
<text x="57.4" y="108.3">OUT</text>
<text x="57.4" y="113.4">NC</text>
<text x="64.2" y="113.4">GND</text>
<text x="66.7" y="108.3">IN</text>
<text x="72.9" y="112.1">3</text>
<text x="4" y="130">C</text>
<text x="291.5" y="130">C</text>
<text x="52.5" y="137.6">2</text>
<text x="52.7" y="135">1</text>
<text x="57.4" y="136.3">VIN</text>
<text x="67.9" y="136.3">VOUT</text>
<text x="78" y="135">8</text>
<text x="78" y="137.6">7</text>
<text x="52.5" y="142.7">4</text>
<text x="57.4" y="138.9">VIN</text>
<text x="57.4" y="144">VBIAS</text>
<text x="67.9" y="138.9">VOUT</text>
<text x="71.3" y="144">CT</text>
<text x="78" y="142.7">6</text>
<text x="57.4" y="149.1">ON</text>
<text x="69.3" y="149.1">GND</text>
<text x="78" y="147.8">5</text>
<text x="95.8" y="168.1">5</text>
<text x="95.9" y="173.2">3</text>
<text x="100.7" y="169.4">SW</text>
<text x="106" y="169.4">VOUT</text>
<text x="116.2" y="168.1">6</text>
<text x="116.2" y="173.2">1</text>
<text x="4" y="178.3">D</text>
<text x="95.8" y="178.3">2</text>
<text x="100.7" y="174.5">VIN</text>
<text x="100.7" y="179.6">EN</text>
<text x="107.5" y="179.6">GND</text>
<text x="109.7" y="174.5">FB</text>
<text x="116.2" y="178.3">4</text>
<text x="201.9" y="178.3">Title</text>
<text x="291.4" y="178.3">D</text>
<text x="19.9" y="184.7">1</text>
<text x="24.6" y="183.4">1</text>
<text x="24.6" y="185.9">2</text>
<text x="201.9" y="185.9">Size</text>
<text x="214.6" y="185.9">Number</text>
<text x="265.5" y="185.9">Revision</text>
<text x="19.7" y="187.2">2</text>
<text x="203.2" y="189.7">A4</text>
<text x="201.9" y="193.5">Date:</text>
<text x="201.9" y="196.1">File:</text>
<text x="213.3" y="193.5">12-22-2022</text>
<text x="213.4" y="196.1">C:\Users\..\Main.SchDoc</text>
<text x="252.8" y="193.5">Sheet</text>
<text x="252.8" y="196.1">Drawn By: Aleksa Bjelogrlic</text>
<text x="259.6" y="193.5">of</text>
<text x="37.9" y="199.9">1</text>
<text x="110.9" y="199.9">2</text>
<text x="184.1" y="199.9">3</text>
<text x="257.1" y="199.9">4</text>
</g>
<g font-size="2.3" fill="#000080">
<text x="17.5" y="23.1">Front End</text>
<text x="116.7" y="23.1">ADC</text>
<text x="193" y="23.1">FPGA Module</text>
<text x="266.8" y="40.9">J11</text>
<text x="254" y="51.1">J9</text>
<text x="276.9" y="51.1">J7</text>
<text x="250.2" y="57.4">D5</text>
<text x="256.8" y="58.7">BNC</text>
<text x="273" y="57.4">D4</text>
<text x="279.7" y="58.7">BNC</text>
<text x="90.8" y="62.9">R106</text>
<text x="93.3" y="65.1">0</text>
<text x="90.8" y="67.9">R107</text>
<text x="93.3" y="70.2">0</text>
<text x="249" y="68.9">TPD1E1B04</text>
<text x="271.9" y="68.9">TPD1E1B04</text>
<text x="243.9" y="81.6">PCIe_X4</text>
<text x="32.7" y="89.3">FE.SchDoc</text>
<text x="274.4" y="89.3">SHLD1</text>
<text x="55.6" y="99.4">U1</text>
<text x="17.5" y="104.5">J1</text>
<text x="34.8" y="106.1">R1</text>
<text x="167.9" y="103.3">TP33</text>
<text x="37.3" y="108.3">0</text>
<text x="274.4" y="112.1">9204</text>
<text x="55.6" y="117.3">SN74LVC1G17</text>
<text x="91" y="114.4">C1</text>
<text x="91" y="117">100nF</text>
<text x="97.1" y="117.2" transform="rotate(-90 97.1 117.2)">10K</text>
<text x="99.7" y="116.5" transform="rotate(-90 99.7 116.5)">R2</text>
<text x="243.9" y="119.8">CON_PCIe_X4.SchDoc</text>
<text x="243.9" y="124.9">M.2_Key_M</text>
<text x="139.6" y="130">ADC.SchDoc</text>
<text x="55.6" y="132.5">U14</text>
<text x="154.4" y="134.1">R108</text>
<text x="156.8" y="136.3">0</text>
<text x="24.8" y="142.5">C91</text>
<text x="88.4" y="140.4">C4</text>
<text x="108.8" y="142.5">C92</text>
<text x="154.4" y="139.1">R109</text>
<text x="156.8" y="141.4">0</text>
<text x="24.8" y="145">22uF</text>
<text x="34.8" y="146.7">R38</text>
<text x="35.8" y="149.1">10K</text>
<text x="88.4" y="147.5">1nF</text>
<text x="108.8" y="145">1uF</text>
<text x="55.6" y="152.9">TPS22975</text>
<text x="17.5" y="165.6">TP8</text>
<text x="29.7" y="167.1">R5</text>
<text x="42.9" y="163">TP3</text>
<text x="75.7" y="165.3">L1</text>
<text x="98.9" y="165.6">U2</text>
<text x="141.9" y="162.8">TP1</text>
<text x="154.4" y="167.1">R4</text>
<text x="30.9" y="169.4">0.01</text>
<text x="75.7" y="171.4">1uH</text>
<text x="137.7" y="172">R10</text>
<text x="155.5" y="169.4">0.01</text>
<text x="221" y="170.7">FPGA.SchDoc</text>
<text x="243.9" y="170.7">M2_KEY_M.SchDoc</text>
<text x="41.1" y="178.1" transform="rotate(-90 41.1 178.1)">0.01</text>
<text x="43.7" y="177.5" transform="rotate(-90 43.7 177.5)">R3</text>
<text x="52.8" y="175.5">C111</text>
<text x="52.8" y="178.1">1000uF</text>
<text x="62.9" y="175.5">C2</text>
<text x="62.9" y="178.1">22uF</text>
<text x="78.1" y="177.2">R6</text>
<text x="79.1" y="179.6">10K</text>
<text x="137" y="177">90.9k</text>
<text x="137" y="174.5">681K</text>
<text x="137.7" y="179.6">R12</text>
<text x="152" y="175.5">C3</text>
<text x="152" y="178.1">22uF</text>
<text x="162.2" y="176">TP4</text>
<text x="17.5" y="180.8">J12</text>
<text x="98.9" y="183.4">TPS61023</text>
<text x="132.7" y="183.7" transform="rotate(-90 132.7 183.7)">100k</text>
<text x="135.3" y="183.8" transform="rotate(-90 135.3 183.8)">R105</text>
<text x="182.6" y="180.6">TP5</text>
<text x="190.5" y="180.8">TP6</text>
<text x="17.5" y="191">B2B-PH-K-S(LF)(SN)</text>
</g>
<g font-size="2.3" fill="#00f">
<text x="246.4" y="18">Connectors for muti-scope connection</text>
<text x="83.6" y="188.5">Vout = (771.9/100+1)*0.6= 5.23V</text>
</g>
<g font-size="2.3" fill="#800000">
<text x="29.2" y="29.5">OUT1_N</text>
<text x="29.6" y="26.9">OUT1_P</text>
<text x="46" y="28.2">CH1_N</text>
<text x="46.4" y="25.7">CH1_P</text>
<text x="121.8" y="29.5">IN1_N</text>
<text x="121.8" y="26.9">IN1_P</text>
<text x="140" y="29.5">D1A_N</text>
<text x="140.4" y="26.9">D1A_P</text>
<text x="157.4" y="25.7">D1A_P</text>
<text x="157.4" y="28.2">D1A_N</text>
<text x="198.1" y="26.9">D1A_P</text>
<text x="198.1" y="29.5">D1A_N</text>
<text x="241.3" y="28.2">REFINOUT2</text>
<text x="29.6" y="34.6">OUT2_P</text>
<text x="46" y="35.9">CH2_N</text>
<text x="46.4" y="33.3">CH2_P</text>
<text x="121.8" y="34.6">IN2_P</text>
<text x="140.5" y="34.6">D1B_P</text>
<text x="157.4" y="33.3">D1B_P</text>
<text x="157.4" y="35.9">D1B_N</text>
<text x="198.1" y="34.6">D1B_P</text>
<text x="241.3" y="33.3">SYNC2</text>
<text x="29.2" y="37.1">OUT2_N</text>
<text x="46.4" y="40.9">CH3_P</text>
<text x="121.8" y="37.1">IN2_N</text>
<text x="140.1" y="37.1">D1B_N</text>
<text x="157.4" y="40.9">D2A_P</text>
<text x="198.1" y="37.1">D1B_N</text>
<text x="29.2" y="44.7">OUT3_N</text>
<text x="29.6" y="42.2">OUT3_P</text>
<text x="46" y="43.5">CH3_N</text>
<text x="121.8" y="44.7">IN3_N</text>
<text x="121.8" y="42.2">IN3_P</text>
<text x="140" y="44.7">D2A_N</text>
<text x="140.4" y="42.2">D2A_P</text>
<text x="157.4" y="43.5">D2A_N</text>
<text x="198.1" y="42.2">D2A_P</text>
<text x="198.1" y="44.7">D2A_N</text>
<text x="254.2" y="46">GND</text>
<text x="282.2" y="46">GND</text>
<text x="29.2" y="52.4">OUT4_N</text>
<text x="29.6" y="49.8">OUT4_P</text>
<text x="46" y="51.1">CH4_N</text>
<text x="46.4" y="48.6">CH4_P</text>
<text x="121.8" y="52.4">IN4_N</text>
<text x="121.8" y="49.8">IN4_P</text>
<text x="140.1" y="52.4">D2B_N</text>
<text x="140.5" y="49.8">D2B_P</text>
<text x="157.4" y="48.6">D2B_P</text>
<text x="157.4" y="51.1">D2B_N</text>
<text x="198.1" y="49.8">D2B_P</text>
<text x="198.1" y="52.4">D2B_N</text>
<text x="241.3" y="53.6">REFINOUT1</text>
<text x="264.2" y="53.6">SYNC1</text>
<text x="32.6" y="57.4">VCM</text>
<text x="121.8" y="57.4">VCM</text>
<text x="138.4" y="60">LCLK_N</text>
<text x="138.9" y="57.4">LCLK_P</text>
<text x="157.4" y="56.2">LCLK_P</text>
<text x="157.4" y="58.7">LCLK_N</text>
<text x="198.1" y="57.4">LCLK_P</text>
<text x="198.1" y="60">LCLK_N</text>
<text x="24.3" y="65.1">ATTEN_[4..1]</text>
<text x="25.5" y="62.6">TERM_[4..1]</text>
<text x="45.5" y="63.8">ATTEN_[4..1]</text>
<text x="45.5" y="61.3">TERM_[4..1]</text>
<text x="73.4" y="63.8">REFINOUT1</text>
<text x="104" y="63.8">REFINOUT</text>
<text x="121.8" y="65.1">REFINOUT</text>
<text x="139" y="65.1">FCLK_P</text>
<text x="157.4" y="63.8">FCLK_P</text>
<text x="198.1" y="65.1">FCLK_P</text>
<text x="23.3" y="67.6">DC_CPL_[4..1]</text>
<text x="45.5" y="66.4">DC_CPL_[4..1]</text>
<text x="45.5" y="71.5">SPI_SCLK</text>
<text x="73.4" y="68.9">REFINOUT2</text>
<text x="138.6" y="67.6">FCLK_N</text>
<text x="157.4" y="71.5">D3A_P</text>
<text x="157.4" y="66.4">FCLK_N</text>
<text x="198.1" y="67.6">FCLK_N</text>
<text x="254.2" y="66.4">GND</text>
<text x="277.1" y="66.4">GND</text>
<text x="22.2" y="77.8">PGA_CSn_[4..1]</text>
<text x="26.2" y="72.7">PGA_SCLK</text>
<text x="26.8" y="75.3">PGA_SDIO</text>
<text x="45.5" y="74">SPI_SDIO</text>
<text x="45.5" y="76.5">PGA_CSn_[4..1]</text>
<text x="140" y="75.3">D3A_N</text>
<text x="140.4" y="72.7">D3A_P</text>
<text x="157.4" y="74">D3A_N</text>
<text x="198.1" y="72.7">D3A_P</text>
<text x="198.1" y="75.3">D3A_N</text>
<text x="246.5" y="76.5">GND</text>
<text x="269.4" y="76.5">GND</text>
<text x="21.9" y="82.9">TRIMDAC_SCL</text>
<text x="45.5" y="81.6">SCL</text>
<text x="140.1" y="82.9">D3B_N</text>
<text x="140.5" y="80.3">D3B_P</text>
<text x="157.4" y="79.1">D3B_P</text>
<text x="157.4" y="81.6">D3B_N</text>
<text x="198.1" y="80.3">D3B_P</text>
<text x="198.1" y="82.9">D3B_N</text>
<text x="21.5" y="85.4">TRIMDAC_SDA</text>
<text x="45.5" y="84.2">SDA</text>
<text x="140.4" y="88">D4A_P</text>
<text x="157.4" y="86.7">D4A_P</text>
<text x="157.4" y="89.3">D4A_N</text>
<text x="198.1" y="88">D4A_P</text>
<text x="222.4" y="88">PCIe_TX</text>
<text x="249" y="88">PCIe_TX</text>
<text x="140" y="90.6">D4A_N</text>
<text x="140.5" y="95.6">D4B_P</text>
<text x="157.4" y="94.4">D4B_P</text>
<text x="198.1" y="90.6">D4A_N</text>
<text x="198.1" y="95.6">D4B_P</text>
<text x="222.2" y="95.6">PCIe_RX</text>
<text x="249" y="95.6">PCIe_RX</text>
<text x="88.7" y="96.9">+3V3</text>
<text x="140.1" y="98.2">D4B_N</text>
<text x="157.4" y="96.9">D4B_N</text>
<text x="198.1" y="98.2">D4B_N</text>
<text x="99.1" y="107.1">PROBE_COMP</text>
<text x="175.2" y="104.5">ACQ_EN</text>
<text x="198.1" y="105.8">ACQ_EN</text>
<text x="213.8" y="105.8">PCIe_REFCLK_N</text>
<text x="214.2" y="103.3">PCIe_REFCLK_P</text>
<text x="249" y="105.8">PCIe_REFCLK_N</text>
<text x="249" y="103.3">PCIe_REFCLK_P</text>
<text x="136.6" y="108.3">PLL_RSTn</text>
<text x="137.2" y="113.4">ADC_CSn</text>
<text x="198.1" y="108.3">OSC_OE</text>
<text x="198.1" y="113.4">ADC_CSn</text>
<text x="217.4" y="113.4">PCIe_PERST#</text>
<text x="249" y="113.4">PCIe_PERST#</text>
<text x="133.6" y="116">ADC_SDATA</text>
<text x="135.3" y="118.5">ADC_SCLK</text>
<text x="157.4" y="117.3">SPI_SCLK</text>
<text x="157.4" y="114.7">SPI_SDIO</text>
<text x="30.3" y="122.3">GND</text>
<text x="137.8" y="123.6">PLL_SCL</text>
<text x="175.2" y="122.3">SCL</text>
<text x="175.2" y="124.9">SDA</text>
<text x="198.1" y="123.6">SCL</text>
<text x="15.6" y="130">+3V3_IN</text>
<text x="78.6" y="127.4">GND</text>
<text x="86.2" y="127.4">GND</text>
<text x="93.9" y="127.4">GND</text>
<text x="106.5" y="130">+3V3</text>
<text x="137.4" y="126.2">PLL_SDA</text>
<text x="198.1" y="126.2">SDA</text>
<text x="223.8" y="131.2">M2_TX</text>
<text x="249" y="131.2">M2_TX</text>
<text x="142.1" y="135">SYNC1</text>
<text x="198.1" y="136.3">SYNC</text>
<text x="142.1" y="140.1">SYNC2</text>
<text x="175.2" y="140.1">FE_EN</text>
<text x="198.1" y="141.4">FE_EN</text>
<text x="223.6" y="138.9">M2_RX</text>
<text x="249" y="138.9">M2_RX</text>
<text x="42.9" y="147.8">ACQ_EN 3</text>
<text x="175.2" y="147.8">ATTEN_[4..1]</text>
<text x="175.2" y="145.2">TERM_[4..1]</text>
<text x="198.1" y="149.1">ATTEN_[4..1]</text>
<text x="198.1" y="146.5">TERM_[4..1]</text>
<text x="215.2" y="149.1">M2_REFCLK_N</text>
<text x="215.7" y="146.5">M2_REFCLK_P</text>
<text x="249" y="149.1">M2_REFCLK_N</text>
<text x="249" y="146.5">M2_REFCLK_P</text>
<text x="175.2" y="150.3">DC_CPL_[4..1]</text>
<text x="175.2" y="155.4">SPI_SCLK</text>
<text x="198.1" y="151.6">DC_CPL_[4..1]</text>
<text x="20.1" y="157.9">GND</text>
<text x="30.3" y="157.9">GND</text>
<text x="83.7" y="157.9">GND</text>
<text x="93.9" y="157.9">GND</text>
<text x="104.1" y="157.9">GND</text>
<text x="175.2" y="157.9">SPI_SDIO</text>
<text x="175.2" y="160.5">PGA_CSn_[4..1]</text>
<text x="198.1" y="156.7">PGA_SCLK</text>
<text x="198.1" y="159.2">PGA_SDIO</text>
<text x="198.1" y="161.8">PGA_CSn_[4..1]</text>
<text x="218.8" y="156.7">M2_PERST#</text>
<text x="220.6" y="161.8">M2_GPIO1</text>
<text x="249" y="156.7">M2_PERST#</text>
<text x="249" y="161.8">M2_GPIO1</text>
<text x="22.6" y="163">+3V3</text>
<text x="162.4" y="163">+5V2</text>
<text x="175.2" y="165.6">PROBE_COMP</text>
<text x="198.1" y="166.8">PROBE_COMP</text>
<text x="220.4" y="164.3">M2_GPIO2</text>
<text x="249" y="164.3">M2_GPIO2</text>
<text x="86.1" y="178.3">FE_EN</text>
<text x="30.5" y="183.4">+VUSB</text>
<text x="48.1" y="193.5">GND</text>
<text x="58.3" y="193.5">GND</text>
<text x="68.5" y="193.5">GND</text>
<text x="119.3" y="193.5">GND</text>
<text x="129.5" y="193.5">GND</text>
<text x="147.3" y="193.5">GND</text>
<text x="182.9" y="193.5">GND</text>
<text x="190.5" y="193.5">GND</text>
</g>
</g></defs>
<path d="M2.2 8.4h292.6v193.3h-292.6z" fill-rule="evenodd" fill="#fffcf8"/>
<path d="M2.2 8.4h292.6v193.3h-292.6z" fill="none" stroke="#000" stroke-width=".21"/>
<path d="M7.3 13.5h282.4v183.1h-282.4z" fill-rule="evenodd" fill="#fffcf8"/>
<g fill="none" stroke="#000" stroke-width=".21">
<path d="M2.2 8.4h5.1M7.3 13.5h282.4v183.1h-282.4zM75.3 8.4v5.1M148.5 8.4v5.1M221.6 8.4v5.1M289.7 8.4h5.1v5.1M2.2 56.7h5.1M289.7 56.7h5.1M2.2 105h5.1M289.7 105.1h5.1M2.2 153.4h5.1M289.7 153.4h5.1"/>
<path d="M289.7 176.3h-89.1v20.3M75.3 196.6v5.1M148.5 196.6v5.1M200.6 183.9h89.1M200.6 191.5h89.1M200.6 194.1h89.1M213.4 183.9v7.6M221.6 196.6v5.1M251.5 191.5v5.1M264.2 183.9v7.6M294.8 196.6v5.1"/>
</g>
<g fill="none" stroke="#00be00" stroke-width="1.3">
<path d="M259.2 36.4h-2.6v2.5M259.2 31.3h-2.6v5.1M259.2 26.2h-2.6v5.1M284.6 26.2v12.7M30.2 110.1h2.5v5.1M78.5 112.7h2.6v7.6M22.6 148.3v2.5M32.7 148.3v2.5M83.6 148.3h2.6v2.5M96.3 143.2v7.6M106.5 148.3v2.5M76 178.8h-5.1v7.7"/>
<path d="M121.8 178.8v7.7M50.5 181.4v5.1M60.7 181.4v5.1M149.8 181.4v5.1"/>
</g>
<path d="M91.2 100v2.5h-12.7M88.7 102.5v7.6M83.6 135.6h2.6M106.5 135.6v2.5M109.1 133v2.6h-22.9v2.5h-2.6M22.6 168.6h5M25.1 166.1v2.5" fill="none" stroke="#f90" stroke-width="1.3"/>
<path d="M17.5 23.6h25.4v63.6h-25.4z" fill-rule="evenodd" fill="#80ff80"/>
<path d="M17.5 23.6h25.4v63.6h-25.4z" fill="none" stroke="#800000" stroke-width=".21"/>
<path d="M39.1 25.2h2.8l1 1-1 1h-2.8z" fill-rule="evenodd" fill="#ffff80"/>
<path d="M39.1 25.2h2.8l1 1-1 1h-2.8z" fill="none" stroke="#800000" stroke-width=".21"/>
<path d="M39.1 27.7h2.8l1 1-1 1h-2.8z" fill-rule="evenodd" fill="#ffff80"/>
<path d="M39.1 27.7h2.8l1 1-1 1h-2.8z" fill="none" stroke="#800000" stroke-width=".21"/>
<path d="M39.1 40.4h2.8l1 1-1 1.1h-2.8z" fill-rule="evenodd" fill="#ffff80"/>
<path d="M39.1 40.4h2.8l1 1-1 1.1h-2.8z" fill="none" stroke="#800000" stroke-width=".21"/>
<path d="M39.1 43h2.8l1 1-1 1h-2.8z" fill-rule="evenodd" fill="#ffff80"/>
<path d="M39.1 43h2.8l1 1-1 1h-2.8z" fill="none" stroke="#800000" stroke-width=".21"/>
<path d="M39.1 50.6h2.8l1 1-1 1h-2.8z" fill-rule="evenodd" fill="#ffff80"/>
<path d="M39.1 50.6h2.8l1 1-1 1h-2.8z" fill="none" stroke="#800000" stroke-width=".21"/>
<path d="M39.1 35.3h2.8l1 1.1-1 1h-2.8z" fill-rule="evenodd" fill="#ffff80"/>
<path d="M39.1 35.3h2.8l1 1.1-1 1h-2.8z" fill="none" stroke="#800000" stroke-width=".21"/>
<path d="M39.1 32.8h2.8l1 1-1 1h-2.8z" fill-rule="evenodd" fill="#ffff80"/>
<path d="M39.1 32.8h2.8l1 1-1 1h-2.8z" fill="none" stroke="#800000" stroke-width=".21"/>
<path d="M39.1 48.1h2.8l1 1-1 1h-2.8z" fill-rule="evenodd" fill="#ffff80"/>
<path d="M39.1 48.1h2.8l1 1-1 1h-2.8z" fill="none" stroke="#800000" stroke-width=".21"/>
<path d="M40.1 55.7h2.8v2h-2.8l-1-1z" fill-rule="evenodd" fill="#ffff80"/>
<path d="M40.1 55.7h2.8v2h-2.8l-1-1z" fill="none" stroke="#800000" stroke-width=".21"/>
<path d="M39.1 66.9l1-1h2.8v2h-2.8z" fill-rule="evenodd" fill="#ffff80"/>
<path d="M39.1 66.9l1-1h2.8v2h-2.8z" fill="none" stroke="#800000" stroke-width=".21"/>
<path d="M39.1 64.3l1-1h2.8v2.1h-2.8z" fill-rule="evenodd" fill="#ffff80"/>
<path d="M39.1 64.3l1-1h2.8v2.1h-2.8z" fill="none" stroke="#800000" stroke-width=".21"/>
<path d="M39.1 72l1-1h2.8v2h-2.8z" fill-rule="evenodd" fill="#ffff80"/>
<path d="M39.1 72l1-1h2.8v2h-2.8z" fill="none" stroke="#800000" stroke-width=".21"/>
<path d="M40.1 76h2.8v2.1h-2.8l-1-1z" fill-rule="evenodd" fill="#ffff80"/>
<path d="M40.1 76h2.8v2.1h-2.8l-1-1z" fill="none" stroke="#800000" stroke-width=".21"/>
<path d="M39.1 74.5l1-1h2.8v2h-2.8z" fill-rule="evenodd" fill="#ffff80"/>
<path d="M39.1 74.5l1-1h2.8v2h-2.8z" fill="none" stroke="#800000" stroke-width=".21"/>
<path d="M40.1 81.1h2.8v2.1h-2.8l-1-1.1z" fill-rule="evenodd" fill="#ffff80"/>
<path d="M40.1 81.1h2.8v2.1h-2.8l-1-1.1z" fill="none" stroke="#800000" stroke-width=".21"/>
<path d="M39.1 84.7l1-1h2.8v2h-2.8z" fill-rule="evenodd" fill="#ffff80"/>
<path d="M39.1 84.7l1-1h2.8v2h-2.8z" fill="none" stroke="#800000" stroke-width=".21"/>
<path d="M39.1 61.8l1-1h2.8v2h-2.8z" fill-rule="evenodd" fill="#ffff80"/>
<path d="M39.1 61.8l1-1h2.8v2h-2.8z" fill="none" stroke="#800000" stroke-width=".21"/>
<path d="M116.7 23.6h35.6v104.3h-35.6z" fill-rule="evenodd" fill="#80ff80"/>
<path d="M116.7 23.6h35.6v104.3h-35.6z" fill="none" stroke="#800000" stroke-width=".21"/>
<path d="M116.7 50.6h2.8l1 1-1 1h-2.8z" fill-rule="evenodd" fill="#ffff80"/>
<path d="M116.7 50.6h2.8l1 1-1 1h-2.8z" fill="none" stroke="#800000" stroke-width=".21"/>
<path d="M116.7 48.1h2.8l1 1-1 1h-2.8z" fill-rule="evenodd" fill="#ffff80"/>
<path d="M116.7 48.1h2.8l1 1-1 1h-2.8z" fill="none" stroke="#800000" stroke-width=".21"/>
<path d="M116.7 43h2.8l1 1-1 1h-2.8z" fill-rule="evenodd" fill="#ffff80"/>
<path d="M116.7 43h2.8l1 1-1 1h-2.8z" fill="none" stroke="#800000" stroke-width=".21"/>
<path d="M116.7 40.4h2.8l1 1-1 1.1h-2.8z" fill-rule="evenodd" fill="#ffff80"/>
<path d="M116.7 40.4h2.8l1 1-1 1.1h-2.8z" fill="none" stroke="#800000" stroke-width=".21"/>
<path d="M116.7 35.3h2.8l1 1.1-1 1h-2.8z" fill-rule="evenodd" fill="#ffff80"/>
<path d="M116.7 35.3h2.8l1 1.1-1 1h-2.8z" fill="none" stroke="#800000" stroke-width=".21"/>
<path d="M116.7 32.8h2.8l1 1-1 1h-2.8z" fill-rule="evenodd" fill="#ffff80"/>
<path d="M116.7 32.8h2.8l1 1-1 1h-2.8z" fill="none" stroke="#800000" stroke-width=".21"/>
<path d="M117.7 55.7h2.8v2h-2.8l-1-1z" fill-rule="evenodd" fill="#ffff80"/>
<path d="M117.7 55.7h2.8v2h-2.8l-1-1z" fill="none" stroke="#800000" stroke-width=".21"/>
<path d="M116.7 27.7h2.8l1 1-1 1h-2.8z" fill-rule="evenodd" fill="#ffff80"/>
<path d="M116.7 27.7h2.8l1 1-1 1h-2.8z" fill="none" stroke="#800000" stroke-width=".21"/>
<path d="M116.7 25.2h2.8l1 1-1 1h-2.8z" fill-rule="evenodd" fill="#ffff80"/>
<path d="M116.7 25.2h2.8l1 1-1 1h-2.8z" fill="none" stroke="#800000" stroke-width=".21"/>
<path d="M149.5 111.7h2.8v2h-2.8l-1-1z" fill-rule="evenodd" fill="#ffff80"/>
<path d="M149.5 111.7h2.8v2h-2.8l-1-1z" fill="none" stroke="#800000" stroke-width=".21"/>
<path d="M149.5 114.2h2.8v2h-2.8l-1-1z" fill-rule="evenodd" fill="#ffff80"/>
<path d="M149.5 114.2h2.8v2h-2.8l-1-1z" fill="none" stroke="#800000" stroke-width=".21"/>
<path d="M149.5 116.7h2.8v2.1h-2.8l-1-1z" fill-rule="evenodd" fill="#ffff80"/>
<path d="M149.5 116.7h2.8v2.1h-2.8l-1-1z" fill="none" stroke="#800000" stroke-width=".21"/>
<path d="M148.5 27.7h2.8l1 1-1 1h-2.8z" fill-rule="evenodd" fill="#ffff80"/>
<path d="M148.5 27.7h2.8l1 1-1 1h-2.8z" fill="none" stroke="#800000" stroke-width=".21"/>
<path d="M148.5 25.2h2.8l1 1-1 1h-2.8z" fill-rule="evenodd" fill="#ffff80"/>
<path d="M148.5 25.2h2.8l1 1-1 1h-2.8z" fill="none" stroke="#800000" stroke-width=".21"/>
<path d="M148.5 32.8h2.8l1 1-1 1h-2.8z" fill-rule="evenodd" fill="#ffff80"/>
<path d="M148.5 32.8h2.8l1 1-1 1h-2.8z" fill="none" stroke="#800000" stroke-width=".21"/>
<path d="M148.5 35.3h2.8l1 1.1-1 1h-2.8z" fill-rule="evenodd" fill="#ffff80"/>
<path d="M148.5 35.3h2.8l1 1.1-1 1h-2.8z" fill="none" stroke="#800000" stroke-width=".21"/>
<path d="M148.5 40.4h2.8l1 1-1 1.1h-2.8z" fill-rule="evenodd" fill="#ffff80"/>
<path d="M148.5 40.4h2.8l1 1-1 1.1h-2.8z" fill="none" stroke="#800000" stroke-width=".21"/>
<path d="M148.5 43h2.8l1 1-1 1h-2.8z" fill-rule="evenodd" fill="#ffff80"/>
<path d="M148.5 43h2.8l1 1-1 1h-2.8z" fill="none" stroke="#800000" stroke-width=".21"/>
<path d="M148.5 50.6h2.8l1 1-1 1h-2.8z" fill-rule="evenodd" fill="#ffff80"/>
<path d="M148.5 50.6h2.8l1 1-1 1h-2.8z" fill="none" stroke="#800000" stroke-width=".21"/>
<path d="M148.5 48.1h2.8l1 1-1 1h-2.8z" fill-rule="evenodd" fill="#ffff80"/>
<path d="M148.5 48.1h2.8l1 1-1 1h-2.8z" fill="none" stroke="#800000" stroke-width=".21"/>
<path d="M148.5 55.7h2.8l1 1-1 1h-2.8z" fill-rule="evenodd" fill="#ffff80"/>
<path d="M148.5 55.7h2.8l1 1-1 1h-2.8z" fill="none" stroke="#800000" stroke-width=".21"/>
<path d="M148.5 58.2h2.8l1 1.1-1 1h-2.8z" fill-rule="evenodd" fill="#ffff80"/>
<path d="M148.5 58.2h2.8l1 1.1-1 1h-2.8z" fill="none" stroke="#800000" stroke-width=".21"/>
<path d="M148.5 65.9h2.8l1 1-1 1h-2.8z" fill-rule="evenodd" fill="#ffff80"/>
<path d="M148.5 65.9h2.8l1 1-1 1h-2.8z" fill="none" stroke="#800000" stroke-width=".21"/>
<path d="M148.5 63.3h2.8l1 1-1 1.1h-2.8z" fill-rule="evenodd" fill="#ffff80"/>
<path d="M148.5 63.3h2.8l1 1-1 1.1h-2.8z" fill="none" stroke="#800000" stroke-width=".21"/>
<path d="M148.5 71h2.8l1 1-1 1h-2.8z" fill-rule="evenodd" fill="#ffff80"/>
<path d="M148.5 71h2.8l1 1-1 1h-2.8z" fill="none" stroke="#800000" stroke-width=".21"/>
<path d="M148.5 73.5h2.8l1 1-1 1h-2.8z" fill-rule="evenodd" fill="#ffff80"/>
<path d="M148.5 73.5h2.8l1 1-1 1h-2.8z" fill="none" stroke="#800000" stroke-width=".21"/>
<path d="M148.5 78.6h2.8l1 1-1 1h-2.8z" fill-rule="evenodd" fill="#ffff80"/>
<path d="M148.5 78.6h2.8l1 1-1 1h-2.8z" fill="none" stroke="#800000" stroke-width=".21"/>
<path d="M148.5 81.1h2.8l1 1-1 1.1h-2.8z" fill-rule="evenodd" fill="#ffff80"/>
<path d="M148.5 81.1h2.8l1 1-1 1.1h-2.8z" fill="none" stroke="#800000" stroke-width=".21"/>
<path d="M148.5 86.2h2.8l1 1-1 1.1h-2.8z" fill-rule="evenodd" fill="#ffff80"/>
<path d="M148.5 86.2h2.8l1 1-1 1.1h-2.8z" fill="none" stroke="#800000" stroke-width=".21"/>
<path d="M148.5 88.8h2.8l1 1-1 1h-2.8z" fill-rule="evenodd" fill="#ffff80"/>
<path d="M148.5 88.8h2.8l1 1-1 1h-2.8z" fill="none" stroke="#800000" stroke-width=".21"/>
<path d="M148.5 93.9h2.8l1 1-1 1h-2.8z" fill-rule="evenodd" fill="#ffff80"/>
<path d="M148.5 93.9h2.8l1 1-1 1h-2.8z" fill="none" stroke="#800000" stroke-width=".21"/>
<path d="M148.5 96.4h2.8l1 1-1 1h-2.8z" fill-rule="evenodd" fill="#ffff80"/>
<path d="M148.5 96.4h2.8l1 1-1 1h-2.8z" fill="none" stroke="#800000" stroke-width=".21"/>
<path d="M149.5 106.6h2.8v2h-2.8l-1-1z" fill-rule="evenodd" fill="#ffff80"/>
<path d="M149.5 106.6h2.8v2h-2.8l-1-1z" fill="none" stroke="#800000" stroke-width=".21"/>
<path d="M149.5 124.4h2.8v2h-2.8l-1-1z" fill-rule="evenodd" fill="#ffff80"/>
<path d="M149.5 124.4h2.8v2h-2.8l-1-1z" fill="none" stroke="#800000" stroke-width=".21"/>
<path d="M149.5 121.8h2.8v2.1h-2.8l-1-1z" fill-rule="evenodd" fill="#ffff80"/>
<path d="M149.5 121.8h2.8v2.1h-2.8l-1-1z" fill="none" stroke="#800000" stroke-width=".21"/>
<path d="M116.7 64.3l1-1h1.8l1 1-1 1.1h-1.8z" fill-rule="evenodd" fill="#ffff80"/>
<path d="M116.7 64.3l1-1h1.8l1 1-1 1.1h-1.8z" fill="none" stroke="#800000" stroke-width=".21"/>
<path d="M193 23.6h43.3v145h-43.3z" fill-rule="evenodd" fill="#80ff80"/>
<path d="M193 23.6h43.3v145h-43.3z" fill="none" stroke="#800000" stroke-width=".21"/>
<path d="M193 25.2h2.8l1 1-1 1h-2.8z" fill-rule="evenodd" fill="#ffff80"/>
<path d="M193 25.2h2.8l1 1-1 1h-2.8z" fill="none" stroke="#800000" stroke-width=".21"/>
<path d="M193 27.7h2.8l1 1-1 1h-2.8z" fill-rule="evenodd" fill="#ffff80"/>
<path d="M193 27.7h2.8l1 1-1 1h-2.8z" fill="none" stroke="#800000" stroke-width=".21"/>
<path d="M193 32.8h2.8l1 1-1 1h-2.8z" fill-rule="evenodd" fill="#ffff80"/>
<path d="M193 32.8h2.8l1 1-1 1h-2.8z" fill="none" stroke="#800000" stroke-width=".21"/>
<path d="M193 35.3h2.8l1 1.1-1 1h-2.8z" fill-rule="evenodd" fill="#ffff80"/>
<path d="M193 35.3h2.8l1 1.1-1 1h-2.8z" fill="none" stroke="#800000" stroke-width=".21"/>
<path d="M193 40.4h2.8l1 1-1 1.1h-2.8z" fill-rule="evenodd" fill="#ffff80"/>
<path d="M193 40.4h2.8l1 1-1 1.1h-2.8z" fill="none" stroke="#800000" stroke-width=".21"/>
<path d="M193 43h2.8l1 1-1 1h-2.8z" fill-rule="evenodd" fill="#ffff80"/>
<path d="M193 43h2.8l1 1-1 1h-2.8z" fill="none" stroke="#800000" stroke-width=".21"/>
<path d="M193 48.1h2.8l1 1-1 1h-2.8z" fill-rule="evenodd" fill="#ffff80"/>
<path d="M193 48.1h2.8l1 1-1 1h-2.8z" fill="none" stroke="#800000" stroke-width=".21"/>
<path d="M193 50.6h2.8l1 1-1 1h-2.8z" fill-rule="evenodd" fill="#ffff80"/>
<path d="M193 50.6h2.8l1 1-1 1h-2.8z" fill="none" stroke="#800000" stroke-width=".21"/>
<path d="M193 55.7h2.8l1 1-1 1h-2.8z" fill-rule="evenodd" fill="#ffff80"/>
<path d="M193 55.7h2.8l1 1-1 1h-2.8z" fill="none" stroke="#800000" stroke-width=".21"/>
<path d="M193 58.2h2.8l1 1.1-1 1h-2.8z" fill-rule="evenodd" fill="#ffff80"/>
<path d="M193 58.2h2.8l1 1.1-1 1h-2.8z" fill="none" stroke="#800000" stroke-width=".21"/>
<path d="M193 63.3h2.8l1 1-1 1.1h-2.8z" fill-rule="evenodd" fill="#ffff80"/>
<path d="M193 63.3h2.8l1 1-1 1.1h-2.8z" fill="none" stroke="#800000" stroke-width=".21"/>
<path d="M193 65.9h2.8l1 1-1 1h-2.8z" fill-rule="evenodd" fill="#ffff80"/>
<path d="M193 65.9h2.8l1 1-1 1h-2.8z" fill="none" stroke="#800000" stroke-width=".21"/>
<path d="M193 71h2.8l1 1-1 1h-2.8z" fill-rule="evenodd" fill="#ffff80"/>
<path d="M193 71h2.8l1 1-1 1h-2.8z" fill="none" stroke="#800000" stroke-width=".21"/>
<path d="M193 73.5h2.8l1 1-1 1h-2.8z" fill-rule="evenodd" fill="#ffff80"/>
<path d="M193 73.5h2.8l1 1-1 1h-2.8z" fill="none" stroke="#800000" stroke-width=".21"/>
<path d="M193 78.6h2.8l1 1-1 1h-2.8z" fill-rule="evenodd" fill="#ffff80"/>
<path d="M193 78.6h2.8l1 1-1 1h-2.8z" fill="none" stroke="#800000" stroke-width=".21"/>
<path d="M193 81.1h2.8l1 1-1 1.1h-2.8z" fill-rule="evenodd" fill="#ffff80"/>
<path d="M193 81.1h2.8l1 1-1 1.1h-2.8z" fill="none" stroke="#800000" stroke-width=".21"/>
<path d="M193 86.2h2.8l1 1-1 1.1h-2.8z" fill-rule="evenodd" fill="#ffff80"/>
<path d="M193 86.2h2.8l1 1-1 1.1h-2.8z" fill="none" stroke="#800000" stroke-width=".21"/>
<path d="M193 88.8h2.8l1 1-1 1h-2.8z" fill-rule="evenodd" fill="#ffff80"/>
<path d="M193 88.8h2.8l1 1-1 1h-2.8z" fill="none" stroke="#800000" stroke-width=".21"/>
<path d="M193 93.9h2.8l1 1-1 1h-2.8z" fill-rule="evenodd" fill="#ffff80"/>
<path d="M193 93.9h2.8l1 1-1 1h-2.8z" fill="none" stroke="#800000" stroke-width=".21"/>
<path d="M193 96.4h2.8l1 1-1 1h-2.8z" fill-rule="evenodd" fill="#ffff80"/>
<path d="M193 96.4h2.8l1 1-1 1h-2.8z" fill="none" stroke="#800000" stroke-width=".21"/>
<path d="M193 105.1l1-1.1h2.8v2.1h-2.8z" fill-rule="evenodd" fill="#ffff80"/>
<path d="M193 105.1l1-1.1h2.8v2.1h-2.8z" fill="none" stroke="#800000" stroke-width=".21"/>
<path d="M193 107.6l1-1h2.8v2h-2.8z" fill-rule="evenodd" fill="#ffff80"/>
<path d="M193 107.6l1-1h2.8v2h-2.8z" fill="none" stroke="#800000" stroke-width=".21"/>
<path d="M193 112.7l1-1h2.8v2h-2.8z" fill-rule="evenodd" fill="#ffff80"/>
<path d="M193 112.7l1-1h2.8v2h-2.8z" fill="none" stroke="#800000" stroke-width=".21"/>
<path d="M193 122.9l1-1.1h2.8v2.1h-2.8z" fill-rule="evenodd" fill="#ffff80"/>
<path d="M193 122.9l1-1.1h2.8v2.1h-2.8z" fill="none" stroke="#800000" stroke-width=".21"/>
<path d="M193 125.4l1-1h2.8v2h-2.8z" fill-rule="evenodd" fill="#ffff80"/>
<path d="M193 125.4l1-1h2.8v2h-2.8z" fill="none" stroke="#800000" stroke-width=".21"/>
<path d="M193 140.7l1-1.1h2.8v2.1h-2.8z" fill-rule="evenodd" fill="#ffff80"/>
<path d="M193 140.7l1-1.1h2.8v2.1h-2.8z" fill="none" stroke="#800000" stroke-width=".21"/>
<path d="M193 148.3l1-1h2.8v2h-2.8z" fill-rule="evenodd" fill="#ffff80"/>
<path d="M193 148.3l1-1h2.8v2h-2.8z" fill="none" stroke="#800000" stroke-width=".21"/>
<path d="M194 149.8h2.8v2.1h-2.8l-1-1.1z" fill-rule="evenodd" fill="#ffff80"/>
<path d="M194 149.8h2.8v2.1h-2.8l-1-1.1z" fill="none" stroke="#800000" stroke-width=".21"/>
<path d="M193 155.9l1-1h2.8v2h-2.8z" fill-rule="evenodd" fill="#ffff80"/>
<path d="M193 155.9l1-1h2.8v2h-2.8z" fill="none" stroke="#800000" stroke-width=".21"/>
<path d="M193 158.5l1-1h2.8v2h-2.8z" fill-rule="evenodd" fill="#ffff80"/>
<path d="M193 158.5l1-1h2.8v2h-2.8z" fill="none" stroke="#800000" stroke-width=".21"/>
<path d="M193 161l1-1h2.8v2h-2.8z" fill-rule="evenodd" fill="#ffff80"/>
<path d="M193 161l1-1h2.8v2h-2.8z" fill="none" stroke="#800000" stroke-width=".21"/>
<path d="M193 166.1l1-1h2.8v2h-2.8z" fill-rule="evenodd" fill="#ffff80"/>
<path d="M193 166.1l1-1h2.8v2h-2.8z" fill="none" stroke="#800000" stroke-width=".21"/>
<path d="M233.5 104h2.8v2.1h-2.8l-1.1-1z" fill-rule="evenodd" fill="#ffff80"/>
<path d="M233.5 104h2.8v2.1h-2.8l-1.1-1z" fill="none" stroke="#800000" stroke-width=".21"/>
<path d="M233.5 111.7h2.8v2h-2.8l-1.1-1z" fill-rule="evenodd" fill="#ffff80"/>
<path d="M233.5 111.7h2.8v2h-2.8l-1.1-1z" fill="none" stroke="#800000" stroke-width=".21"/>
<path d="M233.5 101.5h2.8v2h-2.8l-1.1-1z" fill-rule="evenodd" fill="#ffff80"/>
<path d="M233.5 101.5h2.8v2h-2.8l-1.1-1z" fill="none" stroke="#800000" stroke-width=".21"/>
<path d="M232.6 87.5l1-1h1.8l1 1-1 1h-1.8z" fill-rule="evenodd" fill="#bac0ca"/>
<path d="M232.6 87.5l1-1h1.8l1 1-1 1h-1.8z" fill="none" stroke="#a6acb6" stroke-width=".21"/>
<path d="M233.5 86.2h1.7l1.1 1-1.1 1.1h-1.7l-1.1-1.1z" fill-rule="evenodd" fill="#d5e4ff"/>
<path d="M233.5 86.2h1.7l1.1 1-1.1 1.1h-1.7l-1.1-1.1z" fill="none" stroke="#71809b" stroke-width=".21"/>
<path d="M232.6 95.1l1-1h1.8l1 1-1 1h-1.8z" fill-rule="evenodd" fill="#bac0ca"/>
<path d="M232.6 95.1l1-1h1.8l1 1-1 1h-1.8z" fill="none" stroke="#a6acb6" stroke-width=".21"/>
<path d="M233.5 93.9h1.7l1.1 1-1.1 1h-1.7l-1.1-1z" fill-rule="evenodd" fill="#d5e4ff"/>
<path d="M233.5 93.9h1.7l1.1 1-1.1 1h-1.7l-1.1-1z" fill="none" stroke="#71809b" stroke-width=".21"/>
<path d="M232.4 148.3l1.1-1h2.8v2h-2.8z" fill-rule="evenodd" fill="#ffff80"/>
<path d="M232.4 148.3l1.1-1h2.8v2h-2.8z" fill="none" stroke="#800000" stroke-width=".21"/>
<path d="M233.5 154.9h2.8v2h-2.8l-1.1-1z" fill-rule="evenodd" fill="#ffff80"/>
<path d="M233.5 154.9h2.8v2h-2.8l-1.1-1z" fill="none" stroke="#800000" stroke-width=".21"/>
<path d="M233.5 144.7h2.8v2.1h-2.8l-1.1-1z" fill-rule="evenodd" fill="#ffff80"/>
<path d="M233.5 144.7h2.8v2.1h-2.8l-1.1-1z" fill="none" stroke="#800000" stroke-width=".21"/>
<path d="M233.6 129.7h1.8l1 1-1 1.1h-1.8l-1-1.1z" fill-rule="evenodd" fill="#bac0ca"/>
<path d="M233.6 129.7h1.8l1 1-1 1.1h-1.8l-1-1.1z" fill="none" stroke="#a6acb6" stroke-width=".21"/>
<path d="M233.5 129.5h1.7l1.1 1-1.1 1h-1.7l-1.1-1z" fill-rule="evenodd" fill="#d5e4ff"/>
<path d="M233.5 129.5h1.7l1.1 1-1.1 1h-1.7l-1.1-1z" fill="none" stroke="#71809b" stroke-width=".21"/>
<path d="M232.6 138.4l1-1h1.8l1 1-1 1h-1.8z" fill-rule="evenodd" fill="#bac0ca"/>
<path d="M232.6 138.4l1-1h1.8l1 1-1 1h-1.8z" fill="none" stroke="#a6acb6" stroke-width=".21"/>
<path d="M233.5 137.1h1.7l1.1 1-1.1 1h-1.7l-1.1-1z" fill-rule="evenodd" fill="#d5e4ff"/>
<path d="M233.5 137.1h1.7l1.1 1-1.1 1h-1.7l-1.1-1z" fill="none" stroke="#71809b" stroke-width=".21"/>
<path d="M193 145.8l1-1.1h2.8v2.1h-2.8z" fill-rule="evenodd" fill="#ffff80"/>
<path d="M193 145.8l1-1.1h2.8v2.1h-2.8z" fill="none" stroke="#800000" stroke-width=".21"/>
<path d="M233.5 160h1.7l1.1 1-1.1 1h-1.7l-1.1-1z" fill-rule="evenodd" fill="#ffff80"/>
<path d="M233.5 160h1.7l1.1 1-1.1 1h-1.7l-1.1-1z" fill="none" stroke="#800000" stroke-width=".21"/>
<path d="M232.4 163.6l1.1-1.1h1.7l1.1 1.1-1.1 1h-1.7z" fill-rule="evenodd" fill="#ffff80"/>
<path d="M232.4 163.6l1.1-1.1h1.7l1.1 1.1-1.1 1h-1.7z" fill="none" stroke="#800000" stroke-width=".21"/>
<path d="M193 135.6l1-1h1.8l1 1-1 1h-1.8z" fill-rule="evenodd" fill="#ffff80"/>
<path d="M193 135.6l1-1h1.8l1 1-1 1h-1.8z" fill="none" stroke="#800000" stroke-width=".21"/>
<path d="M60.7 171.2v2.5M60.7 178.8v2.6M149.8 171.2v2.5M149.8 178.8v2.6M152.3 168.6h2M160.5 168.6h2" fill="none" stroke="#000" stroke-width=".25"/>
<path d="M58.7 176.8h4M58.7 175.8h4M60.7 173.7v2.1M60.7 176.8v2M147.8 176.8h4M147.8 175.8h4M149.8 173.7v2.1M149.8 176.8v2M154.4 167.7h6v2h-6z" fill="none" stroke="#00f" stroke-width=".25"/>
<path d="M163.7 163.6h2.6M165 163.6v2.5M58.2 189h5.1M58.9 189.8h3.6M59.7 190.5h2M60.5 191.3h.5M60.7 186.5v2.5M147.2 189h5.1M148 189.8h3.5M148.7 190.5h2.1M149.5 191.3h.5M149.8 186.5v2.5" fill="none" stroke="#800000" stroke-width=".25"/>
<circle cx="144.7" cy="168.6" r=".51" fill="#000080"/>
<circle cx="144.7" cy="168.6" r=".51" fill="none" stroke="#000080" stroke-width=".21"/>
<path d="M144.7 166.1v2.5" fill="none" stroke="#000" stroke-width=".25"/>
<circle cx="144.7" cy="168.6" r=".51" fill="#000080"/>
<circle cx="144.7" cy="168.6" r=".51" fill="none" stroke="#000080" stroke-width=".21"/>
<path d="M143.4 163.6h2.5l1.3 2.5h-5.1z" fill="none" stroke="#000" stroke-width=".25"/>
<circle cx="165" cy="168.6" r=".51" fill="#000080"/>
<circle cx="165" cy="168.6" r=".51" fill="none" stroke="#000080" stroke-width=".21"/>
<path d="M165 168.6v2.6" fill="none" stroke="#000" stroke-width=".25"/>
<circle cx="165" cy="168.6" r=".51" fill="#000080"/>
<circle cx="165" cy="168.6" r=".51" fill="none" stroke="#000080" stroke-width=".21"/>
<path d="M162.5 171.2h5.1l-1.3 2.5h-2.6z" fill="none" stroke="#000" stroke-width=".25"/>
<path d="M30.2 117.8h5.1M31 118.5h3.5M31.7 119.3h2.1M32.7 115.2v2.6M32.5 120.1h.5" fill="none" stroke="#800000" stroke-width=".25"/>
<path d="M17.5 105h5.1v7.7h-5.1z" fill-rule="evenodd" fill="#ffffb0"/>
<path d="M17.5 105h5.1v7.7h-5.1z" fill="none" stroke="#800000" stroke-width=".21"/>
<path d="M22.6 110.1h7.6M22.6 107.6h7.6" fill="none" stroke="#000" stroke-width=".25"/>
<g fill="none" stroke="#d0a19e" stroke-width=".25">
<path d="M169.1 24.5h1l.5-.5h1l.5 .5h1.1M169.1 25.2h1l.5 .5h1l.5-.5h1.1M169.1 27.1h1l.5-.5h1l.5 .5h1.1M169.1 27.7h1l.5 .5h1l.5-.5h1.1M169.1 32.2h1l.5-.5h1l.5 .5h1.1M169.1 32.8h1l.5 .5h1l.5-.5h1.1M169.1 34.7h1l.5-.5h1l.5 .5h1.1M169.1 35.3h1l.5 .5h1l.5-.5h1.1M169.1 39.8h1l.5-.5h1l.5 .5h1.1M169.1 40.4h1l.5 .5h1l.5-.5h1.1M169.1 42.3h1l.5-.5h1l.5 .5h1.1M169.1 43h1l.5 .5h1l.5-.5h1.1"/>
<path d="M169.1 47.4h1l.5-.5h1l.5 .5h1.1M169.1 48.1h1l.5 .5h1l.5-.5h1.1M169.1 50h1l.5-.5h1l.5 .5h1.1M169.1 50.6h1l.5 .5h1l.5-.5h1.1M169.1 55.1h1l.5-.6h1l.5 .6h1.1M169.1 55.7h1l.5 .5h1l.5-.5h1.1M169.1 57.6h1l.5-.5h1l.5 .5h1.1M169.1 58.2h1l.5 .5h1l.5-.5h1.1M169.1 70.3h1l.5-.5h1l.5 .5h1.1M169.1 71h1l.5 .5h1l.5-.5h1.1M169.1 72.9h1l.5-.5h1l.5 .5h1.1M169.1 73.5h1l.5 .5h1l.5-.5h1.1"/>
<path d="M169.1 78h1l.5-.6h1l.5 .6h1.1M169.1 78.6h1l.5 .5h1l.5-.5h1.1M169.1 62.7h1l.5-.5h1l.5 .5h1.1M169.1 63.3h1l.5 .5h1l.5-.5h1.1M169.1 65.2h1l.5-.5h1l.5 .5h1.1M169.1 65.9h1l.5 .5h1l.5-.5h1.1M169.1 80.5h1l.5-.5h1l.5 .5h1.1M169.1 81.1h1l.5 .5h1l.5-.5h1.1M169.1 85.6h1l.5-.5h1l.5 .5h1.1M169.1 86.2h1l.5 .5h1l.5-.5h1.1M169.1 88.1h1l.5-.5h1l.5 .5h1.1M169.1 88.8h1l.5 .5h1l.5-.5h1.1"/>
<path d="M169.1 93.2h1l.5-.5h1l.5 .5h1.1M169.1 93.9h1l.5 .5h1l.5-.5h1.1M169.1 95.8h1l.5-.6h1l.5 .6h1.1M169.1 96.4h1l.5 .5h1l.5-.5h1.1"/>
</g>
<g fill="none" stroke="#d0a19e" stroke-width=".21">
<path d="M169.1 25.2l-1.5 1M169.1 27.7l-1.5 1M169.1 32.8l-1.5 1M169.1 35.3l-1.5 1.1M169.1 40.4l-1.5 1M169.1 43l-1.5 1M169.1 48.1l-1.5 1M169.1 50.6l-1.5 1M169.1 55.7l-1.5 1M169.1 58.2l-1.5 1.1M169.1 71l-1.5 1M169.1 73.5l-1.5 1"/>
<path d="M169.1 78.6l-1.5 1M169.1 63.3l-1.5 1M169.1 65.9l-1.5 1M169.1 81.1l-1.5 1M169.1 86.2l-1.5 1M169.1 88.8l-1.5 1M169.1 93.9l-1.5 1M169.1 96.4l-1.5 1"/>
</g>
<g fill="none" stroke="#f00" stroke-width=".25">
<path d="M168.8 24.3h1.1l.5-.5h1l.5 .5h1M168.8 24.9h1.1l.5 .5h1l.5-.5h1M168.8 26.8h1.1l.5-.5h1l.5 .5h1M168.8 27.5h1.1l.5 .5h1l.5-.5h1M168.8 31.9h1.1l.5-.5h1l.5 .5h1M168.8 32.5h1.1l.5 .6h1l.5-.6h1M168.8 34.4h1.1l.5-.5h1l.5 .5h1M168.8 35.1h1.1l.5 .5h1l.5-.5h1M168.8 39.5h1.1l.5-.5h1l.5 .5h1M168.8 40.2h1.1l.5 .5h1l.5-.5h1M168.8 42.1h1.1l.5-.5h1l.5 .5h1M168.8 42.7h1.1l.5 .5h1l.5-.5h1"/>
<path d="M168.8 47.2h1.1l.5-.5h1l.5 .5h1M168.8 47.8h1.1l.5 .5h1l.5-.5h1M168.8 49.7h1.1l.5-.5h1l.5 .5h1M168.8 50.4h1.1l.5 .5h1l.5-.5h1M168.8 54.8h1.1l.5-.5h1l.5 .5h1M168.8 55.4h1.1l.5 .5h1l.5-.5h1M168.8 57.3h1.1l.5-.5h1l.5 .5h1M168.8 58h1.1l.5 .5h1l.5-.5h1M168.8 70.1h1.1l.5-.5h1l.5 .5h1M168.8 70.7h1.1l.5 .5h1l.5-.5h1M168.8 72.6h1.1l.5-.5h1l.5 .5h1M168.8 73.2h1.1l.5 .6h1l.5-.6h1"/>
<path d="M168.8 77.7h1.1l.5-.5h1l.5 .5h1M168.8 78.3h1.1l.5 .5h1l.5-.5h1M168.8 62.4h1.1l.5-.5h1l.5 .5h1M168.8 63.1h1.1l.5 .5h1l.5-.5h1M168.8 65h1.1l.5-.5h1l.5 .5h1M168.8 65.6h1.1l.5 .5h1l.5-.5h1M168.8 80.2h1.1l.5-.5h1l.5 .5h1M168.8 80.9h1.1l.5 .5h1l.5-.5h1M168.8 85.3h1.1l.5-.5h1l.5 .5h1M168.8 86h1.1l.5 .5h1l.5-.5h1M168.8 87.9h1.1l.5-.5h1l.5 .5h1M168.8 88.5h1.1l.5 .5h1l.5-.5h1"/>
<path d="M168.8 93h1.1l.5-.5h1l.5 .5h1M168.8 93.6h1.1l.5 .5h1l.5-.5h1M168.8 95.5h1.1l.5-.5h1l.5 .5h1M168.8 96.1h1.1l.5 .6h1l.5-.6h1"/>
</g>
<g fill="none" stroke="#f00" stroke-width=".21">
<path d="M168.8 24.9l-1.2 1.3M168.8 27.5l-1.2 1.2M168.8 32.5l-1.2 1.3M168.8 35.1l-1.2 1.3M168.8 40.2l-1.2 1.2M168.8 42.7l-1.2 1.3M168.8 47.8l-1.2 1.3M168.8 50.4l-1.2 1.2M168.8 55.4l-1.2 1.3M168.8 58l-1.2 1.3M168.8 70.7l-1.2 1.3M168.8 73.2l-1.2 1.3"/>
<path d="M168.8 78.3l-1.2 1.3M168.8 63.1l-1.2 1.2M168.8 65.6l-1.2 1.3M168.8 80.9l-1.2 1.2M168.8 86l-1.2 1.2M168.8 88.5l-1.2 1.3M168.8 93.6l-1.2 1.3M168.8 96.1l-1.2 1.3"/>
</g>
<path d="M55.6 100h15.3v15.2h-15.3z" fill-rule="evenodd" fill="#ffffb0"/>
<path d="M55.6 100h15.3v15.2h-15.3z" fill="none" stroke="#800000" stroke-width=".21"/>
<g fill="none" stroke="#000" stroke-width=".25">
<path d="M32.7 107.6h2M40.9 107.6h2M48 107.6h7.6M48 112.7h7.6M70.9 107.6h7.6M70.9 102.5h7.6M70.9 112.7h7.6M96.3 110.1v2M96.3 118.3v2M182.8 181.4h5.1v2.5h-5.1zM185.4 183.9v2.6M190.5 181.4h5v2.5h-5z"/>
<path d="M193 183.9v2.6"/>
</g>
<g fill="none" stroke="#800000" stroke-width=".25">
<path d="M78.5 122.9h5.1M79.3 123.6h3.5M80.1 124.4h2M80.8 125.1h.5M81.1 120.3v2.6M86.2 122.9h5M86.9 123.6h3.6M87.7 124.4h2M88.4 125.1h.6M88.7 120.3v2.6M93.8 122.9h5.1M94.6 123.6h3.5"/>
<path d="M95.3 124.4h2.1M96.1 125.1h.5M96.3 120.3v2.6M182.8 189h5.1M183.6 189.8h3.6M184.4 190.5h2M185.1 191.3h.5M185.4 186.5v2.5M190.5 189h5M191.2 189.8h3.6M192 190.5h2M192.8 191.3h.5"/>
<path d="M193 186.5v2.5"/>
</g>
<path d="M47 111.7l2 2M49 111.7l-2 2" fill="none" stroke="#f00" stroke-width=".21"/>
<path d="M34.8 106.6h6v2h-6zM95.4 112.2h2v6h-2z" fill="none" stroke="#00f" stroke-width=".25"/>
<path d="M98.9 166.1h15.2v15.3h-15.2z" fill-rule="evenodd" fill="#ffffb0"/>
<path d="M98.9 166.1h15.2v15.3h-15.2z" fill="none" stroke="#800000" stroke-width=".21"/>
<path d="M40.4 171.2v2M40.4 179.4v2M73.4 168.6h2.6M86.2 168.6h2.5M91.2 168.6h7.7M91.2 173.7h7.7M91.2 178.8h7.7M114.1 173.7h7.7M114.1 168.6h7.7M114.1 178.8h7.7" fill="none" stroke="#000" stroke-width=".25"/>
<path d="M119.2 189h5.1M120 189.8h3.5M120.8 190.5h2M121.5 191.3h.5M121.8 186.5v2.5" fill="none" stroke="#800000" stroke-width=".25"/>
<path d="M39.4 173.3h2v6h-2zM76 168.6a1.27 1.27 0 0 1 1.3-1.2 1.27 1.27 0 0 1 1.2 1.2 1.27 1.27 0 0 1 1.3-1.2 1.27 1.27 0 0 1 1.3 1.2 1.27 1.27 0 0 1 1.2-1.2 1.27 1.27 0 0 1 1.3 1.2 1.27 1.27 0 0 1 1.3-1.2 1.27 1.27 0 0 1 1.3 1.2M76 166.6h10.2M76 166.1h10.2" fill="none" stroke="#00f" stroke-width=".25"/>
<circle cx="45.4" cy="168.6" r=".51" fill="#000080"/>
<circle cx="45.4" cy="168.6" r=".51" fill="none" stroke="#000080" stroke-width=".21"/>
<path d="M45.5 166.1v2.5" fill="none" stroke="#000" stroke-width=".25"/>
<circle cx="45.4" cy="168.6" r=".51" fill="#000080"/>
<circle cx="45.4" cy="168.6" r=".51" fill="none" stroke="#000080" stroke-width=".21"/>
<path d="M17.5 167.4l2.5-1.3v5.1l-2.5-1.3zM20 168.6h2.6M27.6 168.6h2M35.8 168.6h2M44.2 163.6h2.5l1.3 2.5h-5.1zM76 178.8h2M84.2 178.8h2" fill="none" stroke="#000" stroke-width=".25"/>
<path d="M90 97.4h2.5M91.2 97.4v2.6M23.8 163.6h2.6M25.1 163.6v2.5M68.3 189h5.1M69.1 189.8h3.6M69.9 190.5h2M70.6 191.3h.6M70.9 186.5v2.5" fill="none" stroke="#800000" stroke-width=".25"/>
<path d="M29.7 167.7h6v2h-6zM78.1 177.8h6v2h-6z" fill="none" stroke="#00f" stroke-width=".25"/>
<g fill="none" stroke="#d0a19e" stroke-width=".25">
<path d="M57.2 24.5h1l.5-.5h1l.5 .5h1M57.2 25.2h1l.5 .5h1l.5-.5h1M57.2 27.1h1l.5-.5h1l.5 .5h1M57.2 27.7h1l.5 .5h1l.5-.5h1M57.2 32.2h1l.5-.6h1l.5 .6h1M57.2 32.8h1l.5 .5h1l.5-.5h1M57.2 34.7h1l.5-.5h1l.5 .5h1M57.2 35.3h1l.5 .5h1l.5-.5h1M57.2 39.8h1l.5-.5h1l.5 .5h1M57.2 40.4h1l.5 .5h1l.5-.5h1M57.2 42.3h1l.5-.5h1l.5 .5h1M57.2 43h1l.5 .5h1l.5-.5h1"/>
<path d="M57.2 47.4h1l.5-.5h1l.5 .5h1M57.2 48.1h1l.5 .5h1l.5-.5h1M57.2 50h1l.5-.5h1l.5 .5h1M57.2 50.6h1l.5 .5h1l.5-.5h1"/>
</g>
<path d="M57.2 25.2l-1.6 1M57.2 27.7l-1.6 1M57.2 32.8l-1.6 1M57.2 35.3l-1.6 1.1M57.2 40.4l-1.6 1M57.2 43l-1.6 1M57.2 48.1l-1.6 1M57.2 50.6l-1.6 1" fill="none" stroke="#d0a19e" stroke-width=".21"/>
<g fill="none" stroke="#f00" stroke-width=".25">
<path d="M56.9 24.3h1l.5-.5h1l.6 .5h1M56.9 24.9h1l.5 .5h1l.6-.5h1M56.9 26.8h1l.5-.5h1l.6 .5h1M56.9 27.5h1l.5 .5h1l.6-.5h1M56.9 31.9h1l.5-.5h1l.6 .5h1M56.9 32.5h1l.5 .5h1l.6-.5h1M56.9 34.4h1l.5-.5h1l.6 .5h1M56.9 35.1h1l.5 .5h1l.6-.5h1M56.9 39.5h1l.5-.5h1l.6 .5h1M56.9 40.2h1l.5 .5h1l.6-.5h1M56.9 42.1h1l.5-.5h1l.6 .5h1M56.9 42.7h1l.5 .5h1l.6-.5h1"/>
<path d="M56.9 47.2h1l.5-.5h1l.6 .5h1M56.9 47.8h1l.5 .5h1l.6-.5h1M56.9 49.7h1l.5-.5h1l.6 .5h1M56.9 50.3h1l.5 .6h1l.6-.6h1"/>
</g>
<path d="M56.9 24.9l-1.3 1.3M56.9 27.5l-1.3 1.2M56.9 32.5l-1.3 1.3M56.9 35.1l-1.3 1.3M56.9 40.2l-1.3 1.2M56.9 42.7l-1.3 1.3M56.9 47.8l-1.3 1.3M56.9 50.3l-1.3 1.3" fill="none" stroke="#f00" stroke-width=".21"/>
<circle cx="48" cy="135.6" r=".51" fill="#000080"/>
<circle cx="48" cy="135.6" r=".51" fill="none" stroke="#000080" stroke-width=".21"/>
<path d="M55.6 133h20.4v17.8h-20.4z" fill-rule="evenodd" fill="#ffffb0"/>
<path d="M55.6 133h20.4v17.8h-20.4z" fill="none" stroke="#800000" stroke-width=".21"/>
<path d="M48 135.6h7.6M76 135.6h7.6M76 138.1h7.6M48 148.3h7.6M76 148.3h7.6" fill="none" stroke="#000" stroke-width=".25"/>
<circle cx="48" cy="135.6" r=".51" fill="#000080"/>
<circle cx="48" cy="135.6" r=".51" fill="none" stroke="#000080" stroke-width=".21"/>
<path d="M22.6 138.1v2.6M48 138.1h7.6M106.5 138.1v2.6M22.6 145.7v2.6M48 143.2h7.6M76 143.2h7.6M106.5 145.7v2.6" fill="none" stroke="#000" stroke-width=".25"/>
<path d="M18.7 130.5h2.6M20 130.5v2.5M20 153.4h5.1M20.8 154.1h3.5M21.5 154.9h2.1M22.3 155.7h.5M22.6 150.8v2.6M104 153.4h5.1M104.7 154.1h3.6M105.5 154.9h2M106.3 155.7h.5M106.5 150.8v2.6" fill="none" stroke="#800000" stroke-width=".25"/>
<path d="M20.6 143.7h4M20.6 142.7h4M22.6 140.7v2M22.6 143.7v2M104.5 143.7h4M104.5 142.7h4M106.5 140.7v2M106.5 143.7v2" fill="none" stroke="#00f" stroke-width=".25"/>
<circle cx="132" cy="176.3" r=".51" fill="#000080"/>
<circle cx="132" cy="176.3" r=".51" fill="none" stroke="#000080" stroke-width=".21"/>
<path d="M132 176.3v2" fill="none" stroke="#000" stroke-width=".25"/>
<circle cx="132" cy="176.3" r=".51" fill="#000080"/>
<circle cx="132" cy="176.3" r=".51" fill="none" stroke="#000080" stroke-width=".21"/>
<g fill="none" stroke="#000" stroke-width=".25">
<path d="M274.4 54.2h5.1M279.5 56.7v2.6M172.7 105.1h2.5M32.7 148.3h2M40.9 148.3h2M86.2 143.2h2.5M93.8 143.2h2.5M50.5 171.2v2.5M50.5 178.8v2.6M134.5 176.3h2M142.7 176.3h2M132 184.5v2"/>
<circle cx="171.4" cy="105" r="1.27"/>
</g>
<g fill="none" stroke="#00f" stroke-width=".25">
<path d="M34.8 147.2h6v2.1h-6zM88.7 143.2h2M90.7 141.2v4M91.7 143.2h2.1M91.7 141.2v4M48.5 176.8h4M48.5 175.8h4M50.5 173.7v2.1M50.5 176.8v2M52.1 174.2h1M52.6 173.7v1.1M131 178.4h2v6h-2z"/>
<path d="M136.6 175.3h6v2h-6z"/>
<circle cx="279.5" cy="54.2" r="2.54"/>
</g>
<g fill="none" stroke="#800000" stroke-width=".25">
<path d="M107.8 130.5h2.5M109.1 130.5v2.5M30.2 153.4h5.1M31 154.1h3.5M31.7 154.9h2.1M32.5 155.7h.5M32.7 150.8v2.6M83.6 153.4h5.1M84.4 154.1h3.5M85.1 154.9h2.1M85.9 155.7h.5M86.2 150.8v2.6"/>
<path d="M93.8 153.4h5.1M94.6 154.1h3.5M95.3 154.9h2.1M96.1 155.7h.5M96.3 150.8v2.6M48 189h5.1M48.8 189.8h3.5M49.5 190.5h2.1M50.3 191.3h.5M50.5 186.5v2.5M129.4 189h5.1M130.2 189.8h3.5"/>
<path d="M130.9 190.5h2.1M131.7 191.3h.5M132 186.5v2.5"/>
</g>
<circle cx="279.5" cy="54.2" r=".64" fill="#00f"/>
<circle cx="279.5" cy="54.2" r=".64" fill="none" stroke="#00f" stroke-width=".21"/>
<path d="M279.5 59.3v2.5M277 61.8h5M277.7 62.6h3.6M278.5 63.3h2M279.3 64.1h.5" fill="none" stroke="#800000" stroke-width=".25"/>
<circle cx="271.9" cy="54.2" r=".51" fill="#000080"/>
<circle cx="271.9" cy="54.2" r=".51" fill="none" stroke="#000080" stroke-width=".21"/>
<path d="M271.9 54.2v4.4M271.9 65v4.4" fill="none" stroke="#000" stroke-width=".25"/>
<circle cx="271.9" cy="54.2" r=".51" fill="#000080"/>
<circle cx="271.9" cy="54.2" r=".51" fill="none" stroke="#000080" stroke-width=".21"/>
<path d="M271.9 61.8l1.9 3.2h-3.8z" fill="#00f"/>
<path d="M270.6 61.8h2.5M271.9 61.8l1.9 3.2h-3.8z" fill="none" stroke="#00f" stroke-width=".25"/>
<path d="M270 58.6h3.8l-1.9 3.2z" fill="#00f"/>
<path d="M270 58.6h3.8l-1.9 3.2zM270.6 61.8l-1.3 1.3M274.4 60.5l-1.3 1.3" fill="none" stroke="#00f" stroke-width=".25"/>
<path d="M269.3 72h5.1M270.1 72.7h3.6M270.8 73.5h2.1M271.6 74.3h.5M271.9 69.4v2.6" fill="none" stroke="#800000" stroke-width=".25"/>
<path d="M243.9 125.4h25.4v43.2h-25.4z" fill-rule="evenodd" fill="#80ff80"/>
<path d="M243.9 125.4h25.4v43.2h-25.4z" fill="none" stroke="#800000" stroke-width=".21"/>
<path d="M244.9 147.3h2.8v2h-2.8l-1-1z" fill-rule="evenodd" fill="#ffff80"/>
<path d="M244.9 147.3h2.8v2h-2.8l-1-1z" fill="none" stroke="#800000" stroke-width=".21"/>
<path d="M244.9 154.9h2.8v2h-2.8l-1-1z" fill-rule="evenodd" fill="#ffff80"/>
<path d="M244.9 154.9h2.8v2h-2.8l-1-1z" fill="none" stroke="#800000" stroke-width=".21"/>
<path d="M244.9 144.7h2.8v2.1h-2.8l-1-1z" fill-rule="evenodd" fill="#ffff80"/>
<path d="M244.9 144.7h2.8v2.1h-2.8l-1-1z" fill="none" stroke="#800000" stroke-width=".21"/>
<path d="M245 129.7h1.8l1 1-1 1.1h-1.8l-1-1.1z" fill-rule="evenodd" fill="#bac0ca"/>
<path d="M245 129.7h1.8l1 1-1 1.1h-1.8l-1-1.1z" fill="none" stroke="#a6acb6" stroke-width=".21"/>
<path d="M244.9 129.5h1.8l1 1-1 1h-1.8l-1-1z" fill-rule="evenodd" fill="#d5e4ff"/>
<path d="M244.9 129.5h1.8l1 1-1 1h-1.8l-1-1z" fill="none" stroke="#71809b" stroke-width=".21"/>
<path d="M244 138.4l1-1h1.8l1 1-1 1h-1.8z" fill-rule="evenodd" fill="#bac0ca"/>
<path d="M244 138.4l1-1h1.8l1 1-1 1h-1.8z" fill="none" stroke="#a6acb6" stroke-width=".21"/>
<path d="M244.9 137.1h1.8l1 1-1 1h-1.8l-1-1z" fill-rule="evenodd" fill="#d5e4ff"/>
<path d="M244.9 137.1h1.8l1 1-1 1h-1.8l-1-1z" fill="none" stroke="#71809b" stroke-width=".21"/>
<path d="M244.9 160h1.8l1 1-1 1h-1.8l-1-1z" fill-rule="evenodd" fill="#ffff80"/>
<path d="M244.9 160h1.8l1 1-1 1h-1.8l-1-1z" fill="none" stroke="#800000" stroke-width=".21"/>
<path d="M243.9 163.6l1-1.1h1.8l1 1.1-1 1h-1.8z" fill-rule="evenodd" fill="#ffff80"/>
<path d="M243.9 163.6l1-1.1h1.8l1 1.1-1 1h-1.8z" fill="none" stroke="#800000" stroke-width=".21"/>
<circle cx="256.6" cy="54.2" r="2.54" fill="none" stroke="#00f" stroke-width=".25"/>
<path d="M251.5 54.2h5.1M256.6 56.7v2.6" fill="none" stroke="#000" stroke-width=".25"/>
<circle cx="256.6" cy="54.2" r=".64" fill="#00f"/>
<circle cx="256.6" cy="54.2" r=".64" fill="none" stroke="#00f" stroke-width=".21"/>
<path d="M256.6 59.3v2.5M254.1 61.8h5.1M254.8 62.6h3.6M255.6 63.3h2M256.3 64.1h.6" fill="none" stroke="#800000" stroke-width=".25"/>
<circle cx="249" cy="54.2" r=".51" fill="#000080"/>
<circle cx="249" cy="54.2" r=".51" fill="none" stroke="#000080" stroke-width=".21"/>
<path d="M249 54.2v4.4M249 65v4.4" fill="none" stroke="#000" stroke-width=".25"/>
<circle cx="249" cy="54.2" r=".51" fill="#000080"/>
<circle cx="249" cy="54.2" r=".51" fill="none" stroke="#000080" stroke-width=".21"/>
<path d="M249 61.8l1.9 3.2h-3.8z" fill="#00f"/>
<path d="M247.7 61.8h2.5M249 61.8l1.9 3.2h-3.8z" fill="none" stroke="#00f" stroke-width=".25"/>
<path d="M247.1 58.6h3.8l-1.9 3.2z" fill="#00f"/>
<path d="M247.1 58.6h3.8l-1.9 3.2zM247.7 61.8l-1.3 1.3M251.5 60.5l-1.3 1.3" fill="none" stroke="#00f" stroke-width=".25"/>
<path d="M246.4 72h5.1M247.2 72.7h3.6M248 73.5h2M248.7 74.3h.5M249 69.4v2.6" fill="none" stroke="#800000" stroke-width=".25"/>
<path d="M243.9 82.1h25.4v35.7h-25.4z" fill-rule="evenodd" fill="#80ff80"/>
<path d="M243.9 82.1h25.4v35.7h-25.4z" fill="none" stroke="#800000" stroke-width=".21"/>
<path d="M244.9 104h2.8v2.1h-2.8l-1-1z" fill-rule="evenodd" fill="#ffff80"/>
<path d="M244.9 104h2.8v2.1h-2.8l-1-1z" fill="none" stroke="#800000" stroke-width=".21"/>
<path d="M244.9 111.7h2.8v2h-2.8l-1-1z" fill-rule="evenodd" fill="#ffff80"/>
<path d="M244.9 111.7h2.8v2h-2.8l-1-1z" fill="none" stroke="#800000" stroke-width=".21"/>
<path d="M244.9 101.5h2.8v2h-2.8l-1-1z" fill-rule="evenodd" fill="#ffff80"/>
<path d="M244.9 101.5h2.8v2h-2.8l-1-1z" fill="none" stroke="#800000" stroke-width=".21"/>
<path d="M244 87.5l1-1h1.8l1 1-1 1h-1.8z" fill-rule="evenodd" fill="#bac0ca"/>
<path d="M244 87.5l1-1h1.8l1 1-1 1h-1.8z" fill="none" stroke="#a6acb6" stroke-width=".21"/>
<path d="M244.9 86.2h1.8l1 1-1 1.1h-1.8l-1-1.1z" fill-rule="evenodd" fill="#d5e4ff"/>
<path d="M244.9 86.2h1.8l1 1-1 1.1h-1.8l-1-1.1z" fill="none" stroke="#71809b" stroke-width=".21"/>
<path d="M244 95.1l1-1h1.8l1 1-1 1h-1.8z" fill-rule="evenodd" fill="#bac0ca"/>
<path d="M244 95.1l1-1h1.8l1 1-1 1h-1.8z" fill="none" stroke="#a6acb6" stroke-width=".21"/>
<path d="M244.9 93.9h1.8l1 1-1 1h-1.8l-1-1z" fill-rule="evenodd" fill="#d5e4ff"/>
<path d="M244.9 93.9h1.8l1 1-1 1h-1.8l-1-1z" fill="none" stroke="#71809b" stroke-width=".21"/>
<path d="M274.4 89.8h5.1v20.3h-5.1z" fill-rule="evenodd" fill="#ffffb0"/>
<path d="M274.4 89.8h5.1v20.3h-5.1z" fill="none" stroke="#800000" stroke-width=".21"/>
<g fill="none" stroke="#00f" stroke-width=".25">
<path d="M90.8 63.4h6v2h-6zM90.8 68.5h6v2h-6zM86.7 114.7h4M86.7 115.7h4M88.7 112.7v2M88.7 115.7v2.1M154.4 134.6h6v2h-6zM154.4 139.7h6v2h-6zM136.6 172.7h6v2h-6z"/>
<circle cx="277" cy="92.3" r="1.27"/>
<circle cx="277" cy="97.4" r="1.27"/>
<circle cx="277" cy="97.4" r="1.26"/>
<circle cx="277" cy="102.5" r="1.27"/>
<circle cx="277" cy="107.6" r="1.27"/>
</g>
<path d="M88.7 64.3h2M88.7 69.4h2M96.9 64.3h2M96.9 69.4h2M88.7 110.1v2.6M88.7 117.8v2.5M152.3 135.6h2M160.5 135.6h2M152.3 140.7h2M160.5 140.7h2M134.5 173.7h2M142.7 173.7h2" fill="none" stroke="#000" stroke-width=".25"/>
<circle cx="284.6" cy="28.7" r=".51" fill="#000080"/>
<circle cx="284.6" cy="28.7" r=".51" fill="none" stroke="#000080" stroke-width=".21"/>
<circle cx="284.6" cy="31.3" r=".51" fill="#000080"/>
<circle cx="284.6" cy="31.3" r=".51" fill="none" stroke="#000080" stroke-width=".21"/>
<circle cx="284.6" cy="33.8" r=".51" fill="#000080"/>
<circle cx="284.6" cy="33.8" r=".51" fill="none" stroke="#000080" stroke-width=".21"/>
<circle cx="284.6" cy="36.4" r=".51" fill="#000080"/>
<circle cx="284.6" cy="36.4" r=".51" fill="none" stroke="#000080" stroke-width=".21"/>
<path d="M266.8 23.6h10.2v15.3h-10.2z" fill-rule="evenodd" fill="#ffffb0"/>
<path d="M266.8 23.6h10.2v15.3h-10.2z" fill="none" stroke="#800000" stroke-width=".21"/>
<path d="M259.2 26.2h7.6M259.2 28.7h7.6M277 26.2h7.6M277 28.7h7.6" fill="none" stroke="#000" stroke-width=".25"/>
<circle cx="284.6" cy="28.7" r=".51" fill="#000080"/>
<circle cx="284.6" cy="28.7" r=".51" fill="none" stroke="#000080" stroke-width=".21"/>
<path d="M259.2 31.3h7.6M277 31.3h7.6" fill="none" stroke="#000" stroke-width=".25"/>
<circle cx="284.6" cy="31.3" r=".51" fill="#000080"/>
<circle cx="284.6" cy="31.3" r=".51" fill="none" stroke="#000080" stroke-width=".21"/>
<path d="M259.2 33.8h7.6M277 33.8h7.6" fill="none" stroke="#000" stroke-width=".25"/>
<circle cx="284.6" cy="33.8" r=".51" fill="#000080"/>
<circle cx="284.6" cy="33.8" r=".51" fill="none" stroke="#000080" stroke-width=".21"/>
<path d="M259.2 36.4h7.6M277 36.4h7.6" fill="none" stroke="#000" stroke-width=".25"/>
<circle cx="284.6" cy="36.4" r=".51" fill="#000080"/>
<circle cx="284.6" cy="36.4" r=".51" fill="none" stroke="#000080" stroke-width=".21"/>
<path d="M256.6 38.9v2.5M284.6 38.9v2.5M254.1 41.4h5.1M254.8 42.2h3.6M255.6 43h2M256.3 43.7h.6M282 41.4h5.1M282.8 42.2h3.6M283.6 43h2M284.3 43.7h.5" fill="none" stroke="#800000" stroke-width=".25"/>
<path d="M165 166.1v2.5h-2.5M60.7 181.4v5.1M149.8 181.4v5.1" fill="none" stroke="#000080" stroke-width=".25"/>
<circle cx="165" cy="168.6" r=".51" fill="#000080"/>
<circle cx="165" cy="168.6" r=".51" fill="none" stroke="#000080" stroke-width=".21"/>
<g fill="none" stroke="#000080" stroke-width=".25">
<path d="M42.9 26.2h73.8M42.9 28.7h73.8M42.9 33.8h73.8M42.9 36.4h73.8M152.3 26.2h40.7M152.3 28.7h40.7M152.3 33.8h40.7M152.3 36.4h40.7M42.9 41.4h73.8M42.9 44h73.8M42.9 49.1h73.8M42.9 51.6h73.8"/>
<path d="M42.9 56.7h73.8M152.3 41.4h40.7M152.3 49.1h40.7M152.3 51.6h40.7M152.3 56.7h40.7M152.3 44h40.7M152.3 59.3h40.7M152.3 64.3h40.7M152.3 66.9h40.7M152.3 72h40.7M152.3 74.5h40.7M152.3 79.6h40.7"/>
<path d="M152.3 82.1h40.7M152.3 87.2h40.7M152.3 89.8h40.7M152.3 94.9h40.7M152.3 97.4h40.7M30.2 110.1h2.5v5.1M42.9 107.6h5.1M78.5 112.7h2.6v7.6M78.5 107.6h17.8v2.5M175.2 105.1h17.8M172.7 140.7h20.3M172.7 155.9h20.3"/>
<path d="M172.7 158.5h20.3"/>
</g>
<circle cx="96.3" cy="107.6" r=".51" fill="#000080"/>
<circle cx="96.3" cy="107.6" r=".51" fill="none" stroke="#000080" stroke-width=".21"/>
<path d="M96.3 107.6h17.8" fill="none" stroke="#000080" stroke-width=".25"/>
<circle cx="96.3" cy="107.6" r=".51" fill="#000080"/>
<circle cx="96.3" cy="107.6" r=".51" fill="none" stroke="#000080" stroke-width=".21"/>
<path d="M70.9 168.6h2.5M86.2 178.8h5M172.7 166.1h20.3" fill="none" stroke="#000080" stroke-width=".25"/>
<circle cx="70.9" cy="168.6" r=".51" fill="#000080"/>
<circle cx="70.9" cy="168.6" r=".51" fill="none" stroke="#000080" stroke-width=".21"/>
<g fill="none" stroke="#000080" stroke-width=".25">
<path d="M42.9 72h20.4M42.9 74.5h20.4M42.9 82.1h20.4M42.9 84.7h20.4M152.3 115.2h20.4M152.3 117.8h20.4M152.3 107.6h40.7M152.3 112.7h40.7M45.5 135.6v7.6h2.5M152.3 122.9h40.7M152.3 125.4h40.7M83.6 148.3h2.6v2.5"/>
<path d="M76 178.8h-5.1v7.7M88.7 168.6h2.5M121.8 178.8v7.7"/>
</g>
<circle cx="45.4" cy="135.6" r=".51" fill="#000080"/>
<circle cx="45.4" cy="135.6" r=".51" fill="none" stroke="#000080" stroke-width=".21"/>
<path d="M106.5 135.6v2.5M83.6 143.2h2.6M96.3 143.2v7.6M106.5 148.3v2.5" fill="none" stroke="#000080" stroke-width=".25"/>
<circle cx="106.5" cy="135.6" r=".51" fill="#000080"/>
<circle cx="106.5" cy="135.6" r=".51" fill="none" stroke="#000080" stroke-width=".21"/>
<path d="M83.6 135.6h2.6" fill="none" stroke="#000080" stroke-width=".25"/>
<circle cx="86.2" cy="135.6" r=".51" fill="#000080"/>
<circle cx="86.2" cy="135.6" r=".51" fill="none" stroke="#000080" stroke-width=".21"/>
<path d="M22.6 135.6v2.5M22.6 148.3v2.5" fill="none" stroke="#000080" stroke-width=".25"/>
<circle cx="22.6" cy="135.6" r=".51" fill="#000080"/>
<circle cx="22.6" cy="135.6" r=".51" fill="none" stroke="#000080" stroke-width=".21"/>
<path d="M45.5 135.6h2.5v2.5" fill="none" stroke="#000080" stroke-width=".25"/>
<circle cx="45.4" cy="135.6" r=".51" fill="#000080"/>
<circle cx="45.4" cy="135.6" r=".51" fill="none" stroke="#000080" stroke-width=".21"/>
<circle cx="48" cy="135.6" r=".51" fill="#000080"/>
<circle cx="48" cy="135.6" r=".51" fill="none" stroke="#000080" stroke-width=".21"/>
<path d="M20 133v2.6h25.5M32.7 148.3v2.5M42.9 148.3h5.1" fill="none" stroke="#000080" stroke-width=".25"/>
<circle cx="22.6" cy="135.6" r=".51" fill="#000080"/>
<circle cx="22.6" cy="135.6" r=".51" fill="none" stroke="#000080" stroke-width=".21"/>
<circle cx="45.4" cy="135.6" r=".51" fill="#000080"/>
<circle cx="45.4" cy="135.6" r=".51" fill="none" stroke="#000080" stroke-width=".21"/>
<path d="M109.1 133v2.6h-22.9v2.5h-2.6" fill="none" stroke="#000080" stroke-width=".25"/>
<circle cx="106.5" cy="135.6" r=".51" fill="#000080"/>
<circle cx="106.5" cy="135.6" r=".51" fill="none" stroke="#000080" stroke-width=".21"/>
<circle cx="86.2" cy="135.6" r=".51" fill="#000080"/>
<circle cx="86.2" cy="135.6" r=".51" fill="none" stroke="#000080" stroke-width=".21"/>
<path d="M22.6 168.6h5" fill="none" stroke="#000080" stroke-width=".25"/>
<circle cx="25.1" cy="168.6" r=".51" fill="#000080"/>
<circle cx="25.1" cy="168.6" r=".51" fill="none" stroke="#000080" stroke-width=".21"/>
<path d="M25.1 166.1v2.5" fill="none" stroke="#000080" stroke-width=".25"/>
<circle cx="25.1" cy="168.6" r=".51" fill="#000080"/>
<circle cx="25.1" cy="168.6" r=".51" fill="none" stroke="#000080" stroke-width=".21"/>
<path d="M40.4 168.6v2.6" fill="none" stroke="#000080" stroke-width=".25"/>
<circle cx="40.4" cy="168.6" r=".51" fill="#000080"/>
<circle cx="40.4" cy="168.6" r=".51" fill="none" stroke="#000080" stroke-width=".21"/>
<path d="M40.4 181.4v2.5h-10.2" fill="none" stroke="#000080" stroke-width=".25"/>
<circle cx="40.4" cy="183.9" r=".51" fill="#000080"/>
<circle cx="40.4" cy="183.9" r=".51" fill="none" stroke="#000080" stroke-width=".21"/>
<path d="M60.7 168.6v2.6" fill="none" stroke="#000080" stroke-width=".25"/>
<circle cx="60.7" cy="168.6" r=".51" fill="#000080"/>
<circle cx="60.7" cy="168.6" r=".51" fill="none" stroke="#000080" stroke-width=".21"/>
<path d="M37.8 168.6h33.1v5.1h20.3" fill="none" stroke="#000080" stroke-width=".25"/>
<circle cx="40.4" cy="168.6" r=".51" fill="#000080"/>
<circle cx="40.4" cy="168.6" r=".51" fill="none" stroke="#000080" stroke-width=".21"/>
<circle cx="45.4" cy="168.6" r=".51" fill="#000080"/>
<circle cx="45.4" cy="168.6" r=".51" fill="none" stroke="#000080" stroke-width=".21"/>
<circle cx="50.5" cy="168.6" r=".51" fill="#000080"/>
<circle cx="50.5" cy="168.6" r=".51" fill="none" stroke="#000080" stroke-width=".21"/>
<circle cx="60.7" cy="168.6" r=".51" fill="#000080"/>
<circle cx="60.7" cy="168.6" r=".51" fill="none" stroke="#000080" stroke-width=".21"/>
<circle cx="70.9" cy="168.6" r=".51" fill="#000080"/>
<circle cx="70.9" cy="168.6" r=".51" fill="none" stroke="#000080" stroke-width=".21"/>
<path d="M50.5 168.6v2.6M50.5 181.4v5.1" fill="none" stroke="#000080" stroke-width=".25"/>
<circle cx="50.5" cy="168.6" r=".51" fill="#000080"/>
<circle cx="50.5" cy="168.6" r=".51" fill="none" stroke="#000080" stroke-width=".21"/>
<path d="M264.2 54.2h10.2M30.2 107.6h2.5" fill="none" stroke="#000080" stroke-width=".25"/>
<circle cx="271.9" cy="54.2" r=".51" fill="#000080"/>
<circle cx="271.9" cy="54.2" r=".51" fill="none" stroke="#000080" stroke-width=".21"/>
<path d="M241.3 54.2h10.2M236.3 155.9h7.6M236.3 145.8h7.6M236.3 148.3h7.6M236.3 161h7.6M236.3 163.6h7.6" fill="none" stroke="#000080" stroke-width=".25"/>
<circle cx="249" cy="54.2" r=".51" fill="#000080"/>
<circle cx="249" cy="54.2" r=".51" fill="none" stroke="#000080" stroke-width=".21"/>
<path d="M91.2 100v2.5h-12.7M236.3 112.7h7.6M236.3 102.5h7.6M236.3 105.1h7.6" fill="none" stroke="#000080" stroke-width=".25"/>
<circle cx="88.7" cy="102.5" r=".51" fill="#000080"/>
<circle cx="88.7" cy="102.5" r=".51" fill="none" stroke="#000080" stroke-width=".21"/>
<path d="M88.7 102.5v7.6" fill="none" stroke="#000080" stroke-width=".25"/>
<circle cx="88.7" cy="102.5" r=".51" fill="#000080"/>
<circle cx="88.7" cy="102.5" r=".51" fill="none" stroke="#000080" stroke-width=".21"/>
<path d="M101.4 64.3v5.1h-2.5" fill="none" stroke="#000080" stroke-width=".25"/>
<circle cx="101.4" cy="64.3" r=".51" fill="#000080"/>
<circle cx="101.4" cy="64.3" r=".51" fill="none" stroke="#000080" stroke-width=".21"/>
<path d="M73.4 64.3h15.3M73.4 69.4h15.3M165 135.6v5.1h-2.5" fill="none" stroke="#000080" stroke-width=".25"/>
<circle cx="165" cy="135.6" r=".51" fill="#000080"/>
<circle cx="165" cy="135.6" r=".51" fill="none" stroke="#000080" stroke-width=".21"/>
<path d="M142.1 135.6h10.2M162.5 135.6h30.5M142.1 140.7h10.2" fill="none" stroke="#000080" stroke-width=".25"/>
<circle cx="165" cy="135.6" r=".51" fill="#000080"/>
<circle cx="165" cy="135.6" r=".51" fill="none" stroke="#000080" stroke-width=".21"/>
<path d="M98.9 64.3h17.8" fill="none" stroke="#000080" stroke-width=".25"/>
<circle cx="101.4" cy="64.3" r=".51" fill="#000080"/>
<circle cx="101.4" cy="64.3" r=".51" fill="none" stroke="#000080" stroke-width=".21"/>
<path d="M149.8 168.6v2.6" fill="none" stroke="#000080" stroke-width=".25"/>
<circle cx="149.8" cy="168.6" r=".51" fill="#000080"/>
<circle cx="149.8" cy="168.6" r=".51" fill="none" stroke="#000080" stroke-width=".21"/>
<path d="M134.5 168.6v5.1M144.7 173.7v2.6" fill="none" stroke="#000080" stroke-width=".25"/>
<circle cx="134.5" cy="168.6" r=".51" fill="#000080"/>
<circle cx="134.5" cy="168.6" r=".51" fill="none" stroke="#000080" stroke-width=".21"/>
<path d="M121.8 168.6h12.7" fill="none" stroke="#000080" stroke-width=".25"/>
<circle cx="134.5" cy="168.6" r=".51" fill="#000080"/>
<circle cx="134.5" cy="168.6" r=".51" fill="none" stroke="#000080" stroke-width=".21"/>
<path d="M121.8 173.7h10.2v2.6h2.5" fill="none" stroke="#000080" stroke-width=".25"/>
<circle cx="132" cy="176.3" r=".51" fill="#000080"/>
<circle cx="132" cy="176.3" r=".51" fill="none" stroke="#000080" stroke-width=".21"/>
<path d="M134.5 168.6h17.8" fill="none" stroke="#000080" stroke-width=".25"/>
<circle cx="149.8" cy="168.6" r=".51" fill="#000080"/>
<circle cx="149.8" cy="168.6" r=".51" fill="none" stroke="#000080" stroke-width=".21"/>
<circle cx="144.7" cy="168.6" r=".51" fill="#000080"/>
<circle cx="144.7" cy="168.6" r=".51" fill="none" stroke="#000080" stroke-width=".21"/>
<circle cx="134.5" cy="168.6" r=".51" fill="#000080"/>
<circle cx="134.5" cy="168.6" r=".51" fill="none" stroke="#000080" stroke-width=".21"/>
<path d="M241.3 28.7h17.9M284.6 26.2v12.7" fill="none" stroke="#000080" stroke-width=".25"/>
<circle cx="284.6" cy="28.7" r=".51" fill="#000080"/>
<circle cx="284.6" cy="28.7" r=".51" fill="none" stroke="#000080" stroke-width=".21"/>
<circle cx="284.6" cy="31.3" r=".51" fill="#000080"/>
<circle cx="284.6" cy="31.3" r=".51" fill="none" stroke="#000080" stroke-width=".21"/>
<circle cx="284.6" cy="33.8" r=".51" fill="#000080"/>
<circle cx="284.6" cy="33.8" r=".51" fill="none" stroke="#000080" stroke-width=".21"/>
<circle cx="284.6" cy="36.4" r=".51" fill="#000080"/>
<circle cx="284.6" cy="36.4" r=".51" fill="none" stroke="#000080" stroke-width=".21"/>
<path d="M241.3 33.8h17.9M259.2 36.4h-2.6v2.5" fill="none" stroke="#000080" stroke-width=".25"/>
<circle cx="256.6" cy="36.4" r=".51" fill="#000080"/>
<circle cx="256.6" cy="36.4" r=".51" fill="none" stroke="#000080" stroke-width=".21"/>
<path d="M259.2 31.3h-2.6v5.1" fill="none" stroke="#000080" stroke-width=".25"/>
<circle cx="256.6" cy="31.3" r=".51" fill="#000080"/>
<circle cx="256.6" cy="31.3" r=".51" fill="none" stroke="#000080" stroke-width=".21"/>
<circle cx="256.6" cy="36.4" r=".51" fill="#000080"/>
<circle cx="256.6" cy="36.4" r=".51" fill="none" stroke="#000080" stroke-width=".21"/>
<path d="M259.2 26.2h-2.6v5.1" fill="none" stroke="#000080" stroke-width=".25"/>
<circle cx="256.6" cy="31.3" r=".51" fill="#000080"/>
<circle cx="256.6" cy="31.3" r=".51" fill="none" stroke="#000080" stroke-width=".21"/>
<path d="M42.9 64.3h20.4M42.9 66.9h20.4M42.9 77.1h20.4M42.9 61.8h20.4M172.7 148.3h20.3M172.7 150.8h20.3M172.7 145.8h20.3M172.7 161h20.3" fill="none" stroke="#000080" stroke-width=".76"/>
<path d="M236.3 94.9h7.6M236.3 87.2h7.6M236.3 138.1h7.6M236.3 130.5h7.6" fill="none" stroke="#cbdaff" stroke-width="1.3"/>
<path d="M236.8 94.4l1 .9M236.8 86.8l1 .9M239.3 94.4l1 .9M239.3 86.8l1 .9M241.9 94.4l1 .9M241.9 86.8l1 .9M236.8 137.7l1 .9M236.8 130l1 .9M239.3 137.7l1 .9M239.3 130l1 .9M241.9 137.7l1 .9M241.9 130l1 .9" fill="none" stroke="#adbce7" stroke-width=".38"/>
<path d="M236.3 94.9h7.6M236.3 87.2h7.6M236.3 138.1h7.6M236.3 130.5h7.6" fill="none" stroke="#adbce7" stroke-width=".25"/>
<path d="M17.5 181.4h5.1v7.6h-5.1z" fill-rule="evenodd" fill="#ffffb0"/>
<path d="M17.5 181.4h5.1v7.6h-5.1z" fill="none" stroke="#800000" stroke-width=".21"/>
<path d="M22.6 183.9h7.6M22.6 186.5h7.6" fill="none" stroke="#000" stroke-width=".25"/>
<path d="M40.4 183.9v2.6h-10.2" fill="none" stroke="#000080" stroke-width=".25"/>
<circle cx="40.4" cy="183.9" r=".51" fill="#000080"/>
<circle cx="40.4" cy="183.9" r=".51" fill="none" stroke="#000080" stroke-width=".21"/>
<use href="#words"/>
</svg>
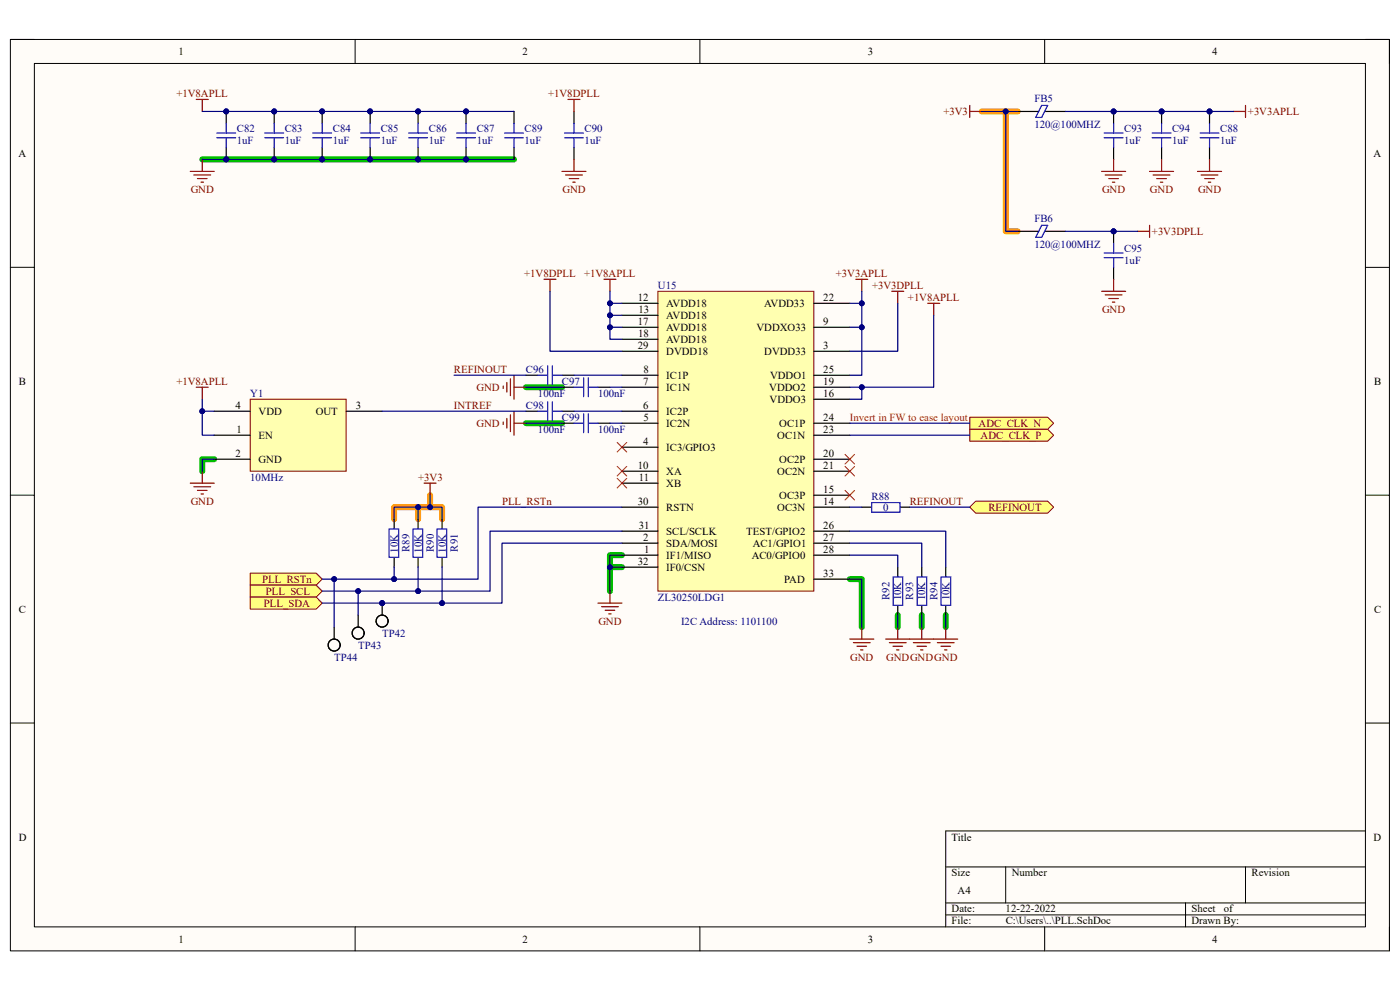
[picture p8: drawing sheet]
<svg xmlns="http://www.w3.org/2000/svg" width="297mm" height="210mm" viewBox="0 0 297 210" stroke-linecap="round" stroke-linejoin="round" font-family="sans-serif">
<defs><g id="words">
<g font-size="2.3">
<text x="37.9" y="11.7">1</text>
<text x="110.9" y="11.7">2</text>
<text x="184.1" y="11.7">3</text>
<text x="257.1" y="11.7">4</text>
<text x="3.9" y="33.3">A</text>
<text x="291.4" y="33.3">A</text>
<text x="135.3" y="63.8">12</text>
<text x="141.4" y="65.1">AVDD18</text>
<text x="162.1" y="65.1">AVDD33</text>
<text x="174.7" y="63.8">22</text>
<text x="135.3" y="68.9">17</text>
<text x="135.4" y="71.5">18</text>
<text x="135.4" y="66.4">13</text>
<text x="141.4" y="67.6">AVDD18</text>
<text x="141.4" y="70.2">AVDD18</text>
<text x="160.5" y="70.2">VDDXO33</text>
<text x="174.7" y="68.9">9</text>
<text x="135.3" y="74">29</text>
<text x="141.4" y="72.7">AVDD18</text>
<text x="141.4" y="75.3">DVDD18</text>
<text x="162.1" y="75.3">DVDD33</text>
<text x="174.7" y="74">3</text>
<text x="4" y="81.6">B</text>
<text x="136.5" y="81.6">7</text>
<text x="136.5" y="79.1">8</text>
<text x="141.4" y="82.9">IC1N</text>
<text x="141.4" y="80.3">IC1P</text>
<text x="163.2" y="82.9">VDDO2</text>
<text x="163.4" y="80.3">VDDO1</text>
<text x="174.7" y="81.6">19</text>
<text x="174.7" y="79.1">25</text>
<text x="291.5" y="81.6">B</text>
<text x="50" y="86.7">4</text>
<text x="54.9" y="88">VDD</text>
<text x="67" y="88">OUT</text>
<text x="75.5" y="86.7">3</text>
<text x="136.5" y="86.7">6</text>
<text x="136.5" y="89.3">5</text>
<text x="141.4" y="88">IC2P</text>
<text x="163.3" y="85.4">VDDO3</text>
<text x="174.7" y="84.2">16</text>
<text x="174.7" y="89.3">24</text>
<text x="50.2" y="91.8">1</text>
<text x="54.9" y="93.1">EN</text>
<text x="136.5" y="94.4">4</text>
<text x="141.4" y="95.6">IC3/GPIO3</text>
<text x="141.4" y="90.6">IC2N</text>
<text x="164.9" y="93.1">OC1N</text>
<text x="165.3" y="90.6">OC1P</text>
<text x="174.7" y="91.8">23</text>
<text x="50" y="96.9">2</text>
<text x="54.9" y="98.2">GND</text>
<text x="135.3" y="99.4">10</text>
<text x="135.5" y="102">11</text>
<text x="141.4" y="100.7">XA</text>
<text x="164.9" y="100.7">OC2N</text>
<text x="165.3" y="98.2">OC2P</text>
<text x="174.7" y="96.9">20</text>
<text x="174.7" y="99.4">21</text>
<text x="135.3" y="107.1">30</text>
<text x="141.4" y="103.3">XB</text>
<text x="165.3" y="105.8">OC3P</text>
<text x="174.7" y="107.1">14</text>
<text x="174.7" y="104.5">15</text>
<text x="135.5" y="112.1">31</text>
<text x="141.4" y="108.3">RSTN</text>
<text x="141.4" y="113.4">SCL/SCLK</text>
<text x="158.3" y="113.4">TEST/GPIO2</text>
<text x="164.9" y="108.3">OC3N</text>
<text x="174.7" y="112.1">26</text>
<text x="135.3" y="119.8">32</text>
<text x="136.5" y="114.7">2</text>
<text x="136.7" y="117.3">1</text>
<text x="141.4" y="118.5">IF1/MISO</text>
<text x="141.4" y="116">SDA/MOSI</text>
<text x="159.5" y="118.5">AC0/GPIO0</text>
<text x="159.7" y="116">AC1/GPIO1</text>
<text x="174.7" y="114.7">27</text>
<text x="174.7" y="117.3">28</text>
<text x="141.4" y="121.1">IF0/CSN</text>
<text x="166.4" y="123.6">PAD</text>
<text x="174.7" y="122.3">33</text>
<text x="4" y="130">C</text>
<text x="291.5" y="130">C</text>
<text x="4" y="178.3">D</text>
<text x="201.9" y="178.3">Title</text>
<text x="291.4" y="178.3">D</text>
<text x="201.9" y="185.9">Size</text>
<text x="214.6" y="185.9">Number</text>
<text x="265.5" y="185.9">Revision</text>
<text x="203.2" y="189.7">A4</text>
<text x="201.9" y="193.5">Date:</text>
<text x="201.9" y="196.1">File:</text>
<text x="213.3" y="193.5">12-22-2022</text>
<text x="213.4" y="196.1">C:\Users\..\PLL.SchDoc</text>
<text x="252.8" y="196.1">Drawn By:</text>
<text x="252.8" y="193.5">Sheet</text>
<text x="259.6" y="193.5">of</text>
<text x="37.9" y="199.9">1</text>
<text x="110.9" y="199.9">2</text>
<text x="184.1" y="199.9">3</text>
<text x="257.1" y="199.9">4</text>
</g>
<g font-size="2.3" fill="#800000">
<text x="37.4" y="20.6">+1V8APLL</text>
<text x="116.3" y="20.6">+1V8DPLL</text>
<text x="200.2" y="24.4">+3V3</text>
<text x="264.8" y="24.4">+3V3APLL</text>
<text x="40.5" y="40.9">GND</text>
<text x="119.3" y="40.9">GND</text>
<text x="233.8" y="40.9">GND</text>
<text x="244" y="40.9">GND</text>
<text x="254.2" y="40.9">GND</text>
<text x="244.4" y="49.8">+3V3DPLL</text>
<text x="111.2" y="58.7">+1V8DPLL</text>
<text x="123.9" y="58.7">+1V8APLL</text>
<text x="177.3" y="58.7">+3V3APLL</text>
<text x="185" y="61.3">+3V3DPLL</text>
<text x="192.6" y="63.8">+1V8APLL</text>
<text x="233.8" y="66.4">GND</text>
<text x="37.4" y="81.6">+1V8APLL</text>
<text x="96.3" y="79.1">REFINOUT</text>
<text x="101.1" y="82.9">GND</text>
<text x="96.3" y="86.7">INTREF</text>
<text x="101.1" y="90.6">GND</text>
<text x="207.6" y="90.6">ADC_CLK_N</text>
<text x="208" y="93.1">ADC_CLK_P</text>
<text x="88.7" y="102">+3V3</text>
<text x="40.5" y="107.1">GND</text>
<text x="106.5" y="107.1">PLL_RSTn</text>
<text x="193" y="107.1">REFINOUT</text>
<text x="209.7" y="108.3">REFINOUT</text>
<text x="55.6" y="123.6">PLL_RSTn</text>
<text x="56" y="128.7">PLL_SDA</text>
<text x="56.4" y="126.2">PLL_SCL</text>
<text x="127" y="132.5">GND</text>
<text x="180.4" y="140.1">GND</text>
<text x="188" y="140.1">GNDGNDGND</text>
</g>
<g font-size="2.3" fill="#000080">
<text x="219.5" y="21.6">FB5</text>
<text x="50.2" y="27.9">C82</text>
<text x="60.4" y="27.9">C83</text>
<text x="70.6" y="27.9">C84</text>
<text x="80.8" y="27.9">C85</text>
<text x="91" y="27.9">C86</text>
<text x="101.1" y="27.9">C87</text>
<text x="111.3" y="27.9">C89</text>
<text x="124" y="27.9">C90</text>
<text x="219.5" y="27.2">120@100MHZ</text>
<text x="238.5" y="27.9">C93</text>
<text x="248.7" y="27.9">C94</text>
<text x="258.9" y="27.9">C88</text>
<text x="50.2" y="30.5">1uF</text>
<text x="60.4" y="30.5">1uF</text>
<text x="70.6" y="30.5">1uF</text>
<text x="80.8" y="30.5">1uF</text>
<text x="91" y="30.5">1uF</text>
<text x="101.1" y="30.5">1uF</text>
<text x="111.3" y="30.5">1uF</text>
<text x="124" y="30.5">1uF</text>
<text x="238.5" y="30.5">1uF</text>
<text x="248.7" y="30.5">1uF</text>
<text x="258.9" y="30.5">1uF</text>
<text x="219.5" y="47">FB6</text>
<text x="219.5" y="52.6">120@100MHZ</text>
<text x="238.5" y="53.4">C95</text>
<text x="238.5" y="55.9">1uF</text>
<text x="139.6" y="61.3">U15</text>
<text x="111.6" y="79.1">C96</text>
<text x="119.2" y="81.6">C97</text>
<text x="53.1" y="84.2">Y1</text>
<text x="111.6" y="86.7">C98</text>
<text x="114.1" y="84.2">100nF</text>
<text x="119.2" y="89.3">C99</text>
<text x="126.9" y="84.2">100nF</text>
<text x="114.1" y="91.8">100nF</text>
<text x="126.9" y="91.8">100nF</text>
<text x="53.1" y="102">10MHz</text>
<text x="184.9" y="106.1">R88</text>
<text x="187.4" y="108.3">0</text>
<text x="84.4" y="117.2" transform="rotate(-90 84.4 117.2)">10K</text>
<text x="86.9" y="117.1" transform="rotate(-90 86.9 117.1)">R89</text>
<text x="89.5" y="117.2" transform="rotate(-90 89.5 117.2)">10K</text>
<text x="92" y="117.1" transform="rotate(-90 92 117.1)">R90</text>
<text x="94.6" y="117.2" transform="rotate(-90 94.6 117.2)">10K</text>
<text x="97.1" y="117" transform="rotate(-90 97.1 117)">R91</text>
<text x="139.6" y="127.4">ZL30250LDG1</text>
<text x="188.7" y="127.3" transform="rotate(-90 188.7 127.3)">R92</text>
<text x="191.2" y="127.4" transform="rotate(-90 191.2 127.4)">10K</text>
<text x="193.8" y="127.2" transform="rotate(-90 193.8 127.2)">R93</text>
<text x="196.3" y="127.4" transform="rotate(-90 196.3 127.4)">10K</text>
<text x="198.9" y="127.3" transform="rotate(-90 198.9 127.3)">R94</text>
<text x="201.4" y="127.4" transform="rotate(-90 201.4 127.4)">10K</text>
<text x="76" y="137.6">TP43</text>
<text x="81.1" y="135">TP42</text>
<text x="144.5" y="132.5">I2C Address: 1101100</text>
<text x="70.9" y="140.1">TP44</text>
</g>
<text font-size="2.3" fill="#f00" x="180.3" y="89.3">Invert in FW to ease layout</text>
</g></defs>
<path d="M2.2 8.4h292.6v193.3h-292.6z" fill-rule="evenodd" fill="#fffcf8"/>
<path d="M2.2 8.4h292.6v193.3h-292.6z" fill="none" stroke="#000" stroke-width=".21"/>
<path d="M7.3 13.5h282.4v183.1h-282.4z" fill-rule="evenodd" fill="#fffcf8"/>
<g fill="none" stroke="#000" stroke-width=".21">
<path d="M2.2 8.4h5.1M7.3 13.5h282.4v183.1h-282.4zM75.3 8.4v5.1M148.5 8.4v5.1M221.6 8.4v5.1M289.7 8.4h5.1v5.1M2.2 56.7h5.1M289.7 56.7h5.1M2.2 105h5.1M289.7 105.1h5.1M2.2 153.4h5.1M289.7 153.4h5.1"/>
<path d="M289.7 176.3h-89.1v20.3M75.3 196.6v5.1M148.5 196.6v5.1M200.6 183.9h89.1M200.6 191.5h89.1M200.6 194.1h89.1M213.4 183.9v7.6M221.6 196.6v5.1M251.5 191.5v5.1M264.2 183.9v7.6M294.8 196.6v5.1"/>
</g>
<path d="M208.3 23.6h5.1M215.9 23.6h-2.5v25.5h2.5M88.7 107.6h-5.1v2.5M91.2 107.6h-2.5v2.5M91.2 105v2.6h2.6v2.5" fill="none" stroke="#f90" stroke-width="1.3"/>
<path d="M42.9 33.8h66.2M45.5 97.4h-2.6v2.6M111.6 82.1h7.6M111.6 89.8h7.6M131.9 117.8h-2.5v7.6M129.4 120.3h2.5M180.3 122.9h2.5v10.1M190.5 130.5v2.5M195.5 130.5v2.5M200.6 130.5v2.5" fill="none" stroke="#00be00" stroke-width="1.3"/>
<path d="M88.7 110.1v2M88.7 118.3v2M93.8 110.1v2M93.8 118.3v2" fill="none" stroke="#000" stroke-width=".25"/>
<path d="M87.6 112.2h2.1v6h-2.1zM92.7 112.2h2.1v6h-2.1z" fill="none" stroke="#00f" stroke-width=".25"/>
<path d="M90 102.5h2.5M91.2 102.5v2.5" fill="none" stroke="#800000" stroke-width=".25"/>
<path d="M53.1 121.6h14l1.2 1.3-1.2 1.2h-14z" fill-rule="evenodd" fill="#ffff80"/>
<path d="M53.1 121.6h14l1.2 1.3-1.2 1.2h-14z" fill="none" stroke="#800000" stroke-width=".21"/>
<circle cx="81.1" cy="127.9" r=".51" fill="#000080"/>
<circle cx="81.1" cy="127.9" r=".51" fill="none" stroke="#000080" stroke-width=".21"/>
<path d="M81.1 127.9v2.6" fill="none" stroke="#000" stroke-width=".25"/>
<circle cx="81.1" cy="127.9" r=".51" fill="#000080"/>
<circle cx="81.1" cy="127.9" r=".51" fill="none" stroke="#000080" stroke-width=".21"/>
<circle cx="81.1" cy="131.8" r="1.27" fill="none" stroke="#000" stroke-width=".25"/>
<path d="M139.6 61.8h33.1v63.6h-33.1z" fill-rule="evenodd" fill="#ffffb0"/>
<path d="M139.6 61.8h33.1v63.6h-33.1z" fill="none" stroke="#800000" stroke-width=".21"/>
<g fill="none" stroke="#000" stroke-width=".25">
<path d="M131.9 74.5h7.7M131.9 79.6h7.7M131.9 69.4h7.7M131.9 64.3h7.7M131.9 66.9h7.7M131.9 72h7.7M172.7 74.5h7.6M172.7 79.6h7.6M172.7 69.4h7.6M172.7 64.3h7.6M131.9 94.9h7.7M131.9 89.8h7.7"/>
<path d="M131.9 87.2h7.7M131.9 82.1h7.7M131.9 100h7.7M172.7 89.8h7.6M172.7 82.1h7.6M172.7 100h7.6M172.7 84.7h7.6M172.7 97.4h7.6M172.7 92.3h7.6M131.9 117.8h7.7M131.9 115.2h7.7M131.9 102.5h7.7"/>
<path d="M131.9 107.6h7.7M131.9 112.7h7.7M172.7 115.2h7.6M172.7 107.6h7.6M172.7 105.1h7.6M172.7 112.7h7.6M172.7 117.8h7.6M131.9 120.3h7.7M172.7 122.9h7.6"/>
</g>
<path d="M126.9 127.9h5M127.6 128.7h3.6M128.4 129.5h2M129.1 130.2h.6M129.4 125.4v2.5M180.3 135.6h5.1M181 136.3h3.6M181.8 137.1h2M182.6 137.9h.5M182.8 133v2.6" fill="none" stroke="#800000" stroke-width=".25"/>
<path d="M53.1 124.1h14l1.2 1.3-1.2 1.3h-14z" fill-rule="evenodd" fill="#ffff80"/>
<path d="M53.1 124.1h14l1.2 1.3-1.2 1.3h-14z" fill="none" stroke="#800000" stroke-width=".21"/>
<path d="M53.1 126.7h14l1.2 1.2-1.2 1.3h-14z" fill-rule="evenodd" fill="#ffff80"/>
<path d="M53.1 126.7h14l1.2 1.2-1.2 1.3h-14z" fill="none" stroke="#800000" stroke-width=".21"/>
<g fill="none" stroke="#000" stroke-width=".25">
<path d="M215.9 23.6h4.5M221.6 23.6h4.5M215.9 49.1h4.5M221.6 49.1h4.5M111.6 79.6h2.5M119.2 79.6h2.6M119.2 82.1h2.6M126.9 82.1h2.5M83.6 110.1v2M83.6 118.3v2M182.8 107.6h2M191 107.6h2"/>
<path d="M70.9 133v2.6M76 130.5v2.5M190.5 120.3v2M190.5 128.5v2M195.5 120.3v2M195.5 128.5v2M200.6 120.3v2M200.6 128.5v2"/>
<circle cx="70.9" cy="136.8" r="1.27"/>
<circle cx="76" cy="134.3" r="1.27"/>
</g>
<g fill="none" stroke="#00f" stroke-width=".25">
<path d="M221 22.4h1.3l-1.3 2.5h-1.3zM221 47.8h1.3l-1.3 2.6h-1.3zM114.1 79.6h2.1M116.2 77.6v4M117.2 79.6h2M117.2 77.6v4M121.8 82.1h2M123.8 80.1v4.1M124.8 82.1h2.1M124.8 80.1v4.1M82.6 112.2h2v6h-2zM184.9 106.6h6v2h-6z"/>
<path d="M189.5 122.4h2v6h-2zM194.6 122.4h2v6h-2zM199.7 122.4h2v6h-2z"/>
</g>
<path d="M130.9 98.9l2.1 2.1M130.9 93.9l2.1 2M133 98.9l-2.1 2.1M133 93.9l-2.1 2M179.3 98.9l2 2.1M179.3 96.4l2 2M181.3 98.9l-2 2.1M181.3 96.4l-2 2M130.9 101.5l2.1 2M133 101.5l-2.1 2M179.3 104l2 2.1M181.3 104l-2 2.1" fill="none" stroke="#f00" stroke-width=".21"/>
<g fill="none" stroke="#800000" stroke-width=".25">
<path d="M261.7 23.6h2.5M264.2 22.4v2.5M115.4 59.3h2.6M116.7 59.3v2.5M128.1 59.3h2.6M129.4 59.3v2.5M181.6 59.3h2.5M182.8 59.3v2.5M241.3 49.1h2.6M243.9 47.8v2.6M109.1 79.6v5.1M189.2 61.8h2.5"/>
<path d="M190.5 61.8v2.5M106.8 81.9v.5M107.5 81.1v2.1M108.3 80.4v3.5M109.1 82.1h2.5M187.9 135.6h15.3M188.7 136.3h3.5M189.4 137.1h2.1M190.2 137.9h.5M190.5 133v2.6M193.8 136.3h3.5M194.5 137.1h2.1"/>
<path d="M195.3 137.9h.5M195.5 133v2.6M198.9 136.3h3.5M199.6 137.1h2.1M200.4 137.9h.5M200.6 133v2.6"/>
</g>
<circle cx="236.3" cy="23.6" r=".51" fill="#000080"/>
<circle cx="236.3" cy="23.6" r=".51" fill="none" stroke="#000080" stroke-width=".21"/>
<path d="M236.3 23.6v2.6" fill="none" stroke="#000" stroke-width=".25"/>
<circle cx="236.3" cy="23.6" r=".51" fill="#000080"/>
<circle cx="236.3" cy="23.6" r=".51" fill="none" stroke="#000080" stroke-width=".21"/>
<path d="M236.3 31.3v2.5" fill="none" stroke="#000" stroke-width=".25"/>
<path d="M234.3 28.2h4M234.3 29.2h4M236.3 26.2v2M236.3 29.2v2.1" fill="none" stroke="#00f" stroke-width=".25"/>
<path d="M233.7 36.4h5.1M234.5 37.1h3.5M235.2 37.9h2.1M236 38.7h.5M236.3 33.8v2.6" fill="none" stroke="#800000" stroke-width=".25"/>
<circle cx="236.3" cy="49.1" r=".51" fill="#000080"/>
<circle cx="236.3" cy="49.1" r=".51" fill="none" stroke="#000080" stroke-width=".21"/>
<path d="M236.3 49.1v2.5" fill="none" stroke="#000" stroke-width=".25"/>
<circle cx="236.3" cy="49.1" r=".51" fill="#000080"/>
<circle cx="236.3" cy="49.1" r=".51" fill="none" stroke="#000080" stroke-width=".21"/>
<path d="M236.3 56.7v2.6" fill="none" stroke="#000" stroke-width=".25"/>
<path d="M234.3 53.7h4M234.3 54.7h4M236.3 51.6v2.1M236.3 54.7v2" fill="none" stroke="#00f" stroke-width=".25"/>
<path d="M41.6 21.1h2.6M42.9 21.1v2.5M236.3 59.3v2.5M233.7 61.8h5.1M234.5 62.6h3.5M235.2 63.3h2.1M236 64.1h.5" fill="none" stroke="#800000" stroke-width=".25"/>
<circle cx="48" cy="23.6" r=".51" fill="#000080"/>
<circle cx="48" cy="23.6" r=".51" fill="none" stroke="#000080" stroke-width=".21"/>
<circle cx="48" cy="33.8" r=".51" fill="#000080"/>
<circle cx="48" cy="33.8" r=".51" fill="none" stroke="#000080" stroke-width=".21"/>
<path d="M48 23.6v2.6" fill="none" stroke="#000" stroke-width=".25"/>
<circle cx="48" cy="23.6" r=".51" fill="#000080"/>
<circle cx="48" cy="23.6" r=".51" fill="none" stroke="#000080" stroke-width=".21"/>
<path d="M48 31.3v2.5" fill="none" stroke="#000" stroke-width=".25"/>
<circle cx="48" cy="33.8" r=".51" fill="#000080"/>
<circle cx="48" cy="33.8" r=".51" fill="none" stroke="#000080" stroke-width=".21"/>
<path d="M46 28.2h4M46 29.2h4M48 26.2v2M48 29.2v2.1" fill="none" stroke="#00f" stroke-width=".25"/>
<circle cx="58.2" cy="23.6" r=".51" fill="#000080"/>
<circle cx="58.2" cy="23.6" r=".51" fill="none" stroke="#000080" stroke-width=".21"/>
<circle cx="58.2" cy="33.8" r=".51" fill="#000080"/>
<circle cx="58.2" cy="33.8" r=".51" fill="none" stroke="#000080" stroke-width=".21"/>
<path d="M58.2 23.6v2.6" fill="none" stroke="#000" stroke-width=".25"/>
<circle cx="58.2" cy="23.6" r=".51" fill="#000080"/>
<circle cx="58.2" cy="23.6" r=".51" fill="none" stroke="#000080" stroke-width=".21"/>
<path d="M58.2 31.3v2.5" fill="none" stroke="#000" stroke-width=".25"/>
<circle cx="58.2" cy="33.8" r=".51" fill="#000080"/>
<circle cx="58.2" cy="33.8" r=".51" fill="none" stroke="#000080" stroke-width=".21"/>
<path d="M56.2 28.2h4M56.2 29.2h4M58.2 26.2v2M58.2 29.2v2.1" fill="none" stroke="#00f" stroke-width=".25"/>
<circle cx="68.3" cy="23.6" r=".51" fill="#000080"/>
<circle cx="68.3" cy="23.6" r=".51" fill="none" stroke="#000080" stroke-width=".21"/>
<circle cx="68.3" cy="33.8" r=".51" fill="#000080"/>
<circle cx="68.3" cy="33.8" r=".51" fill="none" stroke="#000080" stroke-width=".21"/>
<path d="M68.3 23.6v2.6" fill="none" stroke="#000" stroke-width=".25"/>
<circle cx="68.3" cy="23.6" r=".51" fill="#000080"/>
<circle cx="68.3" cy="23.6" r=".51" fill="none" stroke="#000080" stroke-width=".21"/>
<path d="M68.3 31.3v2.5" fill="none" stroke="#000" stroke-width=".25"/>
<circle cx="68.3" cy="33.8" r=".51" fill="#000080"/>
<circle cx="68.3" cy="33.8" r=".51" fill="none" stroke="#000080" stroke-width=".21"/>
<path d="M66.3 28.2h4.1M66.3 29.2h4.1M68.3 26.2v2M68.3 29.2v2.1" fill="none" stroke="#00f" stroke-width=".25"/>
<circle cx="78.5" cy="23.6" r=".51" fill="#000080"/>
<circle cx="78.5" cy="23.6" r=".51" fill="none" stroke="#000080" stroke-width=".21"/>
<circle cx="78.5" cy="33.8" r=".51" fill="#000080"/>
<circle cx="78.5" cy="33.8" r=".51" fill="none" stroke="#000080" stroke-width=".21"/>
<path d="M78.5 23.6v2.6" fill="none" stroke="#000" stroke-width=".25"/>
<circle cx="78.5" cy="23.6" r=".51" fill="#000080"/>
<circle cx="78.5" cy="23.6" r=".51" fill="none" stroke="#000080" stroke-width=".21"/>
<path d="M78.5 31.3v2.5" fill="none" stroke="#000" stroke-width=".25"/>
<circle cx="78.5" cy="33.8" r=".51" fill="#000080"/>
<circle cx="78.5" cy="33.8" r=".51" fill="none" stroke="#000080" stroke-width=".21"/>
<path d="M76.5 28.2h4M76.5 29.2h4M78.5 26.2v2M78.5 29.2v2.1M119.8 28.2h4M119.8 29.2h4M121.8 26.2v2M121.8 29.2v2.1" fill="none" stroke="#00f" stroke-width=".25"/>
<g fill="none" stroke="#800000" stroke-width=".25">
<path d="M40.4 36.4h5.1M41.1 37.1h3.6M41.9 37.9h2M42.7 38.6h.5M42.9 33.8v2.6M119.2 36.4h5.1M120 37.1h3.5M120.5 21.1h2.5M120.8 37.9h2M121.5 38.6h.5M121.8 21.1v2.5M121.8 33.8v2.6"/>
<path d="M196.8 64.3h2.6M198.1 64.3v2.6"/>
</g>
<path d="M121.8 23.6v2.6M121.8 31.3v2.5" fill="none" stroke="#000" stroke-width=".25"/>
<circle cx="98.9" cy="23.6" r=".51" fill="#000080"/>
<circle cx="98.9" cy="23.6" r=".51" fill="none" stroke="#000080" stroke-width=".21"/>
<circle cx="98.9" cy="33.8" r=".51" fill="#000080"/>
<circle cx="98.9" cy="33.8" r=".51" fill="none" stroke="#000080" stroke-width=".21"/>
<path d="M98.9 23.6v2.6" fill="none" stroke="#000" stroke-width=".25"/>
<circle cx="98.9" cy="23.6" r=".51" fill="#000080"/>
<circle cx="98.9" cy="23.6" r=".51" fill="none" stroke="#000080" stroke-width=".21"/>
<path d="M98.9 31.3v2.5" fill="none" stroke="#000" stroke-width=".25"/>
<circle cx="98.9" cy="33.8" r=".51" fill="#000080"/>
<circle cx="98.9" cy="33.8" r=".51" fill="none" stroke="#000080" stroke-width=".21"/>
<path d="M96.9 28.2h4M96.9 29.2h4M98.9 26.2v2M98.9 29.2v2.1" fill="none" stroke="#00f" stroke-width=".25"/>
<circle cx="88.7" cy="23.6" r=".51" fill="#000080"/>
<circle cx="88.7" cy="23.6" r=".51" fill="none" stroke="#000080" stroke-width=".21"/>
<circle cx="88.7" cy="33.8" r=".51" fill="#000080"/>
<circle cx="88.7" cy="33.8" r=".51" fill="none" stroke="#000080" stroke-width=".21"/>
<path d="M88.7 23.6v2.6" fill="none" stroke="#000" stroke-width=".25"/>
<circle cx="88.7" cy="23.6" r=".51" fill="#000080"/>
<circle cx="88.7" cy="23.6" r=".51" fill="none" stroke="#000080" stroke-width=".21"/>
<path d="M88.7 31.3v2.5" fill="none" stroke="#000" stroke-width=".25"/>
<circle cx="88.7" cy="33.8" r=".51" fill="#000080"/>
<circle cx="88.7" cy="33.8" r=".51" fill="none" stroke="#000080" stroke-width=".21"/>
<path d="M86.7 28.2h4M86.7 29.2h4M88.7 26.2v2M88.7 29.2v2.1" fill="none" stroke="#00f" stroke-width=".25"/>
<circle cx="246.4" cy="23.6" r=".51" fill="#000080"/>
<circle cx="246.4" cy="23.6" r=".51" fill="none" stroke="#000080" stroke-width=".21"/>
<path d="M246.4 23.6v2.6" fill="none" stroke="#000" stroke-width=".25"/>
<circle cx="246.4" cy="23.6" r=".51" fill="#000080"/>
<circle cx="246.4" cy="23.6" r=".51" fill="none" stroke="#000080" stroke-width=".21"/>
<path d="M246.4 31.3v2.5" fill="none" stroke="#000" stroke-width=".25"/>
<path d="M244.4 28.2h4M244.4 29.2h4M246.4 26.2v2M246.4 29.2v2.1" fill="none" stroke="#00f" stroke-width=".25"/>
<path d="M243.9 36.4h5.1M244.6 37.1h3.6M245.4 37.9h2M246.2 38.7h.5M246.4 33.8v2.6" fill="none" stroke="#800000" stroke-width=".25"/>
<path d="M53.1 84.7h20.3v15.3h-20.3z" fill-rule="evenodd" fill="#ffffb0"/>
<path d="M53.1 84.7h20.3v15.3h-20.3z" fill="none" stroke="#800000" stroke-width=".21"/>
<path d="M109.1 23.6v2.6M109.1 31.3v2.5M45.5 87.2h7.6M45.5 97.4h7.6M45.5 92.3h7.6M73.4 87.2h7.7M111.6 87.2h2.5M119.2 87.2h2.6M119.2 89.8h2.6M126.9 89.8h2.5" fill="none" stroke="#000" stroke-width=".25"/>
<path d="M41.6 82.1h2.6M42.9 82.1v2.6M42.9 100v2.5M106.8 89.5v.5M107.5 88.8v2M108.3 88v3.6M109.1 87.2v5.1M109.1 89.8h2.5M40.4 102.5h5.1M41.1 103.3h3.6M41.9 104h2M42.7 104.8h.5" fill="none" stroke="#800000" stroke-width=".25"/>
<path d="M107.1 28.2h4M107.1 29.2h4M109.1 26.2v2M109.1 29.2v2.1M114.1 87.2h2.1M116.2 85.2v4M117.2 87.2h2M117.2 85.2v4M121.8 89.8h2M123.8 87.8v4M124.8 89.8h2.1M124.8 87.8v4" fill="none" stroke="#00f" stroke-width=".25"/>
<path d="M205.7 91.1h16.6l1.2 1.2-1.2 1.3h-16.6z" fill-rule="evenodd" fill="#ffff80"/>
<path d="M205.7 91.1h16.6l1.2 1.2-1.2 1.3h-16.6z" fill="none" stroke="#800000" stroke-width=".21"/>
<path d="M205.7 88.5h16.6l1.2 1.3-1.2 1.3h-16.6z" fill-rule="evenodd" fill="#ffff80"/>
<path d="M205.7 88.5h16.6l1.2 1.3-1.2 1.3h-16.6z" fill="none" stroke="#800000" stroke-width=".21"/>
<path d="M205.7 22.4v2.5M205.7 23.6h2.6" fill="none" stroke="#800000" stroke-width=".25"/>
<circle cx="256.6" cy="23.6" r=".51" fill="#000080"/>
<circle cx="256.6" cy="23.6" r=".51" fill="none" stroke="#000080" stroke-width=".21"/>
<path d="M256.6 23.6v2.6" fill="none" stroke="#000" stroke-width=".25"/>
<circle cx="256.6" cy="23.6" r=".51" fill="#000080"/>
<circle cx="256.6" cy="23.6" r=".51" fill="none" stroke="#000080" stroke-width=".21"/>
<path d="M256.6 31.3v2.5" fill="none" stroke="#000" stroke-width=".25"/>
<path d="M254.6 28.2h4M254.6 29.2h4M256.6 26.2v2M256.6 29.2v2.1" fill="none" stroke="#00f" stroke-width=".25"/>
<path d="M254.1 36.4h5.1M254.8 37.1h3.6M255.6 37.9h2M256.3 38.7h.6M256.6 33.8v2.6" fill="none" stroke="#800000" stroke-width=".25"/>
<path d="M207 106.3h15.3l1.2 1.3-1.2 1.3h-15.3l-1.3-1.3z" fill-rule="evenodd" fill="#ffff80"/>
<path d="M207 106.3h15.3l1.2 1.3-1.2 1.3h-15.3l-1.3-1.3z" fill="none" stroke="#800000" stroke-width=".21"/>
<path d="M91.2 107.6h-2.5v2.5" fill="none" stroke="#000080" stroke-width=".25"/>
<circle cx="88.7" cy="107.6" r=".51" fill="#000080"/>
<circle cx="88.7" cy="107.6" r=".51" fill="none" stroke="#000080" stroke-width=".21"/>
<circle cx="91.2" cy="107.6" r=".51" fill="#000080"/>
<circle cx="91.2" cy="107.6" r=".51" fill="none" stroke="#000080" stroke-width=".21"/>
<path d="M91.2 105v2.6h2.6v2.5" fill="none" stroke="#000080" stroke-width=".25"/>
<circle cx="91.2" cy="107.6" r=".51" fill="#000080"/>
<circle cx="91.2" cy="107.6" r=".51" fill="none" stroke="#000080" stroke-width=".21"/>
<path d="M88.7 120.3v5.1" fill="none" stroke="#000080" stroke-width=".25"/>
<circle cx="88.7" cy="125.4" r=".51" fill="#000080"/>
<circle cx="88.7" cy="125.4" r=".51" fill="none" stroke="#000080" stroke-width=".21"/>
<path d="M180.3 89.8h25.4M180.3 92.3h25.4M131.9 117.8h-2.5v7.6" fill="none" stroke="#000080" stroke-width=".25"/>
<circle cx="129.4" cy="120.3" r=".51" fill="#000080"/>
<circle cx="129.4" cy="120.3" r=".51" fill="none" stroke="#000080" stroke-width=".21"/>
<path d="M129.4 120.3h2.5" fill="none" stroke="#000080" stroke-width=".25"/>
<circle cx="129.4" cy="120.3" r=".51" fill="#000080"/>
<circle cx="129.4" cy="120.3" r=".51" fill="none" stroke="#000080" stroke-width=".21"/>
<path d="M76 125.4v5.1" fill="none" stroke="#000080" stroke-width=".25"/>
<circle cx="76" cy="125.4" r=".51" fill="#000080"/>
<circle cx="76" cy="125.4" r=".51" fill="none" stroke="#000080" stroke-width=".21"/>
<path d="M93.8 120.3v7.6" fill="none" stroke="#000080" stroke-width=".25"/>
<circle cx="93.8" cy="127.9" r=".51" fill="#000080"/>
<circle cx="93.8" cy="127.9" r=".51" fill="none" stroke="#000080" stroke-width=".21"/>
<path d="M88.7 107.6h-5.1v2.5" fill="none" stroke="#000080" stroke-width=".25"/>
<circle cx="88.7" cy="107.6" r=".51" fill="#000080"/>
<circle cx="88.7" cy="107.6" r=".51" fill="none" stroke="#000080" stroke-width=".21"/>
<path d="M83.6 120.3v2.6" fill="none" stroke="#000080" stroke-width=".25"/>
<circle cx="83.6" cy="122.9" r=".51" fill="#000080"/>
<circle cx="83.6" cy="122.9" r=".51" fill="none" stroke="#000080" stroke-width=".21"/>
<path d="M70.9 122.9v10.1" fill="none" stroke="#000080" stroke-width=".25"/>
<circle cx="70.9" cy="122.9" r=".51" fill="#000080"/>
<circle cx="70.9" cy="122.9" r=".51" fill="none" stroke="#000080" stroke-width=".21"/>
<path d="M131.9 115.2h-25.4v12.7h-38.2" fill="none" stroke="#000080" stroke-width=".25"/>
<circle cx="81.1" cy="127.9" r=".51" fill="#000080"/>
<circle cx="81.1" cy="127.9" r=".51" fill="none" stroke="#000080" stroke-width=".21"/>
<circle cx="93.8" cy="127.9" r=".51" fill="#000080"/>
<circle cx="93.8" cy="127.9" r=".51" fill="none" stroke="#000080" stroke-width=".21"/>
<path d="M131.9 112.7h-27.9v12.7h-35.7" fill="none" stroke="#000080" stroke-width=".25"/>
<circle cx="76" cy="125.4" r=".51" fill="#000080"/>
<circle cx="76" cy="125.4" r=".51" fill="none" stroke="#000080" stroke-width=".21"/>
<circle cx="88.7" cy="125.4" r=".51" fill="#000080"/>
<circle cx="88.7" cy="125.4" r=".51" fill="none" stroke="#000080" stroke-width=".21"/>
<path d="M131.9 107.6h-30.5v15.3h-33.1" fill="none" stroke="#000080" stroke-width=".25"/>
<circle cx="70.9" cy="122.9" r=".51" fill="#000080"/>
<circle cx="70.9" cy="122.9" r=".51" fill="none" stroke="#000080" stroke-width=".21"/>
<circle cx="83.6" cy="122.9" r=".51" fill="#000080"/>
<circle cx="83.6" cy="122.9" r=".51" fill="none" stroke="#000080" stroke-width=".21"/>
<g fill="none" stroke="#000080" stroke-width=".25">
<path d="M96.3 79.6h15.3M121.8 79.6h10.1M129.4 61.8v10.2h2.5M111.6 82.1h7.6M129.4 82.1h2.5M180.3 117.8h10.2v2.5M180.3 115.2h15.2v5.1M180.3 112.7h20.3v7.6M180.3 107.6h2.5M180.3 122.9h2.5v10.1M190.5 130.5v2.5M195.5 130.5v2.5"/>
<path d="M200.6 130.5v2.5"/>
</g>
<circle cx="129.4" cy="69.4" r=".51" fill="#000080"/>
<circle cx="129.4" cy="69.4" r=".51" fill="none" stroke="#000080" stroke-width=".21"/>
<circle cx="129.4" cy="66.9" r=".51" fill="#000080"/>
<circle cx="129.4" cy="66.9" r=".51" fill="none" stroke="#000080" stroke-width=".21"/>
<circle cx="129.4" cy="64.3" r=".51" fill="#000080"/>
<circle cx="129.4" cy="64.3" r=".51" fill="none" stroke="#000080" stroke-width=".21"/>
<path d="M129.4 69.4h2.5" fill="none" stroke="#000080" stroke-width=".25"/>
<circle cx="129.4" cy="69.4" r=".51" fill="#000080"/>
<circle cx="129.4" cy="69.4" r=".51" fill="none" stroke="#000080" stroke-width=".21"/>
<path d="M129.4 66.9h2.5" fill="none" stroke="#000080" stroke-width=".25"/>
<circle cx="129.4" cy="66.9" r=".51" fill="#000080"/>
<circle cx="129.4" cy="66.9" r=".51" fill="none" stroke="#000080" stroke-width=".21"/>
<path d="M129.4 64.3h2.5" fill="none" stroke="#000080" stroke-width=".25"/>
<circle cx="129.4" cy="64.3" r=".51" fill="#000080"/>
<circle cx="129.4" cy="64.3" r=".51" fill="none" stroke="#000080" stroke-width=".21"/>
<path d="M226.1 23.6h35.6M116.7 61.8v12.7h15.2" fill="none" stroke="#000080" stroke-width=".25"/>
<circle cx="236.3" cy="23.6" r=".51" fill="#000080"/>
<circle cx="236.3" cy="23.6" r=".51" fill="none" stroke="#000080" stroke-width=".21"/>
<circle cx="246.4" cy="23.6" r=".51" fill="#000080"/>
<circle cx="246.4" cy="23.6" r=".51" fill="none" stroke="#000080" stroke-width=".21"/>
<circle cx="256.6" cy="23.6" r=".51" fill="#000080"/>
<circle cx="256.6" cy="23.6" r=".51" fill="none" stroke="#000080" stroke-width=".21"/>
<path d="M226.1 49.1h15.2" fill="none" stroke="#000080" stroke-width=".25"/>
<circle cx="236.3" cy="49.1" r=".51" fill="#000080"/>
<circle cx="236.3" cy="49.1" r=".51" fill="none" stroke="#000080" stroke-width=".21"/>
<path d="M182.8 64.3v5.1h-2.5" fill="none" stroke="#000080" stroke-width=".25"/>
<circle cx="182.8" cy="69.4" r=".51" fill="#000080"/>
<circle cx="182.8" cy="69.4" r=".51" fill="none" stroke="#000080" stroke-width=".21"/>
<circle cx="182.8" cy="64.3" r=".51" fill="#000080"/>
<circle cx="182.8" cy="64.3" r=".51" fill="none" stroke="#000080" stroke-width=".21"/>
<path d="M190.5 64.3v10.2h-10.2M182.8 82.1v2.6h-2.5" fill="none" stroke="#000080" stroke-width=".25"/>
<circle cx="182.8" cy="82.1" r=".51" fill="#000080"/>
<circle cx="182.8" cy="82.1" r=".51" fill="none" stroke="#000080" stroke-width=".21"/>
<path d="M182.8 61.8v2.5h-2.5" fill="none" stroke="#000080" stroke-width=".25"/>
<circle cx="182.8" cy="64.3" r=".51" fill="#000080"/>
<circle cx="182.8" cy="64.3" r=".51" fill="none" stroke="#000080" stroke-width=".21"/>
<path d="M42.9 84.7v2.5h2.6" fill="none" stroke="#000080" stroke-width=".25"/>
<circle cx="42.9" cy="87.2" r=".51" fill="#000080"/>
<circle cx="42.9" cy="87.2" r=".51" fill="none" stroke="#000080" stroke-width=".21"/>
<path d="M42.9 23.6h66.2M45.5 97.4h-2.6v2.6M81.1 87.2h30.5M111.6 89.8h7.6M121.8 87.2h10.1M129.4 89.8h2.5" fill="none" stroke="#000080" stroke-width=".25"/>
<circle cx="48" cy="23.6" r=".51" fill="#000080"/>
<circle cx="48" cy="23.6" r=".51" fill="none" stroke="#000080" stroke-width=".21"/>
<circle cx="58.2" cy="23.6" r=".51" fill="#000080"/>
<circle cx="58.2" cy="23.6" r=".51" fill="none" stroke="#000080" stroke-width=".21"/>
<circle cx="68.3" cy="23.6" r=".51" fill="#000080"/>
<circle cx="68.3" cy="23.6" r=".51" fill="none" stroke="#000080" stroke-width=".21"/>
<circle cx="78.5" cy="23.6" r=".51" fill="#000080"/>
<circle cx="78.5" cy="23.6" r=".51" fill="none" stroke="#000080" stroke-width=".21"/>
<circle cx="88.7" cy="23.6" r=".51" fill="#000080"/>
<circle cx="88.7" cy="23.6" r=".51" fill="none" stroke="#000080" stroke-width=".21"/>
<circle cx="98.9" cy="23.6" r=".51" fill="#000080"/>
<circle cx="98.9" cy="23.6" r=".51" fill="none" stroke="#000080" stroke-width=".21"/>
<path d="M42.9 33.8h66.2" fill="none" stroke="#000080" stroke-width=".25"/>
<circle cx="48" cy="33.8" r=".51" fill="#000080"/>
<circle cx="48" cy="33.8" r=".51" fill="none" stroke="#000080" stroke-width=".21"/>
<circle cx="58.2" cy="33.8" r=".51" fill="#000080"/>
<circle cx="58.2" cy="33.8" r=".51" fill="none" stroke="#000080" stroke-width=".21"/>
<circle cx="68.3" cy="33.8" r=".51" fill="#000080"/>
<circle cx="68.3" cy="33.8" r=".51" fill="none" stroke="#000080" stroke-width=".21"/>
<circle cx="78.5" cy="33.8" r=".51" fill="#000080"/>
<circle cx="78.5" cy="33.8" r=".51" fill="none" stroke="#000080" stroke-width=".21"/>
<circle cx="88.7" cy="33.8" r=".51" fill="#000080"/>
<circle cx="88.7" cy="33.8" r=".51" fill="none" stroke="#000080" stroke-width=".21"/>
<circle cx="98.9" cy="33.8" r=".51" fill="#000080"/>
<circle cx="98.9" cy="33.8" r=".51" fill="none" stroke="#000080" stroke-width=".21"/>
<path d="M42.9 87.2v5.1h2.6M193 107.6h12.7" fill="none" stroke="#000080" stroke-width=".25"/>
<circle cx="42.9" cy="87.2" r=".51" fill="#000080"/>
<circle cx="42.9" cy="87.2" r=".51" fill="none" stroke="#000080" stroke-width=".21"/>
<path d="M215.9 23.6h-2.5v25.5h2.5" fill="none" stroke="#000080" stroke-width=".25"/>
<circle cx="213.4" cy="23.6" r=".51" fill="#000080"/>
<circle cx="213.4" cy="23.6" r=".51" fill="none" stroke="#000080" stroke-width=".21"/>
<path d="M208.3 23.6h5.1" fill="none" stroke="#000080" stroke-width=".25"/>
<circle cx="213.4" cy="23.6" r=".51" fill="#000080"/>
<circle cx="213.4" cy="23.6" r=".51" fill="none" stroke="#000080" stroke-width=".21"/>
<path d="M198.1 66.9v15.2h-17.8" fill="none" stroke="#000080" stroke-width=".25"/>
<circle cx="182.8" cy="82.1" r=".51" fill="#000080"/>
<circle cx="182.8" cy="82.1" r=".51" fill="none" stroke="#000080" stroke-width=".21"/>
<path d="M182.8 69.4v10.2h-2.5" fill="none" stroke="#000080" stroke-width=".25"/>
<circle cx="182.8" cy="69.4" r=".51" fill="#000080"/>
<circle cx="182.8" cy="69.4" r=".51" fill="none" stroke="#000080" stroke-width=".21"/>
<use href="#words"/>
</svg>
